VERSION 5.8 ;
BUSBITCHARS "[]" ;
DIVIDERCHAR "/" ;
UNITS
    DATABASE MICRONS 1000 ;
END UNITS

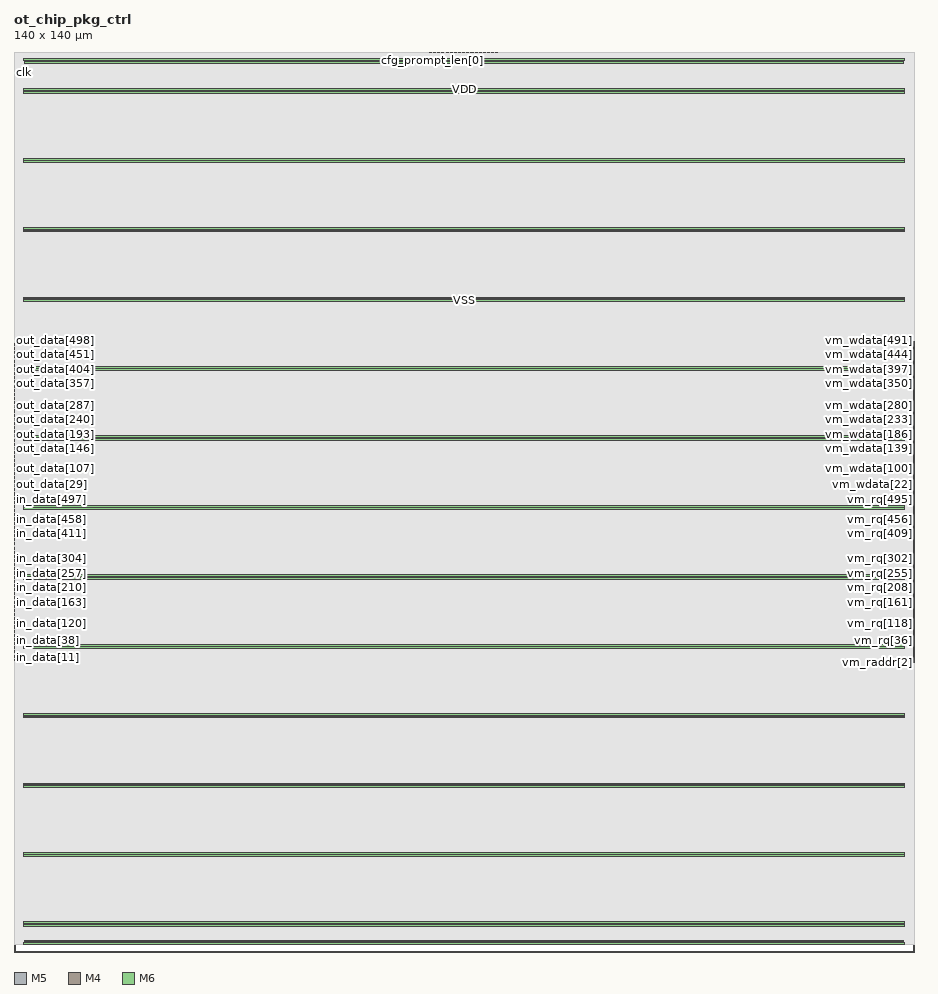
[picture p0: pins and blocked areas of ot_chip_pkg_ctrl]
MACRO ot_chip_pkg_ctrl
  FOREIGN ot_chip_pkg_ctrl 0 0 ;
  CLASS BLOCK ;
  SIZE 140 BY 140 ;
  PIN cfg_gen_len[0]
    DIRECTION INPUT ;
    USE SIGNAL ;
    PORT
      LAYER M5 ;
        RECT  64.272 139.916 64.296 140 ;
    END
  END cfg_gen_len[0]
  PIN cfg_gen_len[10]
    DIRECTION INPUT ;
    USE SIGNAL ;
    PORT
      LAYER M5 ;
        RECT  64.752 139.916 64.776 140 ;
    END
  END cfg_gen_len[10]
  PIN cfg_gen_len[11]
    DIRECTION INPUT ;
    USE SIGNAL ;
    PORT
      LAYER M5 ;
        RECT  64.8 139.916 64.824 140 ;
    END
  END cfg_gen_len[11]
  PIN cfg_gen_len[12]
    DIRECTION INPUT ;
    USE SIGNAL ;
    PORT
      LAYER M5 ;
        RECT  64.848 139.916 64.872 140 ;
    END
  END cfg_gen_len[12]
  PIN cfg_gen_len[13]
    DIRECTION INPUT ;
    USE SIGNAL ;
    PORT
      LAYER M5 ;
        RECT  64.896 139.916 64.92 140 ;
    END
  END cfg_gen_len[13]
  PIN cfg_gen_len[14]
    DIRECTION INPUT ;
    USE SIGNAL ;
    PORT
      LAYER M5 ;
        RECT  64.944 139.916 64.968 140 ;
    END
  END cfg_gen_len[14]
  PIN cfg_gen_len[15]
    DIRECTION INPUT ;
    USE SIGNAL ;
    PORT
      LAYER M5 ;
        RECT  64.992 139.916 65.016 140 ;
    END
  END cfg_gen_len[15]
  PIN cfg_gen_len[1]
    DIRECTION INPUT ;
    USE SIGNAL ;
    PORT
      LAYER M5 ;
        RECT  64.32 139.916 64.344 140 ;
    END
  END cfg_gen_len[1]
  PIN cfg_gen_len[2]
    DIRECTION INPUT ;
    USE SIGNAL ;
    PORT
      LAYER M5 ;
        RECT  64.368 139.916 64.392 140 ;
    END
  END cfg_gen_len[2]
  PIN cfg_gen_len[3]
    DIRECTION INPUT ;
    USE SIGNAL ;
    PORT
      LAYER M5 ;
        RECT  64.416 139.916 64.44 140 ;
    END
  END cfg_gen_len[3]
  PIN cfg_gen_len[4]
    DIRECTION INPUT ;
    USE SIGNAL ;
    PORT
      LAYER M5 ;
        RECT  64.464 139.916 64.488 140 ;
    END
  END cfg_gen_len[4]
  PIN cfg_gen_len[5]
    DIRECTION INPUT ;
    USE SIGNAL ;
    PORT
      LAYER M5 ;
        RECT  64.512 139.916 64.536 140 ;
    END
  END cfg_gen_len[5]
  PIN cfg_gen_len[6]
    DIRECTION INPUT ;
    USE SIGNAL ;
    PORT
      LAYER M5 ;
        RECT  64.56 139.916 64.584 140 ;
    END
  END cfg_gen_len[6]
  PIN cfg_gen_len[7]
    DIRECTION INPUT ;
    USE SIGNAL ;
    PORT
      LAYER M5 ;
        RECT  64.608 139.916 64.632 140 ;
    END
  END cfg_gen_len[7]
  PIN cfg_gen_len[8]
    DIRECTION INPUT ;
    USE SIGNAL ;
    PORT
      LAYER M5 ;
        RECT  64.656 139.916 64.68 140 ;
    END
  END cfg_gen_len[8]
  PIN cfg_gen_len[9]
    DIRECTION INPUT ;
    USE SIGNAL ;
    PORT
      LAYER M5 ;
        RECT  64.704 139.916 64.728 140 ;
    END
  END cfg_gen_len[9]
  PIN cfg_prompt_len[0]
    DIRECTION INPUT ;
    USE SIGNAL ;
    PORT
      LAYER M5 ;
        RECT  65.04 139.916 65.064 140 ;
    END
  END cfg_prompt_len[0]
  PIN cfg_prompt_len[10]
    DIRECTION INPUT ;
    USE SIGNAL ;
    PORT
      LAYER M5 ;
        RECT  65.52 139.916 65.544 140 ;
    END
  END cfg_prompt_len[10]
  PIN cfg_prompt_len[11]
    DIRECTION INPUT ;
    USE SIGNAL ;
    PORT
      LAYER M5 ;
        RECT  65.568 139.916 65.592 140 ;
    END
  END cfg_prompt_len[11]
  PIN cfg_prompt_len[12]
    DIRECTION INPUT ;
    USE SIGNAL ;
    PORT
      LAYER M5 ;
        RECT  65.616 139.916 65.64 140 ;
    END
  END cfg_prompt_len[12]
  PIN cfg_prompt_len[13]
    DIRECTION INPUT ;
    USE SIGNAL ;
    PORT
      LAYER M5 ;
        RECT  65.664 139.916 65.688 140 ;
    END
  END cfg_prompt_len[13]
  PIN cfg_prompt_len[14]
    DIRECTION INPUT ;
    USE SIGNAL ;
    PORT
      LAYER M5 ;
        RECT  65.712 139.916 65.736 140 ;
    END
  END cfg_prompt_len[14]
  PIN cfg_prompt_len[15]
    DIRECTION INPUT ;
    USE SIGNAL ;
    PORT
      LAYER M5 ;
        RECT  65.76 139.916 65.784 140 ;
    END
  END cfg_prompt_len[15]
  PIN cfg_prompt_len[1]
    DIRECTION INPUT ;
    USE SIGNAL ;
    PORT
      LAYER M5 ;
        RECT  65.088 139.916 65.112 140 ;
    END
  END cfg_prompt_len[1]
  PIN cfg_prompt_len[2]
    DIRECTION INPUT ;
    USE SIGNAL ;
    PORT
      LAYER M5 ;
        RECT  65.136 139.916 65.16 140 ;
    END
  END cfg_prompt_len[2]
  PIN cfg_prompt_len[3]
    DIRECTION INPUT ;
    USE SIGNAL ;
    PORT
      LAYER M5 ;
        RECT  65.184 139.916 65.208 140 ;
    END
  END cfg_prompt_len[3]
  PIN cfg_prompt_len[4]
    DIRECTION INPUT ;
    USE SIGNAL ;
    PORT
      LAYER M5 ;
        RECT  65.232 139.916 65.256 140 ;
    END
  END cfg_prompt_len[4]
  PIN cfg_prompt_len[5]
    DIRECTION INPUT ;
    USE SIGNAL ;
    PORT
      LAYER M5 ;
        RECT  65.28 139.916 65.304 140 ;
    END
  END cfg_prompt_len[5]
  PIN cfg_prompt_len[6]
    DIRECTION INPUT ;
    USE SIGNAL ;
    PORT
      LAYER M5 ;
        RECT  65.328 139.916 65.352 140 ;
    END
  END cfg_prompt_len[6]
  PIN cfg_prompt_len[7]
    DIRECTION INPUT ;
    USE SIGNAL ;
    PORT
      LAYER M5 ;
        RECT  65.376 139.916 65.4 140 ;
    END
  END cfg_prompt_len[7]
  PIN cfg_prompt_len[8]
    DIRECTION INPUT ;
    USE SIGNAL ;
    PORT
      LAYER M5 ;
        RECT  65.424 139.916 65.448 140 ;
    END
  END cfg_prompt_len[8]
  PIN cfg_prompt_len[9]
    DIRECTION INPUT ;
    USE SIGNAL ;
    PORT
      LAYER M5 ;
        RECT  65.472 139.916 65.496 140 ;
    END
  END cfg_prompt_len[9]
  PIN cfg_users[0]
    DIRECTION INPUT ;
    USE SIGNAL ;
    PORT
      LAYER M5 ;
        RECT  65.808 139.916 65.832 140 ;
    END
  END cfg_users[0]
  PIN cfg_users[1]
    DIRECTION INPUT ;
    USE SIGNAL ;
    PORT
      LAYER M5 ;
        RECT  65.856 139.916 65.88 140 ;
    END
  END cfg_users[1]
  PIN cfg_users[2]
    DIRECTION INPUT ;
    USE SIGNAL ;
    PORT
      LAYER M5 ;
        RECT  65.904 139.916 65.928 140 ;
    END
  END cfg_users[2]
  PIN cfg_users[3]
    DIRECTION INPUT ;
    USE SIGNAL ;
    PORT
      LAYER M5 ;
        RECT  65.952 139.916 65.976 140 ;
    END
  END cfg_users[3]
  PIN cfg_users[4]
    DIRECTION INPUT ;
    USE SIGNAL ;
    PORT
      LAYER M5 ;
        RECT  66 139.916 66.024 140 ;
    END
  END cfg_users[4]
  PIN cfg_users[5]
    DIRECTION INPUT ;
    USE SIGNAL ;
    PORT
      LAYER M5 ;
        RECT  66.048 139.916 66.072 140 ;
    END
  END cfg_users[5]
  PIN cfg_users[6]
    DIRECTION INPUT ;
    USE SIGNAL ;
    PORT
      LAYER M5 ;
        RECT  66.096 139.916 66.12 140 ;
    END
  END cfg_users[6]
  PIN cfg_users[7]
    DIRECTION INPUT ;
    USE SIGNAL ;
    PORT
      LAYER M5 ;
        RECT  66.144 139.916 66.168 140 ;
    END
  END cfg_users[7]
  PIN clk
    DIRECTION INPUT ;
    USE SIGNAL ;
    PORT
      LAYER M4 ;
        RECT  0 136.848 0.084 136.872 ;
    END
  END clk
  PIN core_busy
    DIRECTION OUTPUT ;
    USE SIGNAL ;
    PORT
      LAYER M5 ;
        RECT  66.192 139.916 66.216 140 ;
    END
  END core_busy
  PIN core_done
    DIRECTION INPUT ;
    USE SIGNAL ;
    PORT
      LAYER M5 ;
        RECT  66.24 139.916 66.264 140 ;
    END
  END core_done
  PIN core_next_token[0]
    DIRECTION INPUT ;
    USE SIGNAL ;
    PORT
      LAYER M5 ;
        RECT  66.288 139.916 66.312 140 ;
    END
  END core_next_token[0]
  PIN core_next_token[10]
    DIRECTION INPUT ;
    USE SIGNAL ;
    PORT
      LAYER M5 ;
        RECT  66.768 139.916 66.792 140 ;
    END
  END core_next_token[10]
  PIN core_next_token[11]
    DIRECTION INPUT ;
    USE SIGNAL ;
    PORT
      LAYER M5 ;
        RECT  66.816 139.916 66.84 140 ;
    END
  END core_next_token[11]
  PIN core_next_token[12]
    DIRECTION INPUT ;
    USE SIGNAL ;
    PORT
      LAYER M5 ;
        RECT  66.864 139.916 66.888 140 ;
    END
  END core_next_token[12]
  PIN core_next_token[13]
    DIRECTION INPUT ;
    USE SIGNAL ;
    PORT
      LAYER M5 ;
        RECT  66.912 139.916 66.936 140 ;
    END
  END core_next_token[13]
  PIN core_next_token[14]
    DIRECTION INPUT ;
    USE SIGNAL ;
    PORT
      LAYER M5 ;
        RECT  66.96 139.916 66.984 140 ;
    END
  END core_next_token[14]
  PIN core_next_token[15]
    DIRECTION INPUT ;
    USE SIGNAL ;
    PORT
      LAYER M5 ;
        RECT  67.008 139.916 67.032 140 ;
    END
  END core_next_token[15]
  PIN core_next_token[1]
    DIRECTION INPUT ;
    USE SIGNAL ;
    PORT
      LAYER M5 ;
        RECT  66.336 139.916 66.36 140 ;
    END
  END core_next_token[1]
  PIN core_next_token[2]
    DIRECTION INPUT ;
    USE SIGNAL ;
    PORT
      LAYER M5 ;
        RECT  66.384 139.916 66.408 140 ;
    END
  END core_next_token[2]
  PIN core_next_token[3]
    DIRECTION INPUT ;
    USE SIGNAL ;
    PORT
      LAYER M5 ;
        RECT  66.432 139.916 66.456 140 ;
    END
  END core_next_token[3]
  PIN core_next_token[4]
    DIRECTION INPUT ;
    USE SIGNAL ;
    PORT
      LAYER M5 ;
        RECT  66.48 139.916 66.504 140 ;
    END
  END core_next_token[4]
  PIN core_next_token[5]
    DIRECTION INPUT ;
    USE SIGNAL ;
    PORT
      LAYER M5 ;
        RECT  66.528 139.916 66.552 140 ;
    END
  END core_next_token[5]
  PIN core_next_token[6]
    DIRECTION INPUT ;
    USE SIGNAL ;
    PORT
      LAYER M5 ;
        RECT  66.576 139.916 66.6 140 ;
    END
  END core_next_token[6]
  PIN core_next_token[7]
    DIRECTION INPUT ;
    USE SIGNAL ;
    PORT
      LAYER M5 ;
        RECT  66.624 139.916 66.648 140 ;
    END
  END core_next_token[7]
  PIN core_next_token[8]
    DIRECTION INPUT ;
    USE SIGNAL ;
    PORT
      LAYER M5 ;
        RECT  66.672 139.916 66.696 140 ;
    END
  END core_next_token[8]
  PIN core_next_token[9]
    DIRECTION INPUT ;
    USE SIGNAL ;
    PORT
      LAYER M5 ;
        RECT  66.72 139.916 66.744 140 ;
    END
  END core_next_token[9]
  PIN core_next_val[0]
    DIRECTION INPUT ;
    USE SIGNAL ;
    PORT
      LAYER M5 ;
        RECT  67.056 139.916 67.08 140 ;
    END
  END core_next_val[0]
  PIN core_next_val[10]
    DIRECTION INPUT ;
    USE SIGNAL ;
    PORT
      LAYER M5 ;
        RECT  67.536 139.916 67.56 140 ;
    END
  END core_next_val[10]
  PIN core_next_val[11]
    DIRECTION INPUT ;
    USE SIGNAL ;
    PORT
      LAYER M5 ;
        RECT  67.584 139.916 67.608 140 ;
    END
  END core_next_val[11]
  PIN core_next_val[12]
    DIRECTION INPUT ;
    USE SIGNAL ;
    PORT
      LAYER M5 ;
        RECT  67.632 139.916 67.656 140 ;
    END
  END core_next_val[12]
  PIN core_next_val[13]
    DIRECTION INPUT ;
    USE SIGNAL ;
    PORT
      LAYER M5 ;
        RECT  67.68 139.916 67.704 140 ;
    END
  END core_next_val[13]
  PIN core_next_val[14]
    DIRECTION INPUT ;
    USE SIGNAL ;
    PORT
      LAYER M5 ;
        RECT  67.728 139.916 67.752 140 ;
    END
  END core_next_val[14]
  PIN core_next_val[15]
    DIRECTION INPUT ;
    USE SIGNAL ;
    PORT
      LAYER M5 ;
        RECT  67.776 139.916 67.8 140 ;
    END
  END core_next_val[15]
  PIN core_next_val[16]
    DIRECTION INPUT ;
    USE SIGNAL ;
    PORT
      LAYER M5 ;
        RECT  67.824 139.916 67.848 140 ;
    END
  END core_next_val[16]
  PIN core_next_val[17]
    DIRECTION INPUT ;
    USE SIGNAL ;
    PORT
      LAYER M5 ;
        RECT  67.872 139.916 67.896 140 ;
    END
  END core_next_val[17]
  PIN core_next_val[18]
    DIRECTION INPUT ;
    USE SIGNAL ;
    PORT
      LAYER M5 ;
        RECT  67.92 139.916 67.944 140 ;
    END
  END core_next_val[18]
  PIN core_next_val[19]
    DIRECTION INPUT ;
    USE SIGNAL ;
    PORT
      LAYER M5 ;
        RECT  67.968 139.916 67.992 140 ;
    END
  END core_next_val[19]
  PIN core_next_val[1]
    DIRECTION INPUT ;
    USE SIGNAL ;
    PORT
      LAYER M5 ;
        RECT  67.104 139.916 67.128 140 ;
    END
  END core_next_val[1]
  PIN core_next_val[20]
    DIRECTION INPUT ;
    USE SIGNAL ;
    PORT
      LAYER M5 ;
        RECT  68.016 139.916 68.04 140 ;
    END
  END core_next_val[20]
  PIN core_next_val[21]
    DIRECTION INPUT ;
    USE SIGNAL ;
    PORT
      LAYER M5 ;
        RECT  68.064 139.916 68.088 140 ;
    END
  END core_next_val[21]
  PIN core_next_val[22]
    DIRECTION INPUT ;
    USE SIGNAL ;
    PORT
      LAYER M5 ;
        RECT  68.112 139.916 68.136 140 ;
    END
  END core_next_val[22]
  PIN core_next_val[23]
    DIRECTION INPUT ;
    USE SIGNAL ;
    PORT
      LAYER M5 ;
        RECT  68.16 139.916 68.184 140 ;
    END
  END core_next_val[23]
  PIN core_next_val[24]
    DIRECTION INPUT ;
    USE SIGNAL ;
    PORT
      LAYER M5 ;
        RECT  68.208 139.916 68.232 140 ;
    END
  END core_next_val[24]
  PIN core_next_val[25]
    DIRECTION INPUT ;
    USE SIGNAL ;
    PORT
      LAYER M5 ;
        RECT  68.256 139.916 68.28 140 ;
    END
  END core_next_val[25]
  PIN core_next_val[26]
    DIRECTION INPUT ;
    USE SIGNAL ;
    PORT
      LAYER M5 ;
        RECT  68.304 139.916 68.328 140 ;
    END
  END core_next_val[26]
  PIN core_next_val[27]
    DIRECTION INPUT ;
    USE SIGNAL ;
    PORT
      LAYER M5 ;
        RECT  68.352 139.916 68.376 140 ;
    END
  END core_next_val[27]
  PIN core_next_val[28]
    DIRECTION INPUT ;
    USE SIGNAL ;
    PORT
      LAYER M5 ;
        RECT  68.4 139.916 68.424 140 ;
    END
  END core_next_val[28]
  PIN core_next_val[29]
    DIRECTION INPUT ;
    USE SIGNAL ;
    PORT
      LAYER M5 ;
        RECT  68.448 139.916 68.472 140 ;
    END
  END core_next_val[29]
  PIN core_next_val[2]
    DIRECTION INPUT ;
    USE SIGNAL ;
    PORT
      LAYER M5 ;
        RECT  67.152 139.916 67.176 140 ;
    END
  END core_next_val[2]
  PIN core_next_val[30]
    DIRECTION INPUT ;
    USE SIGNAL ;
    PORT
      LAYER M5 ;
        RECT  68.496 139.916 68.52 140 ;
    END
  END core_next_val[30]
  PIN core_next_val[31]
    DIRECTION INPUT ;
    USE SIGNAL ;
    PORT
      LAYER M5 ;
        RECT  68.544 139.916 68.568 140 ;
    END
  END core_next_val[31]
  PIN core_next_val[3]
    DIRECTION INPUT ;
    USE SIGNAL ;
    PORT
      LAYER M5 ;
        RECT  67.2 139.916 67.224 140 ;
    END
  END core_next_val[3]
  PIN core_next_val[4]
    DIRECTION INPUT ;
    USE SIGNAL ;
    PORT
      LAYER M5 ;
        RECT  67.248 139.916 67.272 140 ;
    END
  END core_next_val[4]
  PIN core_next_val[5]
    DIRECTION INPUT ;
    USE SIGNAL ;
    PORT
      LAYER M5 ;
        RECT  67.296 139.916 67.32 140 ;
    END
  END core_next_val[5]
  PIN core_next_val[6]
    DIRECTION INPUT ;
    USE SIGNAL ;
    PORT
      LAYER M5 ;
        RECT  67.344 139.916 67.368 140 ;
    END
  END core_next_val[6]
  PIN core_next_val[7]
    DIRECTION INPUT ;
    USE SIGNAL ;
    PORT
      LAYER M5 ;
        RECT  67.392 139.916 67.416 140 ;
    END
  END core_next_val[7]
  PIN core_next_val[8]
    DIRECTION INPUT ;
    USE SIGNAL ;
    PORT
      LAYER M5 ;
        RECT  67.44 139.916 67.464 140 ;
    END
  END core_next_val[8]
  PIN core_next_val[9]
    DIRECTION INPUT ;
    USE SIGNAL ;
    PORT
      LAYER M5 ;
        RECT  67.488 139.916 67.512 140 ;
    END
  END core_next_val[9]
  PIN core_pos[0]
    DIRECTION OUTPUT ;
    USE SIGNAL ;
    PORT
      LAYER M5 ;
        RECT  68.592 139.916 68.616 140 ;
    END
  END core_pos[0]
  PIN core_pos[10]
    DIRECTION OUTPUT ;
    USE SIGNAL ;
    PORT
      LAYER M5 ;
        RECT  69.072 139.916 69.096 140 ;
    END
  END core_pos[10]
  PIN core_pos[11]
    DIRECTION OUTPUT ;
    USE SIGNAL ;
    PORT
      LAYER M5 ;
        RECT  69.12 139.916 69.144 140 ;
    END
  END core_pos[11]
  PIN core_pos[12]
    DIRECTION OUTPUT ;
    USE SIGNAL ;
    PORT
      LAYER M5 ;
        RECT  69.168 139.916 69.192 140 ;
    END
  END core_pos[12]
  PIN core_pos[13]
    DIRECTION OUTPUT ;
    USE SIGNAL ;
    PORT
      LAYER M5 ;
        RECT  69.216 139.916 69.24 140 ;
    END
  END core_pos[13]
  PIN core_pos[14]
    DIRECTION OUTPUT ;
    USE SIGNAL ;
    PORT
      LAYER M5 ;
        RECT  69.264 139.916 69.288 140 ;
    END
  END core_pos[14]
  PIN core_pos[15]
    DIRECTION OUTPUT ;
    USE SIGNAL ;
    PORT
      LAYER M5 ;
        RECT  69.312 139.916 69.336 140 ;
    END
  END core_pos[15]
  PIN core_pos[1]
    DIRECTION OUTPUT ;
    USE SIGNAL ;
    PORT
      LAYER M5 ;
        RECT  68.64 139.916 68.664 140 ;
    END
  END core_pos[1]
  PIN core_pos[2]
    DIRECTION OUTPUT ;
    USE SIGNAL ;
    PORT
      LAYER M5 ;
        RECT  68.688 139.916 68.712 140 ;
    END
  END core_pos[2]
  PIN core_pos[3]
    DIRECTION OUTPUT ;
    USE SIGNAL ;
    PORT
      LAYER M5 ;
        RECT  68.736 139.916 68.76 140 ;
    END
  END core_pos[3]
  PIN core_pos[4]
    DIRECTION OUTPUT ;
    USE SIGNAL ;
    PORT
      LAYER M5 ;
        RECT  68.784 139.916 68.808 140 ;
    END
  END core_pos[4]
  PIN core_pos[5]
    DIRECTION OUTPUT ;
    USE SIGNAL ;
    PORT
      LAYER M5 ;
        RECT  68.832 139.916 68.856 140 ;
    END
  END core_pos[5]
  PIN core_pos[6]
    DIRECTION OUTPUT ;
    USE SIGNAL ;
    PORT
      LAYER M5 ;
        RECT  68.88 139.916 68.904 140 ;
    END
  END core_pos[6]
  PIN core_pos[7]
    DIRECTION OUTPUT ;
    USE SIGNAL ;
    PORT
      LAYER M5 ;
        RECT  68.928 139.916 68.952 140 ;
    END
  END core_pos[7]
  PIN core_pos[8]
    DIRECTION OUTPUT ;
    USE SIGNAL ;
    PORT
      LAYER M5 ;
        RECT  68.976 139.916 69 140 ;
    END
  END core_pos[8]
  PIN core_pos[9]
    DIRECTION OUTPUT ;
    USE SIGNAL ;
    PORT
      LAYER M5 ;
        RECT  69.024 139.916 69.048 140 ;
    END
  END core_pos[9]
  PIN core_start
    DIRECTION OUTPUT ;
    USE SIGNAL ;
    PORT
      LAYER M5 ;
        RECT  69.36 139.916 69.384 140 ;
    END
  END core_start
  PIN core_token[0]
    DIRECTION OUTPUT ;
    USE SIGNAL ;
    PORT
      LAYER M5 ;
        RECT  69.408 139.916 69.432 140 ;
    END
  END core_token[0]
  PIN core_token[10]
    DIRECTION OUTPUT ;
    USE SIGNAL ;
    PORT
      LAYER M5 ;
        RECT  69.888 139.916 69.912 140 ;
    END
  END core_token[10]
  PIN core_token[11]
    DIRECTION OUTPUT ;
    USE SIGNAL ;
    PORT
      LAYER M5 ;
        RECT  69.936 139.916 69.96 140 ;
    END
  END core_token[11]
  PIN core_token[12]
    DIRECTION OUTPUT ;
    USE SIGNAL ;
    PORT
      LAYER M5 ;
        RECT  69.984 139.916 70.008 140 ;
    END
  END core_token[12]
  PIN core_token[13]
    DIRECTION OUTPUT ;
    USE SIGNAL ;
    PORT
      LAYER M5 ;
        RECT  70.032 139.916 70.056 140 ;
    END
  END core_token[13]
  PIN core_token[14]
    DIRECTION OUTPUT ;
    USE SIGNAL ;
    PORT
      LAYER M5 ;
        RECT  70.08 139.916 70.104 140 ;
    END
  END core_token[14]
  PIN core_token[15]
    DIRECTION OUTPUT ;
    USE SIGNAL ;
    PORT
      LAYER M5 ;
        RECT  70.128 139.916 70.152 140 ;
    END
  END core_token[15]
  PIN core_token[1]
    DIRECTION OUTPUT ;
    USE SIGNAL ;
    PORT
      LAYER M5 ;
        RECT  69.456 139.916 69.48 140 ;
    END
  END core_token[1]
  PIN core_token[2]
    DIRECTION OUTPUT ;
    USE SIGNAL ;
    PORT
      LAYER M5 ;
        RECT  69.504 139.916 69.528 140 ;
    END
  END core_token[2]
  PIN core_token[3]
    DIRECTION OUTPUT ;
    USE SIGNAL ;
    PORT
      LAYER M5 ;
        RECT  69.552 139.916 69.576 140 ;
    END
  END core_token[3]
  PIN core_token[4]
    DIRECTION OUTPUT ;
    USE SIGNAL ;
    PORT
      LAYER M5 ;
        RECT  69.6 139.916 69.624 140 ;
    END
  END core_token[4]
  PIN core_token[5]
    DIRECTION OUTPUT ;
    USE SIGNAL ;
    PORT
      LAYER M5 ;
        RECT  69.648 139.916 69.672 140 ;
    END
  END core_token[5]
  PIN core_token[6]
    DIRECTION OUTPUT ;
    USE SIGNAL ;
    PORT
      LAYER M5 ;
        RECT  69.696 139.916 69.72 140 ;
    END
  END core_token[6]
  PIN core_token[7]
    DIRECTION OUTPUT ;
    USE SIGNAL ;
    PORT
      LAYER M5 ;
        RECT  69.744 139.916 69.768 140 ;
    END
  END core_token[7]
  PIN core_token[8]
    DIRECTION OUTPUT ;
    USE SIGNAL ;
    PORT
      LAYER M5 ;
        RECT  69.792 139.916 69.816 140 ;
    END
  END core_token[8]
  PIN core_token[9]
    DIRECTION OUTPUT ;
    USE SIGNAL ;
    PORT
      LAYER M5 ;
        RECT  69.84 139.916 69.864 140 ;
    END
  END core_token[9]
  PIN in_data[0]
    DIRECTION INPUT ;
    USE SIGNAL ;
    PORT
      LAYER M4 ;
        RECT  0 45.312 0.084 45.336 ;
    END
  END in_data[0]
  PIN in_data[100]
    DIRECTION INPUT ;
    USE SIGNAL ;
    PORT
      LAYER M4 ;
        RECT  0 50.112 0.084 50.136 ;
    END
  END in_data[100]
  PIN in_data[101]
    DIRECTION INPUT ;
    USE SIGNAL ;
    PORT
      LAYER M4 ;
        RECT  0 50.16 0.084 50.184 ;
    END
  END in_data[101]
  PIN in_data[102]
    DIRECTION INPUT ;
    USE SIGNAL ;
    PORT
      LAYER M4 ;
        RECT  0 50.208 0.084 50.232 ;
    END
  END in_data[102]
  PIN in_data[103]
    DIRECTION INPUT ;
    USE SIGNAL ;
    PORT
      LAYER M4 ;
        RECT  0 50.256 0.084 50.28 ;
    END
  END in_data[103]
  PIN in_data[104]
    DIRECTION INPUT ;
    USE SIGNAL ;
    PORT
      LAYER M4 ;
        RECT  0 50.304 0.084 50.328 ;
    END
  END in_data[104]
  PIN in_data[105]
    DIRECTION INPUT ;
    USE SIGNAL ;
    PORT
      LAYER M4 ;
        RECT  0 50.352 0.084 50.376 ;
    END
  END in_data[105]
  PIN in_data[106]
    DIRECTION INPUT ;
    USE SIGNAL ;
    PORT
      LAYER M4 ;
        RECT  0 50.4 0.084 50.424 ;
    END
  END in_data[106]
  PIN in_data[107]
    DIRECTION INPUT ;
    USE SIGNAL ;
    PORT
      LAYER M4 ;
        RECT  0 50.448 0.084 50.472 ;
    END
  END in_data[107]
  PIN in_data[108]
    DIRECTION INPUT ;
    USE SIGNAL ;
    PORT
      LAYER M4 ;
        RECT  0 50.496 0.084 50.52 ;
    END
  END in_data[108]
  PIN in_data[109]
    DIRECTION INPUT ;
    USE SIGNAL ;
    PORT
      LAYER M4 ;
        RECT  0 50.544 0.084 50.568 ;
    END
  END in_data[109]
  PIN in_data[10]
    DIRECTION INPUT ;
    USE SIGNAL ;
    PORT
      LAYER M4 ;
        RECT  0 45.792 0.084 45.816 ;
    END
  END in_data[10]
  PIN in_data[110]
    DIRECTION INPUT ;
    USE SIGNAL ;
    PORT
      LAYER M4 ;
        RECT  0 50.592 0.084 50.616 ;
    END
  END in_data[110]
  PIN in_data[111]
    DIRECTION INPUT ;
    USE SIGNAL ;
    PORT
      LAYER M4 ;
        RECT  0 50.64 0.084 50.664 ;
    END
  END in_data[111]
  PIN in_data[112]
    DIRECTION INPUT ;
    USE SIGNAL ;
    PORT
      LAYER M4 ;
        RECT  0 50.688 0.084 50.712 ;
    END
  END in_data[112]
  PIN in_data[113]
    DIRECTION INPUT ;
    USE SIGNAL ;
    PORT
      LAYER M4 ;
        RECT  0 50.736 0.084 50.76 ;
    END
  END in_data[113]
  PIN in_data[114]
    DIRECTION INPUT ;
    USE SIGNAL ;
    PORT
      LAYER M4 ;
        RECT  0 50.784 0.084 50.808 ;
    END
  END in_data[114]
  PIN in_data[115]
    DIRECTION INPUT ;
    USE SIGNAL ;
    PORT
      LAYER M4 ;
        RECT  0 50.832 0.084 50.856 ;
    END
  END in_data[115]
  PIN in_data[116]
    DIRECTION INPUT ;
    USE SIGNAL ;
    PORT
      LAYER M4 ;
        RECT  0 50.88 0.084 50.904 ;
    END
  END in_data[116]
  PIN in_data[117]
    DIRECTION INPUT ;
    USE SIGNAL ;
    PORT
      LAYER M4 ;
        RECT  0 50.928 0.084 50.952 ;
    END
  END in_data[117]
  PIN in_data[118]
    DIRECTION INPUT ;
    USE SIGNAL ;
    PORT
      LAYER M4 ;
        RECT  0 50.976 0.084 51 ;
    END
  END in_data[118]
  PIN in_data[119]
    DIRECTION INPUT ;
    USE SIGNAL ;
    PORT
      LAYER M4 ;
        RECT  0 51.024 0.084 51.048 ;
    END
  END in_data[119]
  PIN in_data[11]
    DIRECTION INPUT ;
    USE SIGNAL ;
    PORT
      LAYER M4 ;
        RECT  0 45.84 0.084 45.864 ;
    END
  END in_data[11]
  PIN in_data[120]
    DIRECTION INPUT ;
    USE SIGNAL ;
    PORT
      LAYER M4 ;
        RECT  0 51.072 0.084 51.096 ;
    END
  END in_data[120]
  PIN in_data[121]
    DIRECTION INPUT ;
    USE SIGNAL ;
    PORT
      LAYER M4 ;
        RECT  0 51.12 0.084 51.144 ;
    END
  END in_data[121]
  PIN in_data[122]
    DIRECTION INPUT ;
    USE SIGNAL ;
    PORT
      LAYER M4 ;
        RECT  0 51.168 0.084 51.192 ;
    END
  END in_data[122]
  PIN in_data[123]
    DIRECTION INPUT ;
    USE SIGNAL ;
    PORT
      LAYER M4 ;
        RECT  0 51.216 0.084 51.24 ;
    END
  END in_data[123]
  PIN in_data[124]
    DIRECTION INPUT ;
    USE SIGNAL ;
    PORT
      LAYER M4 ;
        RECT  0 51.264 0.084 51.288 ;
    END
  END in_data[124]
  PIN in_data[125]
    DIRECTION INPUT ;
    USE SIGNAL ;
    PORT
      LAYER M4 ;
        RECT  0 51.312 0.084 51.336 ;
    END
  END in_data[125]
  PIN in_data[126]
    DIRECTION INPUT ;
    USE SIGNAL ;
    PORT
      LAYER M4 ;
        RECT  0 51.36 0.084 51.384 ;
    END
  END in_data[126]
  PIN in_data[127]
    DIRECTION INPUT ;
    USE SIGNAL ;
    PORT
      LAYER M4 ;
        RECT  0 51.408 0.084 51.432 ;
    END
  END in_data[127]
  PIN in_data[128]
    DIRECTION INPUT ;
    USE SIGNAL ;
    PORT
      LAYER M4 ;
        RECT  0 51.456 0.084 51.48 ;
    END
  END in_data[128]
  PIN in_data[129]
    DIRECTION INPUT ;
    USE SIGNAL ;
    PORT
      LAYER M4 ;
        RECT  0 51.504 0.084 51.528 ;
    END
  END in_data[129]
  PIN in_data[12]
    DIRECTION INPUT ;
    USE SIGNAL ;
    PORT
      LAYER M4 ;
        RECT  0 45.888 0.084 45.912 ;
    END
  END in_data[12]
  PIN in_data[130]
    DIRECTION INPUT ;
    USE SIGNAL ;
    PORT
      LAYER M4 ;
        RECT  0 51.552 0.084 51.576 ;
    END
  END in_data[130]
  PIN in_data[131]
    DIRECTION INPUT ;
    USE SIGNAL ;
    PORT
      LAYER M4 ;
        RECT  0 51.6 0.084 51.624 ;
    END
  END in_data[131]
  PIN in_data[132]
    DIRECTION INPUT ;
    USE SIGNAL ;
    PORT
      LAYER M4 ;
        RECT  0 51.648 0.084 51.672 ;
    END
  END in_data[132]
  PIN in_data[133]
    DIRECTION INPUT ;
    USE SIGNAL ;
    PORT
      LAYER M4 ;
        RECT  0 51.696 0.084 51.72 ;
    END
  END in_data[133]
  PIN in_data[134]
    DIRECTION INPUT ;
    USE SIGNAL ;
    PORT
      LAYER M4 ;
        RECT  0 51.744 0.084 51.768 ;
    END
  END in_data[134]
  PIN in_data[135]
    DIRECTION INPUT ;
    USE SIGNAL ;
    PORT
      LAYER M4 ;
        RECT  0 51.792 0.084 51.816 ;
    END
  END in_data[135]
  PIN in_data[136]
    DIRECTION INPUT ;
    USE SIGNAL ;
    PORT
      LAYER M4 ;
        RECT  0 51.84 0.084 51.864 ;
    END
  END in_data[136]
  PIN in_data[137]
    DIRECTION INPUT ;
    USE SIGNAL ;
    PORT
      LAYER M4 ;
        RECT  0 51.888 0.084 51.912 ;
    END
  END in_data[137]
  PIN in_data[138]
    DIRECTION INPUT ;
    USE SIGNAL ;
    PORT
      LAYER M4 ;
        RECT  0 51.936 0.084 51.96 ;
    END
  END in_data[138]
  PIN in_data[139]
    DIRECTION INPUT ;
    USE SIGNAL ;
    PORT
      LAYER M4 ;
        RECT  0 51.984 0.084 52.008 ;
    END
  END in_data[139]
  PIN in_data[13]
    DIRECTION INPUT ;
    USE SIGNAL ;
    PORT
      LAYER M4 ;
        RECT  0 45.936 0.084 45.96 ;
    END
  END in_data[13]
  PIN in_data[140]
    DIRECTION INPUT ;
    USE SIGNAL ;
    PORT
      LAYER M4 ;
        RECT  0 52.032 0.084 52.056 ;
    END
  END in_data[140]
  PIN in_data[141]
    DIRECTION INPUT ;
    USE SIGNAL ;
    PORT
      LAYER M4 ;
        RECT  0 52.08 0.084 52.104 ;
    END
  END in_data[141]
  PIN in_data[142]
    DIRECTION INPUT ;
    USE SIGNAL ;
    PORT
      LAYER M4 ;
        RECT  0 52.128 0.084 52.152 ;
    END
  END in_data[142]
  PIN in_data[143]
    DIRECTION INPUT ;
    USE SIGNAL ;
    PORT
      LAYER M4 ;
        RECT  0 52.176 0.084 52.2 ;
    END
  END in_data[143]
  PIN in_data[144]
    DIRECTION INPUT ;
    USE SIGNAL ;
    PORT
      LAYER M4 ;
        RECT  0 52.224 0.084 52.248 ;
    END
  END in_data[144]
  PIN in_data[145]
    DIRECTION INPUT ;
    USE SIGNAL ;
    PORT
      LAYER M4 ;
        RECT  0 52.272 0.084 52.296 ;
    END
  END in_data[145]
  PIN in_data[146]
    DIRECTION INPUT ;
    USE SIGNAL ;
    PORT
      LAYER M4 ;
        RECT  0 52.32 0.084 52.344 ;
    END
  END in_data[146]
  PIN in_data[147]
    DIRECTION INPUT ;
    USE SIGNAL ;
    PORT
      LAYER M4 ;
        RECT  0 52.368 0.084 52.392 ;
    END
  END in_data[147]
  PIN in_data[148]
    DIRECTION INPUT ;
    USE SIGNAL ;
    PORT
      LAYER M4 ;
        RECT  0 52.416 0.084 52.44 ;
    END
  END in_data[148]
  PIN in_data[149]
    DIRECTION INPUT ;
    USE SIGNAL ;
    PORT
      LAYER M4 ;
        RECT  0 52.464 0.084 52.488 ;
    END
  END in_data[149]
  PIN in_data[14]
    DIRECTION INPUT ;
    USE SIGNAL ;
    PORT
      LAYER M4 ;
        RECT  0 45.984 0.084 46.008 ;
    END
  END in_data[14]
  PIN in_data[150]
    DIRECTION INPUT ;
    USE SIGNAL ;
    PORT
      LAYER M4 ;
        RECT  0 52.512 0.084 52.536 ;
    END
  END in_data[150]
  PIN in_data[151]
    DIRECTION INPUT ;
    USE SIGNAL ;
    PORT
      LAYER M4 ;
        RECT  0 52.56 0.084 52.584 ;
    END
  END in_data[151]
  PIN in_data[152]
    DIRECTION INPUT ;
    USE SIGNAL ;
    PORT
      LAYER M4 ;
        RECT  0 52.608 0.084 52.632 ;
    END
  END in_data[152]
  PIN in_data[153]
    DIRECTION INPUT ;
    USE SIGNAL ;
    PORT
      LAYER M4 ;
        RECT  0 52.656 0.084 52.68 ;
    END
  END in_data[153]
  PIN in_data[154]
    DIRECTION INPUT ;
    USE SIGNAL ;
    PORT
      LAYER M4 ;
        RECT  0 52.704 0.084 52.728 ;
    END
  END in_data[154]
  PIN in_data[155]
    DIRECTION INPUT ;
    USE SIGNAL ;
    PORT
      LAYER M4 ;
        RECT  0 52.752 0.084 52.776 ;
    END
  END in_data[155]
  PIN in_data[156]
    DIRECTION INPUT ;
    USE SIGNAL ;
    PORT
      LAYER M4 ;
        RECT  0 52.8 0.084 52.824 ;
    END
  END in_data[156]
  PIN in_data[157]
    DIRECTION INPUT ;
    USE SIGNAL ;
    PORT
      LAYER M4 ;
        RECT  0 52.848 0.084 52.872 ;
    END
  END in_data[157]
  PIN in_data[158]
    DIRECTION INPUT ;
    USE SIGNAL ;
    PORT
      LAYER M4 ;
        RECT  0 52.896 0.084 52.92 ;
    END
  END in_data[158]
  PIN in_data[159]
    DIRECTION INPUT ;
    USE SIGNAL ;
    PORT
      LAYER M4 ;
        RECT  0 52.944 0.084 52.968 ;
    END
  END in_data[159]
  PIN in_data[15]
    DIRECTION INPUT ;
    USE SIGNAL ;
    PORT
      LAYER M4 ;
        RECT  0 46.032 0.084 46.056 ;
    END
  END in_data[15]
  PIN in_data[160]
    DIRECTION INPUT ;
    USE SIGNAL ;
    PORT
      LAYER M4 ;
        RECT  0 52.992 0.084 53.016 ;
    END
  END in_data[160]
  PIN in_data[161]
    DIRECTION INPUT ;
    USE SIGNAL ;
    PORT
      LAYER M4 ;
        RECT  0 53.04 0.084 53.064 ;
    END
  END in_data[161]
  PIN in_data[162]
    DIRECTION INPUT ;
    USE SIGNAL ;
    PORT
      LAYER M4 ;
        RECT  0 53.088 0.084 53.112 ;
    END
  END in_data[162]
  PIN in_data[163]
    DIRECTION INPUT ;
    USE SIGNAL ;
    PORT
      LAYER M4 ;
        RECT  0 53.136 0.084 53.16 ;
    END
  END in_data[163]
  PIN in_data[164]
    DIRECTION INPUT ;
    USE SIGNAL ;
    PORT
      LAYER M4 ;
        RECT  0 53.184 0.084 53.208 ;
    END
  END in_data[164]
  PIN in_data[165]
    DIRECTION INPUT ;
    USE SIGNAL ;
    PORT
      LAYER M4 ;
        RECT  0 53.232 0.084 53.256 ;
    END
  END in_data[165]
  PIN in_data[166]
    DIRECTION INPUT ;
    USE SIGNAL ;
    PORT
      LAYER M4 ;
        RECT  0 53.28 0.084 53.304 ;
    END
  END in_data[166]
  PIN in_data[167]
    DIRECTION INPUT ;
    USE SIGNAL ;
    PORT
      LAYER M4 ;
        RECT  0 53.328 0.084 53.352 ;
    END
  END in_data[167]
  PIN in_data[168]
    DIRECTION INPUT ;
    USE SIGNAL ;
    PORT
      LAYER M4 ;
        RECT  0 53.376 0.084 53.4 ;
    END
  END in_data[168]
  PIN in_data[169]
    DIRECTION INPUT ;
    USE SIGNAL ;
    PORT
      LAYER M4 ;
        RECT  0 53.424 0.084 53.448 ;
    END
  END in_data[169]
  PIN in_data[16]
    DIRECTION INPUT ;
    USE SIGNAL ;
    PORT
      LAYER M4 ;
        RECT  0 46.08 0.084 46.104 ;
    END
  END in_data[16]
  PIN in_data[170]
    DIRECTION INPUT ;
    USE SIGNAL ;
    PORT
      LAYER M4 ;
        RECT  0 53.472 0.084 53.496 ;
    END
  END in_data[170]
  PIN in_data[171]
    DIRECTION INPUT ;
    USE SIGNAL ;
    PORT
      LAYER M4 ;
        RECT  0 53.52 0.084 53.544 ;
    END
  END in_data[171]
  PIN in_data[172]
    DIRECTION INPUT ;
    USE SIGNAL ;
    PORT
      LAYER M4 ;
        RECT  0 53.568 0.084 53.592 ;
    END
  END in_data[172]
  PIN in_data[173]
    DIRECTION INPUT ;
    USE SIGNAL ;
    PORT
      LAYER M4 ;
        RECT  0 53.616 0.084 53.64 ;
    END
  END in_data[173]
  PIN in_data[174]
    DIRECTION INPUT ;
    USE SIGNAL ;
    PORT
      LAYER M4 ;
        RECT  0 53.664 0.084 53.688 ;
    END
  END in_data[174]
  PIN in_data[175]
    DIRECTION INPUT ;
    USE SIGNAL ;
    PORT
      LAYER M4 ;
        RECT  0 53.712 0.084 53.736 ;
    END
  END in_data[175]
  PIN in_data[176]
    DIRECTION INPUT ;
    USE SIGNAL ;
    PORT
      LAYER M4 ;
        RECT  0 53.76 0.084 53.784 ;
    END
  END in_data[176]
  PIN in_data[177]
    DIRECTION INPUT ;
    USE SIGNAL ;
    PORT
      LAYER M4 ;
        RECT  0 53.808 0.084 53.832 ;
    END
  END in_data[177]
  PIN in_data[178]
    DIRECTION INPUT ;
    USE SIGNAL ;
    PORT
      LAYER M4 ;
        RECT  0 53.856 0.084 53.88 ;
    END
  END in_data[178]
  PIN in_data[179]
    DIRECTION INPUT ;
    USE SIGNAL ;
    PORT
      LAYER M4 ;
        RECT  0 53.904 0.084 53.928 ;
    END
  END in_data[179]
  PIN in_data[17]
    DIRECTION INPUT ;
    USE SIGNAL ;
    PORT
      LAYER M4 ;
        RECT  0 46.128 0.084 46.152 ;
    END
  END in_data[17]
  PIN in_data[180]
    DIRECTION INPUT ;
    USE SIGNAL ;
    PORT
      LAYER M4 ;
        RECT  0 53.952 0.084 53.976 ;
    END
  END in_data[180]
  PIN in_data[181]
    DIRECTION INPUT ;
    USE SIGNAL ;
    PORT
      LAYER M4 ;
        RECT  0 54 0.084 54.024 ;
    END
  END in_data[181]
  PIN in_data[182]
    DIRECTION INPUT ;
    USE SIGNAL ;
    PORT
      LAYER M4 ;
        RECT  0 54.048 0.084 54.072 ;
    END
  END in_data[182]
  PIN in_data[183]
    DIRECTION INPUT ;
    USE SIGNAL ;
    PORT
      LAYER M4 ;
        RECT  0 54.096 0.084 54.12 ;
    END
  END in_data[183]
  PIN in_data[184]
    DIRECTION INPUT ;
    USE SIGNAL ;
    PORT
      LAYER M4 ;
        RECT  0 54.144 0.084 54.168 ;
    END
  END in_data[184]
  PIN in_data[185]
    DIRECTION INPUT ;
    USE SIGNAL ;
    PORT
      LAYER M4 ;
        RECT  0 54.192 0.084 54.216 ;
    END
  END in_data[185]
  PIN in_data[186]
    DIRECTION INPUT ;
    USE SIGNAL ;
    PORT
      LAYER M4 ;
        RECT  0 54.24 0.084 54.264 ;
    END
  END in_data[186]
  PIN in_data[187]
    DIRECTION INPUT ;
    USE SIGNAL ;
    PORT
      LAYER M4 ;
        RECT  0 54.288 0.084 54.312 ;
    END
  END in_data[187]
  PIN in_data[188]
    DIRECTION INPUT ;
    USE SIGNAL ;
    PORT
      LAYER M4 ;
        RECT  0 54.336 0.084 54.36 ;
    END
  END in_data[188]
  PIN in_data[189]
    DIRECTION INPUT ;
    USE SIGNAL ;
    PORT
      LAYER M4 ;
        RECT  0 54.384 0.084 54.408 ;
    END
  END in_data[189]
  PIN in_data[18]
    DIRECTION INPUT ;
    USE SIGNAL ;
    PORT
      LAYER M4 ;
        RECT  0 46.176 0.084 46.2 ;
    END
  END in_data[18]
  PIN in_data[190]
    DIRECTION INPUT ;
    USE SIGNAL ;
    PORT
      LAYER M4 ;
        RECT  0 54.432 0.084 54.456 ;
    END
  END in_data[190]
  PIN in_data[191]
    DIRECTION INPUT ;
    USE SIGNAL ;
    PORT
      LAYER M4 ;
        RECT  0 54.48 0.084 54.504 ;
    END
  END in_data[191]
  PIN in_data[192]
    DIRECTION INPUT ;
    USE SIGNAL ;
    PORT
      LAYER M4 ;
        RECT  0 54.528 0.084 54.552 ;
    END
  END in_data[192]
  PIN in_data[193]
    DIRECTION INPUT ;
    USE SIGNAL ;
    PORT
      LAYER M4 ;
        RECT  0 54.576 0.084 54.6 ;
    END
  END in_data[193]
  PIN in_data[194]
    DIRECTION INPUT ;
    USE SIGNAL ;
    PORT
      LAYER M4 ;
        RECT  0 54.624 0.084 54.648 ;
    END
  END in_data[194]
  PIN in_data[195]
    DIRECTION INPUT ;
    USE SIGNAL ;
    PORT
      LAYER M4 ;
        RECT  0 54.672 0.084 54.696 ;
    END
  END in_data[195]
  PIN in_data[196]
    DIRECTION INPUT ;
    USE SIGNAL ;
    PORT
      LAYER M4 ;
        RECT  0 54.72 0.084 54.744 ;
    END
  END in_data[196]
  PIN in_data[197]
    DIRECTION INPUT ;
    USE SIGNAL ;
    PORT
      LAYER M4 ;
        RECT  0 54.768 0.084 54.792 ;
    END
  END in_data[197]
  PIN in_data[198]
    DIRECTION INPUT ;
    USE SIGNAL ;
    PORT
      LAYER M4 ;
        RECT  0 54.816 0.084 54.84 ;
    END
  END in_data[198]
  PIN in_data[199]
    DIRECTION INPUT ;
    USE SIGNAL ;
    PORT
      LAYER M4 ;
        RECT  0 54.864 0.084 54.888 ;
    END
  END in_data[199]
  PIN in_data[19]
    DIRECTION INPUT ;
    USE SIGNAL ;
    PORT
      LAYER M4 ;
        RECT  0 46.224 0.084 46.248 ;
    END
  END in_data[19]
  PIN in_data[1]
    DIRECTION INPUT ;
    USE SIGNAL ;
    PORT
      LAYER M4 ;
        RECT  0 45.36 0.084 45.384 ;
    END
  END in_data[1]
  PIN in_data[200]
    DIRECTION INPUT ;
    USE SIGNAL ;
    PORT
      LAYER M4 ;
        RECT  0 54.912 0.084 54.936 ;
    END
  END in_data[200]
  PIN in_data[201]
    DIRECTION INPUT ;
    USE SIGNAL ;
    PORT
      LAYER M4 ;
        RECT  0 54.96 0.084 54.984 ;
    END
  END in_data[201]
  PIN in_data[202]
    DIRECTION INPUT ;
    USE SIGNAL ;
    PORT
      LAYER M4 ;
        RECT  0 55.008 0.084 55.032 ;
    END
  END in_data[202]
  PIN in_data[203]
    DIRECTION INPUT ;
    USE SIGNAL ;
    PORT
      LAYER M4 ;
        RECT  0 55.056 0.084 55.08 ;
    END
  END in_data[203]
  PIN in_data[204]
    DIRECTION INPUT ;
    USE SIGNAL ;
    PORT
      LAYER M4 ;
        RECT  0 55.104 0.084 55.128 ;
    END
  END in_data[204]
  PIN in_data[205]
    DIRECTION INPUT ;
    USE SIGNAL ;
    PORT
      LAYER M4 ;
        RECT  0 55.152 0.084 55.176 ;
    END
  END in_data[205]
  PIN in_data[206]
    DIRECTION INPUT ;
    USE SIGNAL ;
    PORT
      LAYER M4 ;
        RECT  0 55.2 0.084 55.224 ;
    END
  END in_data[206]
  PIN in_data[207]
    DIRECTION INPUT ;
    USE SIGNAL ;
    PORT
      LAYER M4 ;
        RECT  0 55.248 0.084 55.272 ;
    END
  END in_data[207]
  PIN in_data[208]
    DIRECTION INPUT ;
    USE SIGNAL ;
    PORT
      LAYER M4 ;
        RECT  0 55.296 0.084 55.32 ;
    END
  END in_data[208]
  PIN in_data[209]
    DIRECTION INPUT ;
    USE SIGNAL ;
    PORT
      LAYER M4 ;
        RECT  0 55.344 0.084 55.368 ;
    END
  END in_data[209]
  PIN in_data[20]
    DIRECTION INPUT ;
    USE SIGNAL ;
    PORT
      LAYER M4 ;
        RECT  0 46.272 0.084 46.296 ;
    END
  END in_data[20]
  PIN in_data[210]
    DIRECTION INPUT ;
    USE SIGNAL ;
    PORT
      LAYER M4 ;
        RECT  0 55.392 0.084 55.416 ;
    END
  END in_data[210]
  PIN in_data[211]
    DIRECTION INPUT ;
    USE SIGNAL ;
    PORT
      LAYER M4 ;
        RECT  0 55.44 0.084 55.464 ;
    END
  END in_data[211]
  PIN in_data[212]
    DIRECTION INPUT ;
    USE SIGNAL ;
    PORT
      LAYER M4 ;
        RECT  0 55.488 0.084 55.512 ;
    END
  END in_data[212]
  PIN in_data[213]
    DIRECTION INPUT ;
    USE SIGNAL ;
    PORT
      LAYER M4 ;
        RECT  0 55.536 0.084 55.56 ;
    END
  END in_data[213]
  PIN in_data[214]
    DIRECTION INPUT ;
    USE SIGNAL ;
    PORT
      LAYER M4 ;
        RECT  0 55.584 0.084 55.608 ;
    END
  END in_data[214]
  PIN in_data[215]
    DIRECTION INPUT ;
    USE SIGNAL ;
    PORT
      LAYER M4 ;
        RECT  0 55.632 0.084 55.656 ;
    END
  END in_data[215]
  PIN in_data[216]
    DIRECTION INPUT ;
    USE SIGNAL ;
    PORT
      LAYER M4 ;
        RECT  0 55.68 0.084 55.704 ;
    END
  END in_data[216]
  PIN in_data[217]
    DIRECTION INPUT ;
    USE SIGNAL ;
    PORT
      LAYER M4 ;
        RECT  0 55.728 0.084 55.752 ;
    END
  END in_data[217]
  PIN in_data[218]
    DIRECTION INPUT ;
    USE SIGNAL ;
    PORT
      LAYER M4 ;
        RECT  0 55.776 0.084 55.8 ;
    END
  END in_data[218]
  PIN in_data[219]
    DIRECTION INPUT ;
    USE SIGNAL ;
    PORT
      LAYER M4 ;
        RECT  0 55.824 0.084 55.848 ;
    END
  END in_data[219]
  PIN in_data[21]
    DIRECTION INPUT ;
    USE SIGNAL ;
    PORT
      LAYER M4 ;
        RECT  0 46.32 0.084 46.344 ;
    END
  END in_data[21]
  PIN in_data[220]
    DIRECTION INPUT ;
    USE SIGNAL ;
    PORT
      LAYER M4 ;
        RECT  0 55.872 0.084 55.896 ;
    END
  END in_data[220]
  PIN in_data[221]
    DIRECTION INPUT ;
    USE SIGNAL ;
    PORT
      LAYER M4 ;
        RECT  0 55.92 0.084 55.944 ;
    END
  END in_data[221]
  PIN in_data[222]
    DIRECTION INPUT ;
    USE SIGNAL ;
    PORT
      LAYER M4 ;
        RECT  0 55.968 0.084 55.992 ;
    END
  END in_data[222]
  PIN in_data[223]
    DIRECTION INPUT ;
    USE SIGNAL ;
    PORT
      LAYER M4 ;
        RECT  0 56.016 0.084 56.04 ;
    END
  END in_data[223]
  PIN in_data[224]
    DIRECTION INPUT ;
    USE SIGNAL ;
    PORT
      LAYER M4 ;
        RECT  0 56.064 0.084 56.088 ;
    END
  END in_data[224]
  PIN in_data[225]
    DIRECTION INPUT ;
    USE SIGNAL ;
    PORT
      LAYER M4 ;
        RECT  0 56.112 0.084 56.136 ;
    END
  END in_data[225]
  PIN in_data[226]
    DIRECTION INPUT ;
    USE SIGNAL ;
    PORT
      LAYER M4 ;
        RECT  0 56.16 0.084 56.184 ;
    END
  END in_data[226]
  PIN in_data[227]
    DIRECTION INPUT ;
    USE SIGNAL ;
    PORT
      LAYER M4 ;
        RECT  0 56.208 0.084 56.232 ;
    END
  END in_data[227]
  PIN in_data[228]
    DIRECTION INPUT ;
    USE SIGNAL ;
    PORT
      LAYER M4 ;
        RECT  0 56.256 0.084 56.28 ;
    END
  END in_data[228]
  PIN in_data[229]
    DIRECTION INPUT ;
    USE SIGNAL ;
    PORT
      LAYER M4 ;
        RECT  0 56.304 0.084 56.328 ;
    END
  END in_data[229]
  PIN in_data[22]
    DIRECTION INPUT ;
    USE SIGNAL ;
    PORT
      LAYER M4 ;
        RECT  0 46.368 0.084 46.392 ;
    END
  END in_data[22]
  PIN in_data[230]
    DIRECTION INPUT ;
    USE SIGNAL ;
    PORT
      LAYER M4 ;
        RECT  0 56.352 0.084 56.376 ;
    END
  END in_data[230]
  PIN in_data[231]
    DIRECTION INPUT ;
    USE SIGNAL ;
    PORT
      LAYER M4 ;
        RECT  0 56.4 0.084 56.424 ;
    END
  END in_data[231]
  PIN in_data[232]
    DIRECTION INPUT ;
    USE SIGNAL ;
    PORT
      LAYER M4 ;
        RECT  0 56.448 0.084 56.472 ;
    END
  END in_data[232]
  PIN in_data[233]
    DIRECTION INPUT ;
    USE SIGNAL ;
    PORT
      LAYER M4 ;
        RECT  0 56.496 0.084 56.52 ;
    END
  END in_data[233]
  PIN in_data[234]
    DIRECTION INPUT ;
    USE SIGNAL ;
    PORT
      LAYER M4 ;
        RECT  0 56.544 0.084 56.568 ;
    END
  END in_data[234]
  PIN in_data[235]
    DIRECTION INPUT ;
    USE SIGNAL ;
    PORT
      LAYER M4 ;
        RECT  0 56.592 0.084 56.616 ;
    END
  END in_data[235]
  PIN in_data[236]
    DIRECTION INPUT ;
    USE SIGNAL ;
    PORT
      LAYER M4 ;
        RECT  0 56.64 0.084 56.664 ;
    END
  END in_data[236]
  PIN in_data[237]
    DIRECTION INPUT ;
    USE SIGNAL ;
    PORT
      LAYER M4 ;
        RECT  0 56.688 0.084 56.712 ;
    END
  END in_data[237]
  PIN in_data[238]
    DIRECTION INPUT ;
    USE SIGNAL ;
    PORT
      LAYER M4 ;
        RECT  0 56.736 0.084 56.76 ;
    END
  END in_data[238]
  PIN in_data[239]
    DIRECTION INPUT ;
    USE SIGNAL ;
    PORT
      LAYER M4 ;
        RECT  0 56.784 0.084 56.808 ;
    END
  END in_data[239]
  PIN in_data[23]
    DIRECTION INPUT ;
    USE SIGNAL ;
    PORT
      LAYER M4 ;
        RECT  0 46.416 0.084 46.44 ;
    END
  END in_data[23]
  PIN in_data[240]
    DIRECTION INPUT ;
    USE SIGNAL ;
    PORT
      LAYER M4 ;
        RECT  0 56.832 0.084 56.856 ;
    END
  END in_data[240]
  PIN in_data[241]
    DIRECTION INPUT ;
    USE SIGNAL ;
    PORT
      LAYER M4 ;
        RECT  0 56.88 0.084 56.904 ;
    END
  END in_data[241]
  PIN in_data[242]
    DIRECTION INPUT ;
    USE SIGNAL ;
    PORT
      LAYER M4 ;
        RECT  0 56.928 0.084 56.952 ;
    END
  END in_data[242]
  PIN in_data[243]
    DIRECTION INPUT ;
    USE SIGNAL ;
    PORT
      LAYER M4 ;
        RECT  0 56.976 0.084 57 ;
    END
  END in_data[243]
  PIN in_data[244]
    DIRECTION INPUT ;
    USE SIGNAL ;
    PORT
      LAYER M4 ;
        RECT  0 57.024 0.084 57.048 ;
    END
  END in_data[244]
  PIN in_data[245]
    DIRECTION INPUT ;
    USE SIGNAL ;
    PORT
      LAYER M4 ;
        RECT  0 57.072 0.084 57.096 ;
    END
  END in_data[245]
  PIN in_data[246]
    DIRECTION INPUT ;
    USE SIGNAL ;
    PORT
      LAYER M4 ;
        RECT  0 57.12 0.084 57.144 ;
    END
  END in_data[246]
  PIN in_data[247]
    DIRECTION INPUT ;
    USE SIGNAL ;
    PORT
      LAYER M4 ;
        RECT  0 57.168 0.084 57.192 ;
    END
  END in_data[247]
  PIN in_data[248]
    DIRECTION INPUT ;
    USE SIGNAL ;
    PORT
      LAYER M4 ;
        RECT  0 57.216 0.084 57.24 ;
    END
  END in_data[248]
  PIN in_data[249]
    DIRECTION INPUT ;
    USE SIGNAL ;
    PORT
      LAYER M4 ;
        RECT  0 57.264 0.084 57.288 ;
    END
  END in_data[249]
  PIN in_data[24]
    DIRECTION INPUT ;
    USE SIGNAL ;
    PORT
      LAYER M4 ;
        RECT  0 46.464 0.084 46.488 ;
    END
  END in_data[24]
  PIN in_data[250]
    DIRECTION INPUT ;
    USE SIGNAL ;
    PORT
      LAYER M4 ;
        RECT  0 57.312 0.084 57.336 ;
    END
  END in_data[250]
  PIN in_data[251]
    DIRECTION INPUT ;
    USE SIGNAL ;
    PORT
      LAYER M4 ;
        RECT  0 57.36 0.084 57.384 ;
    END
  END in_data[251]
  PIN in_data[252]
    DIRECTION INPUT ;
    USE SIGNAL ;
    PORT
      LAYER M4 ;
        RECT  0 57.408 0.084 57.432 ;
    END
  END in_data[252]
  PIN in_data[253]
    DIRECTION INPUT ;
    USE SIGNAL ;
    PORT
      LAYER M4 ;
        RECT  0 57.456 0.084 57.48 ;
    END
  END in_data[253]
  PIN in_data[254]
    DIRECTION INPUT ;
    USE SIGNAL ;
    PORT
      LAYER M4 ;
        RECT  0 57.504 0.084 57.528 ;
    END
  END in_data[254]
  PIN in_data[255]
    DIRECTION INPUT ;
    USE SIGNAL ;
    PORT
      LAYER M4 ;
        RECT  0 57.552 0.084 57.576 ;
    END
  END in_data[255]
  PIN in_data[256]
    DIRECTION INPUT ;
    USE SIGNAL ;
    PORT
      LAYER M4 ;
        RECT  0 57.6 0.084 57.624 ;
    END
  END in_data[256]
  PIN in_data[257]
    DIRECTION INPUT ;
    USE SIGNAL ;
    PORT
      LAYER M4 ;
        RECT  0 57.648 0.084 57.672 ;
    END
  END in_data[257]
  PIN in_data[258]
    DIRECTION INPUT ;
    USE SIGNAL ;
    PORT
      LAYER M4 ;
        RECT  0 57.696 0.084 57.72 ;
    END
  END in_data[258]
  PIN in_data[259]
    DIRECTION INPUT ;
    USE SIGNAL ;
    PORT
      LAYER M4 ;
        RECT  0 57.744 0.084 57.768 ;
    END
  END in_data[259]
  PIN in_data[25]
    DIRECTION INPUT ;
    USE SIGNAL ;
    PORT
      LAYER M4 ;
        RECT  0 46.512 0.084 46.536 ;
    END
  END in_data[25]
  PIN in_data[260]
    DIRECTION INPUT ;
    USE SIGNAL ;
    PORT
      LAYER M4 ;
        RECT  0 57.792 0.084 57.816 ;
    END
  END in_data[260]
  PIN in_data[261]
    DIRECTION INPUT ;
    USE SIGNAL ;
    PORT
      LAYER M4 ;
        RECT  0 57.84 0.084 57.864 ;
    END
  END in_data[261]
  PIN in_data[262]
    DIRECTION INPUT ;
    USE SIGNAL ;
    PORT
      LAYER M4 ;
        RECT  0 57.888 0.084 57.912 ;
    END
  END in_data[262]
  PIN in_data[263]
    DIRECTION INPUT ;
    USE SIGNAL ;
    PORT
      LAYER M4 ;
        RECT  0 57.936 0.084 57.96 ;
    END
  END in_data[263]
  PIN in_data[264]
    DIRECTION INPUT ;
    USE SIGNAL ;
    PORT
      LAYER M4 ;
        RECT  0 57.984 0.084 58.008 ;
    END
  END in_data[264]
  PIN in_data[265]
    DIRECTION INPUT ;
    USE SIGNAL ;
    PORT
      LAYER M4 ;
        RECT  0 58.032 0.084 58.056 ;
    END
  END in_data[265]
  PIN in_data[266]
    DIRECTION INPUT ;
    USE SIGNAL ;
    PORT
      LAYER M4 ;
        RECT  0 58.08 0.084 58.104 ;
    END
  END in_data[266]
  PIN in_data[267]
    DIRECTION INPUT ;
    USE SIGNAL ;
    PORT
      LAYER M4 ;
        RECT  0 58.128 0.084 58.152 ;
    END
  END in_data[267]
  PIN in_data[268]
    DIRECTION INPUT ;
    USE SIGNAL ;
    PORT
      LAYER M4 ;
        RECT  0 58.176 0.084 58.2 ;
    END
  END in_data[268]
  PIN in_data[269]
    DIRECTION INPUT ;
    USE SIGNAL ;
    PORT
      LAYER M4 ;
        RECT  0 58.224 0.084 58.248 ;
    END
  END in_data[269]
  PIN in_data[26]
    DIRECTION INPUT ;
    USE SIGNAL ;
    PORT
      LAYER M4 ;
        RECT  0 46.56 0.084 46.584 ;
    END
  END in_data[26]
  PIN in_data[270]
    DIRECTION INPUT ;
    USE SIGNAL ;
    PORT
      LAYER M4 ;
        RECT  0 58.272 0.084 58.296 ;
    END
  END in_data[270]
  PIN in_data[271]
    DIRECTION INPUT ;
    USE SIGNAL ;
    PORT
      LAYER M4 ;
        RECT  0 58.32 0.084 58.344 ;
    END
  END in_data[271]
  PIN in_data[272]
    DIRECTION INPUT ;
    USE SIGNAL ;
    PORT
      LAYER M4 ;
        RECT  0 58.368 0.084 58.392 ;
    END
  END in_data[272]
  PIN in_data[273]
    DIRECTION INPUT ;
    USE SIGNAL ;
    PORT
      LAYER M4 ;
        RECT  0 58.416 0.084 58.44 ;
    END
  END in_data[273]
  PIN in_data[274]
    DIRECTION INPUT ;
    USE SIGNAL ;
    PORT
      LAYER M4 ;
        RECT  0 58.464 0.084 58.488 ;
    END
  END in_data[274]
  PIN in_data[275]
    DIRECTION INPUT ;
    USE SIGNAL ;
    PORT
      LAYER M4 ;
        RECT  0 58.512 0.084 58.536 ;
    END
  END in_data[275]
  PIN in_data[276]
    DIRECTION INPUT ;
    USE SIGNAL ;
    PORT
      LAYER M4 ;
        RECT  0 58.56 0.084 58.584 ;
    END
  END in_data[276]
  PIN in_data[277]
    DIRECTION INPUT ;
    USE SIGNAL ;
    PORT
      LAYER M4 ;
        RECT  0 58.608 0.084 58.632 ;
    END
  END in_data[277]
  PIN in_data[278]
    DIRECTION INPUT ;
    USE SIGNAL ;
    PORT
      LAYER M4 ;
        RECT  0 58.656 0.084 58.68 ;
    END
  END in_data[278]
  PIN in_data[279]
    DIRECTION INPUT ;
    USE SIGNAL ;
    PORT
      LAYER M4 ;
        RECT  0 58.704 0.084 58.728 ;
    END
  END in_data[279]
  PIN in_data[27]
    DIRECTION INPUT ;
    USE SIGNAL ;
    PORT
      LAYER M4 ;
        RECT  0 46.608 0.084 46.632 ;
    END
  END in_data[27]
  PIN in_data[280]
    DIRECTION INPUT ;
    USE SIGNAL ;
    PORT
      LAYER M4 ;
        RECT  0 58.752 0.084 58.776 ;
    END
  END in_data[280]
  PIN in_data[281]
    DIRECTION INPUT ;
    USE SIGNAL ;
    PORT
      LAYER M4 ;
        RECT  0 58.8 0.084 58.824 ;
    END
  END in_data[281]
  PIN in_data[282]
    DIRECTION INPUT ;
    USE SIGNAL ;
    PORT
      LAYER M4 ;
        RECT  0 58.848 0.084 58.872 ;
    END
  END in_data[282]
  PIN in_data[283]
    DIRECTION INPUT ;
    USE SIGNAL ;
    PORT
      LAYER M4 ;
        RECT  0 58.896 0.084 58.92 ;
    END
  END in_data[283]
  PIN in_data[284]
    DIRECTION INPUT ;
    USE SIGNAL ;
    PORT
      LAYER M4 ;
        RECT  0 58.944 0.084 58.968 ;
    END
  END in_data[284]
  PIN in_data[285]
    DIRECTION INPUT ;
    USE SIGNAL ;
    PORT
      LAYER M4 ;
        RECT  0 58.992 0.084 59.016 ;
    END
  END in_data[285]
  PIN in_data[286]
    DIRECTION INPUT ;
    USE SIGNAL ;
    PORT
      LAYER M4 ;
        RECT  0 59.04 0.084 59.064 ;
    END
  END in_data[286]
  PIN in_data[287]
    DIRECTION INPUT ;
    USE SIGNAL ;
    PORT
      LAYER M4 ;
        RECT  0 59.088 0.084 59.112 ;
    END
  END in_data[287]
  PIN in_data[288]
    DIRECTION INPUT ;
    USE SIGNAL ;
    PORT
      LAYER M4 ;
        RECT  0 59.136 0.084 59.16 ;
    END
  END in_data[288]
  PIN in_data[289]
    DIRECTION INPUT ;
    USE SIGNAL ;
    PORT
      LAYER M4 ;
        RECT  0 59.184 0.084 59.208 ;
    END
  END in_data[289]
  PIN in_data[28]
    DIRECTION INPUT ;
    USE SIGNAL ;
    PORT
      LAYER M4 ;
        RECT  0 46.656 0.084 46.68 ;
    END
  END in_data[28]
  PIN in_data[290]
    DIRECTION INPUT ;
    USE SIGNAL ;
    PORT
      LAYER M4 ;
        RECT  0 59.232 0.084 59.256 ;
    END
  END in_data[290]
  PIN in_data[291]
    DIRECTION INPUT ;
    USE SIGNAL ;
    PORT
      LAYER M4 ;
        RECT  0 59.28 0.084 59.304 ;
    END
  END in_data[291]
  PIN in_data[292]
    DIRECTION INPUT ;
    USE SIGNAL ;
    PORT
      LAYER M4 ;
        RECT  0 59.328 0.084 59.352 ;
    END
  END in_data[292]
  PIN in_data[293]
    DIRECTION INPUT ;
    USE SIGNAL ;
    PORT
      LAYER M4 ;
        RECT  0 59.376 0.084 59.4 ;
    END
  END in_data[293]
  PIN in_data[294]
    DIRECTION INPUT ;
    USE SIGNAL ;
    PORT
      LAYER M4 ;
        RECT  0 59.424 0.084 59.448 ;
    END
  END in_data[294]
  PIN in_data[295]
    DIRECTION INPUT ;
    USE SIGNAL ;
    PORT
      LAYER M4 ;
        RECT  0 59.472 0.084 59.496 ;
    END
  END in_data[295]
  PIN in_data[296]
    DIRECTION INPUT ;
    USE SIGNAL ;
    PORT
      LAYER M4 ;
        RECT  0 59.52 0.084 59.544 ;
    END
  END in_data[296]
  PIN in_data[297]
    DIRECTION INPUT ;
    USE SIGNAL ;
    PORT
      LAYER M4 ;
        RECT  0 59.568 0.084 59.592 ;
    END
  END in_data[297]
  PIN in_data[298]
    DIRECTION INPUT ;
    USE SIGNAL ;
    PORT
      LAYER M4 ;
        RECT  0 59.616 0.084 59.64 ;
    END
  END in_data[298]
  PIN in_data[299]
    DIRECTION INPUT ;
    USE SIGNAL ;
    PORT
      LAYER M4 ;
        RECT  0 59.664 0.084 59.688 ;
    END
  END in_data[299]
  PIN in_data[29]
    DIRECTION INPUT ;
    USE SIGNAL ;
    PORT
      LAYER M4 ;
        RECT  0 46.704 0.084 46.728 ;
    END
  END in_data[29]
  PIN in_data[2]
    DIRECTION INPUT ;
    USE SIGNAL ;
    PORT
      LAYER M4 ;
        RECT  0 45.408 0.084 45.432 ;
    END
  END in_data[2]
  PIN in_data[300]
    DIRECTION INPUT ;
    USE SIGNAL ;
    PORT
      LAYER M4 ;
        RECT  0 59.712 0.084 59.736 ;
    END
  END in_data[300]
  PIN in_data[301]
    DIRECTION INPUT ;
    USE SIGNAL ;
    PORT
      LAYER M4 ;
        RECT  0 59.76 0.084 59.784 ;
    END
  END in_data[301]
  PIN in_data[302]
    DIRECTION INPUT ;
    USE SIGNAL ;
    PORT
      LAYER M4 ;
        RECT  0 59.808 0.084 59.832 ;
    END
  END in_data[302]
  PIN in_data[303]
    DIRECTION INPUT ;
    USE SIGNAL ;
    PORT
      LAYER M4 ;
        RECT  0 59.856 0.084 59.88 ;
    END
  END in_data[303]
  PIN in_data[304]
    DIRECTION INPUT ;
    USE SIGNAL ;
    PORT
      LAYER M4 ;
        RECT  0 59.904 0.084 59.928 ;
    END
  END in_data[304]
  PIN in_data[305]
    DIRECTION INPUT ;
    USE SIGNAL ;
    PORT
      LAYER M4 ;
        RECT  0 59.952 0.084 59.976 ;
    END
  END in_data[305]
  PIN in_data[306]
    DIRECTION INPUT ;
    USE SIGNAL ;
    PORT
      LAYER M4 ;
        RECT  0 60 0.084 60.024 ;
    END
  END in_data[306]
  PIN in_data[307]
    DIRECTION INPUT ;
    USE SIGNAL ;
    PORT
      LAYER M4 ;
        RECT  0 60.048 0.084 60.072 ;
    END
  END in_data[307]
  PIN in_data[308]
    DIRECTION INPUT ;
    USE SIGNAL ;
    PORT
      LAYER M4 ;
        RECT  0 60.096 0.084 60.12 ;
    END
  END in_data[308]
  PIN in_data[309]
    DIRECTION INPUT ;
    USE SIGNAL ;
    PORT
      LAYER M4 ;
        RECT  0 60.144 0.084 60.168 ;
    END
  END in_data[309]
  PIN in_data[30]
    DIRECTION INPUT ;
    USE SIGNAL ;
    PORT
      LAYER M4 ;
        RECT  0 46.752 0.084 46.776 ;
    END
  END in_data[30]
  PIN in_data[310]
    DIRECTION INPUT ;
    USE SIGNAL ;
    PORT
      LAYER M4 ;
        RECT  0 60.192 0.084 60.216 ;
    END
  END in_data[310]
  PIN in_data[311]
    DIRECTION INPUT ;
    USE SIGNAL ;
    PORT
      LAYER M4 ;
        RECT  0 60.24 0.084 60.264 ;
    END
  END in_data[311]
  PIN in_data[312]
    DIRECTION INPUT ;
    USE SIGNAL ;
    PORT
      LAYER M4 ;
        RECT  0 60.288 0.084 60.312 ;
    END
  END in_data[312]
  PIN in_data[313]
    DIRECTION INPUT ;
    USE SIGNAL ;
    PORT
      LAYER M4 ;
        RECT  0 60.336 0.084 60.36 ;
    END
  END in_data[313]
  PIN in_data[314]
    DIRECTION INPUT ;
    USE SIGNAL ;
    PORT
      LAYER M4 ;
        RECT  0 60.384 0.084 60.408 ;
    END
  END in_data[314]
  PIN in_data[315]
    DIRECTION INPUT ;
    USE SIGNAL ;
    PORT
      LAYER M4 ;
        RECT  0 60.432 0.084 60.456 ;
    END
  END in_data[315]
  PIN in_data[316]
    DIRECTION INPUT ;
    USE SIGNAL ;
    PORT
      LAYER M4 ;
        RECT  0 60.48 0.084 60.504 ;
    END
  END in_data[316]
  PIN in_data[317]
    DIRECTION INPUT ;
    USE SIGNAL ;
    PORT
      LAYER M4 ;
        RECT  0 60.528 0.084 60.552 ;
    END
  END in_data[317]
  PIN in_data[318]
    DIRECTION INPUT ;
    USE SIGNAL ;
    PORT
      LAYER M4 ;
        RECT  0 60.576 0.084 60.6 ;
    END
  END in_data[318]
  PIN in_data[319]
    DIRECTION INPUT ;
    USE SIGNAL ;
    PORT
      LAYER M4 ;
        RECT  0 60.624 0.084 60.648 ;
    END
  END in_data[319]
  PIN in_data[31]
    DIRECTION INPUT ;
    USE SIGNAL ;
    PORT
      LAYER M4 ;
        RECT  0 46.8 0.084 46.824 ;
    END
  END in_data[31]
  PIN in_data[320]
    DIRECTION INPUT ;
    USE SIGNAL ;
    PORT
      LAYER M4 ;
        RECT  0 60.672 0.084 60.696 ;
    END
  END in_data[320]
  PIN in_data[321]
    DIRECTION INPUT ;
    USE SIGNAL ;
    PORT
      LAYER M4 ;
        RECT  0 60.72 0.084 60.744 ;
    END
  END in_data[321]
  PIN in_data[322]
    DIRECTION INPUT ;
    USE SIGNAL ;
    PORT
      LAYER M4 ;
        RECT  0 60.768 0.084 60.792 ;
    END
  END in_data[322]
  PIN in_data[323]
    DIRECTION INPUT ;
    USE SIGNAL ;
    PORT
      LAYER M4 ;
        RECT  0 60.816 0.084 60.84 ;
    END
  END in_data[323]
  PIN in_data[324]
    DIRECTION INPUT ;
    USE SIGNAL ;
    PORT
      LAYER M4 ;
        RECT  0 60.864 0.084 60.888 ;
    END
  END in_data[324]
  PIN in_data[325]
    DIRECTION INPUT ;
    USE SIGNAL ;
    PORT
      LAYER M4 ;
        RECT  0 60.912 0.084 60.936 ;
    END
  END in_data[325]
  PIN in_data[326]
    DIRECTION INPUT ;
    USE SIGNAL ;
    PORT
      LAYER M4 ;
        RECT  0 60.96 0.084 60.984 ;
    END
  END in_data[326]
  PIN in_data[327]
    DIRECTION INPUT ;
    USE SIGNAL ;
    PORT
      LAYER M4 ;
        RECT  0 61.008 0.084 61.032 ;
    END
  END in_data[327]
  PIN in_data[328]
    DIRECTION INPUT ;
    USE SIGNAL ;
    PORT
      LAYER M4 ;
        RECT  0 61.056 0.084 61.08 ;
    END
  END in_data[328]
  PIN in_data[329]
    DIRECTION INPUT ;
    USE SIGNAL ;
    PORT
      LAYER M4 ;
        RECT  0 61.104 0.084 61.128 ;
    END
  END in_data[329]
  PIN in_data[32]
    DIRECTION INPUT ;
    USE SIGNAL ;
    PORT
      LAYER M4 ;
        RECT  0 46.848 0.084 46.872 ;
    END
  END in_data[32]
  PIN in_data[330]
    DIRECTION INPUT ;
    USE SIGNAL ;
    PORT
      LAYER M4 ;
        RECT  0 61.152 0.084 61.176 ;
    END
  END in_data[330]
  PIN in_data[331]
    DIRECTION INPUT ;
    USE SIGNAL ;
    PORT
      LAYER M4 ;
        RECT  0 61.2 0.084 61.224 ;
    END
  END in_data[331]
  PIN in_data[332]
    DIRECTION INPUT ;
    USE SIGNAL ;
    PORT
      LAYER M4 ;
        RECT  0 61.248 0.084 61.272 ;
    END
  END in_data[332]
  PIN in_data[333]
    DIRECTION INPUT ;
    USE SIGNAL ;
    PORT
      LAYER M4 ;
        RECT  0 61.296 0.084 61.32 ;
    END
  END in_data[333]
  PIN in_data[334]
    DIRECTION INPUT ;
    USE SIGNAL ;
    PORT
      LAYER M4 ;
        RECT  0 61.344 0.084 61.368 ;
    END
  END in_data[334]
  PIN in_data[335]
    DIRECTION INPUT ;
    USE SIGNAL ;
    PORT
      LAYER M4 ;
        RECT  0 61.392 0.084 61.416 ;
    END
  END in_data[335]
  PIN in_data[336]
    DIRECTION INPUT ;
    USE SIGNAL ;
    PORT
      LAYER M4 ;
        RECT  0 61.44 0.084 61.464 ;
    END
  END in_data[336]
  PIN in_data[337]
    DIRECTION INPUT ;
    USE SIGNAL ;
    PORT
      LAYER M4 ;
        RECT  0 61.488 0.084 61.512 ;
    END
  END in_data[337]
  PIN in_data[338]
    DIRECTION INPUT ;
    USE SIGNAL ;
    PORT
      LAYER M4 ;
        RECT  0 61.536 0.084 61.56 ;
    END
  END in_data[338]
  PIN in_data[339]
    DIRECTION INPUT ;
    USE SIGNAL ;
    PORT
      LAYER M4 ;
        RECT  0 61.584 0.084 61.608 ;
    END
  END in_data[339]
  PIN in_data[33]
    DIRECTION INPUT ;
    USE SIGNAL ;
    PORT
      LAYER M4 ;
        RECT  0 46.896 0.084 46.92 ;
    END
  END in_data[33]
  PIN in_data[340]
    DIRECTION INPUT ;
    USE SIGNAL ;
    PORT
      LAYER M4 ;
        RECT  0 61.632 0.084 61.656 ;
    END
  END in_data[340]
  PIN in_data[341]
    DIRECTION INPUT ;
    USE SIGNAL ;
    PORT
      LAYER M4 ;
        RECT  0 61.68 0.084 61.704 ;
    END
  END in_data[341]
  PIN in_data[342]
    DIRECTION INPUT ;
    USE SIGNAL ;
    PORT
      LAYER M4 ;
        RECT  0 61.728 0.084 61.752 ;
    END
  END in_data[342]
  PIN in_data[343]
    DIRECTION INPUT ;
    USE SIGNAL ;
    PORT
      LAYER M4 ;
        RECT  0 61.776 0.084 61.8 ;
    END
  END in_data[343]
  PIN in_data[344]
    DIRECTION INPUT ;
    USE SIGNAL ;
    PORT
      LAYER M4 ;
        RECT  0 61.824 0.084 61.848 ;
    END
  END in_data[344]
  PIN in_data[345]
    DIRECTION INPUT ;
    USE SIGNAL ;
    PORT
      LAYER M4 ;
        RECT  0 61.872 0.084 61.896 ;
    END
  END in_data[345]
  PIN in_data[346]
    DIRECTION INPUT ;
    USE SIGNAL ;
    PORT
      LAYER M4 ;
        RECT  0 61.92 0.084 61.944 ;
    END
  END in_data[346]
  PIN in_data[347]
    DIRECTION INPUT ;
    USE SIGNAL ;
    PORT
      LAYER M4 ;
        RECT  0 61.968 0.084 61.992 ;
    END
  END in_data[347]
  PIN in_data[348]
    DIRECTION INPUT ;
    USE SIGNAL ;
    PORT
      LAYER M4 ;
        RECT  0 62.016 0.084 62.04 ;
    END
  END in_data[348]
  PIN in_data[349]
    DIRECTION INPUT ;
    USE SIGNAL ;
    PORT
      LAYER M4 ;
        RECT  0 62.064 0.084 62.088 ;
    END
  END in_data[349]
  PIN in_data[34]
    DIRECTION INPUT ;
    USE SIGNAL ;
    PORT
      LAYER M4 ;
        RECT  0 46.944 0.084 46.968 ;
    END
  END in_data[34]
  PIN in_data[350]
    DIRECTION INPUT ;
    USE SIGNAL ;
    PORT
      LAYER M4 ;
        RECT  0 62.112 0.084 62.136 ;
    END
  END in_data[350]
  PIN in_data[351]
    DIRECTION INPUT ;
    USE SIGNAL ;
    PORT
      LAYER M4 ;
        RECT  0 62.16 0.084 62.184 ;
    END
  END in_data[351]
  PIN in_data[352]
    DIRECTION INPUT ;
    USE SIGNAL ;
    PORT
      LAYER M4 ;
        RECT  0 62.208 0.084 62.232 ;
    END
  END in_data[352]
  PIN in_data[353]
    DIRECTION INPUT ;
    USE SIGNAL ;
    PORT
      LAYER M4 ;
        RECT  0 62.256 0.084 62.28 ;
    END
  END in_data[353]
  PIN in_data[354]
    DIRECTION INPUT ;
    USE SIGNAL ;
    PORT
      LAYER M4 ;
        RECT  0 62.304 0.084 62.328 ;
    END
  END in_data[354]
  PIN in_data[355]
    DIRECTION INPUT ;
    USE SIGNAL ;
    PORT
      LAYER M4 ;
        RECT  0 62.352 0.084 62.376 ;
    END
  END in_data[355]
  PIN in_data[356]
    DIRECTION INPUT ;
    USE SIGNAL ;
    PORT
      LAYER M4 ;
        RECT  0 62.4 0.084 62.424 ;
    END
  END in_data[356]
  PIN in_data[357]
    DIRECTION INPUT ;
    USE SIGNAL ;
    PORT
      LAYER M4 ;
        RECT  0 62.448 0.084 62.472 ;
    END
  END in_data[357]
  PIN in_data[358]
    DIRECTION INPUT ;
    USE SIGNAL ;
    PORT
      LAYER M4 ;
        RECT  0 62.496 0.084 62.52 ;
    END
  END in_data[358]
  PIN in_data[359]
    DIRECTION INPUT ;
    USE SIGNAL ;
    PORT
      LAYER M4 ;
        RECT  0 62.544 0.084 62.568 ;
    END
  END in_data[359]
  PIN in_data[35]
    DIRECTION INPUT ;
    USE SIGNAL ;
    PORT
      LAYER M4 ;
        RECT  0 46.992 0.084 47.016 ;
    END
  END in_data[35]
  PIN in_data[360]
    DIRECTION INPUT ;
    USE SIGNAL ;
    PORT
      LAYER M4 ;
        RECT  0 62.592 0.084 62.616 ;
    END
  END in_data[360]
  PIN in_data[361]
    DIRECTION INPUT ;
    USE SIGNAL ;
    PORT
      LAYER M4 ;
        RECT  0 62.64 0.084 62.664 ;
    END
  END in_data[361]
  PIN in_data[362]
    DIRECTION INPUT ;
    USE SIGNAL ;
    PORT
      LAYER M4 ;
        RECT  0 62.688 0.084 62.712 ;
    END
  END in_data[362]
  PIN in_data[363]
    DIRECTION INPUT ;
    USE SIGNAL ;
    PORT
      LAYER M4 ;
        RECT  0 62.736 0.084 62.76 ;
    END
  END in_data[363]
  PIN in_data[364]
    DIRECTION INPUT ;
    USE SIGNAL ;
    PORT
      LAYER M4 ;
        RECT  0 62.784 0.084 62.808 ;
    END
  END in_data[364]
  PIN in_data[365]
    DIRECTION INPUT ;
    USE SIGNAL ;
    PORT
      LAYER M4 ;
        RECT  0 62.832 0.084 62.856 ;
    END
  END in_data[365]
  PIN in_data[366]
    DIRECTION INPUT ;
    USE SIGNAL ;
    PORT
      LAYER M4 ;
        RECT  0 62.88 0.084 62.904 ;
    END
  END in_data[366]
  PIN in_data[367]
    DIRECTION INPUT ;
    USE SIGNAL ;
    PORT
      LAYER M4 ;
        RECT  0 62.928 0.084 62.952 ;
    END
  END in_data[367]
  PIN in_data[368]
    DIRECTION INPUT ;
    USE SIGNAL ;
    PORT
      LAYER M4 ;
        RECT  0 62.976 0.084 63 ;
    END
  END in_data[368]
  PIN in_data[369]
    DIRECTION INPUT ;
    USE SIGNAL ;
    PORT
      LAYER M4 ;
        RECT  0 63.024 0.084 63.048 ;
    END
  END in_data[369]
  PIN in_data[36]
    DIRECTION INPUT ;
    USE SIGNAL ;
    PORT
      LAYER M4 ;
        RECT  0 47.04 0.084 47.064 ;
    END
  END in_data[36]
  PIN in_data[370]
    DIRECTION INPUT ;
    USE SIGNAL ;
    PORT
      LAYER M4 ;
        RECT  0 63.072 0.084 63.096 ;
    END
  END in_data[370]
  PIN in_data[371]
    DIRECTION INPUT ;
    USE SIGNAL ;
    PORT
      LAYER M4 ;
        RECT  0 63.12 0.084 63.144 ;
    END
  END in_data[371]
  PIN in_data[372]
    DIRECTION INPUT ;
    USE SIGNAL ;
    PORT
      LAYER M4 ;
        RECT  0 63.168 0.084 63.192 ;
    END
  END in_data[372]
  PIN in_data[373]
    DIRECTION INPUT ;
    USE SIGNAL ;
    PORT
      LAYER M4 ;
        RECT  0 63.216 0.084 63.24 ;
    END
  END in_data[373]
  PIN in_data[374]
    DIRECTION INPUT ;
    USE SIGNAL ;
    PORT
      LAYER M4 ;
        RECT  0 63.264 0.084 63.288 ;
    END
  END in_data[374]
  PIN in_data[375]
    DIRECTION INPUT ;
    USE SIGNAL ;
    PORT
      LAYER M4 ;
        RECT  0 63.312 0.084 63.336 ;
    END
  END in_data[375]
  PIN in_data[376]
    DIRECTION INPUT ;
    USE SIGNAL ;
    PORT
      LAYER M4 ;
        RECT  0 63.36 0.084 63.384 ;
    END
  END in_data[376]
  PIN in_data[377]
    DIRECTION INPUT ;
    USE SIGNAL ;
    PORT
      LAYER M4 ;
        RECT  0 63.408 0.084 63.432 ;
    END
  END in_data[377]
  PIN in_data[378]
    DIRECTION INPUT ;
    USE SIGNAL ;
    PORT
      LAYER M4 ;
        RECT  0 63.456 0.084 63.48 ;
    END
  END in_data[378]
  PIN in_data[379]
    DIRECTION INPUT ;
    USE SIGNAL ;
    PORT
      LAYER M4 ;
        RECT  0 63.504 0.084 63.528 ;
    END
  END in_data[379]
  PIN in_data[37]
    DIRECTION INPUT ;
    USE SIGNAL ;
    PORT
      LAYER M4 ;
        RECT  0 47.088 0.084 47.112 ;
    END
  END in_data[37]
  PIN in_data[380]
    DIRECTION INPUT ;
    USE SIGNAL ;
    PORT
      LAYER M4 ;
        RECT  0 63.552 0.084 63.576 ;
    END
  END in_data[380]
  PIN in_data[381]
    DIRECTION INPUT ;
    USE SIGNAL ;
    PORT
      LAYER M4 ;
        RECT  0 63.6 0.084 63.624 ;
    END
  END in_data[381]
  PIN in_data[382]
    DIRECTION INPUT ;
    USE SIGNAL ;
    PORT
      LAYER M4 ;
        RECT  0 63.648 0.084 63.672 ;
    END
  END in_data[382]
  PIN in_data[383]
    DIRECTION INPUT ;
    USE SIGNAL ;
    PORT
      LAYER M4 ;
        RECT  0 63.696 0.084 63.72 ;
    END
  END in_data[383]
  PIN in_data[384]
    DIRECTION INPUT ;
    USE SIGNAL ;
    PORT
      LAYER M4 ;
        RECT  0 63.744 0.084 63.768 ;
    END
  END in_data[384]
  PIN in_data[385]
    DIRECTION INPUT ;
    USE SIGNAL ;
    PORT
      LAYER M4 ;
        RECT  0 63.792 0.084 63.816 ;
    END
  END in_data[385]
  PIN in_data[386]
    DIRECTION INPUT ;
    USE SIGNAL ;
    PORT
      LAYER M4 ;
        RECT  0 63.84 0.084 63.864 ;
    END
  END in_data[386]
  PIN in_data[387]
    DIRECTION INPUT ;
    USE SIGNAL ;
    PORT
      LAYER M4 ;
        RECT  0 63.888 0.084 63.912 ;
    END
  END in_data[387]
  PIN in_data[388]
    DIRECTION INPUT ;
    USE SIGNAL ;
    PORT
      LAYER M4 ;
        RECT  0 63.936 0.084 63.96 ;
    END
  END in_data[388]
  PIN in_data[389]
    DIRECTION INPUT ;
    USE SIGNAL ;
    PORT
      LAYER M4 ;
        RECT  0 63.984 0.084 64.008 ;
    END
  END in_data[389]
  PIN in_data[38]
    DIRECTION INPUT ;
    USE SIGNAL ;
    PORT
      LAYER M4 ;
        RECT  0 47.136 0.084 47.16 ;
    END
  END in_data[38]
  PIN in_data[390]
    DIRECTION INPUT ;
    USE SIGNAL ;
    PORT
      LAYER M4 ;
        RECT  0 64.032 0.084 64.056 ;
    END
  END in_data[390]
  PIN in_data[391]
    DIRECTION INPUT ;
    USE SIGNAL ;
    PORT
      LAYER M4 ;
        RECT  0 64.08 0.084 64.104 ;
    END
  END in_data[391]
  PIN in_data[392]
    DIRECTION INPUT ;
    USE SIGNAL ;
    PORT
      LAYER M4 ;
        RECT  0 64.128 0.084 64.152 ;
    END
  END in_data[392]
  PIN in_data[393]
    DIRECTION INPUT ;
    USE SIGNAL ;
    PORT
      LAYER M4 ;
        RECT  0 64.176 0.084 64.2 ;
    END
  END in_data[393]
  PIN in_data[394]
    DIRECTION INPUT ;
    USE SIGNAL ;
    PORT
      LAYER M4 ;
        RECT  0 64.224 0.084 64.248 ;
    END
  END in_data[394]
  PIN in_data[395]
    DIRECTION INPUT ;
    USE SIGNAL ;
    PORT
      LAYER M4 ;
        RECT  0 64.272 0.084 64.296 ;
    END
  END in_data[395]
  PIN in_data[396]
    DIRECTION INPUT ;
    USE SIGNAL ;
    PORT
      LAYER M4 ;
        RECT  0 64.32 0.084 64.344 ;
    END
  END in_data[396]
  PIN in_data[397]
    DIRECTION INPUT ;
    USE SIGNAL ;
    PORT
      LAYER M4 ;
        RECT  0 64.368 0.084 64.392 ;
    END
  END in_data[397]
  PIN in_data[398]
    DIRECTION INPUT ;
    USE SIGNAL ;
    PORT
      LAYER M4 ;
        RECT  0 64.416 0.084 64.44 ;
    END
  END in_data[398]
  PIN in_data[399]
    DIRECTION INPUT ;
    USE SIGNAL ;
    PORT
      LAYER M4 ;
        RECT  0 64.464 0.084 64.488 ;
    END
  END in_data[399]
  PIN in_data[39]
    DIRECTION INPUT ;
    USE SIGNAL ;
    PORT
      LAYER M4 ;
        RECT  0 47.184 0.084 47.208 ;
    END
  END in_data[39]
  PIN in_data[3]
    DIRECTION INPUT ;
    USE SIGNAL ;
    PORT
      LAYER M4 ;
        RECT  0 45.456 0.084 45.48 ;
    END
  END in_data[3]
  PIN in_data[400]
    DIRECTION INPUT ;
    USE SIGNAL ;
    PORT
      LAYER M4 ;
        RECT  0 64.512 0.084 64.536 ;
    END
  END in_data[400]
  PIN in_data[401]
    DIRECTION INPUT ;
    USE SIGNAL ;
    PORT
      LAYER M4 ;
        RECT  0 64.56 0.084 64.584 ;
    END
  END in_data[401]
  PIN in_data[402]
    DIRECTION INPUT ;
    USE SIGNAL ;
    PORT
      LAYER M4 ;
        RECT  0 64.608 0.084 64.632 ;
    END
  END in_data[402]
  PIN in_data[403]
    DIRECTION INPUT ;
    USE SIGNAL ;
    PORT
      LAYER M4 ;
        RECT  0 64.656 0.084 64.68 ;
    END
  END in_data[403]
  PIN in_data[404]
    DIRECTION INPUT ;
    USE SIGNAL ;
    PORT
      LAYER M4 ;
        RECT  0 64.704 0.084 64.728 ;
    END
  END in_data[404]
  PIN in_data[405]
    DIRECTION INPUT ;
    USE SIGNAL ;
    PORT
      LAYER M4 ;
        RECT  0 64.752 0.084 64.776 ;
    END
  END in_data[405]
  PIN in_data[406]
    DIRECTION INPUT ;
    USE SIGNAL ;
    PORT
      LAYER M4 ;
        RECT  0 64.8 0.084 64.824 ;
    END
  END in_data[406]
  PIN in_data[407]
    DIRECTION INPUT ;
    USE SIGNAL ;
    PORT
      LAYER M4 ;
        RECT  0 64.848 0.084 64.872 ;
    END
  END in_data[407]
  PIN in_data[408]
    DIRECTION INPUT ;
    USE SIGNAL ;
    PORT
      LAYER M4 ;
        RECT  0 64.896 0.084 64.92 ;
    END
  END in_data[408]
  PIN in_data[409]
    DIRECTION INPUT ;
    USE SIGNAL ;
    PORT
      LAYER M4 ;
        RECT  0 64.944 0.084 64.968 ;
    END
  END in_data[409]
  PIN in_data[40]
    DIRECTION INPUT ;
    USE SIGNAL ;
    PORT
      LAYER M4 ;
        RECT  0 47.232 0.084 47.256 ;
    END
  END in_data[40]
  PIN in_data[410]
    DIRECTION INPUT ;
    USE SIGNAL ;
    PORT
      LAYER M4 ;
        RECT  0 64.992 0.084 65.016 ;
    END
  END in_data[410]
  PIN in_data[411]
    DIRECTION INPUT ;
    USE SIGNAL ;
    PORT
      LAYER M4 ;
        RECT  0 65.04 0.084 65.064 ;
    END
  END in_data[411]
  PIN in_data[412]
    DIRECTION INPUT ;
    USE SIGNAL ;
    PORT
      LAYER M4 ;
        RECT  0 65.088 0.084 65.112 ;
    END
  END in_data[412]
  PIN in_data[413]
    DIRECTION INPUT ;
    USE SIGNAL ;
    PORT
      LAYER M4 ;
        RECT  0 65.136 0.084 65.16 ;
    END
  END in_data[413]
  PIN in_data[414]
    DIRECTION INPUT ;
    USE SIGNAL ;
    PORT
      LAYER M4 ;
        RECT  0 65.184 0.084 65.208 ;
    END
  END in_data[414]
  PIN in_data[415]
    DIRECTION INPUT ;
    USE SIGNAL ;
    PORT
      LAYER M4 ;
        RECT  0 65.232 0.084 65.256 ;
    END
  END in_data[415]
  PIN in_data[416]
    DIRECTION INPUT ;
    USE SIGNAL ;
    PORT
      LAYER M4 ;
        RECT  0 65.28 0.084 65.304 ;
    END
  END in_data[416]
  PIN in_data[417]
    DIRECTION INPUT ;
    USE SIGNAL ;
    PORT
      LAYER M4 ;
        RECT  0 65.328 0.084 65.352 ;
    END
  END in_data[417]
  PIN in_data[418]
    DIRECTION INPUT ;
    USE SIGNAL ;
    PORT
      LAYER M4 ;
        RECT  0 65.376 0.084 65.4 ;
    END
  END in_data[418]
  PIN in_data[419]
    DIRECTION INPUT ;
    USE SIGNAL ;
    PORT
      LAYER M4 ;
        RECT  0 65.424 0.084 65.448 ;
    END
  END in_data[419]
  PIN in_data[41]
    DIRECTION INPUT ;
    USE SIGNAL ;
    PORT
      LAYER M4 ;
        RECT  0 47.28 0.084 47.304 ;
    END
  END in_data[41]
  PIN in_data[420]
    DIRECTION INPUT ;
    USE SIGNAL ;
    PORT
      LAYER M4 ;
        RECT  0 65.472 0.084 65.496 ;
    END
  END in_data[420]
  PIN in_data[421]
    DIRECTION INPUT ;
    USE SIGNAL ;
    PORT
      LAYER M4 ;
        RECT  0 65.52 0.084 65.544 ;
    END
  END in_data[421]
  PIN in_data[422]
    DIRECTION INPUT ;
    USE SIGNAL ;
    PORT
      LAYER M4 ;
        RECT  0 65.568 0.084 65.592 ;
    END
  END in_data[422]
  PIN in_data[423]
    DIRECTION INPUT ;
    USE SIGNAL ;
    PORT
      LAYER M4 ;
        RECT  0 65.616 0.084 65.64 ;
    END
  END in_data[423]
  PIN in_data[424]
    DIRECTION INPUT ;
    USE SIGNAL ;
    PORT
      LAYER M4 ;
        RECT  0 65.664 0.084 65.688 ;
    END
  END in_data[424]
  PIN in_data[425]
    DIRECTION INPUT ;
    USE SIGNAL ;
    PORT
      LAYER M4 ;
        RECT  0 65.712 0.084 65.736 ;
    END
  END in_data[425]
  PIN in_data[426]
    DIRECTION INPUT ;
    USE SIGNAL ;
    PORT
      LAYER M4 ;
        RECT  0 65.76 0.084 65.784 ;
    END
  END in_data[426]
  PIN in_data[427]
    DIRECTION INPUT ;
    USE SIGNAL ;
    PORT
      LAYER M4 ;
        RECT  0 65.808 0.084 65.832 ;
    END
  END in_data[427]
  PIN in_data[428]
    DIRECTION INPUT ;
    USE SIGNAL ;
    PORT
      LAYER M4 ;
        RECT  0 65.856 0.084 65.88 ;
    END
  END in_data[428]
  PIN in_data[429]
    DIRECTION INPUT ;
    USE SIGNAL ;
    PORT
      LAYER M4 ;
        RECT  0 65.904 0.084 65.928 ;
    END
  END in_data[429]
  PIN in_data[42]
    DIRECTION INPUT ;
    USE SIGNAL ;
    PORT
      LAYER M4 ;
        RECT  0 47.328 0.084 47.352 ;
    END
  END in_data[42]
  PIN in_data[430]
    DIRECTION INPUT ;
    USE SIGNAL ;
    PORT
      LAYER M4 ;
        RECT  0 65.952 0.084 65.976 ;
    END
  END in_data[430]
  PIN in_data[431]
    DIRECTION INPUT ;
    USE SIGNAL ;
    PORT
      LAYER M4 ;
        RECT  0 66 0.084 66.024 ;
    END
  END in_data[431]
  PIN in_data[432]
    DIRECTION INPUT ;
    USE SIGNAL ;
    PORT
      LAYER M4 ;
        RECT  0 66.048 0.084 66.072 ;
    END
  END in_data[432]
  PIN in_data[433]
    DIRECTION INPUT ;
    USE SIGNAL ;
    PORT
      LAYER M4 ;
        RECT  0 66.096 0.084 66.12 ;
    END
  END in_data[433]
  PIN in_data[434]
    DIRECTION INPUT ;
    USE SIGNAL ;
    PORT
      LAYER M4 ;
        RECT  0 66.144 0.084 66.168 ;
    END
  END in_data[434]
  PIN in_data[435]
    DIRECTION INPUT ;
    USE SIGNAL ;
    PORT
      LAYER M4 ;
        RECT  0 66.192 0.084 66.216 ;
    END
  END in_data[435]
  PIN in_data[436]
    DIRECTION INPUT ;
    USE SIGNAL ;
    PORT
      LAYER M4 ;
        RECT  0 66.24 0.084 66.264 ;
    END
  END in_data[436]
  PIN in_data[437]
    DIRECTION INPUT ;
    USE SIGNAL ;
    PORT
      LAYER M4 ;
        RECT  0 66.288 0.084 66.312 ;
    END
  END in_data[437]
  PIN in_data[438]
    DIRECTION INPUT ;
    USE SIGNAL ;
    PORT
      LAYER M4 ;
        RECT  0 66.336 0.084 66.36 ;
    END
  END in_data[438]
  PIN in_data[439]
    DIRECTION INPUT ;
    USE SIGNAL ;
    PORT
      LAYER M4 ;
        RECT  0 66.384 0.084 66.408 ;
    END
  END in_data[439]
  PIN in_data[43]
    DIRECTION INPUT ;
    USE SIGNAL ;
    PORT
      LAYER M4 ;
        RECT  0 47.376 0.084 47.4 ;
    END
  END in_data[43]
  PIN in_data[440]
    DIRECTION INPUT ;
    USE SIGNAL ;
    PORT
      LAYER M4 ;
        RECT  0 66.432 0.084 66.456 ;
    END
  END in_data[440]
  PIN in_data[441]
    DIRECTION INPUT ;
    USE SIGNAL ;
    PORT
      LAYER M4 ;
        RECT  0 66.48 0.084 66.504 ;
    END
  END in_data[441]
  PIN in_data[442]
    DIRECTION INPUT ;
    USE SIGNAL ;
    PORT
      LAYER M4 ;
        RECT  0 66.528 0.084 66.552 ;
    END
  END in_data[442]
  PIN in_data[443]
    DIRECTION INPUT ;
    USE SIGNAL ;
    PORT
      LAYER M4 ;
        RECT  0 66.576 0.084 66.6 ;
    END
  END in_data[443]
  PIN in_data[444]
    DIRECTION INPUT ;
    USE SIGNAL ;
    PORT
      LAYER M4 ;
        RECT  0 66.624 0.084 66.648 ;
    END
  END in_data[444]
  PIN in_data[445]
    DIRECTION INPUT ;
    USE SIGNAL ;
    PORT
      LAYER M4 ;
        RECT  0 66.672 0.084 66.696 ;
    END
  END in_data[445]
  PIN in_data[446]
    DIRECTION INPUT ;
    USE SIGNAL ;
    PORT
      LAYER M4 ;
        RECT  0 66.72 0.084 66.744 ;
    END
  END in_data[446]
  PIN in_data[447]
    DIRECTION INPUT ;
    USE SIGNAL ;
    PORT
      LAYER M4 ;
        RECT  0 66.768 0.084 66.792 ;
    END
  END in_data[447]
  PIN in_data[448]
    DIRECTION INPUT ;
    USE SIGNAL ;
    PORT
      LAYER M4 ;
        RECT  0 66.816 0.084 66.84 ;
    END
  END in_data[448]
  PIN in_data[449]
    DIRECTION INPUT ;
    USE SIGNAL ;
    PORT
      LAYER M4 ;
        RECT  0 66.864 0.084 66.888 ;
    END
  END in_data[449]
  PIN in_data[44]
    DIRECTION INPUT ;
    USE SIGNAL ;
    PORT
      LAYER M4 ;
        RECT  0 47.424 0.084 47.448 ;
    END
  END in_data[44]
  PIN in_data[450]
    DIRECTION INPUT ;
    USE SIGNAL ;
    PORT
      LAYER M4 ;
        RECT  0 66.912 0.084 66.936 ;
    END
  END in_data[450]
  PIN in_data[451]
    DIRECTION INPUT ;
    USE SIGNAL ;
    PORT
      LAYER M4 ;
        RECT  0 66.96 0.084 66.984 ;
    END
  END in_data[451]
  PIN in_data[452]
    DIRECTION INPUT ;
    USE SIGNAL ;
    PORT
      LAYER M4 ;
        RECT  0 67.008 0.084 67.032 ;
    END
  END in_data[452]
  PIN in_data[453]
    DIRECTION INPUT ;
    USE SIGNAL ;
    PORT
      LAYER M4 ;
        RECT  0 67.056 0.084 67.08 ;
    END
  END in_data[453]
  PIN in_data[454]
    DIRECTION INPUT ;
    USE SIGNAL ;
    PORT
      LAYER M4 ;
        RECT  0 67.104 0.084 67.128 ;
    END
  END in_data[454]
  PIN in_data[455]
    DIRECTION INPUT ;
    USE SIGNAL ;
    PORT
      LAYER M4 ;
        RECT  0 67.152 0.084 67.176 ;
    END
  END in_data[455]
  PIN in_data[456]
    DIRECTION INPUT ;
    USE SIGNAL ;
    PORT
      LAYER M4 ;
        RECT  0 67.2 0.084 67.224 ;
    END
  END in_data[456]
  PIN in_data[457]
    DIRECTION INPUT ;
    USE SIGNAL ;
    PORT
      LAYER M4 ;
        RECT  0 67.248 0.084 67.272 ;
    END
  END in_data[457]
  PIN in_data[458]
    DIRECTION INPUT ;
    USE SIGNAL ;
    PORT
      LAYER M4 ;
        RECT  0 67.296 0.084 67.32 ;
    END
  END in_data[458]
  PIN in_data[459]
    DIRECTION INPUT ;
    USE SIGNAL ;
    PORT
      LAYER M4 ;
        RECT  0 67.344 0.084 67.368 ;
    END
  END in_data[459]
  PIN in_data[45]
    DIRECTION INPUT ;
    USE SIGNAL ;
    PORT
      LAYER M4 ;
        RECT  0 47.472 0.084 47.496 ;
    END
  END in_data[45]
  PIN in_data[460]
    DIRECTION INPUT ;
    USE SIGNAL ;
    PORT
      LAYER M4 ;
        RECT  0 67.392 0.084 67.416 ;
    END
  END in_data[460]
  PIN in_data[461]
    DIRECTION INPUT ;
    USE SIGNAL ;
    PORT
      LAYER M4 ;
        RECT  0 67.44 0.084 67.464 ;
    END
  END in_data[461]
  PIN in_data[462]
    DIRECTION INPUT ;
    USE SIGNAL ;
    PORT
      LAYER M4 ;
        RECT  0 67.488 0.084 67.512 ;
    END
  END in_data[462]
  PIN in_data[463]
    DIRECTION INPUT ;
    USE SIGNAL ;
    PORT
      LAYER M4 ;
        RECT  0 67.536 0.084 67.56 ;
    END
  END in_data[463]
  PIN in_data[464]
    DIRECTION INPUT ;
    USE SIGNAL ;
    PORT
      LAYER M4 ;
        RECT  0 67.584 0.084 67.608 ;
    END
  END in_data[464]
  PIN in_data[465]
    DIRECTION INPUT ;
    USE SIGNAL ;
    PORT
      LAYER M4 ;
        RECT  0 67.632 0.084 67.656 ;
    END
  END in_data[465]
  PIN in_data[466]
    DIRECTION INPUT ;
    USE SIGNAL ;
    PORT
      LAYER M4 ;
        RECT  0 67.68 0.084 67.704 ;
    END
  END in_data[466]
  PIN in_data[467]
    DIRECTION INPUT ;
    USE SIGNAL ;
    PORT
      LAYER M4 ;
        RECT  0 67.728 0.084 67.752 ;
    END
  END in_data[467]
  PIN in_data[468]
    DIRECTION INPUT ;
    USE SIGNAL ;
    PORT
      LAYER M4 ;
        RECT  0 67.776 0.084 67.8 ;
    END
  END in_data[468]
  PIN in_data[469]
    DIRECTION INPUT ;
    USE SIGNAL ;
    PORT
      LAYER M4 ;
        RECT  0 67.824 0.084 67.848 ;
    END
  END in_data[469]
  PIN in_data[46]
    DIRECTION INPUT ;
    USE SIGNAL ;
    PORT
      LAYER M4 ;
        RECT  0 47.52 0.084 47.544 ;
    END
  END in_data[46]
  PIN in_data[470]
    DIRECTION INPUT ;
    USE SIGNAL ;
    PORT
      LAYER M4 ;
        RECT  0 67.872 0.084 67.896 ;
    END
  END in_data[470]
  PIN in_data[471]
    DIRECTION INPUT ;
    USE SIGNAL ;
    PORT
      LAYER M4 ;
        RECT  0 67.92 0.084 67.944 ;
    END
  END in_data[471]
  PIN in_data[472]
    DIRECTION INPUT ;
    USE SIGNAL ;
    PORT
      LAYER M4 ;
        RECT  0 67.968 0.084 67.992 ;
    END
  END in_data[472]
  PIN in_data[473]
    DIRECTION INPUT ;
    USE SIGNAL ;
    PORT
      LAYER M4 ;
        RECT  0 68.016 0.084 68.04 ;
    END
  END in_data[473]
  PIN in_data[474]
    DIRECTION INPUT ;
    USE SIGNAL ;
    PORT
      LAYER M4 ;
        RECT  0 68.064 0.084 68.088 ;
    END
  END in_data[474]
  PIN in_data[475]
    DIRECTION INPUT ;
    USE SIGNAL ;
    PORT
      LAYER M4 ;
        RECT  0 68.112 0.084 68.136 ;
    END
  END in_data[475]
  PIN in_data[476]
    DIRECTION INPUT ;
    USE SIGNAL ;
    PORT
      LAYER M4 ;
        RECT  0 68.16 0.084 68.184 ;
    END
  END in_data[476]
  PIN in_data[477]
    DIRECTION INPUT ;
    USE SIGNAL ;
    PORT
      LAYER M4 ;
        RECT  0 68.208 0.084 68.232 ;
    END
  END in_data[477]
  PIN in_data[478]
    DIRECTION INPUT ;
    USE SIGNAL ;
    PORT
      LAYER M4 ;
        RECT  0 68.256 0.084 68.28 ;
    END
  END in_data[478]
  PIN in_data[479]
    DIRECTION INPUT ;
    USE SIGNAL ;
    PORT
      LAYER M4 ;
        RECT  0 68.304 0.084 68.328 ;
    END
  END in_data[479]
  PIN in_data[47]
    DIRECTION INPUT ;
    USE SIGNAL ;
    PORT
      LAYER M4 ;
        RECT  0 47.568 0.084 47.592 ;
    END
  END in_data[47]
  PIN in_data[480]
    DIRECTION INPUT ;
    USE SIGNAL ;
    PORT
      LAYER M4 ;
        RECT  0 68.352 0.084 68.376 ;
    END
  END in_data[480]
  PIN in_data[481]
    DIRECTION INPUT ;
    USE SIGNAL ;
    PORT
      LAYER M4 ;
        RECT  0 68.4 0.084 68.424 ;
    END
  END in_data[481]
  PIN in_data[482]
    DIRECTION INPUT ;
    USE SIGNAL ;
    PORT
      LAYER M4 ;
        RECT  0 68.448 0.084 68.472 ;
    END
  END in_data[482]
  PIN in_data[483]
    DIRECTION INPUT ;
    USE SIGNAL ;
    PORT
      LAYER M4 ;
        RECT  0 68.496 0.084 68.52 ;
    END
  END in_data[483]
  PIN in_data[484]
    DIRECTION INPUT ;
    USE SIGNAL ;
    PORT
      LAYER M4 ;
        RECT  0 68.544 0.084 68.568 ;
    END
  END in_data[484]
  PIN in_data[485]
    DIRECTION INPUT ;
    USE SIGNAL ;
    PORT
      LAYER M4 ;
        RECT  0 68.592 0.084 68.616 ;
    END
  END in_data[485]
  PIN in_data[486]
    DIRECTION INPUT ;
    USE SIGNAL ;
    PORT
      LAYER M4 ;
        RECT  0 68.64 0.084 68.664 ;
    END
  END in_data[486]
  PIN in_data[487]
    DIRECTION INPUT ;
    USE SIGNAL ;
    PORT
      LAYER M4 ;
        RECT  0 68.688 0.084 68.712 ;
    END
  END in_data[487]
  PIN in_data[488]
    DIRECTION INPUT ;
    USE SIGNAL ;
    PORT
      LAYER M4 ;
        RECT  0 68.736 0.084 68.76 ;
    END
  END in_data[488]
  PIN in_data[489]
    DIRECTION INPUT ;
    USE SIGNAL ;
    PORT
      LAYER M4 ;
        RECT  0 68.784 0.084 68.808 ;
    END
  END in_data[489]
  PIN in_data[48]
    DIRECTION INPUT ;
    USE SIGNAL ;
    PORT
      LAYER M4 ;
        RECT  0 47.616 0.084 47.64 ;
    END
  END in_data[48]
  PIN in_data[490]
    DIRECTION INPUT ;
    USE SIGNAL ;
    PORT
      LAYER M4 ;
        RECT  0 68.832 0.084 68.856 ;
    END
  END in_data[490]
  PIN in_data[491]
    DIRECTION INPUT ;
    USE SIGNAL ;
    PORT
      LAYER M4 ;
        RECT  0 68.88 0.084 68.904 ;
    END
  END in_data[491]
  PIN in_data[492]
    DIRECTION INPUT ;
    USE SIGNAL ;
    PORT
      LAYER M4 ;
        RECT  0 68.928 0.084 68.952 ;
    END
  END in_data[492]
  PIN in_data[493]
    DIRECTION INPUT ;
    USE SIGNAL ;
    PORT
      LAYER M4 ;
        RECT  0 68.976 0.084 69 ;
    END
  END in_data[493]
  PIN in_data[494]
    DIRECTION INPUT ;
    USE SIGNAL ;
    PORT
      LAYER M4 ;
        RECT  0 69.024 0.084 69.048 ;
    END
  END in_data[494]
  PIN in_data[495]
    DIRECTION INPUT ;
    USE SIGNAL ;
    PORT
      LAYER M4 ;
        RECT  0 69.072 0.084 69.096 ;
    END
  END in_data[495]
  PIN in_data[496]
    DIRECTION INPUT ;
    USE SIGNAL ;
    PORT
      LAYER M4 ;
        RECT  0 69.12 0.084 69.144 ;
    END
  END in_data[496]
  PIN in_data[497]
    DIRECTION INPUT ;
    USE SIGNAL ;
    PORT
      LAYER M4 ;
        RECT  0 69.168 0.084 69.192 ;
    END
  END in_data[497]
  PIN in_data[498]
    DIRECTION INPUT ;
    USE SIGNAL ;
    PORT
      LAYER M4 ;
        RECT  0 69.216 0.084 69.24 ;
    END
  END in_data[498]
  PIN in_data[499]
    DIRECTION INPUT ;
    USE SIGNAL ;
    PORT
      LAYER M4 ;
        RECT  0 69.264 0.084 69.288 ;
    END
  END in_data[499]
  PIN in_data[49]
    DIRECTION INPUT ;
    USE SIGNAL ;
    PORT
      LAYER M4 ;
        RECT  0 47.664 0.084 47.688 ;
    END
  END in_data[49]
  PIN in_data[4]
    DIRECTION INPUT ;
    USE SIGNAL ;
    PORT
      LAYER M4 ;
        RECT  0 45.504 0.084 45.528 ;
    END
  END in_data[4]
  PIN in_data[500]
    DIRECTION INPUT ;
    USE SIGNAL ;
    PORT
      LAYER M4 ;
        RECT  0 69.312 0.084 69.336 ;
    END
  END in_data[500]
  PIN in_data[501]
    DIRECTION INPUT ;
    USE SIGNAL ;
    PORT
      LAYER M4 ;
        RECT  0 69.36 0.084 69.384 ;
    END
  END in_data[501]
  PIN in_data[502]
    DIRECTION INPUT ;
    USE SIGNAL ;
    PORT
      LAYER M4 ;
        RECT  0 69.408 0.084 69.432 ;
    END
  END in_data[502]
  PIN in_data[503]
    DIRECTION INPUT ;
    USE SIGNAL ;
    PORT
      LAYER M4 ;
        RECT  0 69.456 0.084 69.48 ;
    END
  END in_data[503]
  PIN in_data[504]
    DIRECTION INPUT ;
    USE SIGNAL ;
    PORT
      LAYER M4 ;
        RECT  0 69.504 0.084 69.528 ;
    END
  END in_data[504]
  PIN in_data[505]
    DIRECTION INPUT ;
    USE SIGNAL ;
    PORT
      LAYER M4 ;
        RECT  0 69.552 0.084 69.576 ;
    END
  END in_data[505]
  PIN in_data[506]
    DIRECTION INPUT ;
    USE SIGNAL ;
    PORT
      LAYER M4 ;
        RECT  0 69.6 0.084 69.624 ;
    END
  END in_data[506]
  PIN in_data[507]
    DIRECTION INPUT ;
    USE SIGNAL ;
    PORT
      LAYER M4 ;
        RECT  0 69.648 0.084 69.672 ;
    END
  END in_data[507]
  PIN in_data[508]
    DIRECTION INPUT ;
    USE SIGNAL ;
    PORT
      LAYER M4 ;
        RECT  0 69.696 0.084 69.72 ;
    END
  END in_data[508]
  PIN in_data[509]
    DIRECTION INPUT ;
    USE SIGNAL ;
    PORT
      LAYER M4 ;
        RECT  0 69.744 0.084 69.768 ;
    END
  END in_data[509]
  PIN in_data[50]
    DIRECTION INPUT ;
    USE SIGNAL ;
    PORT
      LAYER M4 ;
        RECT  0 47.712 0.084 47.736 ;
    END
  END in_data[50]
  PIN in_data[510]
    DIRECTION INPUT ;
    USE SIGNAL ;
    PORT
      LAYER M4 ;
        RECT  0 69.792 0.084 69.816 ;
    END
  END in_data[510]
  PIN in_data[511]
    DIRECTION INPUT ;
    USE SIGNAL ;
    PORT
      LAYER M4 ;
        RECT  0 69.84 0.084 69.864 ;
    END
  END in_data[511]
  PIN in_data[51]
    DIRECTION INPUT ;
    USE SIGNAL ;
    PORT
      LAYER M4 ;
        RECT  0 47.76 0.084 47.784 ;
    END
  END in_data[51]
  PIN in_data[52]
    DIRECTION INPUT ;
    USE SIGNAL ;
    PORT
      LAYER M4 ;
        RECT  0 47.808 0.084 47.832 ;
    END
  END in_data[52]
  PIN in_data[53]
    DIRECTION INPUT ;
    USE SIGNAL ;
    PORT
      LAYER M4 ;
        RECT  0 47.856 0.084 47.88 ;
    END
  END in_data[53]
  PIN in_data[54]
    DIRECTION INPUT ;
    USE SIGNAL ;
    PORT
      LAYER M4 ;
        RECT  0 47.904 0.084 47.928 ;
    END
  END in_data[54]
  PIN in_data[55]
    DIRECTION INPUT ;
    USE SIGNAL ;
    PORT
      LAYER M4 ;
        RECT  0 47.952 0.084 47.976 ;
    END
  END in_data[55]
  PIN in_data[56]
    DIRECTION INPUT ;
    USE SIGNAL ;
    PORT
      LAYER M4 ;
        RECT  0 48 0.084 48.024 ;
    END
  END in_data[56]
  PIN in_data[57]
    DIRECTION INPUT ;
    USE SIGNAL ;
    PORT
      LAYER M4 ;
        RECT  0 48.048 0.084 48.072 ;
    END
  END in_data[57]
  PIN in_data[58]
    DIRECTION INPUT ;
    USE SIGNAL ;
    PORT
      LAYER M4 ;
        RECT  0 48.096 0.084 48.12 ;
    END
  END in_data[58]
  PIN in_data[59]
    DIRECTION INPUT ;
    USE SIGNAL ;
    PORT
      LAYER M4 ;
        RECT  0 48.144 0.084 48.168 ;
    END
  END in_data[59]
  PIN in_data[5]
    DIRECTION INPUT ;
    USE SIGNAL ;
    PORT
      LAYER M4 ;
        RECT  0 45.552 0.084 45.576 ;
    END
  END in_data[5]
  PIN in_data[60]
    DIRECTION INPUT ;
    USE SIGNAL ;
    PORT
      LAYER M4 ;
        RECT  0 48.192 0.084 48.216 ;
    END
  END in_data[60]
  PIN in_data[61]
    DIRECTION INPUT ;
    USE SIGNAL ;
    PORT
      LAYER M4 ;
        RECT  0 48.24 0.084 48.264 ;
    END
  END in_data[61]
  PIN in_data[62]
    DIRECTION INPUT ;
    USE SIGNAL ;
    PORT
      LAYER M4 ;
        RECT  0 48.288 0.084 48.312 ;
    END
  END in_data[62]
  PIN in_data[63]
    DIRECTION INPUT ;
    USE SIGNAL ;
    PORT
      LAYER M4 ;
        RECT  0 48.336 0.084 48.36 ;
    END
  END in_data[63]
  PIN in_data[64]
    DIRECTION INPUT ;
    USE SIGNAL ;
    PORT
      LAYER M4 ;
        RECT  0 48.384 0.084 48.408 ;
    END
  END in_data[64]
  PIN in_data[65]
    DIRECTION INPUT ;
    USE SIGNAL ;
    PORT
      LAYER M4 ;
        RECT  0 48.432 0.084 48.456 ;
    END
  END in_data[65]
  PIN in_data[66]
    DIRECTION INPUT ;
    USE SIGNAL ;
    PORT
      LAYER M4 ;
        RECT  0 48.48 0.084 48.504 ;
    END
  END in_data[66]
  PIN in_data[67]
    DIRECTION INPUT ;
    USE SIGNAL ;
    PORT
      LAYER M4 ;
        RECT  0 48.528 0.084 48.552 ;
    END
  END in_data[67]
  PIN in_data[68]
    DIRECTION INPUT ;
    USE SIGNAL ;
    PORT
      LAYER M4 ;
        RECT  0 48.576 0.084 48.6 ;
    END
  END in_data[68]
  PIN in_data[69]
    DIRECTION INPUT ;
    USE SIGNAL ;
    PORT
      LAYER M4 ;
        RECT  0 48.624 0.084 48.648 ;
    END
  END in_data[69]
  PIN in_data[6]
    DIRECTION INPUT ;
    USE SIGNAL ;
    PORT
      LAYER M4 ;
        RECT  0 45.6 0.084 45.624 ;
    END
  END in_data[6]
  PIN in_data[70]
    DIRECTION INPUT ;
    USE SIGNAL ;
    PORT
      LAYER M4 ;
        RECT  0 48.672 0.084 48.696 ;
    END
  END in_data[70]
  PIN in_data[71]
    DIRECTION INPUT ;
    USE SIGNAL ;
    PORT
      LAYER M4 ;
        RECT  0 48.72 0.084 48.744 ;
    END
  END in_data[71]
  PIN in_data[72]
    DIRECTION INPUT ;
    USE SIGNAL ;
    PORT
      LAYER M4 ;
        RECT  0 48.768 0.084 48.792 ;
    END
  END in_data[72]
  PIN in_data[73]
    DIRECTION INPUT ;
    USE SIGNAL ;
    PORT
      LAYER M4 ;
        RECT  0 48.816 0.084 48.84 ;
    END
  END in_data[73]
  PIN in_data[74]
    DIRECTION INPUT ;
    USE SIGNAL ;
    PORT
      LAYER M4 ;
        RECT  0 48.864 0.084 48.888 ;
    END
  END in_data[74]
  PIN in_data[75]
    DIRECTION INPUT ;
    USE SIGNAL ;
    PORT
      LAYER M4 ;
        RECT  0 48.912 0.084 48.936 ;
    END
  END in_data[75]
  PIN in_data[76]
    DIRECTION INPUT ;
    USE SIGNAL ;
    PORT
      LAYER M4 ;
        RECT  0 48.96 0.084 48.984 ;
    END
  END in_data[76]
  PIN in_data[77]
    DIRECTION INPUT ;
    USE SIGNAL ;
    PORT
      LAYER M4 ;
        RECT  0 49.008 0.084 49.032 ;
    END
  END in_data[77]
  PIN in_data[78]
    DIRECTION INPUT ;
    USE SIGNAL ;
    PORT
      LAYER M4 ;
        RECT  0 49.056 0.084 49.08 ;
    END
  END in_data[78]
  PIN in_data[79]
    DIRECTION INPUT ;
    USE SIGNAL ;
    PORT
      LAYER M4 ;
        RECT  0 49.104 0.084 49.128 ;
    END
  END in_data[79]
  PIN in_data[7]
    DIRECTION INPUT ;
    USE SIGNAL ;
    PORT
      LAYER M4 ;
        RECT  0 45.648 0.084 45.672 ;
    END
  END in_data[7]
  PIN in_data[80]
    DIRECTION INPUT ;
    USE SIGNAL ;
    PORT
      LAYER M4 ;
        RECT  0 49.152 0.084 49.176 ;
    END
  END in_data[80]
  PIN in_data[81]
    DIRECTION INPUT ;
    USE SIGNAL ;
    PORT
      LAYER M4 ;
        RECT  0 49.2 0.084 49.224 ;
    END
  END in_data[81]
  PIN in_data[82]
    DIRECTION INPUT ;
    USE SIGNAL ;
    PORT
      LAYER M4 ;
        RECT  0 49.248 0.084 49.272 ;
    END
  END in_data[82]
  PIN in_data[83]
    DIRECTION INPUT ;
    USE SIGNAL ;
    PORT
      LAYER M4 ;
        RECT  0 49.296 0.084 49.32 ;
    END
  END in_data[83]
  PIN in_data[84]
    DIRECTION INPUT ;
    USE SIGNAL ;
    PORT
      LAYER M4 ;
        RECT  0 49.344 0.084 49.368 ;
    END
  END in_data[84]
  PIN in_data[85]
    DIRECTION INPUT ;
    USE SIGNAL ;
    PORT
      LAYER M4 ;
        RECT  0 49.392 0.084 49.416 ;
    END
  END in_data[85]
  PIN in_data[86]
    DIRECTION INPUT ;
    USE SIGNAL ;
    PORT
      LAYER M4 ;
        RECT  0 49.44 0.084 49.464 ;
    END
  END in_data[86]
  PIN in_data[87]
    DIRECTION INPUT ;
    USE SIGNAL ;
    PORT
      LAYER M4 ;
        RECT  0 49.488 0.084 49.512 ;
    END
  END in_data[87]
  PIN in_data[88]
    DIRECTION INPUT ;
    USE SIGNAL ;
    PORT
      LAYER M4 ;
        RECT  0 49.536 0.084 49.56 ;
    END
  END in_data[88]
  PIN in_data[89]
    DIRECTION INPUT ;
    USE SIGNAL ;
    PORT
      LAYER M4 ;
        RECT  0 49.584 0.084 49.608 ;
    END
  END in_data[89]
  PIN in_data[8]
    DIRECTION INPUT ;
    USE SIGNAL ;
    PORT
      LAYER M4 ;
        RECT  0 45.696 0.084 45.72 ;
    END
  END in_data[8]
  PIN in_data[90]
    DIRECTION INPUT ;
    USE SIGNAL ;
    PORT
      LAYER M4 ;
        RECT  0 49.632 0.084 49.656 ;
    END
  END in_data[90]
  PIN in_data[91]
    DIRECTION INPUT ;
    USE SIGNAL ;
    PORT
      LAYER M4 ;
        RECT  0 49.68 0.084 49.704 ;
    END
  END in_data[91]
  PIN in_data[92]
    DIRECTION INPUT ;
    USE SIGNAL ;
    PORT
      LAYER M4 ;
        RECT  0 49.728 0.084 49.752 ;
    END
  END in_data[92]
  PIN in_data[93]
    DIRECTION INPUT ;
    USE SIGNAL ;
    PORT
      LAYER M4 ;
        RECT  0 49.776 0.084 49.8 ;
    END
  END in_data[93]
  PIN in_data[94]
    DIRECTION INPUT ;
    USE SIGNAL ;
    PORT
      LAYER M4 ;
        RECT  0 49.824 0.084 49.848 ;
    END
  END in_data[94]
  PIN in_data[95]
    DIRECTION INPUT ;
    USE SIGNAL ;
    PORT
      LAYER M4 ;
        RECT  0 49.872 0.084 49.896 ;
    END
  END in_data[95]
  PIN in_data[96]
    DIRECTION INPUT ;
    USE SIGNAL ;
    PORT
      LAYER M4 ;
        RECT  0 49.92 0.084 49.944 ;
    END
  END in_data[96]
  PIN in_data[97]
    DIRECTION INPUT ;
    USE SIGNAL ;
    PORT
      LAYER M4 ;
        RECT  0 49.968 0.084 49.992 ;
    END
  END in_data[97]
  PIN in_data[98]
    DIRECTION INPUT ;
    USE SIGNAL ;
    PORT
      LAYER M4 ;
        RECT  0 50.016 0.084 50.04 ;
    END
  END in_data[98]
  PIN in_data[99]
    DIRECTION INPUT ;
    USE SIGNAL ;
    PORT
      LAYER M4 ;
        RECT  0 50.064 0.084 50.088 ;
    END
  END in_data[99]
  PIN in_data[9]
    DIRECTION INPUT ;
    USE SIGNAL ;
    PORT
      LAYER M4 ;
        RECT  0 45.744 0.084 45.768 ;
    END
  END in_data[9]
  PIN in_last
    DIRECTION INPUT ;
    USE SIGNAL ;
    PORT
      LAYER M4 ;
        RECT  0 69.888 0.084 69.912 ;
    END
  END in_last
  PIN in_ready
    DIRECTION OUTPUT ;
    USE SIGNAL ;
    PORT
      LAYER M4 ;
        RECT  0 69.936 0.084 69.96 ;
    END
  END in_ready
  PIN in_valid
    DIRECTION INPUT ;
    USE SIGNAL ;
    PORT
      LAYER M4 ;
        RECT  0 69.984 0.084 70.008 ;
    END
  END in_valid
  PIN kv_base[0]
    DIRECTION OUTPUT ;
    USE SIGNAL ;
    PORT
      LAYER M5 ;
        RECT  70.176 139.916 70.2 140 ;
    END
  END kv_base[0]
  PIN kv_base[10]
    DIRECTION OUTPUT ;
    USE SIGNAL ;
    PORT
      LAYER M5 ;
        RECT  70.656 139.916 70.68 140 ;
    END
  END kv_base[10]
  PIN kv_base[11]
    DIRECTION OUTPUT ;
    USE SIGNAL ;
    PORT
      LAYER M5 ;
        RECT  70.704 139.916 70.728 140 ;
    END
  END kv_base[11]
  PIN kv_base[12]
    DIRECTION OUTPUT ;
    USE SIGNAL ;
    PORT
      LAYER M5 ;
        RECT  70.752 139.916 70.776 140 ;
    END
  END kv_base[12]
  PIN kv_base[13]
    DIRECTION OUTPUT ;
    USE SIGNAL ;
    PORT
      LAYER M5 ;
        RECT  70.8 139.916 70.824 140 ;
    END
  END kv_base[13]
  PIN kv_base[14]
    DIRECTION OUTPUT ;
    USE SIGNAL ;
    PORT
      LAYER M5 ;
        RECT  70.848 139.916 70.872 140 ;
    END
  END kv_base[14]
  PIN kv_base[15]
    DIRECTION OUTPUT ;
    USE SIGNAL ;
    PORT
      LAYER M5 ;
        RECT  70.896 139.916 70.92 140 ;
    END
  END kv_base[15]
  PIN kv_base[16]
    DIRECTION OUTPUT ;
    USE SIGNAL ;
    PORT
      LAYER M5 ;
        RECT  70.944 139.916 70.968 140 ;
    END
  END kv_base[16]
  PIN kv_base[17]
    DIRECTION OUTPUT ;
    USE SIGNAL ;
    PORT
      LAYER M5 ;
        RECT  70.992 139.916 71.016 140 ;
    END
  END kv_base[17]
  PIN kv_base[18]
    DIRECTION OUTPUT ;
    USE SIGNAL ;
    PORT
      LAYER M5 ;
        RECT  71.04 139.916 71.064 140 ;
    END
  END kv_base[18]
  PIN kv_base[19]
    DIRECTION OUTPUT ;
    USE SIGNAL ;
    PORT
      LAYER M5 ;
        RECT  71.088 139.916 71.112 140 ;
    END
  END kv_base[19]
  PIN kv_base[1]
    DIRECTION OUTPUT ;
    USE SIGNAL ;
    PORT
      LAYER M5 ;
        RECT  70.224 139.916 70.248 140 ;
    END
  END kv_base[1]
  PIN kv_base[20]
    DIRECTION OUTPUT ;
    USE SIGNAL ;
    PORT
      LAYER M5 ;
        RECT  71.136 139.916 71.16 140 ;
    END
  END kv_base[20]
  PIN kv_base[21]
    DIRECTION OUTPUT ;
    USE SIGNAL ;
    PORT
      LAYER M5 ;
        RECT  71.184 139.916 71.208 140 ;
    END
  END kv_base[21]
  PIN kv_base[22]
    DIRECTION OUTPUT ;
    USE SIGNAL ;
    PORT
      LAYER M5 ;
        RECT  71.232 139.916 71.256 140 ;
    END
  END kv_base[22]
  PIN kv_base[23]
    DIRECTION OUTPUT ;
    USE SIGNAL ;
    PORT
      LAYER M5 ;
        RECT  71.28 139.916 71.304 140 ;
    END
  END kv_base[23]
  PIN kv_base[2]
    DIRECTION OUTPUT ;
    USE SIGNAL ;
    PORT
      LAYER M5 ;
        RECT  70.272 139.916 70.296 140 ;
    END
  END kv_base[2]
  PIN kv_base[3]
    DIRECTION OUTPUT ;
    USE SIGNAL ;
    PORT
      LAYER M5 ;
        RECT  70.32 139.916 70.344 140 ;
    END
  END kv_base[3]
  PIN kv_base[4]
    DIRECTION OUTPUT ;
    USE SIGNAL ;
    PORT
      LAYER M5 ;
        RECT  70.368 139.916 70.392 140 ;
    END
  END kv_base[4]
  PIN kv_base[5]
    DIRECTION OUTPUT ;
    USE SIGNAL ;
    PORT
      LAYER M5 ;
        RECT  70.416 139.916 70.44 140 ;
    END
  END kv_base[5]
  PIN kv_base[6]
    DIRECTION OUTPUT ;
    USE SIGNAL ;
    PORT
      LAYER M5 ;
        RECT  70.464 139.916 70.488 140 ;
    END
  END kv_base[6]
  PIN kv_base[7]
    DIRECTION OUTPUT ;
    USE SIGNAL ;
    PORT
      LAYER M5 ;
        RECT  70.512 139.916 70.536 140 ;
    END
  END kv_base[7]
  PIN kv_base[8]
    DIRECTION OUTPUT ;
    USE SIGNAL ;
    PORT
      LAYER M5 ;
        RECT  70.56 139.916 70.584 140 ;
    END
  END kv_base[8]
  PIN kv_base[9]
    DIRECTION OUTPUT ;
    USE SIGNAL ;
    PORT
      LAYER M5 ;
        RECT  70.608 139.916 70.632 140 ;
    END
  END kv_base[9]
  PIN out_data[0]
    DIRECTION OUTPUT ;
    USE SIGNAL ;
    PORT
      LAYER M4 ;
        RECT  0 70.032 0.084 70.056 ;
    END
  END out_data[0]
  PIN out_data[100]
    DIRECTION OUTPUT ;
    USE SIGNAL ;
    PORT
      LAYER M4 ;
        RECT  0 74.832 0.084 74.856 ;
    END
  END out_data[100]
  PIN out_data[101]
    DIRECTION OUTPUT ;
    USE SIGNAL ;
    PORT
      LAYER M4 ;
        RECT  0 74.88 0.084 74.904 ;
    END
  END out_data[101]
  PIN out_data[102]
    DIRECTION OUTPUT ;
    USE SIGNAL ;
    PORT
      LAYER M4 ;
        RECT  0 74.928 0.084 74.952 ;
    END
  END out_data[102]
  PIN out_data[103]
    DIRECTION OUTPUT ;
    USE SIGNAL ;
    PORT
      LAYER M4 ;
        RECT  0 74.976 0.084 75 ;
    END
  END out_data[103]
  PIN out_data[104]
    DIRECTION OUTPUT ;
    USE SIGNAL ;
    PORT
      LAYER M4 ;
        RECT  0 75.024 0.084 75.048 ;
    END
  END out_data[104]
  PIN out_data[105]
    DIRECTION OUTPUT ;
    USE SIGNAL ;
    PORT
      LAYER M4 ;
        RECT  0 75.072 0.084 75.096 ;
    END
  END out_data[105]
  PIN out_data[106]
    DIRECTION OUTPUT ;
    USE SIGNAL ;
    PORT
      LAYER M4 ;
        RECT  0 75.12 0.084 75.144 ;
    END
  END out_data[106]
  PIN out_data[107]
    DIRECTION OUTPUT ;
    USE SIGNAL ;
    PORT
      LAYER M4 ;
        RECT  0 75.168 0.084 75.192 ;
    END
  END out_data[107]
  PIN out_data[108]
    DIRECTION OUTPUT ;
    USE SIGNAL ;
    PORT
      LAYER M4 ;
        RECT  0 75.216 0.084 75.24 ;
    END
  END out_data[108]
  PIN out_data[109]
    DIRECTION OUTPUT ;
    USE SIGNAL ;
    PORT
      LAYER M4 ;
        RECT  0 75.264 0.084 75.288 ;
    END
  END out_data[109]
  PIN out_data[10]
    DIRECTION OUTPUT ;
    USE SIGNAL ;
    PORT
      LAYER M4 ;
        RECT  0 70.512 0.084 70.536 ;
    END
  END out_data[10]
  PIN out_data[110]
    DIRECTION OUTPUT ;
    USE SIGNAL ;
    PORT
      LAYER M4 ;
        RECT  0 75.312 0.084 75.336 ;
    END
  END out_data[110]
  PIN out_data[111]
    DIRECTION OUTPUT ;
    USE SIGNAL ;
    PORT
      LAYER M4 ;
        RECT  0 75.36 0.084 75.384 ;
    END
  END out_data[111]
  PIN out_data[112]
    DIRECTION OUTPUT ;
    USE SIGNAL ;
    PORT
      LAYER M4 ;
        RECT  0 75.408 0.084 75.432 ;
    END
  END out_data[112]
  PIN out_data[113]
    DIRECTION OUTPUT ;
    USE SIGNAL ;
    PORT
      LAYER M4 ;
        RECT  0 75.456 0.084 75.48 ;
    END
  END out_data[113]
  PIN out_data[114]
    DIRECTION OUTPUT ;
    USE SIGNAL ;
    PORT
      LAYER M4 ;
        RECT  0 75.504 0.084 75.528 ;
    END
  END out_data[114]
  PIN out_data[115]
    DIRECTION OUTPUT ;
    USE SIGNAL ;
    PORT
      LAYER M4 ;
        RECT  0 75.552 0.084 75.576 ;
    END
  END out_data[115]
  PIN out_data[116]
    DIRECTION OUTPUT ;
    USE SIGNAL ;
    PORT
      LAYER M4 ;
        RECT  0 75.6 0.084 75.624 ;
    END
  END out_data[116]
  PIN out_data[117]
    DIRECTION OUTPUT ;
    USE SIGNAL ;
    PORT
      LAYER M4 ;
        RECT  0 75.648 0.084 75.672 ;
    END
  END out_data[117]
  PIN out_data[118]
    DIRECTION OUTPUT ;
    USE SIGNAL ;
    PORT
      LAYER M4 ;
        RECT  0 75.696 0.084 75.72 ;
    END
  END out_data[118]
  PIN out_data[119]
    DIRECTION OUTPUT ;
    USE SIGNAL ;
    PORT
      LAYER M4 ;
        RECT  0 75.744 0.084 75.768 ;
    END
  END out_data[119]
  PIN out_data[11]
    DIRECTION OUTPUT ;
    USE SIGNAL ;
    PORT
      LAYER M4 ;
        RECT  0 70.56 0.084 70.584 ;
    END
  END out_data[11]
  PIN out_data[120]
    DIRECTION OUTPUT ;
    USE SIGNAL ;
    PORT
      LAYER M4 ;
        RECT  0 75.792 0.084 75.816 ;
    END
  END out_data[120]
  PIN out_data[121]
    DIRECTION OUTPUT ;
    USE SIGNAL ;
    PORT
      LAYER M4 ;
        RECT  0 75.84 0.084 75.864 ;
    END
  END out_data[121]
  PIN out_data[122]
    DIRECTION OUTPUT ;
    USE SIGNAL ;
    PORT
      LAYER M4 ;
        RECT  0 75.888 0.084 75.912 ;
    END
  END out_data[122]
  PIN out_data[123]
    DIRECTION OUTPUT ;
    USE SIGNAL ;
    PORT
      LAYER M4 ;
        RECT  0 75.936 0.084 75.96 ;
    END
  END out_data[123]
  PIN out_data[124]
    DIRECTION OUTPUT ;
    USE SIGNAL ;
    PORT
      LAYER M4 ;
        RECT  0 75.984 0.084 76.008 ;
    END
  END out_data[124]
  PIN out_data[125]
    DIRECTION OUTPUT ;
    USE SIGNAL ;
    PORT
      LAYER M4 ;
        RECT  0 76.032 0.084 76.056 ;
    END
  END out_data[125]
  PIN out_data[126]
    DIRECTION OUTPUT ;
    USE SIGNAL ;
    PORT
      LAYER M4 ;
        RECT  0 76.08 0.084 76.104 ;
    END
  END out_data[126]
  PIN out_data[127]
    DIRECTION OUTPUT ;
    USE SIGNAL ;
    PORT
      LAYER M4 ;
        RECT  0 76.128 0.084 76.152 ;
    END
  END out_data[127]
  PIN out_data[128]
    DIRECTION OUTPUT ;
    USE SIGNAL ;
    PORT
      LAYER M4 ;
        RECT  0 76.176 0.084 76.2 ;
    END
  END out_data[128]
  PIN out_data[129]
    DIRECTION OUTPUT ;
    USE SIGNAL ;
    PORT
      LAYER M4 ;
        RECT  0 76.224 0.084 76.248 ;
    END
  END out_data[129]
  PIN out_data[12]
    DIRECTION OUTPUT ;
    USE SIGNAL ;
    PORT
      LAYER M4 ;
        RECT  0 70.608 0.084 70.632 ;
    END
  END out_data[12]
  PIN out_data[130]
    DIRECTION OUTPUT ;
    USE SIGNAL ;
    PORT
      LAYER M4 ;
        RECT  0 76.272 0.084 76.296 ;
    END
  END out_data[130]
  PIN out_data[131]
    DIRECTION OUTPUT ;
    USE SIGNAL ;
    PORT
      LAYER M4 ;
        RECT  0 76.32 0.084 76.344 ;
    END
  END out_data[131]
  PIN out_data[132]
    DIRECTION OUTPUT ;
    USE SIGNAL ;
    PORT
      LAYER M4 ;
        RECT  0 76.368 0.084 76.392 ;
    END
  END out_data[132]
  PIN out_data[133]
    DIRECTION OUTPUT ;
    USE SIGNAL ;
    PORT
      LAYER M4 ;
        RECT  0 76.416 0.084 76.44 ;
    END
  END out_data[133]
  PIN out_data[134]
    DIRECTION OUTPUT ;
    USE SIGNAL ;
    PORT
      LAYER M4 ;
        RECT  0 76.464 0.084 76.488 ;
    END
  END out_data[134]
  PIN out_data[135]
    DIRECTION OUTPUT ;
    USE SIGNAL ;
    PORT
      LAYER M4 ;
        RECT  0 76.512 0.084 76.536 ;
    END
  END out_data[135]
  PIN out_data[136]
    DIRECTION OUTPUT ;
    USE SIGNAL ;
    PORT
      LAYER M4 ;
        RECT  0 76.56 0.084 76.584 ;
    END
  END out_data[136]
  PIN out_data[137]
    DIRECTION OUTPUT ;
    USE SIGNAL ;
    PORT
      LAYER M4 ;
        RECT  0 76.608 0.084 76.632 ;
    END
  END out_data[137]
  PIN out_data[138]
    DIRECTION OUTPUT ;
    USE SIGNAL ;
    PORT
      LAYER M4 ;
        RECT  0 76.656 0.084 76.68 ;
    END
  END out_data[138]
  PIN out_data[139]
    DIRECTION OUTPUT ;
    USE SIGNAL ;
    PORT
      LAYER M4 ;
        RECT  0 76.704 0.084 76.728 ;
    END
  END out_data[139]
  PIN out_data[13]
    DIRECTION OUTPUT ;
    USE SIGNAL ;
    PORT
      LAYER M4 ;
        RECT  0 70.656 0.084 70.68 ;
    END
  END out_data[13]
  PIN out_data[140]
    DIRECTION OUTPUT ;
    USE SIGNAL ;
    PORT
      LAYER M4 ;
        RECT  0 76.752 0.084 76.776 ;
    END
  END out_data[140]
  PIN out_data[141]
    DIRECTION OUTPUT ;
    USE SIGNAL ;
    PORT
      LAYER M4 ;
        RECT  0 76.8 0.084 76.824 ;
    END
  END out_data[141]
  PIN out_data[142]
    DIRECTION OUTPUT ;
    USE SIGNAL ;
    PORT
      LAYER M4 ;
        RECT  0 76.848 0.084 76.872 ;
    END
  END out_data[142]
  PIN out_data[143]
    DIRECTION OUTPUT ;
    USE SIGNAL ;
    PORT
      LAYER M4 ;
        RECT  0 76.896 0.084 76.92 ;
    END
  END out_data[143]
  PIN out_data[144]
    DIRECTION OUTPUT ;
    USE SIGNAL ;
    PORT
      LAYER M4 ;
        RECT  0 76.944 0.084 76.968 ;
    END
  END out_data[144]
  PIN out_data[145]
    DIRECTION OUTPUT ;
    USE SIGNAL ;
    PORT
      LAYER M4 ;
        RECT  0 76.992 0.084 77.016 ;
    END
  END out_data[145]
  PIN out_data[146]
    DIRECTION OUTPUT ;
    USE SIGNAL ;
    PORT
      LAYER M4 ;
        RECT  0 77.04 0.084 77.064 ;
    END
  END out_data[146]
  PIN out_data[147]
    DIRECTION OUTPUT ;
    USE SIGNAL ;
    PORT
      LAYER M4 ;
        RECT  0 77.088 0.084 77.112 ;
    END
  END out_data[147]
  PIN out_data[148]
    DIRECTION OUTPUT ;
    USE SIGNAL ;
    PORT
      LAYER M4 ;
        RECT  0 77.136 0.084 77.16 ;
    END
  END out_data[148]
  PIN out_data[149]
    DIRECTION OUTPUT ;
    USE SIGNAL ;
    PORT
      LAYER M4 ;
        RECT  0 77.184 0.084 77.208 ;
    END
  END out_data[149]
  PIN out_data[14]
    DIRECTION OUTPUT ;
    USE SIGNAL ;
    PORT
      LAYER M4 ;
        RECT  0 70.704 0.084 70.728 ;
    END
  END out_data[14]
  PIN out_data[150]
    DIRECTION OUTPUT ;
    USE SIGNAL ;
    PORT
      LAYER M4 ;
        RECT  0 77.232 0.084 77.256 ;
    END
  END out_data[150]
  PIN out_data[151]
    DIRECTION OUTPUT ;
    USE SIGNAL ;
    PORT
      LAYER M4 ;
        RECT  0 77.28 0.084 77.304 ;
    END
  END out_data[151]
  PIN out_data[152]
    DIRECTION OUTPUT ;
    USE SIGNAL ;
    PORT
      LAYER M4 ;
        RECT  0 77.328 0.084 77.352 ;
    END
  END out_data[152]
  PIN out_data[153]
    DIRECTION OUTPUT ;
    USE SIGNAL ;
    PORT
      LAYER M4 ;
        RECT  0 77.376 0.084 77.4 ;
    END
  END out_data[153]
  PIN out_data[154]
    DIRECTION OUTPUT ;
    USE SIGNAL ;
    PORT
      LAYER M4 ;
        RECT  0 77.424 0.084 77.448 ;
    END
  END out_data[154]
  PIN out_data[155]
    DIRECTION OUTPUT ;
    USE SIGNAL ;
    PORT
      LAYER M4 ;
        RECT  0 77.472 0.084 77.496 ;
    END
  END out_data[155]
  PIN out_data[156]
    DIRECTION OUTPUT ;
    USE SIGNAL ;
    PORT
      LAYER M4 ;
        RECT  0 77.52 0.084 77.544 ;
    END
  END out_data[156]
  PIN out_data[157]
    DIRECTION OUTPUT ;
    USE SIGNAL ;
    PORT
      LAYER M4 ;
        RECT  0 77.568 0.084 77.592 ;
    END
  END out_data[157]
  PIN out_data[158]
    DIRECTION OUTPUT ;
    USE SIGNAL ;
    PORT
      LAYER M4 ;
        RECT  0 77.616 0.084 77.64 ;
    END
  END out_data[158]
  PIN out_data[159]
    DIRECTION OUTPUT ;
    USE SIGNAL ;
    PORT
      LAYER M4 ;
        RECT  0 77.664 0.084 77.688 ;
    END
  END out_data[159]
  PIN out_data[15]
    DIRECTION OUTPUT ;
    USE SIGNAL ;
    PORT
      LAYER M4 ;
        RECT  0 70.752 0.084 70.776 ;
    END
  END out_data[15]
  PIN out_data[160]
    DIRECTION OUTPUT ;
    USE SIGNAL ;
    PORT
      LAYER M4 ;
        RECT  0 77.712 0.084 77.736 ;
    END
  END out_data[160]
  PIN out_data[161]
    DIRECTION OUTPUT ;
    USE SIGNAL ;
    PORT
      LAYER M4 ;
        RECT  0 77.76 0.084 77.784 ;
    END
  END out_data[161]
  PIN out_data[162]
    DIRECTION OUTPUT ;
    USE SIGNAL ;
    PORT
      LAYER M4 ;
        RECT  0 77.808 0.084 77.832 ;
    END
  END out_data[162]
  PIN out_data[163]
    DIRECTION OUTPUT ;
    USE SIGNAL ;
    PORT
      LAYER M4 ;
        RECT  0 77.856 0.084 77.88 ;
    END
  END out_data[163]
  PIN out_data[164]
    DIRECTION OUTPUT ;
    USE SIGNAL ;
    PORT
      LAYER M4 ;
        RECT  0 77.904 0.084 77.928 ;
    END
  END out_data[164]
  PIN out_data[165]
    DIRECTION OUTPUT ;
    USE SIGNAL ;
    PORT
      LAYER M4 ;
        RECT  0 77.952 0.084 77.976 ;
    END
  END out_data[165]
  PIN out_data[166]
    DIRECTION OUTPUT ;
    USE SIGNAL ;
    PORT
      LAYER M4 ;
        RECT  0 78 0.084 78.024 ;
    END
  END out_data[166]
  PIN out_data[167]
    DIRECTION OUTPUT ;
    USE SIGNAL ;
    PORT
      LAYER M4 ;
        RECT  0 78.048 0.084 78.072 ;
    END
  END out_data[167]
  PIN out_data[168]
    DIRECTION OUTPUT ;
    USE SIGNAL ;
    PORT
      LAYER M4 ;
        RECT  0 78.096 0.084 78.12 ;
    END
  END out_data[168]
  PIN out_data[169]
    DIRECTION OUTPUT ;
    USE SIGNAL ;
    PORT
      LAYER M4 ;
        RECT  0 78.144 0.084 78.168 ;
    END
  END out_data[169]
  PIN out_data[16]
    DIRECTION OUTPUT ;
    USE SIGNAL ;
    PORT
      LAYER M4 ;
        RECT  0 70.8 0.084 70.824 ;
    END
  END out_data[16]
  PIN out_data[170]
    DIRECTION OUTPUT ;
    USE SIGNAL ;
    PORT
      LAYER M4 ;
        RECT  0 78.192 0.084 78.216 ;
    END
  END out_data[170]
  PIN out_data[171]
    DIRECTION OUTPUT ;
    USE SIGNAL ;
    PORT
      LAYER M4 ;
        RECT  0 78.24 0.084 78.264 ;
    END
  END out_data[171]
  PIN out_data[172]
    DIRECTION OUTPUT ;
    USE SIGNAL ;
    PORT
      LAYER M4 ;
        RECT  0 78.288 0.084 78.312 ;
    END
  END out_data[172]
  PIN out_data[173]
    DIRECTION OUTPUT ;
    USE SIGNAL ;
    PORT
      LAYER M4 ;
        RECT  0 78.336 0.084 78.36 ;
    END
  END out_data[173]
  PIN out_data[174]
    DIRECTION OUTPUT ;
    USE SIGNAL ;
    PORT
      LAYER M4 ;
        RECT  0 78.384 0.084 78.408 ;
    END
  END out_data[174]
  PIN out_data[175]
    DIRECTION OUTPUT ;
    USE SIGNAL ;
    PORT
      LAYER M4 ;
        RECT  0 78.432 0.084 78.456 ;
    END
  END out_data[175]
  PIN out_data[176]
    DIRECTION OUTPUT ;
    USE SIGNAL ;
    PORT
      LAYER M4 ;
        RECT  0 78.48 0.084 78.504 ;
    END
  END out_data[176]
  PIN out_data[177]
    DIRECTION OUTPUT ;
    USE SIGNAL ;
    PORT
      LAYER M4 ;
        RECT  0 78.528 0.084 78.552 ;
    END
  END out_data[177]
  PIN out_data[178]
    DIRECTION OUTPUT ;
    USE SIGNAL ;
    PORT
      LAYER M4 ;
        RECT  0 78.576 0.084 78.6 ;
    END
  END out_data[178]
  PIN out_data[179]
    DIRECTION OUTPUT ;
    USE SIGNAL ;
    PORT
      LAYER M4 ;
        RECT  0 78.624 0.084 78.648 ;
    END
  END out_data[179]
  PIN out_data[17]
    DIRECTION OUTPUT ;
    USE SIGNAL ;
    PORT
      LAYER M4 ;
        RECT  0 70.848 0.084 70.872 ;
    END
  END out_data[17]
  PIN out_data[180]
    DIRECTION OUTPUT ;
    USE SIGNAL ;
    PORT
      LAYER M4 ;
        RECT  0 78.672 0.084 78.696 ;
    END
  END out_data[180]
  PIN out_data[181]
    DIRECTION OUTPUT ;
    USE SIGNAL ;
    PORT
      LAYER M4 ;
        RECT  0 78.72 0.084 78.744 ;
    END
  END out_data[181]
  PIN out_data[182]
    DIRECTION OUTPUT ;
    USE SIGNAL ;
    PORT
      LAYER M4 ;
        RECT  0 78.768 0.084 78.792 ;
    END
  END out_data[182]
  PIN out_data[183]
    DIRECTION OUTPUT ;
    USE SIGNAL ;
    PORT
      LAYER M4 ;
        RECT  0 78.816 0.084 78.84 ;
    END
  END out_data[183]
  PIN out_data[184]
    DIRECTION OUTPUT ;
    USE SIGNAL ;
    PORT
      LAYER M4 ;
        RECT  0 78.864 0.084 78.888 ;
    END
  END out_data[184]
  PIN out_data[185]
    DIRECTION OUTPUT ;
    USE SIGNAL ;
    PORT
      LAYER M4 ;
        RECT  0 78.912 0.084 78.936 ;
    END
  END out_data[185]
  PIN out_data[186]
    DIRECTION OUTPUT ;
    USE SIGNAL ;
    PORT
      LAYER M4 ;
        RECT  0 78.96 0.084 78.984 ;
    END
  END out_data[186]
  PIN out_data[187]
    DIRECTION OUTPUT ;
    USE SIGNAL ;
    PORT
      LAYER M4 ;
        RECT  0 79.008 0.084 79.032 ;
    END
  END out_data[187]
  PIN out_data[188]
    DIRECTION OUTPUT ;
    USE SIGNAL ;
    PORT
      LAYER M4 ;
        RECT  0 79.056 0.084 79.08 ;
    END
  END out_data[188]
  PIN out_data[189]
    DIRECTION OUTPUT ;
    USE SIGNAL ;
    PORT
      LAYER M4 ;
        RECT  0 79.104 0.084 79.128 ;
    END
  END out_data[189]
  PIN out_data[18]
    DIRECTION OUTPUT ;
    USE SIGNAL ;
    PORT
      LAYER M4 ;
        RECT  0 70.896 0.084 70.92 ;
    END
  END out_data[18]
  PIN out_data[190]
    DIRECTION OUTPUT ;
    USE SIGNAL ;
    PORT
      LAYER M4 ;
        RECT  0 79.152 0.084 79.176 ;
    END
  END out_data[190]
  PIN out_data[191]
    DIRECTION OUTPUT ;
    USE SIGNAL ;
    PORT
      LAYER M4 ;
        RECT  0 79.2 0.084 79.224 ;
    END
  END out_data[191]
  PIN out_data[192]
    DIRECTION OUTPUT ;
    USE SIGNAL ;
    PORT
      LAYER M4 ;
        RECT  0 79.248 0.084 79.272 ;
    END
  END out_data[192]
  PIN out_data[193]
    DIRECTION OUTPUT ;
    USE SIGNAL ;
    PORT
      LAYER M4 ;
        RECT  0 79.296 0.084 79.32 ;
    END
  END out_data[193]
  PIN out_data[194]
    DIRECTION OUTPUT ;
    USE SIGNAL ;
    PORT
      LAYER M4 ;
        RECT  0 79.344 0.084 79.368 ;
    END
  END out_data[194]
  PIN out_data[195]
    DIRECTION OUTPUT ;
    USE SIGNAL ;
    PORT
      LAYER M4 ;
        RECT  0 79.392 0.084 79.416 ;
    END
  END out_data[195]
  PIN out_data[196]
    DIRECTION OUTPUT ;
    USE SIGNAL ;
    PORT
      LAYER M4 ;
        RECT  0 79.44 0.084 79.464 ;
    END
  END out_data[196]
  PIN out_data[197]
    DIRECTION OUTPUT ;
    USE SIGNAL ;
    PORT
      LAYER M4 ;
        RECT  0 79.488 0.084 79.512 ;
    END
  END out_data[197]
  PIN out_data[198]
    DIRECTION OUTPUT ;
    USE SIGNAL ;
    PORT
      LAYER M4 ;
        RECT  0 79.536 0.084 79.56 ;
    END
  END out_data[198]
  PIN out_data[199]
    DIRECTION OUTPUT ;
    USE SIGNAL ;
    PORT
      LAYER M4 ;
        RECT  0 79.584 0.084 79.608 ;
    END
  END out_data[199]
  PIN out_data[19]
    DIRECTION OUTPUT ;
    USE SIGNAL ;
    PORT
      LAYER M4 ;
        RECT  0 70.944 0.084 70.968 ;
    END
  END out_data[19]
  PIN out_data[1]
    DIRECTION OUTPUT ;
    USE SIGNAL ;
    PORT
      LAYER M4 ;
        RECT  0 70.08 0.084 70.104 ;
    END
  END out_data[1]
  PIN out_data[200]
    DIRECTION OUTPUT ;
    USE SIGNAL ;
    PORT
      LAYER M4 ;
        RECT  0 79.632 0.084 79.656 ;
    END
  END out_data[200]
  PIN out_data[201]
    DIRECTION OUTPUT ;
    USE SIGNAL ;
    PORT
      LAYER M4 ;
        RECT  0 79.68 0.084 79.704 ;
    END
  END out_data[201]
  PIN out_data[202]
    DIRECTION OUTPUT ;
    USE SIGNAL ;
    PORT
      LAYER M4 ;
        RECT  0 79.728 0.084 79.752 ;
    END
  END out_data[202]
  PIN out_data[203]
    DIRECTION OUTPUT ;
    USE SIGNAL ;
    PORT
      LAYER M4 ;
        RECT  0 79.776 0.084 79.8 ;
    END
  END out_data[203]
  PIN out_data[204]
    DIRECTION OUTPUT ;
    USE SIGNAL ;
    PORT
      LAYER M4 ;
        RECT  0 79.824 0.084 79.848 ;
    END
  END out_data[204]
  PIN out_data[205]
    DIRECTION OUTPUT ;
    USE SIGNAL ;
    PORT
      LAYER M4 ;
        RECT  0 79.872 0.084 79.896 ;
    END
  END out_data[205]
  PIN out_data[206]
    DIRECTION OUTPUT ;
    USE SIGNAL ;
    PORT
      LAYER M4 ;
        RECT  0 79.92 0.084 79.944 ;
    END
  END out_data[206]
  PIN out_data[207]
    DIRECTION OUTPUT ;
    USE SIGNAL ;
    PORT
      LAYER M4 ;
        RECT  0 79.968 0.084 79.992 ;
    END
  END out_data[207]
  PIN out_data[208]
    DIRECTION OUTPUT ;
    USE SIGNAL ;
    PORT
      LAYER M4 ;
        RECT  0 80.016 0.084 80.04 ;
    END
  END out_data[208]
  PIN out_data[209]
    DIRECTION OUTPUT ;
    USE SIGNAL ;
    PORT
      LAYER M4 ;
        RECT  0 80.064 0.084 80.088 ;
    END
  END out_data[209]
  PIN out_data[20]
    DIRECTION OUTPUT ;
    USE SIGNAL ;
    PORT
      LAYER M4 ;
        RECT  0 70.992 0.084 71.016 ;
    END
  END out_data[20]
  PIN out_data[210]
    DIRECTION OUTPUT ;
    USE SIGNAL ;
    PORT
      LAYER M4 ;
        RECT  0 80.112 0.084 80.136 ;
    END
  END out_data[210]
  PIN out_data[211]
    DIRECTION OUTPUT ;
    USE SIGNAL ;
    PORT
      LAYER M4 ;
        RECT  0 80.16 0.084 80.184 ;
    END
  END out_data[211]
  PIN out_data[212]
    DIRECTION OUTPUT ;
    USE SIGNAL ;
    PORT
      LAYER M4 ;
        RECT  0 80.208 0.084 80.232 ;
    END
  END out_data[212]
  PIN out_data[213]
    DIRECTION OUTPUT ;
    USE SIGNAL ;
    PORT
      LAYER M4 ;
        RECT  0 80.256 0.084 80.28 ;
    END
  END out_data[213]
  PIN out_data[214]
    DIRECTION OUTPUT ;
    USE SIGNAL ;
    PORT
      LAYER M4 ;
        RECT  0 80.304 0.084 80.328 ;
    END
  END out_data[214]
  PIN out_data[215]
    DIRECTION OUTPUT ;
    USE SIGNAL ;
    PORT
      LAYER M4 ;
        RECT  0 80.352 0.084 80.376 ;
    END
  END out_data[215]
  PIN out_data[216]
    DIRECTION OUTPUT ;
    USE SIGNAL ;
    PORT
      LAYER M4 ;
        RECT  0 80.4 0.084 80.424 ;
    END
  END out_data[216]
  PIN out_data[217]
    DIRECTION OUTPUT ;
    USE SIGNAL ;
    PORT
      LAYER M4 ;
        RECT  0 80.448 0.084 80.472 ;
    END
  END out_data[217]
  PIN out_data[218]
    DIRECTION OUTPUT ;
    USE SIGNAL ;
    PORT
      LAYER M4 ;
        RECT  0 80.496 0.084 80.52 ;
    END
  END out_data[218]
  PIN out_data[219]
    DIRECTION OUTPUT ;
    USE SIGNAL ;
    PORT
      LAYER M4 ;
        RECT  0 80.544 0.084 80.568 ;
    END
  END out_data[219]
  PIN out_data[21]
    DIRECTION OUTPUT ;
    USE SIGNAL ;
    PORT
      LAYER M4 ;
        RECT  0 71.04 0.084 71.064 ;
    END
  END out_data[21]
  PIN out_data[220]
    DIRECTION OUTPUT ;
    USE SIGNAL ;
    PORT
      LAYER M4 ;
        RECT  0 80.592 0.084 80.616 ;
    END
  END out_data[220]
  PIN out_data[221]
    DIRECTION OUTPUT ;
    USE SIGNAL ;
    PORT
      LAYER M4 ;
        RECT  0 80.64 0.084 80.664 ;
    END
  END out_data[221]
  PIN out_data[222]
    DIRECTION OUTPUT ;
    USE SIGNAL ;
    PORT
      LAYER M4 ;
        RECT  0 80.688 0.084 80.712 ;
    END
  END out_data[222]
  PIN out_data[223]
    DIRECTION OUTPUT ;
    USE SIGNAL ;
    PORT
      LAYER M4 ;
        RECT  0 80.736 0.084 80.76 ;
    END
  END out_data[223]
  PIN out_data[224]
    DIRECTION OUTPUT ;
    USE SIGNAL ;
    PORT
      LAYER M4 ;
        RECT  0 80.784 0.084 80.808 ;
    END
  END out_data[224]
  PIN out_data[225]
    DIRECTION OUTPUT ;
    USE SIGNAL ;
    PORT
      LAYER M4 ;
        RECT  0 80.832 0.084 80.856 ;
    END
  END out_data[225]
  PIN out_data[226]
    DIRECTION OUTPUT ;
    USE SIGNAL ;
    PORT
      LAYER M4 ;
        RECT  0 80.88 0.084 80.904 ;
    END
  END out_data[226]
  PIN out_data[227]
    DIRECTION OUTPUT ;
    USE SIGNAL ;
    PORT
      LAYER M4 ;
        RECT  0 80.928 0.084 80.952 ;
    END
  END out_data[227]
  PIN out_data[228]
    DIRECTION OUTPUT ;
    USE SIGNAL ;
    PORT
      LAYER M4 ;
        RECT  0 80.976 0.084 81 ;
    END
  END out_data[228]
  PIN out_data[229]
    DIRECTION OUTPUT ;
    USE SIGNAL ;
    PORT
      LAYER M4 ;
        RECT  0 81.024 0.084 81.048 ;
    END
  END out_data[229]
  PIN out_data[22]
    DIRECTION OUTPUT ;
    USE SIGNAL ;
    PORT
      LAYER M4 ;
        RECT  0 71.088 0.084 71.112 ;
    END
  END out_data[22]
  PIN out_data[230]
    DIRECTION OUTPUT ;
    USE SIGNAL ;
    PORT
      LAYER M4 ;
        RECT  0 81.072 0.084 81.096 ;
    END
  END out_data[230]
  PIN out_data[231]
    DIRECTION OUTPUT ;
    USE SIGNAL ;
    PORT
      LAYER M4 ;
        RECT  0 81.12 0.084 81.144 ;
    END
  END out_data[231]
  PIN out_data[232]
    DIRECTION OUTPUT ;
    USE SIGNAL ;
    PORT
      LAYER M4 ;
        RECT  0 81.168 0.084 81.192 ;
    END
  END out_data[232]
  PIN out_data[233]
    DIRECTION OUTPUT ;
    USE SIGNAL ;
    PORT
      LAYER M4 ;
        RECT  0 81.216 0.084 81.24 ;
    END
  END out_data[233]
  PIN out_data[234]
    DIRECTION OUTPUT ;
    USE SIGNAL ;
    PORT
      LAYER M4 ;
        RECT  0 81.264 0.084 81.288 ;
    END
  END out_data[234]
  PIN out_data[235]
    DIRECTION OUTPUT ;
    USE SIGNAL ;
    PORT
      LAYER M4 ;
        RECT  0 81.312 0.084 81.336 ;
    END
  END out_data[235]
  PIN out_data[236]
    DIRECTION OUTPUT ;
    USE SIGNAL ;
    PORT
      LAYER M4 ;
        RECT  0 81.36 0.084 81.384 ;
    END
  END out_data[236]
  PIN out_data[237]
    DIRECTION OUTPUT ;
    USE SIGNAL ;
    PORT
      LAYER M4 ;
        RECT  0 81.408 0.084 81.432 ;
    END
  END out_data[237]
  PIN out_data[238]
    DIRECTION OUTPUT ;
    USE SIGNAL ;
    PORT
      LAYER M4 ;
        RECT  0 81.456 0.084 81.48 ;
    END
  END out_data[238]
  PIN out_data[239]
    DIRECTION OUTPUT ;
    USE SIGNAL ;
    PORT
      LAYER M4 ;
        RECT  0 81.504 0.084 81.528 ;
    END
  END out_data[239]
  PIN out_data[23]
    DIRECTION OUTPUT ;
    USE SIGNAL ;
    PORT
      LAYER M4 ;
        RECT  0 71.136 0.084 71.16 ;
    END
  END out_data[23]
  PIN out_data[240]
    DIRECTION OUTPUT ;
    USE SIGNAL ;
    PORT
      LAYER M4 ;
        RECT  0 81.552 0.084 81.576 ;
    END
  END out_data[240]
  PIN out_data[241]
    DIRECTION OUTPUT ;
    USE SIGNAL ;
    PORT
      LAYER M4 ;
        RECT  0 81.6 0.084 81.624 ;
    END
  END out_data[241]
  PIN out_data[242]
    DIRECTION OUTPUT ;
    USE SIGNAL ;
    PORT
      LAYER M4 ;
        RECT  0 81.648 0.084 81.672 ;
    END
  END out_data[242]
  PIN out_data[243]
    DIRECTION OUTPUT ;
    USE SIGNAL ;
    PORT
      LAYER M4 ;
        RECT  0 81.696 0.084 81.72 ;
    END
  END out_data[243]
  PIN out_data[244]
    DIRECTION OUTPUT ;
    USE SIGNAL ;
    PORT
      LAYER M4 ;
        RECT  0 81.744 0.084 81.768 ;
    END
  END out_data[244]
  PIN out_data[245]
    DIRECTION OUTPUT ;
    USE SIGNAL ;
    PORT
      LAYER M4 ;
        RECT  0 81.792 0.084 81.816 ;
    END
  END out_data[245]
  PIN out_data[246]
    DIRECTION OUTPUT ;
    USE SIGNAL ;
    PORT
      LAYER M4 ;
        RECT  0 81.84 0.084 81.864 ;
    END
  END out_data[246]
  PIN out_data[247]
    DIRECTION OUTPUT ;
    USE SIGNAL ;
    PORT
      LAYER M4 ;
        RECT  0 81.888 0.084 81.912 ;
    END
  END out_data[247]
  PIN out_data[248]
    DIRECTION OUTPUT ;
    USE SIGNAL ;
    PORT
      LAYER M4 ;
        RECT  0 81.936 0.084 81.96 ;
    END
  END out_data[248]
  PIN out_data[249]
    DIRECTION OUTPUT ;
    USE SIGNAL ;
    PORT
      LAYER M4 ;
        RECT  0 81.984 0.084 82.008 ;
    END
  END out_data[249]
  PIN out_data[24]
    DIRECTION OUTPUT ;
    USE SIGNAL ;
    PORT
      LAYER M4 ;
        RECT  0 71.184 0.084 71.208 ;
    END
  END out_data[24]
  PIN out_data[250]
    DIRECTION OUTPUT ;
    USE SIGNAL ;
    PORT
      LAYER M4 ;
        RECT  0 82.032 0.084 82.056 ;
    END
  END out_data[250]
  PIN out_data[251]
    DIRECTION OUTPUT ;
    USE SIGNAL ;
    PORT
      LAYER M4 ;
        RECT  0 82.08 0.084 82.104 ;
    END
  END out_data[251]
  PIN out_data[252]
    DIRECTION OUTPUT ;
    USE SIGNAL ;
    PORT
      LAYER M4 ;
        RECT  0 82.128 0.084 82.152 ;
    END
  END out_data[252]
  PIN out_data[253]
    DIRECTION OUTPUT ;
    USE SIGNAL ;
    PORT
      LAYER M4 ;
        RECT  0 82.176 0.084 82.2 ;
    END
  END out_data[253]
  PIN out_data[254]
    DIRECTION OUTPUT ;
    USE SIGNAL ;
    PORT
      LAYER M4 ;
        RECT  0 82.224 0.084 82.248 ;
    END
  END out_data[254]
  PIN out_data[255]
    DIRECTION OUTPUT ;
    USE SIGNAL ;
    PORT
      LAYER M4 ;
        RECT  0 82.272 0.084 82.296 ;
    END
  END out_data[255]
  PIN out_data[256]
    DIRECTION OUTPUT ;
    USE SIGNAL ;
    PORT
      LAYER M4 ;
        RECT  0 82.32 0.084 82.344 ;
    END
  END out_data[256]
  PIN out_data[257]
    DIRECTION OUTPUT ;
    USE SIGNAL ;
    PORT
      LAYER M4 ;
        RECT  0 82.368 0.084 82.392 ;
    END
  END out_data[257]
  PIN out_data[258]
    DIRECTION OUTPUT ;
    USE SIGNAL ;
    PORT
      LAYER M4 ;
        RECT  0 82.416 0.084 82.44 ;
    END
  END out_data[258]
  PIN out_data[259]
    DIRECTION OUTPUT ;
    USE SIGNAL ;
    PORT
      LAYER M4 ;
        RECT  0 82.464 0.084 82.488 ;
    END
  END out_data[259]
  PIN out_data[25]
    DIRECTION OUTPUT ;
    USE SIGNAL ;
    PORT
      LAYER M4 ;
        RECT  0 71.232 0.084 71.256 ;
    END
  END out_data[25]
  PIN out_data[260]
    DIRECTION OUTPUT ;
    USE SIGNAL ;
    PORT
      LAYER M4 ;
        RECT  0 82.512 0.084 82.536 ;
    END
  END out_data[260]
  PIN out_data[261]
    DIRECTION OUTPUT ;
    USE SIGNAL ;
    PORT
      LAYER M4 ;
        RECT  0 82.56 0.084 82.584 ;
    END
  END out_data[261]
  PIN out_data[262]
    DIRECTION OUTPUT ;
    USE SIGNAL ;
    PORT
      LAYER M4 ;
        RECT  0 82.608 0.084 82.632 ;
    END
  END out_data[262]
  PIN out_data[263]
    DIRECTION OUTPUT ;
    USE SIGNAL ;
    PORT
      LAYER M4 ;
        RECT  0 82.656 0.084 82.68 ;
    END
  END out_data[263]
  PIN out_data[264]
    DIRECTION OUTPUT ;
    USE SIGNAL ;
    PORT
      LAYER M4 ;
        RECT  0 82.704 0.084 82.728 ;
    END
  END out_data[264]
  PIN out_data[265]
    DIRECTION OUTPUT ;
    USE SIGNAL ;
    PORT
      LAYER M4 ;
        RECT  0 82.752 0.084 82.776 ;
    END
  END out_data[265]
  PIN out_data[266]
    DIRECTION OUTPUT ;
    USE SIGNAL ;
    PORT
      LAYER M4 ;
        RECT  0 82.8 0.084 82.824 ;
    END
  END out_data[266]
  PIN out_data[267]
    DIRECTION OUTPUT ;
    USE SIGNAL ;
    PORT
      LAYER M4 ;
        RECT  0 82.848 0.084 82.872 ;
    END
  END out_data[267]
  PIN out_data[268]
    DIRECTION OUTPUT ;
    USE SIGNAL ;
    PORT
      LAYER M4 ;
        RECT  0 82.896 0.084 82.92 ;
    END
  END out_data[268]
  PIN out_data[269]
    DIRECTION OUTPUT ;
    USE SIGNAL ;
    PORT
      LAYER M4 ;
        RECT  0 82.944 0.084 82.968 ;
    END
  END out_data[269]
  PIN out_data[26]
    DIRECTION OUTPUT ;
    USE SIGNAL ;
    PORT
      LAYER M4 ;
        RECT  0 71.28 0.084 71.304 ;
    END
  END out_data[26]
  PIN out_data[270]
    DIRECTION OUTPUT ;
    USE SIGNAL ;
    PORT
      LAYER M4 ;
        RECT  0 82.992 0.084 83.016 ;
    END
  END out_data[270]
  PIN out_data[271]
    DIRECTION OUTPUT ;
    USE SIGNAL ;
    PORT
      LAYER M4 ;
        RECT  0 83.04 0.084 83.064 ;
    END
  END out_data[271]
  PIN out_data[272]
    DIRECTION OUTPUT ;
    USE SIGNAL ;
    PORT
      LAYER M4 ;
        RECT  0 83.088 0.084 83.112 ;
    END
  END out_data[272]
  PIN out_data[273]
    DIRECTION OUTPUT ;
    USE SIGNAL ;
    PORT
      LAYER M4 ;
        RECT  0 83.136 0.084 83.16 ;
    END
  END out_data[273]
  PIN out_data[274]
    DIRECTION OUTPUT ;
    USE SIGNAL ;
    PORT
      LAYER M4 ;
        RECT  0 83.184 0.084 83.208 ;
    END
  END out_data[274]
  PIN out_data[275]
    DIRECTION OUTPUT ;
    USE SIGNAL ;
    PORT
      LAYER M4 ;
        RECT  0 83.232 0.084 83.256 ;
    END
  END out_data[275]
  PIN out_data[276]
    DIRECTION OUTPUT ;
    USE SIGNAL ;
    PORT
      LAYER M4 ;
        RECT  0 83.28 0.084 83.304 ;
    END
  END out_data[276]
  PIN out_data[277]
    DIRECTION OUTPUT ;
    USE SIGNAL ;
    PORT
      LAYER M4 ;
        RECT  0 83.328 0.084 83.352 ;
    END
  END out_data[277]
  PIN out_data[278]
    DIRECTION OUTPUT ;
    USE SIGNAL ;
    PORT
      LAYER M4 ;
        RECT  0 83.376 0.084 83.4 ;
    END
  END out_data[278]
  PIN out_data[279]
    DIRECTION OUTPUT ;
    USE SIGNAL ;
    PORT
      LAYER M4 ;
        RECT  0 83.424 0.084 83.448 ;
    END
  END out_data[279]
  PIN out_data[27]
    DIRECTION OUTPUT ;
    USE SIGNAL ;
    PORT
      LAYER M4 ;
        RECT  0 71.328 0.084 71.352 ;
    END
  END out_data[27]
  PIN out_data[280]
    DIRECTION OUTPUT ;
    USE SIGNAL ;
    PORT
      LAYER M4 ;
        RECT  0 83.472 0.084 83.496 ;
    END
  END out_data[280]
  PIN out_data[281]
    DIRECTION OUTPUT ;
    USE SIGNAL ;
    PORT
      LAYER M4 ;
        RECT  0 83.52 0.084 83.544 ;
    END
  END out_data[281]
  PIN out_data[282]
    DIRECTION OUTPUT ;
    USE SIGNAL ;
    PORT
      LAYER M4 ;
        RECT  0 83.568 0.084 83.592 ;
    END
  END out_data[282]
  PIN out_data[283]
    DIRECTION OUTPUT ;
    USE SIGNAL ;
    PORT
      LAYER M4 ;
        RECT  0 83.616 0.084 83.64 ;
    END
  END out_data[283]
  PIN out_data[284]
    DIRECTION OUTPUT ;
    USE SIGNAL ;
    PORT
      LAYER M4 ;
        RECT  0 83.664 0.084 83.688 ;
    END
  END out_data[284]
  PIN out_data[285]
    DIRECTION OUTPUT ;
    USE SIGNAL ;
    PORT
      LAYER M4 ;
        RECT  0 83.712 0.084 83.736 ;
    END
  END out_data[285]
  PIN out_data[286]
    DIRECTION OUTPUT ;
    USE SIGNAL ;
    PORT
      LAYER M4 ;
        RECT  0 83.76 0.084 83.784 ;
    END
  END out_data[286]
  PIN out_data[287]
    DIRECTION OUTPUT ;
    USE SIGNAL ;
    PORT
      LAYER M4 ;
        RECT  0 83.808 0.084 83.832 ;
    END
  END out_data[287]
  PIN out_data[288]
    DIRECTION OUTPUT ;
    USE SIGNAL ;
    PORT
      LAYER M4 ;
        RECT  0 83.856 0.084 83.88 ;
    END
  END out_data[288]
  PIN out_data[289]
    DIRECTION OUTPUT ;
    USE SIGNAL ;
    PORT
      LAYER M4 ;
        RECT  0 83.904 0.084 83.928 ;
    END
  END out_data[289]
  PIN out_data[28]
    DIRECTION OUTPUT ;
    USE SIGNAL ;
    PORT
      LAYER M4 ;
        RECT  0 71.376 0.084 71.4 ;
    END
  END out_data[28]
  PIN out_data[290]
    DIRECTION OUTPUT ;
    USE SIGNAL ;
    PORT
      LAYER M4 ;
        RECT  0 83.952 0.084 83.976 ;
    END
  END out_data[290]
  PIN out_data[291]
    DIRECTION OUTPUT ;
    USE SIGNAL ;
    PORT
      LAYER M4 ;
        RECT  0 84 0.084 84.024 ;
    END
  END out_data[291]
  PIN out_data[292]
    DIRECTION OUTPUT ;
    USE SIGNAL ;
    PORT
      LAYER M4 ;
        RECT  0 84.048 0.084 84.072 ;
    END
  END out_data[292]
  PIN out_data[293]
    DIRECTION OUTPUT ;
    USE SIGNAL ;
    PORT
      LAYER M4 ;
        RECT  0 84.096 0.084 84.12 ;
    END
  END out_data[293]
  PIN out_data[294]
    DIRECTION OUTPUT ;
    USE SIGNAL ;
    PORT
      LAYER M4 ;
        RECT  0 84.144 0.084 84.168 ;
    END
  END out_data[294]
  PIN out_data[295]
    DIRECTION OUTPUT ;
    USE SIGNAL ;
    PORT
      LAYER M4 ;
        RECT  0 84.192 0.084 84.216 ;
    END
  END out_data[295]
  PIN out_data[296]
    DIRECTION OUTPUT ;
    USE SIGNAL ;
    PORT
      LAYER M4 ;
        RECT  0 84.24 0.084 84.264 ;
    END
  END out_data[296]
  PIN out_data[297]
    DIRECTION OUTPUT ;
    USE SIGNAL ;
    PORT
      LAYER M4 ;
        RECT  0 84.288 0.084 84.312 ;
    END
  END out_data[297]
  PIN out_data[298]
    DIRECTION OUTPUT ;
    USE SIGNAL ;
    PORT
      LAYER M4 ;
        RECT  0 84.336 0.084 84.36 ;
    END
  END out_data[298]
  PIN out_data[299]
    DIRECTION OUTPUT ;
    USE SIGNAL ;
    PORT
      LAYER M4 ;
        RECT  0 84.384 0.084 84.408 ;
    END
  END out_data[299]
  PIN out_data[29]
    DIRECTION OUTPUT ;
    USE SIGNAL ;
    PORT
      LAYER M4 ;
        RECT  0 71.424 0.084 71.448 ;
    END
  END out_data[29]
  PIN out_data[2]
    DIRECTION OUTPUT ;
    USE SIGNAL ;
    PORT
      LAYER M4 ;
        RECT  0 70.128 0.084 70.152 ;
    END
  END out_data[2]
  PIN out_data[300]
    DIRECTION OUTPUT ;
    USE SIGNAL ;
    PORT
      LAYER M4 ;
        RECT  0 84.432 0.084 84.456 ;
    END
  END out_data[300]
  PIN out_data[301]
    DIRECTION OUTPUT ;
    USE SIGNAL ;
    PORT
      LAYER M4 ;
        RECT  0 84.48 0.084 84.504 ;
    END
  END out_data[301]
  PIN out_data[302]
    DIRECTION OUTPUT ;
    USE SIGNAL ;
    PORT
      LAYER M4 ;
        RECT  0 84.528 0.084 84.552 ;
    END
  END out_data[302]
  PIN out_data[303]
    DIRECTION OUTPUT ;
    USE SIGNAL ;
    PORT
      LAYER M4 ;
        RECT  0 84.576 0.084 84.6 ;
    END
  END out_data[303]
  PIN out_data[304]
    DIRECTION OUTPUT ;
    USE SIGNAL ;
    PORT
      LAYER M4 ;
        RECT  0 84.624 0.084 84.648 ;
    END
  END out_data[304]
  PIN out_data[305]
    DIRECTION OUTPUT ;
    USE SIGNAL ;
    PORT
      LAYER M4 ;
        RECT  0 84.672 0.084 84.696 ;
    END
  END out_data[305]
  PIN out_data[306]
    DIRECTION OUTPUT ;
    USE SIGNAL ;
    PORT
      LAYER M4 ;
        RECT  0 84.72 0.084 84.744 ;
    END
  END out_data[306]
  PIN out_data[307]
    DIRECTION OUTPUT ;
    USE SIGNAL ;
    PORT
      LAYER M4 ;
        RECT  0 84.768 0.084 84.792 ;
    END
  END out_data[307]
  PIN out_data[308]
    DIRECTION OUTPUT ;
    USE SIGNAL ;
    PORT
      LAYER M4 ;
        RECT  0 84.816 0.084 84.84 ;
    END
  END out_data[308]
  PIN out_data[309]
    DIRECTION OUTPUT ;
    USE SIGNAL ;
    PORT
      LAYER M4 ;
        RECT  0 84.864 0.084 84.888 ;
    END
  END out_data[309]
  PIN out_data[30]
    DIRECTION OUTPUT ;
    USE SIGNAL ;
    PORT
      LAYER M4 ;
        RECT  0 71.472 0.084 71.496 ;
    END
  END out_data[30]
  PIN out_data[310]
    DIRECTION OUTPUT ;
    USE SIGNAL ;
    PORT
      LAYER M4 ;
        RECT  0 84.912 0.084 84.936 ;
    END
  END out_data[310]
  PIN out_data[311]
    DIRECTION OUTPUT ;
    USE SIGNAL ;
    PORT
      LAYER M4 ;
        RECT  0 84.96 0.084 84.984 ;
    END
  END out_data[311]
  PIN out_data[312]
    DIRECTION OUTPUT ;
    USE SIGNAL ;
    PORT
      LAYER M4 ;
        RECT  0 85.008 0.084 85.032 ;
    END
  END out_data[312]
  PIN out_data[313]
    DIRECTION OUTPUT ;
    USE SIGNAL ;
    PORT
      LAYER M4 ;
        RECT  0 85.056 0.084 85.08 ;
    END
  END out_data[313]
  PIN out_data[314]
    DIRECTION OUTPUT ;
    USE SIGNAL ;
    PORT
      LAYER M4 ;
        RECT  0 85.104 0.084 85.128 ;
    END
  END out_data[314]
  PIN out_data[315]
    DIRECTION OUTPUT ;
    USE SIGNAL ;
    PORT
      LAYER M4 ;
        RECT  0 85.152 0.084 85.176 ;
    END
  END out_data[315]
  PIN out_data[316]
    DIRECTION OUTPUT ;
    USE SIGNAL ;
    PORT
      LAYER M4 ;
        RECT  0 85.2 0.084 85.224 ;
    END
  END out_data[316]
  PIN out_data[317]
    DIRECTION OUTPUT ;
    USE SIGNAL ;
    PORT
      LAYER M4 ;
        RECT  0 85.248 0.084 85.272 ;
    END
  END out_data[317]
  PIN out_data[318]
    DIRECTION OUTPUT ;
    USE SIGNAL ;
    PORT
      LAYER M4 ;
        RECT  0 85.296 0.084 85.32 ;
    END
  END out_data[318]
  PIN out_data[319]
    DIRECTION OUTPUT ;
    USE SIGNAL ;
    PORT
      LAYER M4 ;
        RECT  0 85.344 0.084 85.368 ;
    END
  END out_data[319]
  PIN out_data[31]
    DIRECTION OUTPUT ;
    USE SIGNAL ;
    PORT
      LAYER M4 ;
        RECT  0 71.52 0.084 71.544 ;
    END
  END out_data[31]
  PIN out_data[320]
    DIRECTION OUTPUT ;
    USE SIGNAL ;
    PORT
      LAYER M4 ;
        RECT  0 85.392 0.084 85.416 ;
    END
  END out_data[320]
  PIN out_data[321]
    DIRECTION OUTPUT ;
    USE SIGNAL ;
    PORT
      LAYER M4 ;
        RECT  0 85.44 0.084 85.464 ;
    END
  END out_data[321]
  PIN out_data[322]
    DIRECTION OUTPUT ;
    USE SIGNAL ;
    PORT
      LAYER M4 ;
        RECT  0 85.488 0.084 85.512 ;
    END
  END out_data[322]
  PIN out_data[323]
    DIRECTION OUTPUT ;
    USE SIGNAL ;
    PORT
      LAYER M4 ;
        RECT  0 85.536 0.084 85.56 ;
    END
  END out_data[323]
  PIN out_data[324]
    DIRECTION OUTPUT ;
    USE SIGNAL ;
    PORT
      LAYER M4 ;
        RECT  0 85.584 0.084 85.608 ;
    END
  END out_data[324]
  PIN out_data[325]
    DIRECTION OUTPUT ;
    USE SIGNAL ;
    PORT
      LAYER M4 ;
        RECT  0 85.632 0.084 85.656 ;
    END
  END out_data[325]
  PIN out_data[326]
    DIRECTION OUTPUT ;
    USE SIGNAL ;
    PORT
      LAYER M4 ;
        RECT  0 85.68 0.084 85.704 ;
    END
  END out_data[326]
  PIN out_data[327]
    DIRECTION OUTPUT ;
    USE SIGNAL ;
    PORT
      LAYER M4 ;
        RECT  0 85.728 0.084 85.752 ;
    END
  END out_data[327]
  PIN out_data[328]
    DIRECTION OUTPUT ;
    USE SIGNAL ;
    PORT
      LAYER M4 ;
        RECT  0 85.776 0.084 85.8 ;
    END
  END out_data[328]
  PIN out_data[329]
    DIRECTION OUTPUT ;
    USE SIGNAL ;
    PORT
      LAYER M4 ;
        RECT  0 85.824 0.084 85.848 ;
    END
  END out_data[329]
  PIN out_data[32]
    DIRECTION OUTPUT ;
    USE SIGNAL ;
    PORT
      LAYER M4 ;
        RECT  0 71.568 0.084 71.592 ;
    END
  END out_data[32]
  PIN out_data[330]
    DIRECTION OUTPUT ;
    USE SIGNAL ;
    PORT
      LAYER M4 ;
        RECT  0 85.872 0.084 85.896 ;
    END
  END out_data[330]
  PIN out_data[331]
    DIRECTION OUTPUT ;
    USE SIGNAL ;
    PORT
      LAYER M4 ;
        RECT  0 85.92 0.084 85.944 ;
    END
  END out_data[331]
  PIN out_data[332]
    DIRECTION OUTPUT ;
    USE SIGNAL ;
    PORT
      LAYER M4 ;
        RECT  0 85.968 0.084 85.992 ;
    END
  END out_data[332]
  PIN out_data[333]
    DIRECTION OUTPUT ;
    USE SIGNAL ;
    PORT
      LAYER M4 ;
        RECT  0 86.016 0.084 86.04 ;
    END
  END out_data[333]
  PIN out_data[334]
    DIRECTION OUTPUT ;
    USE SIGNAL ;
    PORT
      LAYER M4 ;
        RECT  0 86.064 0.084 86.088 ;
    END
  END out_data[334]
  PIN out_data[335]
    DIRECTION OUTPUT ;
    USE SIGNAL ;
    PORT
      LAYER M4 ;
        RECT  0 86.112 0.084 86.136 ;
    END
  END out_data[335]
  PIN out_data[336]
    DIRECTION OUTPUT ;
    USE SIGNAL ;
    PORT
      LAYER M4 ;
        RECT  0 86.16 0.084 86.184 ;
    END
  END out_data[336]
  PIN out_data[337]
    DIRECTION OUTPUT ;
    USE SIGNAL ;
    PORT
      LAYER M4 ;
        RECT  0 86.208 0.084 86.232 ;
    END
  END out_data[337]
  PIN out_data[338]
    DIRECTION OUTPUT ;
    USE SIGNAL ;
    PORT
      LAYER M4 ;
        RECT  0 86.256 0.084 86.28 ;
    END
  END out_data[338]
  PIN out_data[339]
    DIRECTION OUTPUT ;
    USE SIGNAL ;
    PORT
      LAYER M4 ;
        RECT  0 86.304 0.084 86.328 ;
    END
  END out_data[339]
  PIN out_data[33]
    DIRECTION OUTPUT ;
    USE SIGNAL ;
    PORT
      LAYER M4 ;
        RECT  0 71.616 0.084 71.64 ;
    END
  END out_data[33]
  PIN out_data[340]
    DIRECTION OUTPUT ;
    USE SIGNAL ;
    PORT
      LAYER M4 ;
        RECT  0 86.352 0.084 86.376 ;
    END
  END out_data[340]
  PIN out_data[341]
    DIRECTION OUTPUT ;
    USE SIGNAL ;
    PORT
      LAYER M4 ;
        RECT  0 86.4 0.084 86.424 ;
    END
  END out_data[341]
  PIN out_data[342]
    DIRECTION OUTPUT ;
    USE SIGNAL ;
    PORT
      LAYER M4 ;
        RECT  0 86.448 0.084 86.472 ;
    END
  END out_data[342]
  PIN out_data[343]
    DIRECTION OUTPUT ;
    USE SIGNAL ;
    PORT
      LAYER M4 ;
        RECT  0 86.496 0.084 86.52 ;
    END
  END out_data[343]
  PIN out_data[344]
    DIRECTION OUTPUT ;
    USE SIGNAL ;
    PORT
      LAYER M4 ;
        RECT  0 86.544 0.084 86.568 ;
    END
  END out_data[344]
  PIN out_data[345]
    DIRECTION OUTPUT ;
    USE SIGNAL ;
    PORT
      LAYER M4 ;
        RECT  0 86.592 0.084 86.616 ;
    END
  END out_data[345]
  PIN out_data[346]
    DIRECTION OUTPUT ;
    USE SIGNAL ;
    PORT
      LAYER M4 ;
        RECT  0 86.64 0.084 86.664 ;
    END
  END out_data[346]
  PIN out_data[347]
    DIRECTION OUTPUT ;
    USE SIGNAL ;
    PORT
      LAYER M4 ;
        RECT  0 86.688 0.084 86.712 ;
    END
  END out_data[347]
  PIN out_data[348]
    DIRECTION OUTPUT ;
    USE SIGNAL ;
    PORT
      LAYER M4 ;
        RECT  0 86.736 0.084 86.76 ;
    END
  END out_data[348]
  PIN out_data[349]
    DIRECTION OUTPUT ;
    USE SIGNAL ;
    PORT
      LAYER M4 ;
        RECT  0 86.784 0.084 86.808 ;
    END
  END out_data[349]
  PIN out_data[34]
    DIRECTION OUTPUT ;
    USE SIGNAL ;
    PORT
      LAYER M4 ;
        RECT  0 71.664 0.084 71.688 ;
    END
  END out_data[34]
  PIN out_data[350]
    DIRECTION OUTPUT ;
    USE SIGNAL ;
    PORT
      LAYER M4 ;
        RECT  0 86.832 0.084 86.856 ;
    END
  END out_data[350]
  PIN out_data[351]
    DIRECTION OUTPUT ;
    USE SIGNAL ;
    PORT
      LAYER M4 ;
        RECT  0 86.88 0.084 86.904 ;
    END
  END out_data[351]
  PIN out_data[352]
    DIRECTION OUTPUT ;
    USE SIGNAL ;
    PORT
      LAYER M4 ;
        RECT  0 86.928 0.084 86.952 ;
    END
  END out_data[352]
  PIN out_data[353]
    DIRECTION OUTPUT ;
    USE SIGNAL ;
    PORT
      LAYER M4 ;
        RECT  0 86.976 0.084 87 ;
    END
  END out_data[353]
  PIN out_data[354]
    DIRECTION OUTPUT ;
    USE SIGNAL ;
    PORT
      LAYER M4 ;
        RECT  0 87.024 0.084 87.048 ;
    END
  END out_data[354]
  PIN out_data[355]
    DIRECTION OUTPUT ;
    USE SIGNAL ;
    PORT
      LAYER M4 ;
        RECT  0 87.072 0.084 87.096 ;
    END
  END out_data[355]
  PIN out_data[356]
    DIRECTION OUTPUT ;
    USE SIGNAL ;
    PORT
      LAYER M4 ;
        RECT  0 87.12 0.084 87.144 ;
    END
  END out_data[356]
  PIN out_data[357]
    DIRECTION OUTPUT ;
    USE SIGNAL ;
    PORT
      LAYER M4 ;
        RECT  0 87.168 0.084 87.192 ;
    END
  END out_data[357]
  PIN out_data[358]
    DIRECTION OUTPUT ;
    USE SIGNAL ;
    PORT
      LAYER M4 ;
        RECT  0 87.216 0.084 87.24 ;
    END
  END out_data[358]
  PIN out_data[359]
    DIRECTION OUTPUT ;
    USE SIGNAL ;
    PORT
      LAYER M4 ;
        RECT  0 87.264 0.084 87.288 ;
    END
  END out_data[359]
  PIN out_data[35]
    DIRECTION OUTPUT ;
    USE SIGNAL ;
    PORT
      LAYER M4 ;
        RECT  0 71.712 0.084 71.736 ;
    END
  END out_data[35]
  PIN out_data[360]
    DIRECTION OUTPUT ;
    USE SIGNAL ;
    PORT
      LAYER M4 ;
        RECT  0 87.312 0.084 87.336 ;
    END
  END out_data[360]
  PIN out_data[361]
    DIRECTION OUTPUT ;
    USE SIGNAL ;
    PORT
      LAYER M4 ;
        RECT  0 87.36 0.084 87.384 ;
    END
  END out_data[361]
  PIN out_data[362]
    DIRECTION OUTPUT ;
    USE SIGNAL ;
    PORT
      LAYER M4 ;
        RECT  0 87.408 0.084 87.432 ;
    END
  END out_data[362]
  PIN out_data[363]
    DIRECTION OUTPUT ;
    USE SIGNAL ;
    PORT
      LAYER M4 ;
        RECT  0 87.456 0.084 87.48 ;
    END
  END out_data[363]
  PIN out_data[364]
    DIRECTION OUTPUT ;
    USE SIGNAL ;
    PORT
      LAYER M4 ;
        RECT  0 87.504 0.084 87.528 ;
    END
  END out_data[364]
  PIN out_data[365]
    DIRECTION OUTPUT ;
    USE SIGNAL ;
    PORT
      LAYER M4 ;
        RECT  0 87.552 0.084 87.576 ;
    END
  END out_data[365]
  PIN out_data[366]
    DIRECTION OUTPUT ;
    USE SIGNAL ;
    PORT
      LAYER M4 ;
        RECT  0 87.6 0.084 87.624 ;
    END
  END out_data[366]
  PIN out_data[367]
    DIRECTION OUTPUT ;
    USE SIGNAL ;
    PORT
      LAYER M4 ;
        RECT  0 87.648 0.084 87.672 ;
    END
  END out_data[367]
  PIN out_data[368]
    DIRECTION OUTPUT ;
    USE SIGNAL ;
    PORT
      LAYER M4 ;
        RECT  0 87.696 0.084 87.72 ;
    END
  END out_data[368]
  PIN out_data[369]
    DIRECTION OUTPUT ;
    USE SIGNAL ;
    PORT
      LAYER M4 ;
        RECT  0 87.744 0.084 87.768 ;
    END
  END out_data[369]
  PIN out_data[36]
    DIRECTION OUTPUT ;
    USE SIGNAL ;
    PORT
      LAYER M4 ;
        RECT  0 71.76 0.084 71.784 ;
    END
  END out_data[36]
  PIN out_data[370]
    DIRECTION OUTPUT ;
    USE SIGNAL ;
    PORT
      LAYER M4 ;
        RECT  0 87.792 0.084 87.816 ;
    END
  END out_data[370]
  PIN out_data[371]
    DIRECTION OUTPUT ;
    USE SIGNAL ;
    PORT
      LAYER M4 ;
        RECT  0 87.84 0.084 87.864 ;
    END
  END out_data[371]
  PIN out_data[372]
    DIRECTION OUTPUT ;
    USE SIGNAL ;
    PORT
      LAYER M4 ;
        RECT  0 87.888 0.084 87.912 ;
    END
  END out_data[372]
  PIN out_data[373]
    DIRECTION OUTPUT ;
    USE SIGNAL ;
    PORT
      LAYER M4 ;
        RECT  0 87.936 0.084 87.96 ;
    END
  END out_data[373]
  PIN out_data[374]
    DIRECTION OUTPUT ;
    USE SIGNAL ;
    PORT
      LAYER M4 ;
        RECT  0 87.984 0.084 88.008 ;
    END
  END out_data[374]
  PIN out_data[375]
    DIRECTION OUTPUT ;
    USE SIGNAL ;
    PORT
      LAYER M4 ;
        RECT  0 88.032 0.084 88.056 ;
    END
  END out_data[375]
  PIN out_data[376]
    DIRECTION OUTPUT ;
    USE SIGNAL ;
    PORT
      LAYER M4 ;
        RECT  0 88.08 0.084 88.104 ;
    END
  END out_data[376]
  PIN out_data[377]
    DIRECTION OUTPUT ;
    USE SIGNAL ;
    PORT
      LAYER M4 ;
        RECT  0 88.128 0.084 88.152 ;
    END
  END out_data[377]
  PIN out_data[378]
    DIRECTION OUTPUT ;
    USE SIGNAL ;
    PORT
      LAYER M4 ;
        RECT  0 88.176 0.084 88.2 ;
    END
  END out_data[378]
  PIN out_data[379]
    DIRECTION OUTPUT ;
    USE SIGNAL ;
    PORT
      LAYER M4 ;
        RECT  0 88.224 0.084 88.248 ;
    END
  END out_data[379]
  PIN out_data[37]
    DIRECTION OUTPUT ;
    USE SIGNAL ;
    PORT
      LAYER M4 ;
        RECT  0 71.808 0.084 71.832 ;
    END
  END out_data[37]
  PIN out_data[380]
    DIRECTION OUTPUT ;
    USE SIGNAL ;
    PORT
      LAYER M4 ;
        RECT  0 88.272 0.084 88.296 ;
    END
  END out_data[380]
  PIN out_data[381]
    DIRECTION OUTPUT ;
    USE SIGNAL ;
    PORT
      LAYER M4 ;
        RECT  0 88.32 0.084 88.344 ;
    END
  END out_data[381]
  PIN out_data[382]
    DIRECTION OUTPUT ;
    USE SIGNAL ;
    PORT
      LAYER M4 ;
        RECT  0 88.368 0.084 88.392 ;
    END
  END out_data[382]
  PIN out_data[383]
    DIRECTION OUTPUT ;
    USE SIGNAL ;
    PORT
      LAYER M4 ;
        RECT  0 88.416 0.084 88.44 ;
    END
  END out_data[383]
  PIN out_data[384]
    DIRECTION OUTPUT ;
    USE SIGNAL ;
    PORT
      LAYER M4 ;
        RECT  0 88.464 0.084 88.488 ;
    END
  END out_data[384]
  PIN out_data[385]
    DIRECTION OUTPUT ;
    USE SIGNAL ;
    PORT
      LAYER M4 ;
        RECT  0 88.512 0.084 88.536 ;
    END
  END out_data[385]
  PIN out_data[386]
    DIRECTION OUTPUT ;
    USE SIGNAL ;
    PORT
      LAYER M4 ;
        RECT  0 88.56 0.084 88.584 ;
    END
  END out_data[386]
  PIN out_data[387]
    DIRECTION OUTPUT ;
    USE SIGNAL ;
    PORT
      LAYER M4 ;
        RECT  0 88.608 0.084 88.632 ;
    END
  END out_data[387]
  PIN out_data[388]
    DIRECTION OUTPUT ;
    USE SIGNAL ;
    PORT
      LAYER M4 ;
        RECT  0 88.656 0.084 88.68 ;
    END
  END out_data[388]
  PIN out_data[389]
    DIRECTION OUTPUT ;
    USE SIGNAL ;
    PORT
      LAYER M4 ;
        RECT  0 88.704 0.084 88.728 ;
    END
  END out_data[389]
  PIN out_data[38]
    DIRECTION OUTPUT ;
    USE SIGNAL ;
    PORT
      LAYER M4 ;
        RECT  0 71.856 0.084 71.88 ;
    END
  END out_data[38]
  PIN out_data[390]
    DIRECTION OUTPUT ;
    USE SIGNAL ;
    PORT
      LAYER M4 ;
        RECT  0 88.752 0.084 88.776 ;
    END
  END out_data[390]
  PIN out_data[391]
    DIRECTION OUTPUT ;
    USE SIGNAL ;
    PORT
      LAYER M4 ;
        RECT  0 88.8 0.084 88.824 ;
    END
  END out_data[391]
  PIN out_data[392]
    DIRECTION OUTPUT ;
    USE SIGNAL ;
    PORT
      LAYER M4 ;
        RECT  0 88.848 0.084 88.872 ;
    END
  END out_data[392]
  PIN out_data[393]
    DIRECTION OUTPUT ;
    USE SIGNAL ;
    PORT
      LAYER M4 ;
        RECT  0 88.896 0.084 88.92 ;
    END
  END out_data[393]
  PIN out_data[394]
    DIRECTION OUTPUT ;
    USE SIGNAL ;
    PORT
      LAYER M4 ;
        RECT  0 88.944 0.084 88.968 ;
    END
  END out_data[394]
  PIN out_data[395]
    DIRECTION OUTPUT ;
    USE SIGNAL ;
    PORT
      LAYER M4 ;
        RECT  0 88.992 0.084 89.016 ;
    END
  END out_data[395]
  PIN out_data[396]
    DIRECTION OUTPUT ;
    USE SIGNAL ;
    PORT
      LAYER M4 ;
        RECT  0 89.04 0.084 89.064 ;
    END
  END out_data[396]
  PIN out_data[397]
    DIRECTION OUTPUT ;
    USE SIGNAL ;
    PORT
      LAYER M4 ;
        RECT  0 89.088 0.084 89.112 ;
    END
  END out_data[397]
  PIN out_data[398]
    DIRECTION OUTPUT ;
    USE SIGNAL ;
    PORT
      LAYER M4 ;
        RECT  0 89.136 0.084 89.16 ;
    END
  END out_data[398]
  PIN out_data[399]
    DIRECTION OUTPUT ;
    USE SIGNAL ;
    PORT
      LAYER M4 ;
        RECT  0 89.184 0.084 89.208 ;
    END
  END out_data[399]
  PIN out_data[39]
    DIRECTION OUTPUT ;
    USE SIGNAL ;
    PORT
      LAYER M4 ;
        RECT  0 71.904 0.084 71.928 ;
    END
  END out_data[39]
  PIN out_data[3]
    DIRECTION OUTPUT ;
    USE SIGNAL ;
    PORT
      LAYER M4 ;
        RECT  0 70.176 0.084 70.2 ;
    END
  END out_data[3]
  PIN out_data[400]
    DIRECTION OUTPUT ;
    USE SIGNAL ;
    PORT
      LAYER M4 ;
        RECT  0 89.232 0.084 89.256 ;
    END
  END out_data[400]
  PIN out_data[401]
    DIRECTION OUTPUT ;
    USE SIGNAL ;
    PORT
      LAYER M4 ;
        RECT  0 89.28 0.084 89.304 ;
    END
  END out_data[401]
  PIN out_data[402]
    DIRECTION OUTPUT ;
    USE SIGNAL ;
    PORT
      LAYER M4 ;
        RECT  0 89.328 0.084 89.352 ;
    END
  END out_data[402]
  PIN out_data[403]
    DIRECTION OUTPUT ;
    USE SIGNAL ;
    PORT
      LAYER M4 ;
        RECT  0 89.376 0.084 89.4 ;
    END
  END out_data[403]
  PIN out_data[404]
    DIRECTION OUTPUT ;
    USE SIGNAL ;
    PORT
      LAYER M4 ;
        RECT  0 89.424 0.084 89.448 ;
    END
  END out_data[404]
  PIN out_data[405]
    DIRECTION OUTPUT ;
    USE SIGNAL ;
    PORT
      LAYER M4 ;
        RECT  0 89.472 0.084 89.496 ;
    END
  END out_data[405]
  PIN out_data[406]
    DIRECTION OUTPUT ;
    USE SIGNAL ;
    PORT
      LAYER M4 ;
        RECT  0 89.52 0.084 89.544 ;
    END
  END out_data[406]
  PIN out_data[407]
    DIRECTION OUTPUT ;
    USE SIGNAL ;
    PORT
      LAYER M4 ;
        RECT  0 89.568 0.084 89.592 ;
    END
  END out_data[407]
  PIN out_data[408]
    DIRECTION OUTPUT ;
    USE SIGNAL ;
    PORT
      LAYER M4 ;
        RECT  0 89.616 0.084 89.64 ;
    END
  END out_data[408]
  PIN out_data[409]
    DIRECTION OUTPUT ;
    USE SIGNAL ;
    PORT
      LAYER M4 ;
        RECT  0 89.664 0.084 89.688 ;
    END
  END out_data[409]
  PIN out_data[40]
    DIRECTION OUTPUT ;
    USE SIGNAL ;
    PORT
      LAYER M4 ;
        RECT  0 71.952 0.084 71.976 ;
    END
  END out_data[40]
  PIN out_data[410]
    DIRECTION OUTPUT ;
    USE SIGNAL ;
    PORT
      LAYER M4 ;
        RECT  0 89.712 0.084 89.736 ;
    END
  END out_data[410]
  PIN out_data[411]
    DIRECTION OUTPUT ;
    USE SIGNAL ;
    PORT
      LAYER M4 ;
        RECT  0 89.76 0.084 89.784 ;
    END
  END out_data[411]
  PIN out_data[412]
    DIRECTION OUTPUT ;
    USE SIGNAL ;
    PORT
      LAYER M4 ;
        RECT  0 89.808 0.084 89.832 ;
    END
  END out_data[412]
  PIN out_data[413]
    DIRECTION OUTPUT ;
    USE SIGNAL ;
    PORT
      LAYER M4 ;
        RECT  0 89.856 0.084 89.88 ;
    END
  END out_data[413]
  PIN out_data[414]
    DIRECTION OUTPUT ;
    USE SIGNAL ;
    PORT
      LAYER M4 ;
        RECT  0 89.904 0.084 89.928 ;
    END
  END out_data[414]
  PIN out_data[415]
    DIRECTION OUTPUT ;
    USE SIGNAL ;
    PORT
      LAYER M4 ;
        RECT  0 89.952 0.084 89.976 ;
    END
  END out_data[415]
  PIN out_data[416]
    DIRECTION OUTPUT ;
    USE SIGNAL ;
    PORT
      LAYER M4 ;
        RECT  0 90 0.084 90.024 ;
    END
  END out_data[416]
  PIN out_data[417]
    DIRECTION OUTPUT ;
    USE SIGNAL ;
    PORT
      LAYER M4 ;
        RECT  0 90.048 0.084 90.072 ;
    END
  END out_data[417]
  PIN out_data[418]
    DIRECTION OUTPUT ;
    USE SIGNAL ;
    PORT
      LAYER M4 ;
        RECT  0 90.096 0.084 90.12 ;
    END
  END out_data[418]
  PIN out_data[419]
    DIRECTION OUTPUT ;
    USE SIGNAL ;
    PORT
      LAYER M4 ;
        RECT  0 90.144 0.084 90.168 ;
    END
  END out_data[419]
  PIN out_data[41]
    DIRECTION OUTPUT ;
    USE SIGNAL ;
    PORT
      LAYER M4 ;
        RECT  0 72 0.084 72.024 ;
    END
  END out_data[41]
  PIN out_data[420]
    DIRECTION OUTPUT ;
    USE SIGNAL ;
    PORT
      LAYER M4 ;
        RECT  0 90.192 0.084 90.216 ;
    END
  END out_data[420]
  PIN out_data[421]
    DIRECTION OUTPUT ;
    USE SIGNAL ;
    PORT
      LAYER M4 ;
        RECT  0 90.24 0.084 90.264 ;
    END
  END out_data[421]
  PIN out_data[422]
    DIRECTION OUTPUT ;
    USE SIGNAL ;
    PORT
      LAYER M4 ;
        RECT  0 90.288 0.084 90.312 ;
    END
  END out_data[422]
  PIN out_data[423]
    DIRECTION OUTPUT ;
    USE SIGNAL ;
    PORT
      LAYER M4 ;
        RECT  0 90.336 0.084 90.36 ;
    END
  END out_data[423]
  PIN out_data[424]
    DIRECTION OUTPUT ;
    USE SIGNAL ;
    PORT
      LAYER M4 ;
        RECT  0 90.384 0.084 90.408 ;
    END
  END out_data[424]
  PIN out_data[425]
    DIRECTION OUTPUT ;
    USE SIGNAL ;
    PORT
      LAYER M4 ;
        RECT  0 90.432 0.084 90.456 ;
    END
  END out_data[425]
  PIN out_data[426]
    DIRECTION OUTPUT ;
    USE SIGNAL ;
    PORT
      LAYER M4 ;
        RECT  0 90.48 0.084 90.504 ;
    END
  END out_data[426]
  PIN out_data[427]
    DIRECTION OUTPUT ;
    USE SIGNAL ;
    PORT
      LAYER M4 ;
        RECT  0 90.528 0.084 90.552 ;
    END
  END out_data[427]
  PIN out_data[428]
    DIRECTION OUTPUT ;
    USE SIGNAL ;
    PORT
      LAYER M4 ;
        RECT  0 90.576 0.084 90.6 ;
    END
  END out_data[428]
  PIN out_data[429]
    DIRECTION OUTPUT ;
    USE SIGNAL ;
    PORT
      LAYER M4 ;
        RECT  0 90.624 0.084 90.648 ;
    END
  END out_data[429]
  PIN out_data[42]
    DIRECTION OUTPUT ;
    USE SIGNAL ;
    PORT
      LAYER M4 ;
        RECT  0 72.048 0.084 72.072 ;
    END
  END out_data[42]
  PIN out_data[430]
    DIRECTION OUTPUT ;
    USE SIGNAL ;
    PORT
      LAYER M4 ;
        RECT  0 90.672 0.084 90.696 ;
    END
  END out_data[430]
  PIN out_data[431]
    DIRECTION OUTPUT ;
    USE SIGNAL ;
    PORT
      LAYER M4 ;
        RECT  0 90.72 0.084 90.744 ;
    END
  END out_data[431]
  PIN out_data[432]
    DIRECTION OUTPUT ;
    USE SIGNAL ;
    PORT
      LAYER M4 ;
        RECT  0 90.768 0.084 90.792 ;
    END
  END out_data[432]
  PIN out_data[433]
    DIRECTION OUTPUT ;
    USE SIGNAL ;
    PORT
      LAYER M4 ;
        RECT  0 90.816 0.084 90.84 ;
    END
  END out_data[433]
  PIN out_data[434]
    DIRECTION OUTPUT ;
    USE SIGNAL ;
    PORT
      LAYER M4 ;
        RECT  0 90.864 0.084 90.888 ;
    END
  END out_data[434]
  PIN out_data[435]
    DIRECTION OUTPUT ;
    USE SIGNAL ;
    PORT
      LAYER M4 ;
        RECT  0 90.912 0.084 90.936 ;
    END
  END out_data[435]
  PIN out_data[436]
    DIRECTION OUTPUT ;
    USE SIGNAL ;
    PORT
      LAYER M4 ;
        RECT  0 90.96 0.084 90.984 ;
    END
  END out_data[436]
  PIN out_data[437]
    DIRECTION OUTPUT ;
    USE SIGNAL ;
    PORT
      LAYER M4 ;
        RECT  0 91.008 0.084 91.032 ;
    END
  END out_data[437]
  PIN out_data[438]
    DIRECTION OUTPUT ;
    USE SIGNAL ;
    PORT
      LAYER M4 ;
        RECT  0 91.056 0.084 91.08 ;
    END
  END out_data[438]
  PIN out_data[439]
    DIRECTION OUTPUT ;
    USE SIGNAL ;
    PORT
      LAYER M4 ;
        RECT  0 91.104 0.084 91.128 ;
    END
  END out_data[439]
  PIN out_data[43]
    DIRECTION OUTPUT ;
    USE SIGNAL ;
    PORT
      LAYER M4 ;
        RECT  0 72.096 0.084 72.12 ;
    END
  END out_data[43]
  PIN out_data[440]
    DIRECTION OUTPUT ;
    USE SIGNAL ;
    PORT
      LAYER M4 ;
        RECT  0 91.152 0.084 91.176 ;
    END
  END out_data[440]
  PIN out_data[441]
    DIRECTION OUTPUT ;
    USE SIGNAL ;
    PORT
      LAYER M4 ;
        RECT  0 91.2 0.084 91.224 ;
    END
  END out_data[441]
  PIN out_data[442]
    DIRECTION OUTPUT ;
    USE SIGNAL ;
    PORT
      LAYER M4 ;
        RECT  0 91.248 0.084 91.272 ;
    END
  END out_data[442]
  PIN out_data[443]
    DIRECTION OUTPUT ;
    USE SIGNAL ;
    PORT
      LAYER M4 ;
        RECT  0 91.296 0.084 91.32 ;
    END
  END out_data[443]
  PIN out_data[444]
    DIRECTION OUTPUT ;
    USE SIGNAL ;
    PORT
      LAYER M4 ;
        RECT  0 91.344 0.084 91.368 ;
    END
  END out_data[444]
  PIN out_data[445]
    DIRECTION OUTPUT ;
    USE SIGNAL ;
    PORT
      LAYER M4 ;
        RECT  0 91.392 0.084 91.416 ;
    END
  END out_data[445]
  PIN out_data[446]
    DIRECTION OUTPUT ;
    USE SIGNAL ;
    PORT
      LAYER M4 ;
        RECT  0 91.44 0.084 91.464 ;
    END
  END out_data[446]
  PIN out_data[447]
    DIRECTION OUTPUT ;
    USE SIGNAL ;
    PORT
      LAYER M4 ;
        RECT  0 91.488 0.084 91.512 ;
    END
  END out_data[447]
  PIN out_data[448]
    DIRECTION OUTPUT ;
    USE SIGNAL ;
    PORT
      LAYER M4 ;
        RECT  0 91.536 0.084 91.56 ;
    END
  END out_data[448]
  PIN out_data[449]
    DIRECTION OUTPUT ;
    USE SIGNAL ;
    PORT
      LAYER M4 ;
        RECT  0 91.584 0.084 91.608 ;
    END
  END out_data[449]
  PIN out_data[44]
    DIRECTION OUTPUT ;
    USE SIGNAL ;
    PORT
      LAYER M4 ;
        RECT  0 72.144 0.084 72.168 ;
    END
  END out_data[44]
  PIN out_data[450]
    DIRECTION OUTPUT ;
    USE SIGNAL ;
    PORT
      LAYER M4 ;
        RECT  0 91.632 0.084 91.656 ;
    END
  END out_data[450]
  PIN out_data[451]
    DIRECTION OUTPUT ;
    USE SIGNAL ;
    PORT
      LAYER M4 ;
        RECT  0 91.68 0.084 91.704 ;
    END
  END out_data[451]
  PIN out_data[452]
    DIRECTION OUTPUT ;
    USE SIGNAL ;
    PORT
      LAYER M4 ;
        RECT  0 91.728 0.084 91.752 ;
    END
  END out_data[452]
  PIN out_data[453]
    DIRECTION OUTPUT ;
    USE SIGNAL ;
    PORT
      LAYER M4 ;
        RECT  0 91.776 0.084 91.8 ;
    END
  END out_data[453]
  PIN out_data[454]
    DIRECTION OUTPUT ;
    USE SIGNAL ;
    PORT
      LAYER M4 ;
        RECT  0 91.824 0.084 91.848 ;
    END
  END out_data[454]
  PIN out_data[455]
    DIRECTION OUTPUT ;
    USE SIGNAL ;
    PORT
      LAYER M4 ;
        RECT  0 91.872 0.084 91.896 ;
    END
  END out_data[455]
  PIN out_data[456]
    DIRECTION OUTPUT ;
    USE SIGNAL ;
    PORT
      LAYER M4 ;
        RECT  0 91.92 0.084 91.944 ;
    END
  END out_data[456]
  PIN out_data[457]
    DIRECTION OUTPUT ;
    USE SIGNAL ;
    PORT
      LAYER M4 ;
        RECT  0 91.968 0.084 91.992 ;
    END
  END out_data[457]
  PIN out_data[458]
    DIRECTION OUTPUT ;
    USE SIGNAL ;
    PORT
      LAYER M4 ;
        RECT  0 92.016 0.084 92.04 ;
    END
  END out_data[458]
  PIN out_data[459]
    DIRECTION OUTPUT ;
    USE SIGNAL ;
    PORT
      LAYER M4 ;
        RECT  0 92.064 0.084 92.088 ;
    END
  END out_data[459]
  PIN out_data[45]
    DIRECTION OUTPUT ;
    USE SIGNAL ;
    PORT
      LAYER M4 ;
        RECT  0 72.192 0.084 72.216 ;
    END
  END out_data[45]
  PIN out_data[460]
    DIRECTION OUTPUT ;
    USE SIGNAL ;
    PORT
      LAYER M4 ;
        RECT  0 92.112 0.084 92.136 ;
    END
  END out_data[460]
  PIN out_data[461]
    DIRECTION OUTPUT ;
    USE SIGNAL ;
    PORT
      LAYER M4 ;
        RECT  0 92.16 0.084 92.184 ;
    END
  END out_data[461]
  PIN out_data[462]
    DIRECTION OUTPUT ;
    USE SIGNAL ;
    PORT
      LAYER M4 ;
        RECT  0 92.208 0.084 92.232 ;
    END
  END out_data[462]
  PIN out_data[463]
    DIRECTION OUTPUT ;
    USE SIGNAL ;
    PORT
      LAYER M4 ;
        RECT  0 92.256 0.084 92.28 ;
    END
  END out_data[463]
  PIN out_data[464]
    DIRECTION OUTPUT ;
    USE SIGNAL ;
    PORT
      LAYER M4 ;
        RECT  0 92.304 0.084 92.328 ;
    END
  END out_data[464]
  PIN out_data[465]
    DIRECTION OUTPUT ;
    USE SIGNAL ;
    PORT
      LAYER M4 ;
        RECT  0 92.352 0.084 92.376 ;
    END
  END out_data[465]
  PIN out_data[466]
    DIRECTION OUTPUT ;
    USE SIGNAL ;
    PORT
      LAYER M4 ;
        RECT  0 92.4 0.084 92.424 ;
    END
  END out_data[466]
  PIN out_data[467]
    DIRECTION OUTPUT ;
    USE SIGNAL ;
    PORT
      LAYER M4 ;
        RECT  0 92.448 0.084 92.472 ;
    END
  END out_data[467]
  PIN out_data[468]
    DIRECTION OUTPUT ;
    USE SIGNAL ;
    PORT
      LAYER M4 ;
        RECT  0 92.496 0.084 92.52 ;
    END
  END out_data[468]
  PIN out_data[469]
    DIRECTION OUTPUT ;
    USE SIGNAL ;
    PORT
      LAYER M4 ;
        RECT  0 92.544 0.084 92.568 ;
    END
  END out_data[469]
  PIN out_data[46]
    DIRECTION OUTPUT ;
    USE SIGNAL ;
    PORT
      LAYER M4 ;
        RECT  0 72.24 0.084 72.264 ;
    END
  END out_data[46]
  PIN out_data[470]
    DIRECTION OUTPUT ;
    USE SIGNAL ;
    PORT
      LAYER M4 ;
        RECT  0 92.592 0.084 92.616 ;
    END
  END out_data[470]
  PIN out_data[471]
    DIRECTION OUTPUT ;
    USE SIGNAL ;
    PORT
      LAYER M4 ;
        RECT  0 92.64 0.084 92.664 ;
    END
  END out_data[471]
  PIN out_data[472]
    DIRECTION OUTPUT ;
    USE SIGNAL ;
    PORT
      LAYER M4 ;
        RECT  0 92.688 0.084 92.712 ;
    END
  END out_data[472]
  PIN out_data[473]
    DIRECTION OUTPUT ;
    USE SIGNAL ;
    PORT
      LAYER M4 ;
        RECT  0 92.736 0.084 92.76 ;
    END
  END out_data[473]
  PIN out_data[474]
    DIRECTION OUTPUT ;
    USE SIGNAL ;
    PORT
      LAYER M4 ;
        RECT  0 92.784 0.084 92.808 ;
    END
  END out_data[474]
  PIN out_data[475]
    DIRECTION OUTPUT ;
    USE SIGNAL ;
    PORT
      LAYER M4 ;
        RECT  0 92.832 0.084 92.856 ;
    END
  END out_data[475]
  PIN out_data[476]
    DIRECTION OUTPUT ;
    USE SIGNAL ;
    PORT
      LAYER M4 ;
        RECT  0 92.88 0.084 92.904 ;
    END
  END out_data[476]
  PIN out_data[477]
    DIRECTION OUTPUT ;
    USE SIGNAL ;
    PORT
      LAYER M4 ;
        RECT  0 92.928 0.084 92.952 ;
    END
  END out_data[477]
  PIN out_data[478]
    DIRECTION OUTPUT ;
    USE SIGNAL ;
    PORT
      LAYER M4 ;
        RECT  0 92.976 0.084 93 ;
    END
  END out_data[478]
  PIN out_data[479]
    DIRECTION OUTPUT ;
    USE SIGNAL ;
    PORT
      LAYER M4 ;
        RECT  0 93.024 0.084 93.048 ;
    END
  END out_data[479]
  PIN out_data[47]
    DIRECTION OUTPUT ;
    USE SIGNAL ;
    PORT
      LAYER M4 ;
        RECT  0 72.288 0.084 72.312 ;
    END
  END out_data[47]
  PIN out_data[480]
    DIRECTION OUTPUT ;
    USE SIGNAL ;
    PORT
      LAYER M4 ;
        RECT  0 93.072 0.084 93.096 ;
    END
  END out_data[480]
  PIN out_data[481]
    DIRECTION OUTPUT ;
    USE SIGNAL ;
    PORT
      LAYER M4 ;
        RECT  0 93.12 0.084 93.144 ;
    END
  END out_data[481]
  PIN out_data[482]
    DIRECTION OUTPUT ;
    USE SIGNAL ;
    PORT
      LAYER M4 ;
        RECT  0 93.168 0.084 93.192 ;
    END
  END out_data[482]
  PIN out_data[483]
    DIRECTION OUTPUT ;
    USE SIGNAL ;
    PORT
      LAYER M4 ;
        RECT  0 93.216 0.084 93.24 ;
    END
  END out_data[483]
  PIN out_data[484]
    DIRECTION OUTPUT ;
    USE SIGNAL ;
    PORT
      LAYER M4 ;
        RECT  0 93.264 0.084 93.288 ;
    END
  END out_data[484]
  PIN out_data[485]
    DIRECTION OUTPUT ;
    USE SIGNAL ;
    PORT
      LAYER M4 ;
        RECT  0 93.312 0.084 93.336 ;
    END
  END out_data[485]
  PIN out_data[486]
    DIRECTION OUTPUT ;
    USE SIGNAL ;
    PORT
      LAYER M4 ;
        RECT  0 93.36 0.084 93.384 ;
    END
  END out_data[486]
  PIN out_data[487]
    DIRECTION OUTPUT ;
    USE SIGNAL ;
    PORT
      LAYER M4 ;
        RECT  0 93.408 0.084 93.432 ;
    END
  END out_data[487]
  PIN out_data[488]
    DIRECTION OUTPUT ;
    USE SIGNAL ;
    PORT
      LAYER M4 ;
        RECT  0 93.456 0.084 93.48 ;
    END
  END out_data[488]
  PIN out_data[489]
    DIRECTION OUTPUT ;
    USE SIGNAL ;
    PORT
      LAYER M4 ;
        RECT  0 93.504 0.084 93.528 ;
    END
  END out_data[489]
  PIN out_data[48]
    DIRECTION OUTPUT ;
    USE SIGNAL ;
    PORT
      LAYER M4 ;
        RECT  0 72.336 0.084 72.36 ;
    END
  END out_data[48]
  PIN out_data[490]
    DIRECTION OUTPUT ;
    USE SIGNAL ;
    PORT
      LAYER M4 ;
        RECT  0 93.552 0.084 93.576 ;
    END
  END out_data[490]
  PIN out_data[491]
    DIRECTION OUTPUT ;
    USE SIGNAL ;
    PORT
      LAYER M4 ;
        RECT  0 93.6 0.084 93.624 ;
    END
  END out_data[491]
  PIN out_data[492]
    DIRECTION OUTPUT ;
    USE SIGNAL ;
    PORT
      LAYER M4 ;
        RECT  0 93.648 0.084 93.672 ;
    END
  END out_data[492]
  PIN out_data[493]
    DIRECTION OUTPUT ;
    USE SIGNAL ;
    PORT
      LAYER M4 ;
        RECT  0 93.696 0.084 93.72 ;
    END
  END out_data[493]
  PIN out_data[494]
    DIRECTION OUTPUT ;
    USE SIGNAL ;
    PORT
      LAYER M4 ;
        RECT  0 93.744 0.084 93.768 ;
    END
  END out_data[494]
  PIN out_data[495]
    DIRECTION OUTPUT ;
    USE SIGNAL ;
    PORT
      LAYER M4 ;
        RECT  0 93.792 0.084 93.816 ;
    END
  END out_data[495]
  PIN out_data[496]
    DIRECTION OUTPUT ;
    USE SIGNAL ;
    PORT
      LAYER M4 ;
        RECT  0 93.84 0.084 93.864 ;
    END
  END out_data[496]
  PIN out_data[497]
    DIRECTION OUTPUT ;
    USE SIGNAL ;
    PORT
      LAYER M4 ;
        RECT  0 93.888 0.084 93.912 ;
    END
  END out_data[497]
  PIN out_data[498]
    DIRECTION OUTPUT ;
    USE SIGNAL ;
    PORT
      LAYER M4 ;
        RECT  0 93.936 0.084 93.96 ;
    END
  END out_data[498]
  PIN out_data[499]
    DIRECTION OUTPUT ;
    USE SIGNAL ;
    PORT
      LAYER M4 ;
        RECT  0 93.984 0.084 94.008 ;
    END
  END out_data[499]
  PIN out_data[49]
    DIRECTION OUTPUT ;
    USE SIGNAL ;
    PORT
      LAYER M4 ;
        RECT  0 72.384 0.084 72.408 ;
    END
  END out_data[49]
  PIN out_data[4]
    DIRECTION OUTPUT ;
    USE SIGNAL ;
    PORT
      LAYER M4 ;
        RECT  0 70.224 0.084 70.248 ;
    END
  END out_data[4]
  PIN out_data[500]
    DIRECTION OUTPUT ;
    USE SIGNAL ;
    PORT
      LAYER M4 ;
        RECT  0 94.032 0.084 94.056 ;
    END
  END out_data[500]
  PIN out_data[501]
    DIRECTION OUTPUT ;
    USE SIGNAL ;
    PORT
      LAYER M4 ;
        RECT  0 94.08 0.084 94.104 ;
    END
  END out_data[501]
  PIN out_data[502]
    DIRECTION OUTPUT ;
    USE SIGNAL ;
    PORT
      LAYER M4 ;
        RECT  0 94.128 0.084 94.152 ;
    END
  END out_data[502]
  PIN out_data[503]
    DIRECTION OUTPUT ;
    USE SIGNAL ;
    PORT
      LAYER M4 ;
        RECT  0 94.176 0.084 94.2 ;
    END
  END out_data[503]
  PIN out_data[504]
    DIRECTION OUTPUT ;
    USE SIGNAL ;
    PORT
      LAYER M4 ;
        RECT  0 94.224 0.084 94.248 ;
    END
  END out_data[504]
  PIN out_data[505]
    DIRECTION OUTPUT ;
    USE SIGNAL ;
    PORT
      LAYER M4 ;
        RECT  0 94.272 0.084 94.296 ;
    END
  END out_data[505]
  PIN out_data[506]
    DIRECTION OUTPUT ;
    USE SIGNAL ;
    PORT
      LAYER M4 ;
        RECT  0 94.32 0.084 94.344 ;
    END
  END out_data[506]
  PIN out_data[507]
    DIRECTION OUTPUT ;
    USE SIGNAL ;
    PORT
      LAYER M4 ;
        RECT  0 94.368 0.084 94.392 ;
    END
  END out_data[507]
  PIN out_data[508]
    DIRECTION OUTPUT ;
    USE SIGNAL ;
    PORT
      LAYER M4 ;
        RECT  0 94.416 0.084 94.44 ;
    END
  END out_data[508]
  PIN out_data[509]
    DIRECTION OUTPUT ;
    USE SIGNAL ;
    PORT
      LAYER M4 ;
        RECT  0 94.464 0.084 94.488 ;
    END
  END out_data[509]
  PIN out_data[50]
    DIRECTION OUTPUT ;
    USE SIGNAL ;
    PORT
      LAYER M4 ;
        RECT  0 72.432 0.084 72.456 ;
    END
  END out_data[50]
  PIN out_data[510]
    DIRECTION OUTPUT ;
    USE SIGNAL ;
    PORT
      LAYER M4 ;
        RECT  0 94.512 0.084 94.536 ;
    END
  END out_data[510]
  PIN out_data[511]
    DIRECTION OUTPUT ;
    USE SIGNAL ;
    PORT
      LAYER M4 ;
        RECT  0 94.56 0.084 94.584 ;
    END
  END out_data[511]
  PIN out_data[51]
    DIRECTION OUTPUT ;
    USE SIGNAL ;
    PORT
      LAYER M4 ;
        RECT  0 72.48 0.084 72.504 ;
    END
  END out_data[51]
  PIN out_data[52]
    DIRECTION OUTPUT ;
    USE SIGNAL ;
    PORT
      LAYER M4 ;
        RECT  0 72.528 0.084 72.552 ;
    END
  END out_data[52]
  PIN out_data[53]
    DIRECTION OUTPUT ;
    USE SIGNAL ;
    PORT
      LAYER M4 ;
        RECT  0 72.576 0.084 72.6 ;
    END
  END out_data[53]
  PIN out_data[54]
    DIRECTION OUTPUT ;
    USE SIGNAL ;
    PORT
      LAYER M4 ;
        RECT  0 72.624 0.084 72.648 ;
    END
  END out_data[54]
  PIN out_data[55]
    DIRECTION OUTPUT ;
    USE SIGNAL ;
    PORT
      LAYER M4 ;
        RECT  0 72.672 0.084 72.696 ;
    END
  END out_data[55]
  PIN out_data[56]
    DIRECTION OUTPUT ;
    USE SIGNAL ;
    PORT
      LAYER M4 ;
        RECT  0 72.72 0.084 72.744 ;
    END
  END out_data[56]
  PIN out_data[57]
    DIRECTION OUTPUT ;
    USE SIGNAL ;
    PORT
      LAYER M4 ;
        RECT  0 72.768 0.084 72.792 ;
    END
  END out_data[57]
  PIN out_data[58]
    DIRECTION OUTPUT ;
    USE SIGNAL ;
    PORT
      LAYER M4 ;
        RECT  0 72.816 0.084 72.84 ;
    END
  END out_data[58]
  PIN out_data[59]
    DIRECTION OUTPUT ;
    USE SIGNAL ;
    PORT
      LAYER M4 ;
        RECT  0 72.864 0.084 72.888 ;
    END
  END out_data[59]
  PIN out_data[5]
    DIRECTION OUTPUT ;
    USE SIGNAL ;
    PORT
      LAYER M4 ;
        RECT  0 70.272 0.084 70.296 ;
    END
  END out_data[5]
  PIN out_data[60]
    DIRECTION OUTPUT ;
    USE SIGNAL ;
    PORT
      LAYER M4 ;
        RECT  0 72.912 0.084 72.936 ;
    END
  END out_data[60]
  PIN out_data[61]
    DIRECTION OUTPUT ;
    USE SIGNAL ;
    PORT
      LAYER M4 ;
        RECT  0 72.96 0.084 72.984 ;
    END
  END out_data[61]
  PIN out_data[62]
    DIRECTION OUTPUT ;
    USE SIGNAL ;
    PORT
      LAYER M4 ;
        RECT  0 73.008 0.084 73.032 ;
    END
  END out_data[62]
  PIN out_data[63]
    DIRECTION OUTPUT ;
    USE SIGNAL ;
    PORT
      LAYER M4 ;
        RECT  0 73.056 0.084 73.08 ;
    END
  END out_data[63]
  PIN out_data[64]
    DIRECTION OUTPUT ;
    USE SIGNAL ;
    PORT
      LAYER M4 ;
        RECT  0 73.104 0.084 73.128 ;
    END
  END out_data[64]
  PIN out_data[65]
    DIRECTION OUTPUT ;
    USE SIGNAL ;
    PORT
      LAYER M4 ;
        RECT  0 73.152 0.084 73.176 ;
    END
  END out_data[65]
  PIN out_data[66]
    DIRECTION OUTPUT ;
    USE SIGNAL ;
    PORT
      LAYER M4 ;
        RECT  0 73.2 0.084 73.224 ;
    END
  END out_data[66]
  PIN out_data[67]
    DIRECTION OUTPUT ;
    USE SIGNAL ;
    PORT
      LAYER M4 ;
        RECT  0 73.248 0.084 73.272 ;
    END
  END out_data[67]
  PIN out_data[68]
    DIRECTION OUTPUT ;
    USE SIGNAL ;
    PORT
      LAYER M4 ;
        RECT  0 73.296 0.084 73.32 ;
    END
  END out_data[68]
  PIN out_data[69]
    DIRECTION OUTPUT ;
    USE SIGNAL ;
    PORT
      LAYER M4 ;
        RECT  0 73.344 0.084 73.368 ;
    END
  END out_data[69]
  PIN out_data[6]
    DIRECTION OUTPUT ;
    USE SIGNAL ;
    PORT
      LAYER M4 ;
        RECT  0 70.32 0.084 70.344 ;
    END
  END out_data[6]
  PIN out_data[70]
    DIRECTION OUTPUT ;
    USE SIGNAL ;
    PORT
      LAYER M4 ;
        RECT  0 73.392 0.084 73.416 ;
    END
  END out_data[70]
  PIN out_data[71]
    DIRECTION OUTPUT ;
    USE SIGNAL ;
    PORT
      LAYER M4 ;
        RECT  0 73.44 0.084 73.464 ;
    END
  END out_data[71]
  PIN out_data[72]
    DIRECTION OUTPUT ;
    USE SIGNAL ;
    PORT
      LAYER M4 ;
        RECT  0 73.488 0.084 73.512 ;
    END
  END out_data[72]
  PIN out_data[73]
    DIRECTION OUTPUT ;
    USE SIGNAL ;
    PORT
      LAYER M4 ;
        RECT  0 73.536 0.084 73.56 ;
    END
  END out_data[73]
  PIN out_data[74]
    DIRECTION OUTPUT ;
    USE SIGNAL ;
    PORT
      LAYER M4 ;
        RECT  0 73.584 0.084 73.608 ;
    END
  END out_data[74]
  PIN out_data[75]
    DIRECTION OUTPUT ;
    USE SIGNAL ;
    PORT
      LAYER M4 ;
        RECT  0 73.632 0.084 73.656 ;
    END
  END out_data[75]
  PIN out_data[76]
    DIRECTION OUTPUT ;
    USE SIGNAL ;
    PORT
      LAYER M4 ;
        RECT  0 73.68 0.084 73.704 ;
    END
  END out_data[76]
  PIN out_data[77]
    DIRECTION OUTPUT ;
    USE SIGNAL ;
    PORT
      LAYER M4 ;
        RECT  0 73.728 0.084 73.752 ;
    END
  END out_data[77]
  PIN out_data[78]
    DIRECTION OUTPUT ;
    USE SIGNAL ;
    PORT
      LAYER M4 ;
        RECT  0 73.776 0.084 73.8 ;
    END
  END out_data[78]
  PIN out_data[79]
    DIRECTION OUTPUT ;
    USE SIGNAL ;
    PORT
      LAYER M4 ;
        RECT  0 73.824 0.084 73.848 ;
    END
  END out_data[79]
  PIN out_data[7]
    DIRECTION OUTPUT ;
    USE SIGNAL ;
    PORT
      LAYER M4 ;
        RECT  0 70.368 0.084 70.392 ;
    END
  END out_data[7]
  PIN out_data[80]
    DIRECTION OUTPUT ;
    USE SIGNAL ;
    PORT
      LAYER M4 ;
        RECT  0 73.872 0.084 73.896 ;
    END
  END out_data[80]
  PIN out_data[81]
    DIRECTION OUTPUT ;
    USE SIGNAL ;
    PORT
      LAYER M4 ;
        RECT  0 73.92 0.084 73.944 ;
    END
  END out_data[81]
  PIN out_data[82]
    DIRECTION OUTPUT ;
    USE SIGNAL ;
    PORT
      LAYER M4 ;
        RECT  0 73.968 0.084 73.992 ;
    END
  END out_data[82]
  PIN out_data[83]
    DIRECTION OUTPUT ;
    USE SIGNAL ;
    PORT
      LAYER M4 ;
        RECT  0 74.016 0.084 74.04 ;
    END
  END out_data[83]
  PIN out_data[84]
    DIRECTION OUTPUT ;
    USE SIGNAL ;
    PORT
      LAYER M4 ;
        RECT  0 74.064 0.084 74.088 ;
    END
  END out_data[84]
  PIN out_data[85]
    DIRECTION OUTPUT ;
    USE SIGNAL ;
    PORT
      LAYER M4 ;
        RECT  0 74.112 0.084 74.136 ;
    END
  END out_data[85]
  PIN out_data[86]
    DIRECTION OUTPUT ;
    USE SIGNAL ;
    PORT
      LAYER M4 ;
        RECT  0 74.16 0.084 74.184 ;
    END
  END out_data[86]
  PIN out_data[87]
    DIRECTION OUTPUT ;
    USE SIGNAL ;
    PORT
      LAYER M4 ;
        RECT  0 74.208 0.084 74.232 ;
    END
  END out_data[87]
  PIN out_data[88]
    DIRECTION OUTPUT ;
    USE SIGNAL ;
    PORT
      LAYER M4 ;
        RECT  0 74.256 0.084 74.28 ;
    END
  END out_data[88]
  PIN out_data[89]
    DIRECTION OUTPUT ;
    USE SIGNAL ;
    PORT
      LAYER M4 ;
        RECT  0 74.304 0.084 74.328 ;
    END
  END out_data[89]
  PIN out_data[8]
    DIRECTION OUTPUT ;
    USE SIGNAL ;
    PORT
      LAYER M4 ;
        RECT  0 70.416 0.084 70.44 ;
    END
  END out_data[8]
  PIN out_data[90]
    DIRECTION OUTPUT ;
    USE SIGNAL ;
    PORT
      LAYER M4 ;
        RECT  0 74.352 0.084 74.376 ;
    END
  END out_data[90]
  PIN out_data[91]
    DIRECTION OUTPUT ;
    USE SIGNAL ;
    PORT
      LAYER M4 ;
        RECT  0 74.4 0.084 74.424 ;
    END
  END out_data[91]
  PIN out_data[92]
    DIRECTION OUTPUT ;
    USE SIGNAL ;
    PORT
      LAYER M4 ;
        RECT  0 74.448 0.084 74.472 ;
    END
  END out_data[92]
  PIN out_data[93]
    DIRECTION OUTPUT ;
    USE SIGNAL ;
    PORT
      LAYER M4 ;
        RECT  0 74.496 0.084 74.52 ;
    END
  END out_data[93]
  PIN out_data[94]
    DIRECTION OUTPUT ;
    USE SIGNAL ;
    PORT
      LAYER M4 ;
        RECT  0 74.544 0.084 74.568 ;
    END
  END out_data[94]
  PIN out_data[95]
    DIRECTION OUTPUT ;
    USE SIGNAL ;
    PORT
      LAYER M4 ;
        RECT  0 74.592 0.084 74.616 ;
    END
  END out_data[95]
  PIN out_data[96]
    DIRECTION OUTPUT ;
    USE SIGNAL ;
    PORT
      LAYER M4 ;
        RECT  0 74.64 0.084 74.664 ;
    END
  END out_data[96]
  PIN out_data[97]
    DIRECTION OUTPUT ;
    USE SIGNAL ;
    PORT
      LAYER M4 ;
        RECT  0 74.688 0.084 74.712 ;
    END
  END out_data[97]
  PIN out_data[98]
    DIRECTION OUTPUT ;
    USE SIGNAL ;
    PORT
      LAYER M4 ;
        RECT  0 74.736 0.084 74.76 ;
    END
  END out_data[98]
  PIN out_data[99]
    DIRECTION OUTPUT ;
    USE SIGNAL ;
    PORT
      LAYER M4 ;
        RECT  0 74.784 0.084 74.808 ;
    END
  END out_data[99]
  PIN out_data[9]
    DIRECTION OUTPUT ;
    USE SIGNAL ;
    PORT
      LAYER M4 ;
        RECT  0 70.464 0.084 70.488 ;
    END
  END out_data[9]
  PIN out_last
    DIRECTION OUTPUT ;
    USE SIGNAL ;
    PORT
      LAYER M4 ;
        RECT  0 94.608 0.084 94.632 ;
    END
  END out_last
  PIN out_ready
    DIRECTION INPUT ;
    USE SIGNAL ;
    PORT
      LAYER M4 ;
        RECT  0 94.656 0.084 94.68 ;
    END
  END out_ready
  PIN out_valid
    DIRECTION OUTPUT ;
    USE SIGNAL ;
    PORT
      LAYER M4 ;
        RECT  0 94.704 0.084 94.728 ;
    END
  END out_valid
  PIN pr_pos[0]
    DIRECTION OUTPUT ;
    USE SIGNAL ;
    PORT
      LAYER M5 ;
        RECT  71.328 139.916 71.352 140 ;
    END
  END pr_pos[0]
  PIN pr_pos[10]
    DIRECTION OUTPUT ;
    USE SIGNAL ;
    PORT
      LAYER M5 ;
        RECT  71.808 139.916 71.832 140 ;
    END
  END pr_pos[10]
  PIN pr_pos[11]
    DIRECTION OUTPUT ;
    USE SIGNAL ;
    PORT
      LAYER M5 ;
        RECT  71.856 139.916 71.88 140 ;
    END
  END pr_pos[11]
  PIN pr_pos[12]
    DIRECTION OUTPUT ;
    USE SIGNAL ;
    PORT
      LAYER M5 ;
        RECT  71.904 139.916 71.928 140 ;
    END
  END pr_pos[12]
  PIN pr_pos[13]
    DIRECTION OUTPUT ;
    USE SIGNAL ;
    PORT
      LAYER M5 ;
        RECT  71.952 139.916 71.976 140 ;
    END
  END pr_pos[13]
  PIN pr_pos[14]
    DIRECTION OUTPUT ;
    USE SIGNAL ;
    PORT
      LAYER M5 ;
        RECT  72 139.916 72.024 140 ;
    END
  END pr_pos[14]
  PIN pr_pos[15]
    DIRECTION OUTPUT ;
    USE SIGNAL ;
    PORT
      LAYER M5 ;
        RECT  72.048 139.916 72.072 140 ;
    END
  END pr_pos[15]
  PIN pr_pos[1]
    DIRECTION OUTPUT ;
    USE SIGNAL ;
    PORT
      LAYER M5 ;
        RECT  71.376 139.916 71.4 140 ;
    END
  END pr_pos[1]
  PIN pr_pos[2]
    DIRECTION OUTPUT ;
    USE SIGNAL ;
    PORT
      LAYER M5 ;
        RECT  71.424 139.916 71.448 140 ;
    END
  END pr_pos[2]
  PIN pr_pos[3]
    DIRECTION OUTPUT ;
    USE SIGNAL ;
    PORT
      LAYER M5 ;
        RECT  71.472 139.916 71.496 140 ;
    END
  END pr_pos[3]
  PIN pr_pos[4]
    DIRECTION OUTPUT ;
    USE SIGNAL ;
    PORT
      LAYER M5 ;
        RECT  71.52 139.916 71.544 140 ;
    END
  END pr_pos[4]
  PIN pr_pos[5]
    DIRECTION OUTPUT ;
    USE SIGNAL ;
    PORT
      LAYER M5 ;
        RECT  71.568 139.916 71.592 140 ;
    END
  END pr_pos[5]
  PIN pr_pos[6]
    DIRECTION OUTPUT ;
    USE SIGNAL ;
    PORT
      LAYER M5 ;
        RECT  71.616 139.916 71.64 140 ;
    END
  END pr_pos[6]
  PIN pr_pos[7]
    DIRECTION OUTPUT ;
    USE SIGNAL ;
    PORT
      LAYER M5 ;
        RECT  71.664 139.916 71.688 140 ;
    END
  END pr_pos[7]
  PIN pr_pos[8]
    DIRECTION OUTPUT ;
    USE SIGNAL ;
    PORT
      LAYER M5 ;
        RECT  71.712 139.916 71.736 140 ;
    END
  END pr_pos[8]
  PIN pr_pos[9]
    DIRECTION OUTPUT ;
    USE SIGNAL ;
    PORT
      LAYER M5 ;
        RECT  71.76 139.916 71.784 140 ;
    END
  END pr_pos[9]
  PIN pr_q[0]
    DIRECTION INPUT ;
    USE SIGNAL ;
    PORT
      LAYER M5 ;
        RECT  72.096 139.916 72.12 140 ;
    END
  END pr_q[0]
  PIN pr_q[10]
    DIRECTION INPUT ;
    USE SIGNAL ;
    PORT
      LAYER M5 ;
        RECT  72.576 139.916 72.6 140 ;
    END
  END pr_q[10]
  PIN pr_q[11]
    DIRECTION INPUT ;
    USE SIGNAL ;
    PORT
      LAYER M5 ;
        RECT  72.624 139.916 72.648 140 ;
    END
  END pr_q[11]
  PIN pr_q[12]
    DIRECTION INPUT ;
    USE SIGNAL ;
    PORT
      LAYER M5 ;
        RECT  72.672 139.916 72.696 140 ;
    END
  END pr_q[12]
  PIN pr_q[13]
    DIRECTION INPUT ;
    USE SIGNAL ;
    PORT
      LAYER M5 ;
        RECT  72.72 139.916 72.744 140 ;
    END
  END pr_q[13]
  PIN pr_q[14]
    DIRECTION INPUT ;
    USE SIGNAL ;
    PORT
      LAYER M5 ;
        RECT  72.768 139.916 72.792 140 ;
    END
  END pr_q[14]
  PIN pr_q[15]
    DIRECTION INPUT ;
    USE SIGNAL ;
    PORT
      LAYER M5 ;
        RECT  72.816 139.916 72.84 140 ;
    END
  END pr_q[15]
  PIN pr_q[1]
    DIRECTION INPUT ;
    USE SIGNAL ;
    PORT
      LAYER M5 ;
        RECT  72.144 139.916 72.168 140 ;
    END
  END pr_q[1]
  PIN pr_q[2]
    DIRECTION INPUT ;
    USE SIGNAL ;
    PORT
      LAYER M5 ;
        RECT  72.192 139.916 72.216 140 ;
    END
  END pr_q[2]
  PIN pr_q[3]
    DIRECTION INPUT ;
    USE SIGNAL ;
    PORT
      LAYER M5 ;
        RECT  72.24 139.916 72.264 140 ;
    END
  END pr_q[3]
  PIN pr_q[4]
    DIRECTION INPUT ;
    USE SIGNAL ;
    PORT
      LAYER M5 ;
        RECT  72.288 139.916 72.312 140 ;
    END
  END pr_q[4]
  PIN pr_q[5]
    DIRECTION INPUT ;
    USE SIGNAL ;
    PORT
      LAYER M5 ;
        RECT  72.336 139.916 72.36 140 ;
    END
  END pr_q[5]
  PIN pr_q[6]
    DIRECTION INPUT ;
    USE SIGNAL ;
    PORT
      LAYER M5 ;
        RECT  72.384 139.916 72.408 140 ;
    END
  END pr_q[6]
  PIN pr_q[7]
    DIRECTION INPUT ;
    USE SIGNAL ;
    PORT
      LAYER M5 ;
        RECT  72.432 139.916 72.456 140 ;
    END
  END pr_q[7]
  PIN pr_q[8]
    DIRECTION INPUT ;
    USE SIGNAL ;
    PORT
      LAYER M5 ;
        RECT  72.48 139.916 72.504 140 ;
    END
  END pr_q[8]
  PIN pr_q[9]
    DIRECTION INPUT ;
    USE SIGNAL ;
    PORT
      LAYER M5 ;
        RECT  72.528 139.916 72.552 140 ;
    END
  END pr_q[9]
  PIN pr_re
    DIRECTION OUTPUT ;
    USE SIGNAL ;
    PORT
      LAYER M5 ;
        RECT  72.864 139.916 72.888 140 ;
    END
  END pr_re
  PIN pr_user[0]
    DIRECTION OUTPUT ;
    USE SIGNAL ;
    PORT
      LAYER M5 ;
        RECT  72.912 139.916 72.936 140 ;
    END
  END pr_user[0]
  PIN pr_user[1]
    DIRECTION OUTPUT ;
    USE SIGNAL ;
    PORT
      LAYER M5 ;
        RECT  72.96 139.916 72.984 140 ;
    END
  END pr_user[1]
  PIN pr_user[2]
    DIRECTION OUTPUT ;
    USE SIGNAL ;
    PORT
      LAYER M5 ;
        RECT  73.008 139.916 73.032 140 ;
    END
  END pr_user[2]
  PIN pr_user[3]
    DIRECTION OUTPUT ;
    USE SIGNAL ;
    PORT
      LAYER M5 ;
        RECT  73.056 139.916 73.08 140 ;
    END
  END pr_user[3]
  PIN pr_user[4]
    DIRECTION OUTPUT ;
    USE SIGNAL ;
    PORT
      LAYER M5 ;
        RECT  73.104 139.916 73.128 140 ;
    END
  END pr_user[4]
  PIN pr_user[5]
    DIRECTION OUTPUT ;
    USE SIGNAL ;
    PORT
      LAYER M5 ;
        RECT  73.152 139.916 73.176 140 ;
    END
  END pr_user[5]
  PIN pr_user[6]
    DIRECTION OUTPUT ;
    USE SIGNAL ;
    PORT
      LAYER M5 ;
        RECT  73.2 139.916 73.224 140 ;
    END
  END pr_user[6]
  PIN pr_user[7]
    DIRECTION OUTPUT ;
    USE SIGNAL ;
    PORT
      LAYER M5 ;
        RECT  73.248 139.916 73.272 140 ;
    END
  END pr_user[7]
  PIN proto_fault
    DIRECTION OUTPUT ;
    USE SIGNAL ;
    PORT
      LAYER M5 ;
        RECT  73.296 139.916 73.32 140 ;
    END
  END proto_fault
  PIN rst_n
    DIRECTION INPUT ;
    USE SIGNAL ;
    PORT
      LAYER M5 ;
        RECT  73.344 139.916 73.368 140 ;
    END
  END rst_n
  PIN tok_id[0]
    DIRECTION OUTPUT ;
    USE SIGNAL ;
    PORT
      LAYER M5 ;
        RECT  73.392 139.916 73.416 140 ;
    END
  END tok_id[0]
  PIN tok_id[10]
    DIRECTION OUTPUT ;
    USE SIGNAL ;
    PORT
      LAYER M5 ;
        RECT  73.872 139.916 73.896 140 ;
    END
  END tok_id[10]
  PIN tok_id[11]
    DIRECTION OUTPUT ;
    USE SIGNAL ;
    PORT
      LAYER M5 ;
        RECT  73.92 139.916 73.944 140 ;
    END
  END tok_id[11]
  PIN tok_id[12]
    DIRECTION OUTPUT ;
    USE SIGNAL ;
    PORT
      LAYER M5 ;
        RECT  73.968 139.916 73.992 140 ;
    END
  END tok_id[12]
  PIN tok_id[13]
    DIRECTION OUTPUT ;
    USE SIGNAL ;
    PORT
      LAYER M5 ;
        RECT  74.016 139.916 74.04 140 ;
    END
  END tok_id[13]
  PIN tok_id[14]
    DIRECTION OUTPUT ;
    USE SIGNAL ;
    PORT
      LAYER M5 ;
        RECT  74.064 139.916 74.088 140 ;
    END
  END tok_id[14]
  PIN tok_id[15]
    DIRECTION OUTPUT ;
    USE SIGNAL ;
    PORT
      LAYER M5 ;
        RECT  74.112 139.916 74.136 140 ;
    END
  END tok_id[15]
  PIN tok_id[1]
    DIRECTION OUTPUT ;
    USE SIGNAL ;
    PORT
      LAYER M5 ;
        RECT  73.44 139.916 73.464 140 ;
    END
  END tok_id[1]
  PIN tok_id[2]
    DIRECTION OUTPUT ;
    USE SIGNAL ;
    PORT
      LAYER M5 ;
        RECT  73.488 139.916 73.512 140 ;
    END
  END tok_id[2]
  PIN tok_id[3]
    DIRECTION OUTPUT ;
    USE SIGNAL ;
    PORT
      LAYER M5 ;
        RECT  73.536 139.916 73.56 140 ;
    END
  END tok_id[3]
  PIN tok_id[4]
    DIRECTION OUTPUT ;
    USE SIGNAL ;
    PORT
      LAYER M5 ;
        RECT  73.584 139.916 73.608 140 ;
    END
  END tok_id[4]
  PIN tok_id[5]
    DIRECTION OUTPUT ;
    USE SIGNAL ;
    PORT
      LAYER M5 ;
        RECT  73.632 139.916 73.656 140 ;
    END
  END tok_id[5]
  PIN tok_id[6]
    DIRECTION OUTPUT ;
    USE SIGNAL ;
    PORT
      LAYER M5 ;
        RECT  73.68 139.916 73.704 140 ;
    END
  END tok_id[6]
  PIN tok_id[7]
    DIRECTION OUTPUT ;
    USE SIGNAL ;
    PORT
      LAYER M5 ;
        RECT  73.728 139.916 73.752 140 ;
    END
  END tok_id[7]
  PIN tok_id[8]
    DIRECTION OUTPUT ;
    USE SIGNAL ;
    PORT
      LAYER M5 ;
        RECT  73.776 139.916 73.8 140 ;
    END
  END tok_id[8]
  PIN tok_id[9]
    DIRECTION OUTPUT ;
    USE SIGNAL ;
    PORT
      LAYER M5 ;
        RECT  73.824 139.916 73.848 140 ;
    END
  END tok_id[9]
  PIN tok_pos[0]
    DIRECTION OUTPUT ;
    USE SIGNAL ;
    PORT
      LAYER M5 ;
        RECT  74.16 139.916 74.184 140 ;
    END
  END tok_pos[0]
  PIN tok_pos[10]
    DIRECTION OUTPUT ;
    USE SIGNAL ;
    PORT
      LAYER M5 ;
        RECT  74.64 139.916 74.664 140 ;
    END
  END tok_pos[10]
  PIN tok_pos[11]
    DIRECTION OUTPUT ;
    USE SIGNAL ;
    PORT
      LAYER M5 ;
        RECT  74.688 139.916 74.712 140 ;
    END
  END tok_pos[11]
  PIN tok_pos[12]
    DIRECTION OUTPUT ;
    USE SIGNAL ;
    PORT
      LAYER M5 ;
        RECT  74.736 139.916 74.76 140 ;
    END
  END tok_pos[12]
  PIN tok_pos[13]
    DIRECTION OUTPUT ;
    USE SIGNAL ;
    PORT
      LAYER M5 ;
        RECT  74.784 139.916 74.808 140 ;
    END
  END tok_pos[13]
  PIN tok_pos[14]
    DIRECTION OUTPUT ;
    USE SIGNAL ;
    PORT
      LAYER M5 ;
        RECT  74.832 139.916 74.856 140 ;
    END
  END tok_pos[14]
  PIN tok_pos[15]
    DIRECTION OUTPUT ;
    USE SIGNAL ;
    PORT
      LAYER M5 ;
        RECT  74.88 139.916 74.904 140 ;
    END
  END tok_pos[15]
  PIN tok_pos[1]
    DIRECTION OUTPUT ;
    USE SIGNAL ;
    PORT
      LAYER M5 ;
        RECT  74.208 139.916 74.232 140 ;
    END
  END tok_pos[1]
  PIN tok_pos[2]
    DIRECTION OUTPUT ;
    USE SIGNAL ;
    PORT
      LAYER M5 ;
        RECT  74.256 139.916 74.28 140 ;
    END
  END tok_pos[2]
  PIN tok_pos[3]
    DIRECTION OUTPUT ;
    USE SIGNAL ;
    PORT
      LAYER M5 ;
        RECT  74.304 139.916 74.328 140 ;
    END
  END tok_pos[3]
  PIN tok_pos[4]
    DIRECTION OUTPUT ;
    USE SIGNAL ;
    PORT
      LAYER M5 ;
        RECT  74.352 139.916 74.376 140 ;
    END
  END tok_pos[4]
  PIN tok_pos[5]
    DIRECTION OUTPUT ;
    USE SIGNAL ;
    PORT
      LAYER M5 ;
        RECT  74.4 139.916 74.424 140 ;
    END
  END tok_pos[5]
  PIN tok_pos[6]
    DIRECTION OUTPUT ;
    USE SIGNAL ;
    PORT
      LAYER M5 ;
        RECT  74.448 139.916 74.472 140 ;
    END
  END tok_pos[6]
  PIN tok_pos[7]
    DIRECTION OUTPUT ;
    USE SIGNAL ;
    PORT
      LAYER M5 ;
        RECT  74.496 139.916 74.52 140 ;
    END
  END tok_pos[7]
  PIN tok_pos[8]
    DIRECTION OUTPUT ;
    USE SIGNAL ;
    PORT
      LAYER M5 ;
        RECT  74.544 139.916 74.568 140 ;
    END
  END tok_pos[8]
  PIN tok_pos[9]
    DIRECTION OUTPUT ;
    USE SIGNAL ;
    PORT
      LAYER M5 ;
        RECT  74.592 139.916 74.616 140 ;
    END
  END tok_pos[9]
  PIN tok_user[0]
    DIRECTION OUTPUT ;
    USE SIGNAL ;
    PORT
      LAYER M5 ;
        RECT  74.928 139.916 74.952 140 ;
    END
  END tok_user[0]
  PIN tok_user[1]
    DIRECTION OUTPUT ;
    USE SIGNAL ;
    PORT
      LAYER M5 ;
        RECT  74.976 139.916 75 140 ;
    END
  END tok_user[1]
  PIN tok_user[2]
    DIRECTION OUTPUT ;
    USE SIGNAL ;
    PORT
      LAYER M5 ;
        RECT  75.024 139.916 75.048 140 ;
    END
  END tok_user[2]
  PIN tok_user[3]
    DIRECTION OUTPUT ;
    USE SIGNAL ;
    PORT
      LAYER M5 ;
        RECT  75.072 139.916 75.096 140 ;
    END
  END tok_user[3]
  PIN tok_user[4]
    DIRECTION OUTPUT ;
    USE SIGNAL ;
    PORT
      LAYER M5 ;
        RECT  75.12 139.916 75.144 140 ;
    END
  END tok_user[4]
  PIN tok_user[5]
    DIRECTION OUTPUT ;
    USE SIGNAL ;
    PORT
      LAYER M5 ;
        RECT  75.168 139.916 75.192 140 ;
    END
  END tok_user[5]
  PIN tok_user[6]
    DIRECTION OUTPUT ;
    USE SIGNAL ;
    PORT
      LAYER M5 ;
        RECT  75.216 139.916 75.24 140 ;
    END
  END tok_user[6]
  PIN tok_user[7]
    DIRECTION OUTPUT ;
    USE SIGNAL ;
    PORT
      LAYER M5 ;
        RECT  75.264 139.916 75.288 140 ;
    END
  END tok_user[7]
  PIN tok_valid
    DIRECTION OUTPUT ;
    USE SIGNAL ;
    PORT
      LAYER M5 ;
        RECT  75.312 139.916 75.336 140 ;
    END
  END tok_valid
  PIN users_done[0]
    DIRECTION OUTPUT ;
    USE SIGNAL ;
    PORT
      LAYER M5 ;
        RECT  75.36 139.916 75.384 140 ;
    END
  END users_done[0]
  PIN users_done[1]
    DIRECTION OUTPUT ;
    USE SIGNAL ;
    PORT
      LAYER M5 ;
        RECT  75.408 139.916 75.432 140 ;
    END
  END users_done[1]
  PIN users_done[2]
    DIRECTION OUTPUT ;
    USE SIGNAL ;
    PORT
      LAYER M5 ;
        RECT  75.456 139.916 75.48 140 ;
    END
  END users_done[2]
  PIN users_done[3]
    DIRECTION OUTPUT ;
    USE SIGNAL ;
    PORT
      LAYER M5 ;
        RECT  75.504 139.916 75.528 140 ;
    END
  END users_done[3]
  PIN users_done[4]
    DIRECTION OUTPUT ;
    USE SIGNAL ;
    PORT
      LAYER M5 ;
        RECT  75.552 139.916 75.576 140 ;
    END
  END users_done[4]
  PIN users_done[5]
    DIRECTION OUTPUT ;
    USE SIGNAL ;
    PORT
      LAYER M5 ;
        RECT  75.6 139.916 75.624 140 ;
    END
  END users_done[5]
  PIN users_done[6]
    DIRECTION OUTPUT ;
    USE SIGNAL ;
    PORT
      LAYER M5 ;
        RECT  75.648 139.916 75.672 140 ;
    END
  END users_done[6]
  PIN users_done[7]
    DIRECTION OUTPUT ;
    USE SIGNAL ;
    PORT
      LAYER M5 ;
        RECT  75.696 139.916 75.72 140 ;
    END
  END users_done[7]
  PIN vm_raddr[0]
    DIRECTION OUTPUT ;
    USE SIGNAL ;
    PORT
      LAYER M4 ;
        RECT  139.916 44.976 140 45 ;
    END
  END vm_raddr[0]
  PIN vm_raddr[1]
    DIRECTION OUTPUT ;
    USE SIGNAL ;
    PORT
      LAYER M4 ;
        RECT  139.916 45.024 140 45.048 ;
    END
  END vm_raddr[1]
  PIN vm_raddr[2]
    DIRECTION OUTPUT ;
    USE SIGNAL ;
    PORT
      LAYER M4 ;
        RECT  139.916 45.072 140 45.096 ;
    END
  END vm_raddr[2]
  PIN vm_raddr[3]
    DIRECTION OUTPUT ;
    USE SIGNAL ;
    PORT
      LAYER M4 ;
        RECT  139.916 45.12 140 45.144 ;
    END
  END vm_raddr[3]
  PIN vm_raddr[4]
    DIRECTION OUTPUT ;
    USE SIGNAL ;
    PORT
      LAYER M4 ;
        RECT  139.916 45.168 140 45.192 ;
    END
  END vm_raddr[4]
  PIN vm_raddr[5]
    DIRECTION OUTPUT ;
    USE SIGNAL ;
    PORT
      LAYER M4 ;
        RECT  139.916 45.216 140 45.24 ;
    END
  END vm_raddr[5]
  PIN vm_raddr[6]
    DIRECTION OUTPUT ;
    USE SIGNAL ;
    PORT
      LAYER M4 ;
        RECT  139.916 45.264 140 45.288 ;
    END
  END vm_raddr[6]
  PIN vm_raddr[7]
    DIRECTION OUTPUT ;
    USE SIGNAL ;
    PORT
      LAYER M4 ;
        RECT  139.916 45.312 140 45.336 ;
    END
  END vm_raddr[7]
  PIN vm_re
    DIRECTION OUTPUT ;
    USE SIGNAL ;
    PORT
      LAYER M4 ;
        RECT  139.916 45.36 140 45.384 ;
    END
  END vm_re
  PIN vm_rq[0]
    DIRECTION INPUT ;
    USE SIGNAL ;
    PORT
      LAYER M4 ;
        RECT  139.916 45.408 140 45.432 ;
    END
  END vm_rq[0]
  PIN vm_rq[100]
    DIRECTION INPUT ;
    USE SIGNAL ;
    PORT
      LAYER M4 ;
        RECT  139.916 50.208 140 50.232 ;
    END
  END vm_rq[100]
  PIN vm_rq[101]
    DIRECTION INPUT ;
    USE SIGNAL ;
    PORT
      LAYER M4 ;
        RECT  139.916 50.256 140 50.28 ;
    END
  END vm_rq[101]
  PIN vm_rq[102]
    DIRECTION INPUT ;
    USE SIGNAL ;
    PORT
      LAYER M4 ;
        RECT  139.916 50.304 140 50.328 ;
    END
  END vm_rq[102]
  PIN vm_rq[103]
    DIRECTION INPUT ;
    USE SIGNAL ;
    PORT
      LAYER M4 ;
        RECT  139.916 50.352 140 50.376 ;
    END
  END vm_rq[103]
  PIN vm_rq[104]
    DIRECTION INPUT ;
    USE SIGNAL ;
    PORT
      LAYER M4 ;
        RECT  139.916 50.4 140 50.424 ;
    END
  END vm_rq[104]
  PIN vm_rq[105]
    DIRECTION INPUT ;
    USE SIGNAL ;
    PORT
      LAYER M4 ;
        RECT  139.916 50.448 140 50.472 ;
    END
  END vm_rq[105]
  PIN vm_rq[106]
    DIRECTION INPUT ;
    USE SIGNAL ;
    PORT
      LAYER M4 ;
        RECT  139.916 50.496 140 50.52 ;
    END
  END vm_rq[106]
  PIN vm_rq[107]
    DIRECTION INPUT ;
    USE SIGNAL ;
    PORT
      LAYER M4 ;
        RECT  139.916 50.544 140 50.568 ;
    END
  END vm_rq[107]
  PIN vm_rq[108]
    DIRECTION INPUT ;
    USE SIGNAL ;
    PORT
      LAYER M4 ;
        RECT  139.916 50.592 140 50.616 ;
    END
  END vm_rq[108]
  PIN vm_rq[109]
    DIRECTION INPUT ;
    USE SIGNAL ;
    PORT
      LAYER M4 ;
        RECT  139.916 50.64 140 50.664 ;
    END
  END vm_rq[109]
  PIN vm_rq[10]
    DIRECTION INPUT ;
    USE SIGNAL ;
    PORT
      LAYER M4 ;
        RECT  139.916 45.888 140 45.912 ;
    END
  END vm_rq[10]
  PIN vm_rq[110]
    DIRECTION INPUT ;
    USE SIGNAL ;
    PORT
      LAYER M4 ;
        RECT  139.916 50.688 140 50.712 ;
    END
  END vm_rq[110]
  PIN vm_rq[111]
    DIRECTION INPUT ;
    USE SIGNAL ;
    PORT
      LAYER M4 ;
        RECT  139.916 50.736 140 50.76 ;
    END
  END vm_rq[111]
  PIN vm_rq[112]
    DIRECTION INPUT ;
    USE SIGNAL ;
    PORT
      LAYER M4 ;
        RECT  139.916 50.784 140 50.808 ;
    END
  END vm_rq[112]
  PIN vm_rq[113]
    DIRECTION INPUT ;
    USE SIGNAL ;
    PORT
      LAYER M4 ;
        RECT  139.916 50.832 140 50.856 ;
    END
  END vm_rq[113]
  PIN vm_rq[114]
    DIRECTION INPUT ;
    USE SIGNAL ;
    PORT
      LAYER M4 ;
        RECT  139.916 50.88 140 50.904 ;
    END
  END vm_rq[114]
  PIN vm_rq[115]
    DIRECTION INPUT ;
    USE SIGNAL ;
    PORT
      LAYER M4 ;
        RECT  139.916 50.928 140 50.952 ;
    END
  END vm_rq[115]
  PIN vm_rq[116]
    DIRECTION INPUT ;
    USE SIGNAL ;
    PORT
      LAYER M4 ;
        RECT  139.916 50.976 140 51 ;
    END
  END vm_rq[116]
  PIN vm_rq[117]
    DIRECTION INPUT ;
    USE SIGNAL ;
    PORT
      LAYER M4 ;
        RECT  139.916 51.024 140 51.048 ;
    END
  END vm_rq[117]
  PIN vm_rq[118]
    DIRECTION INPUT ;
    USE SIGNAL ;
    PORT
      LAYER M4 ;
        RECT  139.916 51.072 140 51.096 ;
    END
  END vm_rq[118]
  PIN vm_rq[119]
    DIRECTION INPUT ;
    USE SIGNAL ;
    PORT
      LAYER M4 ;
        RECT  139.916 51.12 140 51.144 ;
    END
  END vm_rq[119]
  PIN vm_rq[11]
    DIRECTION INPUT ;
    USE SIGNAL ;
    PORT
      LAYER M4 ;
        RECT  139.916 45.936 140 45.96 ;
    END
  END vm_rq[11]
  PIN vm_rq[120]
    DIRECTION INPUT ;
    USE SIGNAL ;
    PORT
      LAYER M4 ;
        RECT  139.916 51.168 140 51.192 ;
    END
  END vm_rq[120]
  PIN vm_rq[121]
    DIRECTION INPUT ;
    USE SIGNAL ;
    PORT
      LAYER M4 ;
        RECT  139.916 51.216 140 51.24 ;
    END
  END vm_rq[121]
  PIN vm_rq[122]
    DIRECTION INPUT ;
    USE SIGNAL ;
    PORT
      LAYER M4 ;
        RECT  139.916 51.264 140 51.288 ;
    END
  END vm_rq[122]
  PIN vm_rq[123]
    DIRECTION INPUT ;
    USE SIGNAL ;
    PORT
      LAYER M4 ;
        RECT  139.916 51.312 140 51.336 ;
    END
  END vm_rq[123]
  PIN vm_rq[124]
    DIRECTION INPUT ;
    USE SIGNAL ;
    PORT
      LAYER M4 ;
        RECT  139.916 51.36 140 51.384 ;
    END
  END vm_rq[124]
  PIN vm_rq[125]
    DIRECTION INPUT ;
    USE SIGNAL ;
    PORT
      LAYER M4 ;
        RECT  139.916 51.408 140 51.432 ;
    END
  END vm_rq[125]
  PIN vm_rq[126]
    DIRECTION INPUT ;
    USE SIGNAL ;
    PORT
      LAYER M4 ;
        RECT  139.916 51.456 140 51.48 ;
    END
  END vm_rq[126]
  PIN vm_rq[127]
    DIRECTION INPUT ;
    USE SIGNAL ;
    PORT
      LAYER M4 ;
        RECT  139.916 51.504 140 51.528 ;
    END
  END vm_rq[127]
  PIN vm_rq[128]
    DIRECTION INPUT ;
    USE SIGNAL ;
    PORT
      LAYER M4 ;
        RECT  139.916 51.552 140 51.576 ;
    END
  END vm_rq[128]
  PIN vm_rq[129]
    DIRECTION INPUT ;
    USE SIGNAL ;
    PORT
      LAYER M4 ;
        RECT  139.916 51.6 140 51.624 ;
    END
  END vm_rq[129]
  PIN vm_rq[12]
    DIRECTION INPUT ;
    USE SIGNAL ;
    PORT
      LAYER M4 ;
        RECT  139.916 45.984 140 46.008 ;
    END
  END vm_rq[12]
  PIN vm_rq[130]
    DIRECTION INPUT ;
    USE SIGNAL ;
    PORT
      LAYER M4 ;
        RECT  139.916 51.648 140 51.672 ;
    END
  END vm_rq[130]
  PIN vm_rq[131]
    DIRECTION INPUT ;
    USE SIGNAL ;
    PORT
      LAYER M4 ;
        RECT  139.916 51.696 140 51.72 ;
    END
  END vm_rq[131]
  PIN vm_rq[132]
    DIRECTION INPUT ;
    USE SIGNAL ;
    PORT
      LAYER M4 ;
        RECT  139.916 51.744 140 51.768 ;
    END
  END vm_rq[132]
  PIN vm_rq[133]
    DIRECTION INPUT ;
    USE SIGNAL ;
    PORT
      LAYER M4 ;
        RECT  139.916 51.792 140 51.816 ;
    END
  END vm_rq[133]
  PIN vm_rq[134]
    DIRECTION INPUT ;
    USE SIGNAL ;
    PORT
      LAYER M4 ;
        RECT  139.916 51.84 140 51.864 ;
    END
  END vm_rq[134]
  PIN vm_rq[135]
    DIRECTION INPUT ;
    USE SIGNAL ;
    PORT
      LAYER M4 ;
        RECT  139.916 51.888 140 51.912 ;
    END
  END vm_rq[135]
  PIN vm_rq[136]
    DIRECTION INPUT ;
    USE SIGNAL ;
    PORT
      LAYER M4 ;
        RECT  139.916 51.936 140 51.96 ;
    END
  END vm_rq[136]
  PIN vm_rq[137]
    DIRECTION INPUT ;
    USE SIGNAL ;
    PORT
      LAYER M4 ;
        RECT  139.916 51.984 140 52.008 ;
    END
  END vm_rq[137]
  PIN vm_rq[138]
    DIRECTION INPUT ;
    USE SIGNAL ;
    PORT
      LAYER M4 ;
        RECT  139.916 52.032 140 52.056 ;
    END
  END vm_rq[138]
  PIN vm_rq[139]
    DIRECTION INPUT ;
    USE SIGNAL ;
    PORT
      LAYER M4 ;
        RECT  139.916 52.08 140 52.104 ;
    END
  END vm_rq[139]
  PIN vm_rq[13]
    DIRECTION INPUT ;
    USE SIGNAL ;
    PORT
      LAYER M4 ;
        RECT  139.916 46.032 140 46.056 ;
    END
  END vm_rq[13]
  PIN vm_rq[140]
    DIRECTION INPUT ;
    USE SIGNAL ;
    PORT
      LAYER M4 ;
        RECT  139.916 52.128 140 52.152 ;
    END
  END vm_rq[140]
  PIN vm_rq[141]
    DIRECTION INPUT ;
    USE SIGNAL ;
    PORT
      LAYER M4 ;
        RECT  139.916 52.176 140 52.2 ;
    END
  END vm_rq[141]
  PIN vm_rq[142]
    DIRECTION INPUT ;
    USE SIGNAL ;
    PORT
      LAYER M4 ;
        RECT  139.916 52.224 140 52.248 ;
    END
  END vm_rq[142]
  PIN vm_rq[143]
    DIRECTION INPUT ;
    USE SIGNAL ;
    PORT
      LAYER M4 ;
        RECT  139.916 52.272 140 52.296 ;
    END
  END vm_rq[143]
  PIN vm_rq[144]
    DIRECTION INPUT ;
    USE SIGNAL ;
    PORT
      LAYER M4 ;
        RECT  139.916 52.32 140 52.344 ;
    END
  END vm_rq[144]
  PIN vm_rq[145]
    DIRECTION INPUT ;
    USE SIGNAL ;
    PORT
      LAYER M4 ;
        RECT  139.916 52.368 140 52.392 ;
    END
  END vm_rq[145]
  PIN vm_rq[146]
    DIRECTION INPUT ;
    USE SIGNAL ;
    PORT
      LAYER M4 ;
        RECT  139.916 52.416 140 52.44 ;
    END
  END vm_rq[146]
  PIN vm_rq[147]
    DIRECTION INPUT ;
    USE SIGNAL ;
    PORT
      LAYER M4 ;
        RECT  139.916 52.464 140 52.488 ;
    END
  END vm_rq[147]
  PIN vm_rq[148]
    DIRECTION INPUT ;
    USE SIGNAL ;
    PORT
      LAYER M4 ;
        RECT  139.916 52.512 140 52.536 ;
    END
  END vm_rq[148]
  PIN vm_rq[149]
    DIRECTION INPUT ;
    USE SIGNAL ;
    PORT
      LAYER M4 ;
        RECT  139.916 52.56 140 52.584 ;
    END
  END vm_rq[149]
  PIN vm_rq[14]
    DIRECTION INPUT ;
    USE SIGNAL ;
    PORT
      LAYER M4 ;
        RECT  139.916 46.08 140 46.104 ;
    END
  END vm_rq[14]
  PIN vm_rq[150]
    DIRECTION INPUT ;
    USE SIGNAL ;
    PORT
      LAYER M4 ;
        RECT  139.916 52.608 140 52.632 ;
    END
  END vm_rq[150]
  PIN vm_rq[151]
    DIRECTION INPUT ;
    USE SIGNAL ;
    PORT
      LAYER M4 ;
        RECT  139.916 52.656 140 52.68 ;
    END
  END vm_rq[151]
  PIN vm_rq[152]
    DIRECTION INPUT ;
    USE SIGNAL ;
    PORT
      LAYER M4 ;
        RECT  139.916 52.704 140 52.728 ;
    END
  END vm_rq[152]
  PIN vm_rq[153]
    DIRECTION INPUT ;
    USE SIGNAL ;
    PORT
      LAYER M4 ;
        RECT  139.916 52.752 140 52.776 ;
    END
  END vm_rq[153]
  PIN vm_rq[154]
    DIRECTION INPUT ;
    USE SIGNAL ;
    PORT
      LAYER M4 ;
        RECT  139.916 52.8 140 52.824 ;
    END
  END vm_rq[154]
  PIN vm_rq[155]
    DIRECTION INPUT ;
    USE SIGNAL ;
    PORT
      LAYER M4 ;
        RECT  139.916 52.848 140 52.872 ;
    END
  END vm_rq[155]
  PIN vm_rq[156]
    DIRECTION INPUT ;
    USE SIGNAL ;
    PORT
      LAYER M4 ;
        RECT  139.916 52.896 140 52.92 ;
    END
  END vm_rq[156]
  PIN vm_rq[157]
    DIRECTION INPUT ;
    USE SIGNAL ;
    PORT
      LAYER M4 ;
        RECT  139.916 52.944 140 52.968 ;
    END
  END vm_rq[157]
  PIN vm_rq[158]
    DIRECTION INPUT ;
    USE SIGNAL ;
    PORT
      LAYER M4 ;
        RECT  139.916 52.992 140 53.016 ;
    END
  END vm_rq[158]
  PIN vm_rq[159]
    DIRECTION INPUT ;
    USE SIGNAL ;
    PORT
      LAYER M4 ;
        RECT  139.916 53.04 140 53.064 ;
    END
  END vm_rq[159]
  PIN vm_rq[15]
    DIRECTION INPUT ;
    USE SIGNAL ;
    PORT
      LAYER M4 ;
        RECT  139.916 46.128 140 46.152 ;
    END
  END vm_rq[15]
  PIN vm_rq[160]
    DIRECTION INPUT ;
    USE SIGNAL ;
    PORT
      LAYER M4 ;
        RECT  139.916 53.088 140 53.112 ;
    END
  END vm_rq[160]
  PIN vm_rq[161]
    DIRECTION INPUT ;
    USE SIGNAL ;
    PORT
      LAYER M4 ;
        RECT  139.916 53.136 140 53.16 ;
    END
  END vm_rq[161]
  PIN vm_rq[162]
    DIRECTION INPUT ;
    USE SIGNAL ;
    PORT
      LAYER M4 ;
        RECT  139.916 53.184 140 53.208 ;
    END
  END vm_rq[162]
  PIN vm_rq[163]
    DIRECTION INPUT ;
    USE SIGNAL ;
    PORT
      LAYER M4 ;
        RECT  139.916 53.232 140 53.256 ;
    END
  END vm_rq[163]
  PIN vm_rq[164]
    DIRECTION INPUT ;
    USE SIGNAL ;
    PORT
      LAYER M4 ;
        RECT  139.916 53.28 140 53.304 ;
    END
  END vm_rq[164]
  PIN vm_rq[165]
    DIRECTION INPUT ;
    USE SIGNAL ;
    PORT
      LAYER M4 ;
        RECT  139.916 53.328 140 53.352 ;
    END
  END vm_rq[165]
  PIN vm_rq[166]
    DIRECTION INPUT ;
    USE SIGNAL ;
    PORT
      LAYER M4 ;
        RECT  139.916 53.376 140 53.4 ;
    END
  END vm_rq[166]
  PIN vm_rq[167]
    DIRECTION INPUT ;
    USE SIGNAL ;
    PORT
      LAYER M4 ;
        RECT  139.916 53.424 140 53.448 ;
    END
  END vm_rq[167]
  PIN vm_rq[168]
    DIRECTION INPUT ;
    USE SIGNAL ;
    PORT
      LAYER M4 ;
        RECT  139.916 53.472 140 53.496 ;
    END
  END vm_rq[168]
  PIN vm_rq[169]
    DIRECTION INPUT ;
    USE SIGNAL ;
    PORT
      LAYER M4 ;
        RECT  139.916 53.52 140 53.544 ;
    END
  END vm_rq[169]
  PIN vm_rq[16]
    DIRECTION INPUT ;
    USE SIGNAL ;
    PORT
      LAYER M4 ;
        RECT  139.916 46.176 140 46.2 ;
    END
  END vm_rq[16]
  PIN vm_rq[170]
    DIRECTION INPUT ;
    USE SIGNAL ;
    PORT
      LAYER M4 ;
        RECT  139.916 53.568 140 53.592 ;
    END
  END vm_rq[170]
  PIN vm_rq[171]
    DIRECTION INPUT ;
    USE SIGNAL ;
    PORT
      LAYER M4 ;
        RECT  139.916 53.616 140 53.64 ;
    END
  END vm_rq[171]
  PIN vm_rq[172]
    DIRECTION INPUT ;
    USE SIGNAL ;
    PORT
      LAYER M4 ;
        RECT  139.916 53.664 140 53.688 ;
    END
  END vm_rq[172]
  PIN vm_rq[173]
    DIRECTION INPUT ;
    USE SIGNAL ;
    PORT
      LAYER M4 ;
        RECT  139.916 53.712 140 53.736 ;
    END
  END vm_rq[173]
  PIN vm_rq[174]
    DIRECTION INPUT ;
    USE SIGNAL ;
    PORT
      LAYER M4 ;
        RECT  139.916 53.76 140 53.784 ;
    END
  END vm_rq[174]
  PIN vm_rq[175]
    DIRECTION INPUT ;
    USE SIGNAL ;
    PORT
      LAYER M4 ;
        RECT  139.916 53.808 140 53.832 ;
    END
  END vm_rq[175]
  PIN vm_rq[176]
    DIRECTION INPUT ;
    USE SIGNAL ;
    PORT
      LAYER M4 ;
        RECT  139.916 53.856 140 53.88 ;
    END
  END vm_rq[176]
  PIN vm_rq[177]
    DIRECTION INPUT ;
    USE SIGNAL ;
    PORT
      LAYER M4 ;
        RECT  139.916 53.904 140 53.928 ;
    END
  END vm_rq[177]
  PIN vm_rq[178]
    DIRECTION INPUT ;
    USE SIGNAL ;
    PORT
      LAYER M4 ;
        RECT  139.916 53.952 140 53.976 ;
    END
  END vm_rq[178]
  PIN vm_rq[179]
    DIRECTION INPUT ;
    USE SIGNAL ;
    PORT
      LAYER M4 ;
        RECT  139.916 54 140 54.024 ;
    END
  END vm_rq[179]
  PIN vm_rq[17]
    DIRECTION INPUT ;
    USE SIGNAL ;
    PORT
      LAYER M4 ;
        RECT  139.916 46.224 140 46.248 ;
    END
  END vm_rq[17]
  PIN vm_rq[180]
    DIRECTION INPUT ;
    USE SIGNAL ;
    PORT
      LAYER M4 ;
        RECT  139.916 54.048 140 54.072 ;
    END
  END vm_rq[180]
  PIN vm_rq[181]
    DIRECTION INPUT ;
    USE SIGNAL ;
    PORT
      LAYER M4 ;
        RECT  139.916 54.096 140 54.12 ;
    END
  END vm_rq[181]
  PIN vm_rq[182]
    DIRECTION INPUT ;
    USE SIGNAL ;
    PORT
      LAYER M4 ;
        RECT  139.916 54.144 140 54.168 ;
    END
  END vm_rq[182]
  PIN vm_rq[183]
    DIRECTION INPUT ;
    USE SIGNAL ;
    PORT
      LAYER M4 ;
        RECT  139.916 54.192 140 54.216 ;
    END
  END vm_rq[183]
  PIN vm_rq[184]
    DIRECTION INPUT ;
    USE SIGNAL ;
    PORT
      LAYER M4 ;
        RECT  139.916 54.24 140 54.264 ;
    END
  END vm_rq[184]
  PIN vm_rq[185]
    DIRECTION INPUT ;
    USE SIGNAL ;
    PORT
      LAYER M4 ;
        RECT  139.916 54.288 140 54.312 ;
    END
  END vm_rq[185]
  PIN vm_rq[186]
    DIRECTION INPUT ;
    USE SIGNAL ;
    PORT
      LAYER M4 ;
        RECT  139.916 54.336 140 54.36 ;
    END
  END vm_rq[186]
  PIN vm_rq[187]
    DIRECTION INPUT ;
    USE SIGNAL ;
    PORT
      LAYER M4 ;
        RECT  139.916 54.384 140 54.408 ;
    END
  END vm_rq[187]
  PIN vm_rq[188]
    DIRECTION INPUT ;
    USE SIGNAL ;
    PORT
      LAYER M4 ;
        RECT  139.916 54.432 140 54.456 ;
    END
  END vm_rq[188]
  PIN vm_rq[189]
    DIRECTION INPUT ;
    USE SIGNAL ;
    PORT
      LAYER M4 ;
        RECT  139.916 54.48 140 54.504 ;
    END
  END vm_rq[189]
  PIN vm_rq[18]
    DIRECTION INPUT ;
    USE SIGNAL ;
    PORT
      LAYER M4 ;
        RECT  139.916 46.272 140 46.296 ;
    END
  END vm_rq[18]
  PIN vm_rq[190]
    DIRECTION INPUT ;
    USE SIGNAL ;
    PORT
      LAYER M4 ;
        RECT  139.916 54.528 140 54.552 ;
    END
  END vm_rq[190]
  PIN vm_rq[191]
    DIRECTION INPUT ;
    USE SIGNAL ;
    PORT
      LAYER M4 ;
        RECT  139.916 54.576 140 54.6 ;
    END
  END vm_rq[191]
  PIN vm_rq[192]
    DIRECTION INPUT ;
    USE SIGNAL ;
    PORT
      LAYER M4 ;
        RECT  139.916 54.624 140 54.648 ;
    END
  END vm_rq[192]
  PIN vm_rq[193]
    DIRECTION INPUT ;
    USE SIGNAL ;
    PORT
      LAYER M4 ;
        RECT  139.916 54.672 140 54.696 ;
    END
  END vm_rq[193]
  PIN vm_rq[194]
    DIRECTION INPUT ;
    USE SIGNAL ;
    PORT
      LAYER M4 ;
        RECT  139.916 54.72 140 54.744 ;
    END
  END vm_rq[194]
  PIN vm_rq[195]
    DIRECTION INPUT ;
    USE SIGNAL ;
    PORT
      LAYER M4 ;
        RECT  139.916 54.768 140 54.792 ;
    END
  END vm_rq[195]
  PIN vm_rq[196]
    DIRECTION INPUT ;
    USE SIGNAL ;
    PORT
      LAYER M4 ;
        RECT  139.916 54.816 140 54.84 ;
    END
  END vm_rq[196]
  PIN vm_rq[197]
    DIRECTION INPUT ;
    USE SIGNAL ;
    PORT
      LAYER M4 ;
        RECT  139.916 54.864 140 54.888 ;
    END
  END vm_rq[197]
  PIN vm_rq[198]
    DIRECTION INPUT ;
    USE SIGNAL ;
    PORT
      LAYER M4 ;
        RECT  139.916 54.912 140 54.936 ;
    END
  END vm_rq[198]
  PIN vm_rq[199]
    DIRECTION INPUT ;
    USE SIGNAL ;
    PORT
      LAYER M4 ;
        RECT  139.916 54.96 140 54.984 ;
    END
  END vm_rq[199]
  PIN vm_rq[19]
    DIRECTION INPUT ;
    USE SIGNAL ;
    PORT
      LAYER M4 ;
        RECT  139.916 46.32 140 46.344 ;
    END
  END vm_rq[19]
  PIN vm_rq[1]
    DIRECTION INPUT ;
    USE SIGNAL ;
    PORT
      LAYER M4 ;
        RECT  139.916 45.456 140 45.48 ;
    END
  END vm_rq[1]
  PIN vm_rq[200]
    DIRECTION INPUT ;
    USE SIGNAL ;
    PORT
      LAYER M4 ;
        RECT  139.916 55.008 140 55.032 ;
    END
  END vm_rq[200]
  PIN vm_rq[201]
    DIRECTION INPUT ;
    USE SIGNAL ;
    PORT
      LAYER M4 ;
        RECT  139.916 55.056 140 55.08 ;
    END
  END vm_rq[201]
  PIN vm_rq[202]
    DIRECTION INPUT ;
    USE SIGNAL ;
    PORT
      LAYER M4 ;
        RECT  139.916 55.104 140 55.128 ;
    END
  END vm_rq[202]
  PIN vm_rq[203]
    DIRECTION INPUT ;
    USE SIGNAL ;
    PORT
      LAYER M4 ;
        RECT  139.916 55.152 140 55.176 ;
    END
  END vm_rq[203]
  PIN vm_rq[204]
    DIRECTION INPUT ;
    USE SIGNAL ;
    PORT
      LAYER M4 ;
        RECT  139.916 55.2 140 55.224 ;
    END
  END vm_rq[204]
  PIN vm_rq[205]
    DIRECTION INPUT ;
    USE SIGNAL ;
    PORT
      LAYER M4 ;
        RECT  139.916 55.248 140 55.272 ;
    END
  END vm_rq[205]
  PIN vm_rq[206]
    DIRECTION INPUT ;
    USE SIGNAL ;
    PORT
      LAYER M4 ;
        RECT  139.916 55.296 140 55.32 ;
    END
  END vm_rq[206]
  PIN vm_rq[207]
    DIRECTION INPUT ;
    USE SIGNAL ;
    PORT
      LAYER M4 ;
        RECT  139.916 55.344 140 55.368 ;
    END
  END vm_rq[207]
  PIN vm_rq[208]
    DIRECTION INPUT ;
    USE SIGNAL ;
    PORT
      LAYER M4 ;
        RECT  139.916 55.392 140 55.416 ;
    END
  END vm_rq[208]
  PIN vm_rq[209]
    DIRECTION INPUT ;
    USE SIGNAL ;
    PORT
      LAYER M4 ;
        RECT  139.916 55.44 140 55.464 ;
    END
  END vm_rq[209]
  PIN vm_rq[20]
    DIRECTION INPUT ;
    USE SIGNAL ;
    PORT
      LAYER M4 ;
        RECT  139.916 46.368 140 46.392 ;
    END
  END vm_rq[20]
  PIN vm_rq[210]
    DIRECTION INPUT ;
    USE SIGNAL ;
    PORT
      LAYER M4 ;
        RECT  139.916 55.488 140 55.512 ;
    END
  END vm_rq[210]
  PIN vm_rq[211]
    DIRECTION INPUT ;
    USE SIGNAL ;
    PORT
      LAYER M4 ;
        RECT  139.916 55.536 140 55.56 ;
    END
  END vm_rq[211]
  PIN vm_rq[212]
    DIRECTION INPUT ;
    USE SIGNAL ;
    PORT
      LAYER M4 ;
        RECT  139.916 55.584 140 55.608 ;
    END
  END vm_rq[212]
  PIN vm_rq[213]
    DIRECTION INPUT ;
    USE SIGNAL ;
    PORT
      LAYER M4 ;
        RECT  139.916 55.632 140 55.656 ;
    END
  END vm_rq[213]
  PIN vm_rq[214]
    DIRECTION INPUT ;
    USE SIGNAL ;
    PORT
      LAYER M4 ;
        RECT  139.916 55.68 140 55.704 ;
    END
  END vm_rq[214]
  PIN vm_rq[215]
    DIRECTION INPUT ;
    USE SIGNAL ;
    PORT
      LAYER M4 ;
        RECT  139.916 55.728 140 55.752 ;
    END
  END vm_rq[215]
  PIN vm_rq[216]
    DIRECTION INPUT ;
    USE SIGNAL ;
    PORT
      LAYER M4 ;
        RECT  139.916 55.776 140 55.8 ;
    END
  END vm_rq[216]
  PIN vm_rq[217]
    DIRECTION INPUT ;
    USE SIGNAL ;
    PORT
      LAYER M4 ;
        RECT  139.916 55.824 140 55.848 ;
    END
  END vm_rq[217]
  PIN vm_rq[218]
    DIRECTION INPUT ;
    USE SIGNAL ;
    PORT
      LAYER M4 ;
        RECT  139.916 55.872 140 55.896 ;
    END
  END vm_rq[218]
  PIN vm_rq[219]
    DIRECTION INPUT ;
    USE SIGNAL ;
    PORT
      LAYER M4 ;
        RECT  139.916 55.92 140 55.944 ;
    END
  END vm_rq[219]
  PIN vm_rq[21]
    DIRECTION INPUT ;
    USE SIGNAL ;
    PORT
      LAYER M4 ;
        RECT  139.916 46.416 140 46.44 ;
    END
  END vm_rq[21]
  PIN vm_rq[220]
    DIRECTION INPUT ;
    USE SIGNAL ;
    PORT
      LAYER M4 ;
        RECT  139.916 55.968 140 55.992 ;
    END
  END vm_rq[220]
  PIN vm_rq[221]
    DIRECTION INPUT ;
    USE SIGNAL ;
    PORT
      LAYER M4 ;
        RECT  139.916 56.016 140 56.04 ;
    END
  END vm_rq[221]
  PIN vm_rq[222]
    DIRECTION INPUT ;
    USE SIGNAL ;
    PORT
      LAYER M4 ;
        RECT  139.916 56.064 140 56.088 ;
    END
  END vm_rq[222]
  PIN vm_rq[223]
    DIRECTION INPUT ;
    USE SIGNAL ;
    PORT
      LAYER M4 ;
        RECT  139.916 56.112 140 56.136 ;
    END
  END vm_rq[223]
  PIN vm_rq[224]
    DIRECTION INPUT ;
    USE SIGNAL ;
    PORT
      LAYER M4 ;
        RECT  139.916 56.16 140 56.184 ;
    END
  END vm_rq[224]
  PIN vm_rq[225]
    DIRECTION INPUT ;
    USE SIGNAL ;
    PORT
      LAYER M4 ;
        RECT  139.916 56.208 140 56.232 ;
    END
  END vm_rq[225]
  PIN vm_rq[226]
    DIRECTION INPUT ;
    USE SIGNAL ;
    PORT
      LAYER M4 ;
        RECT  139.916 56.256 140 56.28 ;
    END
  END vm_rq[226]
  PIN vm_rq[227]
    DIRECTION INPUT ;
    USE SIGNAL ;
    PORT
      LAYER M4 ;
        RECT  139.916 56.304 140 56.328 ;
    END
  END vm_rq[227]
  PIN vm_rq[228]
    DIRECTION INPUT ;
    USE SIGNAL ;
    PORT
      LAYER M4 ;
        RECT  139.916 56.352 140 56.376 ;
    END
  END vm_rq[228]
  PIN vm_rq[229]
    DIRECTION INPUT ;
    USE SIGNAL ;
    PORT
      LAYER M4 ;
        RECT  139.916 56.4 140 56.424 ;
    END
  END vm_rq[229]
  PIN vm_rq[22]
    DIRECTION INPUT ;
    USE SIGNAL ;
    PORT
      LAYER M4 ;
        RECT  139.916 46.464 140 46.488 ;
    END
  END vm_rq[22]
  PIN vm_rq[230]
    DIRECTION INPUT ;
    USE SIGNAL ;
    PORT
      LAYER M4 ;
        RECT  139.916 56.448 140 56.472 ;
    END
  END vm_rq[230]
  PIN vm_rq[231]
    DIRECTION INPUT ;
    USE SIGNAL ;
    PORT
      LAYER M4 ;
        RECT  139.916 56.496 140 56.52 ;
    END
  END vm_rq[231]
  PIN vm_rq[232]
    DIRECTION INPUT ;
    USE SIGNAL ;
    PORT
      LAYER M4 ;
        RECT  139.916 56.544 140 56.568 ;
    END
  END vm_rq[232]
  PIN vm_rq[233]
    DIRECTION INPUT ;
    USE SIGNAL ;
    PORT
      LAYER M4 ;
        RECT  139.916 56.592 140 56.616 ;
    END
  END vm_rq[233]
  PIN vm_rq[234]
    DIRECTION INPUT ;
    USE SIGNAL ;
    PORT
      LAYER M4 ;
        RECT  139.916 56.64 140 56.664 ;
    END
  END vm_rq[234]
  PIN vm_rq[235]
    DIRECTION INPUT ;
    USE SIGNAL ;
    PORT
      LAYER M4 ;
        RECT  139.916 56.688 140 56.712 ;
    END
  END vm_rq[235]
  PIN vm_rq[236]
    DIRECTION INPUT ;
    USE SIGNAL ;
    PORT
      LAYER M4 ;
        RECT  139.916 56.736 140 56.76 ;
    END
  END vm_rq[236]
  PIN vm_rq[237]
    DIRECTION INPUT ;
    USE SIGNAL ;
    PORT
      LAYER M4 ;
        RECT  139.916 56.784 140 56.808 ;
    END
  END vm_rq[237]
  PIN vm_rq[238]
    DIRECTION INPUT ;
    USE SIGNAL ;
    PORT
      LAYER M4 ;
        RECT  139.916 56.832 140 56.856 ;
    END
  END vm_rq[238]
  PIN vm_rq[239]
    DIRECTION INPUT ;
    USE SIGNAL ;
    PORT
      LAYER M4 ;
        RECT  139.916 56.88 140 56.904 ;
    END
  END vm_rq[239]
  PIN vm_rq[23]
    DIRECTION INPUT ;
    USE SIGNAL ;
    PORT
      LAYER M4 ;
        RECT  139.916 46.512 140 46.536 ;
    END
  END vm_rq[23]
  PIN vm_rq[240]
    DIRECTION INPUT ;
    USE SIGNAL ;
    PORT
      LAYER M4 ;
        RECT  139.916 56.928 140 56.952 ;
    END
  END vm_rq[240]
  PIN vm_rq[241]
    DIRECTION INPUT ;
    USE SIGNAL ;
    PORT
      LAYER M4 ;
        RECT  139.916 56.976 140 57 ;
    END
  END vm_rq[241]
  PIN vm_rq[242]
    DIRECTION INPUT ;
    USE SIGNAL ;
    PORT
      LAYER M4 ;
        RECT  139.916 57.024 140 57.048 ;
    END
  END vm_rq[242]
  PIN vm_rq[243]
    DIRECTION INPUT ;
    USE SIGNAL ;
    PORT
      LAYER M4 ;
        RECT  139.916 57.072 140 57.096 ;
    END
  END vm_rq[243]
  PIN vm_rq[244]
    DIRECTION INPUT ;
    USE SIGNAL ;
    PORT
      LAYER M4 ;
        RECT  139.916 57.12 140 57.144 ;
    END
  END vm_rq[244]
  PIN vm_rq[245]
    DIRECTION INPUT ;
    USE SIGNAL ;
    PORT
      LAYER M4 ;
        RECT  139.916 57.168 140 57.192 ;
    END
  END vm_rq[245]
  PIN vm_rq[246]
    DIRECTION INPUT ;
    USE SIGNAL ;
    PORT
      LAYER M4 ;
        RECT  139.916 57.216 140 57.24 ;
    END
  END vm_rq[246]
  PIN vm_rq[247]
    DIRECTION INPUT ;
    USE SIGNAL ;
    PORT
      LAYER M4 ;
        RECT  139.916 57.264 140 57.288 ;
    END
  END vm_rq[247]
  PIN vm_rq[248]
    DIRECTION INPUT ;
    USE SIGNAL ;
    PORT
      LAYER M4 ;
        RECT  139.916 57.312 140 57.336 ;
    END
  END vm_rq[248]
  PIN vm_rq[249]
    DIRECTION INPUT ;
    USE SIGNAL ;
    PORT
      LAYER M4 ;
        RECT  139.916 57.36 140 57.384 ;
    END
  END vm_rq[249]
  PIN vm_rq[24]
    DIRECTION INPUT ;
    USE SIGNAL ;
    PORT
      LAYER M4 ;
        RECT  139.916 46.56 140 46.584 ;
    END
  END vm_rq[24]
  PIN vm_rq[250]
    DIRECTION INPUT ;
    USE SIGNAL ;
    PORT
      LAYER M4 ;
        RECT  139.916 57.408 140 57.432 ;
    END
  END vm_rq[250]
  PIN vm_rq[251]
    DIRECTION INPUT ;
    USE SIGNAL ;
    PORT
      LAYER M4 ;
        RECT  139.916 57.456 140 57.48 ;
    END
  END vm_rq[251]
  PIN vm_rq[252]
    DIRECTION INPUT ;
    USE SIGNAL ;
    PORT
      LAYER M4 ;
        RECT  139.916 57.504 140 57.528 ;
    END
  END vm_rq[252]
  PIN vm_rq[253]
    DIRECTION INPUT ;
    USE SIGNAL ;
    PORT
      LAYER M4 ;
        RECT  139.916 57.552 140 57.576 ;
    END
  END vm_rq[253]
  PIN vm_rq[254]
    DIRECTION INPUT ;
    USE SIGNAL ;
    PORT
      LAYER M4 ;
        RECT  139.916 57.6 140 57.624 ;
    END
  END vm_rq[254]
  PIN vm_rq[255]
    DIRECTION INPUT ;
    USE SIGNAL ;
    PORT
      LAYER M4 ;
        RECT  139.916 57.648 140 57.672 ;
    END
  END vm_rq[255]
  PIN vm_rq[256]
    DIRECTION INPUT ;
    USE SIGNAL ;
    PORT
      LAYER M4 ;
        RECT  139.916 57.696 140 57.72 ;
    END
  END vm_rq[256]
  PIN vm_rq[257]
    DIRECTION INPUT ;
    USE SIGNAL ;
    PORT
      LAYER M4 ;
        RECT  139.916 57.744 140 57.768 ;
    END
  END vm_rq[257]
  PIN vm_rq[258]
    DIRECTION INPUT ;
    USE SIGNAL ;
    PORT
      LAYER M4 ;
        RECT  139.916 57.792 140 57.816 ;
    END
  END vm_rq[258]
  PIN vm_rq[259]
    DIRECTION INPUT ;
    USE SIGNAL ;
    PORT
      LAYER M4 ;
        RECT  139.916 57.84 140 57.864 ;
    END
  END vm_rq[259]
  PIN vm_rq[25]
    DIRECTION INPUT ;
    USE SIGNAL ;
    PORT
      LAYER M4 ;
        RECT  139.916 46.608 140 46.632 ;
    END
  END vm_rq[25]
  PIN vm_rq[260]
    DIRECTION INPUT ;
    USE SIGNAL ;
    PORT
      LAYER M4 ;
        RECT  139.916 57.888 140 57.912 ;
    END
  END vm_rq[260]
  PIN vm_rq[261]
    DIRECTION INPUT ;
    USE SIGNAL ;
    PORT
      LAYER M4 ;
        RECT  139.916 57.936 140 57.96 ;
    END
  END vm_rq[261]
  PIN vm_rq[262]
    DIRECTION INPUT ;
    USE SIGNAL ;
    PORT
      LAYER M4 ;
        RECT  139.916 57.984 140 58.008 ;
    END
  END vm_rq[262]
  PIN vm_rq[263]
    DIRECTION INPUT ;
    USE SIGNAL ;
    PORT
      LAYER M4 ;
        RECT  139.916 58.032 140 58.056 ;
    END
  END vm_rq[263]
  PIN vm_rq[264]
    DIRECTION INPUT ;
    USE SIGNAL ;
    PORT
      LAYER M4 ;
        RECT  139.916 58.08 140 58.104 ;
    END
  END vm_rq[264]
  PIN vm_rq[265]
    DIRECTION INPUT ;
    USE SIGNAL ;
    PORT
      LAYER M4 ;
        RECT  139.916 58.128 140 58.152 ;
    END
  END vm_rq[265]
  PIN vm_rq[266]
    DIRECTION INPUT ;
    USE SIGNAL ;
    PORT
      LAYER M4 ;
        RECT  139.916 58.176 140 58.2 ;
    END
  END vm_rq[266]
  PIN vm_rq[267]
    DIRECTION INPUT ;
    USE SIGNAL ;
    PORT
      LAYER M4 ;
        RECT  139.916 58.224 140 58.248 ;
    END
  END vm_rq[267]
  PIN vm_rq[268]
    DIRECTION INPUT ;
    USE SIGNAL ;
    PORT
      LAYER M4 ;
        RECT  139.916 58.272 140 58.296 ;
    END
  END vm_rq[268]
  PIN vm_rq[269]
    DIRECTION INPUT ;
    USE SIGNAL ;
    PORT
      LAYER M4 ;
        RECT  139.916 58.32 140 58.344 ;
    END
  END vm_rq[269]
  PIN vm_rq[26]
    DIRECTION INPUT ;
    USE SIGNAL ;
    PORT
      LAYER M4 ;
        RECT  139.916 46.656 140 46.68 ;
    END
  END vm_rq[26]
  PIN vm_rq[270]
    DIRECTION INPUT ;
    USE SIGNAL ;
    PORT
      LAYER M4 ;
        RECT  139.916 58.368 140 58.392 ;
    END
  END vm_rq[270]
  PIN vm_rq[271]
    DIRECTION INPUT ;
    USE SIGNAL ;
    PORT
      LAYER M4 ;
        RECT  139.916 58.416 140 58.44 ;
    END
  END vm_rq[271]
  PIN vm_rq[272]
    DIRECTION INPUT ;
    USE SIGNAL ;
    PORT
      LAYER M4 ;
        RECT  139.916 58.464 140 58.488 ;
    END
  END vm_rq[272]
  PIN vm_rq[273]
    DIRECTION INPUT ;
    USE SIGNAL ;
    PORT
      LAYER M4 ;
        RECT  139.916 58.512 140 58.536 ;
    END
  END vm_rq[273]
  PIN vm_rq[274]
    DIRECTION INPUT ;
    USE SIGNAL ;
    PORT
      LAYER M4 ;
        RECT  139.916 58.56 140 58.584 ;
    END
  END vm_rq[274]
  PIN vm_rq[275]
    DIRECTION INPUT ;
    USE SIGNAL ;
    PORT
      LAYER M4 ;
        RECT  139.916 58.608 140 58.632 ;
    END
  END vm_rq[275]
  PIN vm_rq[276]
    DIRECTION INPUT ;
    USE SIGNAL ;
    PORT
      LAYER M4 ;
        RECT  139.916 58.656 140 58.68 ;
    END
  END vm_rq[276]
  PIN vm_rq[277]
    DIRECTION INPUT ;
    USE SIGNAL ;
    PORT
      LAYER M4 ;
        RECT  139.916 58.704 140 58.728 ;
    END
  END vm_rq[277]
  PIN vm_rq[278]
    DIRECTION INPUT ;
    USE SIGNAL ;
    PORT
      LAYER M4 ;
        RECT  139.916 58.752 140 58.776 ;
    END
  END vm_rq[278]
  PIN vm_rq[279]
    DIRECTION INPUT ;
    USE SIGNAL ;
    PORT
      LAYER M4 ;
        RECT  139.916 58.8 140 58.824 ;
    END
  END vm_rq[279]
  PIN vm_rq[27]
    DIRECTION INPUT ;
    USE SIGNAL ;
    PORT
      LAYER M4 ;
        RECT  139.916 46.704 140 46.728 ;
    END
  END vm_rq[27]
  PIN vm_rq[280]
    DIRECTION INPUT ;
    USE SIGNAL ;
    PORT
      LAYER M4 ;
        RECT  139.916 58.848 140 58.872 ;
    END
  END vm_rq[280]
  PIN vm_rq[281]
    DIRECTION INPUT ;
    USE SIGNAL ;
    PORT
      LAYER M4 ;
        RECT  139.916 58.896 140 58.92 ;
    END
  END vm_rq[281]
  PIN vm_rq[282]
    DIRECTION INPUT ;
    USE SIGNAL ;
    PORT
      LAYER M4 ;
        RECT  139.916 58.944 140 58.968 ;
    END
  END vm_rq[282]
  PIN vm_rq[283]
    DIRECTION INPUT ;
    USE SIGNAL ;
    PORT
      LAYER M4 ;
        RECT  139.916 58.992 140 59.016 ;
    END
  END vm_rq[283]
  PIN vm_rq[284]
    DIRECTION INPUT ;
    USE SIGNAL ;
    PORT
      LAYER M4 ;
        RECT  139.916 59.04 140 59.064 ;
    END
  END vm_rq[284]
  PIN vm_rq[285]
    DIRECTION INPUT ;
    USE SIGNAL ;
    PORT
      LAYER M4 ;
        RECT  139.916 59.088 140 59.112 ;
    END
  END vm_rq[285]
  PIN vm_rq[286]
    DIRECTION INPUT ;
    USE SIGNAL ;
    PORT
      LAYER M4 ;
        RECT  139.916 59.136 140 59.16 ;
    END
  END vm_rq[286]
  PIN vm_rq[287]
    DIRECTION INPUT ;
    USE SIGNAL ;
    PORT
      LAYER M4 ;
        RECT  139.916 59.184 140 59.208 ;
    END
  END vm_rq[287]
  PIN vm_rq[288]
    DIRECTION INPUT ;
    USE SIGNAL ;
    PORT
      LAYER M4 ;
        RECT  139.916 59.232 140 59.256 ;
    END
  END vm_rq[288]
  PIN vm_rq[289]
    DIRECTION INPUT ;
    USE SIGNAL ;
    PORT
      LAYER M4 ;
        RECT  139.916 59.28 140 59.304 ;
    END
  END vm_rq[289]
  PIN vm_rq[28]
    DIRECTION INPUT ;
    USE SIGNAL ;
    PORT
      LAYER M4 ;
        RECT  139.916 46.752 140 46.776 ;
    END
  END vm_rq[28]
  PIN vm_rq[290]
    DIRECTION INPUT ;
    USE SIGNAL ;
    PORT
      LAYER M4 ;
        RECT  139.916 59.328 140 59.352 ;
    END
  END vm_rq[290]
  PIN vm_rq[291]
    DIRECTION INPUT ;
    USE SIGNAL ;
    PORT
      LAYER M4 ;
        RECT  139.916 59.376 140 59.4 ;
    END
  END vm_rq[291]
  PIN vm_rq[292]
    DIRECTION INPUT ;
    USE SIGNAL ;
    PORT
      LAYER M4 ;
        RECT  139.916 59.424 140 59.448 ;
    END
  END vm_rq[292]
  PIN vm_rq[293]
    DIRECTION INPUT ;
    USE SIGNAL ;
    PORT
      LAYER M4 ;
        RECT  139.916 59.472 140 59.496 ;
    END
  END vm_rq[293]
  PIN vm_rq[294]
    DIRECTION INPUT ;
    USE SIGNAL ;
    PORT
      LAYER M4 ;
        RECT  139.916 59.52 140 59.544 ;
    END
  END vm_rq[294]
  PIN vm_rq[295]
    DIRECTION INPUT ;
    USE SIGNAL ;
    PORT
      LAYER M4 ;
        RECT  139.916 59.568 140 59.592 ;
    END
  END vm_rq[295]
  PIN vm_rq[296]
    DIRECTION INPUT ;
    USE SIGNAL ;
    PORT
      LAYER M4 ;
        RECT  139.916 59.616 140 59.64 ;
    END
  END vm_rq[296]
  PIN vm_rq[297]
    DIRECTION INPUT ;
    USE SIGNAL ;
    PORT
      LAYER M4 ;
        RECT  139.916 59.664 140 59.688 ;
    END
  END vm_rq[297]
  PIN vm_rq[298]
    DIRECTION INPUT ;
    USE SIGNAL ;
    PORT
      LAYER M4 ;
        RECT  139.916 59.712 140 59.736 ;
    END
  END vm_rq[298]
  PIN vm_rq[299]
    DIRECTION INPUT ;
    USE SIGNAL ;
    PORT
      LAYER M4 ;
        RECT  139.916 59.76 140 59.784 ;
    END
  END vm_rq[299]
  PIN vm_rq[29]
    DIRECTION INPUT ;
    USE SIGNAL ;
    PORT
      LAYER M4 ;
        RECT  139.916 46.8 140 46.824 ;
    END
  END vm_rq[29]
  PIN vm_rq[2]
    DIRECTION INPUT ;
    USE SIGNAL ;
    PORT
      LAYER M4 ;
        RECT  139.916 45.504 140 45.528 ;
    END
  END vm_rq[2]
  PIN vm_rq[300]
    DIRECTION INPUT ;
    USE SIGNAL ;
    PORT
      LAYER M4 ;
        RECT  139.916 59.808 140 59.832 ;
    END
  END vm_rq[300]
  PIN vm_rq[301]
    DIRECTION INPUT ;
    USE SIGNAL ;
    PORT
      LAYER M4 ;
        RECT  139.916 59.856 140 59.88 ;
    END
  END vm_rq[301]
  PIN vm_rq[302]
    DIRECTION INPUT ;
    USE SIGNAL ;
    PORT
      LAYER M4 ;
        RECT  139.916 59.904 140 59.928 ;
    END
  END vm_rq[302]
  PIN vm_rq[303]
    DIRECTION INPUT ;
    USE SIGNAL ;
    PORT
      LAYER M4 ;
        RECT  139.916 59.952 140 59.976 ;
    END
  END vm_rq[303]
  PIN vm_rq[304]
    DIRECTION INPUT ;
    USE SIGNAL ;
    PORT
      LAYER M4 ;
        RECT  139.916 60 140 60.024 ;
    END
  END vm_rq[304]
  PIN vm_rq[305]
    DIRECTION INPUT ;
    USE SIGNAL ;
    PORT
      LAYER M4 ;
        RECT  139.916 60.048 140 60.072 ;
    END
  END vm_rq[305]
  PIN vm_rq[306]
    DIRECTION INPUT ;
    USE SIGNAL ;
    PORT
      LAYER M4 ;
        RECT  139.916 60.096 140 60.12 ;
    END
  END vm_rq[306]
  PIN vm_rq[307]
    DIRECTION INPUT ;
    USE SIGNAL ;
    PORT
      LAYER M4 ;
        RECT  139.916 60.144 140 60.168 ;
    END
  END vm_rq[307]
  PIN vm_rq[308]
    DIRECTION INPUT ;
    USE SIGNAL ;
    PORT
      LAYER M4 ;
        RECT  139.916 60.192 140 60.216 ;
    END
  END vm_rq[308]
  PIN vm_rq[309]
    DIRECTION INPUT ;
    USE SIGNAL ;
    PORT
      LAYER M4 ;
        RECT  139.916 60.24 140 60.264 ;
    END
  END vm_rq[309]
  PIN vm_rq[30]
    DIRECTION INPUT ;
    USE SIGNAL ;
    PORT
      LAYER M4 ;
        RECT  139.916 46.848 140 46.872 ;
    END
  END vm_rq[30]
  PIN vm_rq[310]
    DIRECTION INPUT ;
    USE SIGNAL ;
    PORT
      LAYER M4 ;
        RECT  139.916 60.288 140 60.312 ;
    END
  END vm_rq[310]
  PIN vm_rq[311]
    DIRECTION INPUT ;
    USE SIGNAL ;
    PORT
      LAYER M4 ;
        RECT  139.916 60.336 140 60.36 ;
    END
  END vm_rq[311]
  PIN vm_rq[312]
    DIRECTION INPUT ;
    USE SIGNAL ;
    PORT
      LAYER M4 ;
        RECT  139.916 60.384 140 60.408 ;
    END
  END vm_rq[312]
  PIN vm_rq[313]
    DIRECTION INPUT ;
    USE SIGNAL ;
    PORT
      LAYER M4 ;
        RECT  139.916 60.432 140 60.456 ;
    END
  END vm_rq[313]
  PIN vm_rq[314]
    DIRECTION INPUT ;
    USE SIGNAL ;
    PORT
      LAYER M4 ;
        RECT  139.916 60.48 140 60.504 ;
    END
  END vm_rq[314]
  PIN vm_rq[315]
    DIRECTION INPUT ;
    USE SIGNAL ;
    PORT
      LAYER M4 ;
        RECT  139.916 60.528 140 60.552 ;
    END
  END vm_rq[315]
  PIN vm_rq[316]
    DIRECTION INPUT ;
    USE SIGNAL ;
    PORT
      LAYER M4 ;
        RECT  139.916 60.576 140 60.6 ;
    END
  END vm_rq[316]
  PIN vm_rq[317]
    DIRECTION INPUT ;
    USE SIGNAL ;
    PORT
      LAYER M4 ;
        RECT  139.916 60.624 140 60.648 ;
    END
  END vm_rq[317]
  PIN vm_rq[318]
    DIRECTION INPUT ;
    USE SIGNAL ;
    PORT
      LAYER M4 ;
        RECT  139.916 60.672 140 60.696 ;
    END
  END vm_rq[318]
  PIN vm_rq[319]
    DIRECTION INPUT ;
    USE SIGNAL ;
    PORT
      LAYER M4 ;
        RECT  139.916 60.72 140 60.744 ;
    END
  END vm_rq[319]
  PIN vm_rq[31]
    DIRECTION INPUT ;
    USE SIGNAL ;
    PORT
      LAYER M4 ;
        RECT  139.916 46.896 140 46.92 ;
    END
  END vm_rq[31]
  PIN vm_rq[320]
    DIRECTION INPUT ;
    USE SIGNAL ;
    PORT
      LAYER M4 ;
        RECT  139.916 60.768 140 60.792 ;
    END
  END vm_rq[320]
  PIN vm_rq[321]
    DIRECTION INPUT ;
    USE SIGNAL ;
    PORT
      LAYER M4 ;
        RECT  139.916 60.816 140 60.84 ;
    END
  END vm_rq[321]
  PIN vm_rq[322]
    DIRECTION INPUT ;
    USE SIGNAL ;
    PORT
      LAYER M4 ;
        RECT  139.916 60.864 140 60.888 ;
    END
  END vm_rq[322]
  PIN vm_rq[323]
    DIRECTION INPUT ;
    USE SIGNAL ;
    PORT
      LAYER M4 ;
        RECT  139.916 60.912 140 60.936 ;
    END
  END vm_rq[323]
  PIN vm_rq[324]
    DIRECTION INPUT ;
    USE SIGNAL ;
    PORT
      LAYER M4 ;
        RECT  139.916 60.96 140 60.984 ;
    END
  END vm_rq[324]
  PIN vm_rq[325]
    DIRECTION INPUT ;
    USE SIGNAL ;
    PORT
      LAYER M4 ;
        RECT  139.916 61.008 140 61.032 ;
    END
  END vm_rq[325]
  PIN vm_rq[326]
    DIRECTION INPUT ;
    USE SIGNAL ;
    PORT
      LAYER M4 ;
        RECT  139.916 61.056 140 61.08 ;
    END
  END vm_rq[326]
  PIN vm_rq[327]
    DIRECTION INPUT ;
    USE SIGNAL ;
    PORT
      LAYER M4 ;
        RECT  139.916 61.104 140 61.128 ;
    END
  END vm_rq[327]
  PIN vm_rq[328]
    DIRECTION INPUT ;
    USE SIGNAL ;
    PORT
      LAYER M4 ;
        RECT  139.916 61.152 140 61.176 ;
    END
  END vm_rq[328]
  PIN vm_rq[329]
    DIRECTION INPUT ;
    USE SIGNAL ;
    PORT
      LAYER M4 ;
        RECT  139.916 61.2 140 61.224 ;
    END
  END vm_rq[329]
  PIN vm_rq[32]
    DIRECTION INPUT ;
    USE SIGNAL ;
    PORT
      LAYER M4 ;
        RECT  139.916 46.944 140 46.968 ;
    END
  END vm_rq[32]
  PIN vm_rq[330]
    DIRECTION INPUT ;
    USE SIGNAL ;
    PORT
      LAYER M4 ;
        RECT  139.916 61.248 140 61.272 ;
    END
  END vm_rq[330]
  PIN vm_rq[331]
    DIRECTION INPUT ;
    USE SIGNAL ;
    PORT
      LAYER M4 ;
        RECT  139.916 61.296 140 61.32 ;
    END
  END vm_rq[331]
  PIN vm_rq[332]
    DIRECTION INPUT ;
    USE SIGNAL ;
    PORT
      LAYER M4 ;
        RECT  139.916 61.344 140 61.368 ;
    END
  END vm_rq[332]
  PIN vm_rq[333]
    DIRECTION INPUT ;
    USE SIGNAL ;
    PORT
      LAYER M4 ;
        RECT  139.916 61.392 140 61.416 ;
    END
  END vm_rq[333]
  PIN vm_rq[334]
    DIRECTION INPUT ;
    USE SIGNAL ;
    PORT
      LAYER M4 ;
        RECT  139.916 61.44 140 61.464 ;
    END
  END vm_rq[334]
  PIN vm_rq[335]
    DIRECTION INPUT ;
    USE SIGNAL ;
    PORT
      LAYER M4 ;
        RECT  139.916 61.488 140 61.512 ;
    END
  END vm_rq[335]
  PIN vm_rq[336]
    DIRECTION INPUT ;
    USE SIGNAL ;
    PORT
      LAYER M4 ;
        RECT  139.916 61.536 140 61.56 ;
    END
  END vm_rq[336]
  PIN vm_rq[337]
    DIRECTION INPUT ;
    USE SIGNAL ;
    PORT
      LAYER M4 ;
        RECT  139.916 61.584 140 61.608 ;
    END
  END vm_rq[337]
  PIN vm_rq[338]
    DIRECTION INPUT ;
    USE SIGNAL ;
    PORT
      LAYER M4 ;
        RECT  139.916 61.632 140 61.656 ;
    END
  END vm_rq[338]
  PIN vm_rq[339]
    DIRECTION INPUT ;
    USE SIGNAL ;
    PORT
      LAYER M4 ;
        RECT  139.916 61.68 140 61.704 ;
    END
  END vm_rq[339]
  PIN vm_rq[33]
    DIRECTION INPUT ;
    USE SIGNAL ;
    PORT
      LAYER M4 ;
        RECT  139.916 46.992 140 47.016 ;
    END
  END vm_rq[33]
  PIN vm_rq[340]
    DIRECTION INPUT ;
    USE SIGNAL ;
    PORT
      LAYER M4 ;
        RECT  139.916 61.728 140 61.752 ;
    END
  END vm_rq[340]
  PIN vm_rq[341]
    DIRECTION INPUT ;
    USE SIGNAL ;
    PORT
      LAYER M4 ;
        RECT  139.916 61.776 140 61.8 ;
    END
  END vm_rq[341]
  PIN vm_rq[342]
    DIRECTION INPUT ;
    USE SIGNAL ;
    PORT
      LAYER M4 ;
        RECT  139.916 61.824 140 61.848 ;
    END
  END vm_rq[342]
  PIN vm_rq[343]
    DIRECTION INPUT ;
    USE SIGNAL ;
    PORT
      LAYER M4 ;
        RECT  139.916 61.872 140 61.896 ;
    END
  END vm_rq[343]
  PIN vm_rq[344]
    DIRECTION INPUT ;
    USE SIGNAL ;
    PORT
      LAYER M4 ;
        RECT  139.916 61.92 140 61.944 ;
    END
  END vm_rq[344]
  PIN vm_rq[345]
    DIRECTION INPUT ;
    USE SIGNAL ;
    PORT
      LAYER M4 ;
        RECT  139.916 61.968 140 61.992 ;
    END
  END vm_rq[345]
  PIN vm_rq[346]
    DIRECTION INPUT ;
    USE SIGNAL ;
    PORT
      LAYER M4 ;
        RECT  139.916 62.016 140 62.04 ;
    END
  END vm_rq[346]
  PIN vm_rq[347]
    DIRECTION INPUT ;
    USE SIGNAL ;
    PORT
      LAYER M4 ;
        RECT  139.916 62.064 140 62.088 ;
    END
  END vm_rq[347]
  PIN vm_rq[348]
    DIRECTION INPUT ;
    USE SIGNAL ;
    PORT
      LAYER M4 ;
        RECT  139.916 62.112 140 62.136 ;
    END
  END vm_rq[348]
  PIN vm_rq[349]
    DIRECTION INPUT ;
    USE SIGNAL ;
    PORT
      LAYER M4 ;
        RECT  139.916 62.16 140 62.184 ;
    END
  END vm_rq[349]
  PIN vm_rq[34]
    DIRECTION INPUT ;
    USE SIGNAL ;
    PORT
      LAYER M4 ;
        RECT  139.916 47.04 140 47.064 ;
    END
  END vm_rq[34]
  PIN vm_rq[350]
    DIRECTION INPUT ;
    USE SIGNAL ;
    PORT
      LAYER M4 ;
        RECT  139.916 62.208 140 62.232 ;
    END
  END vm_rq[350]
  PIN vm_rq[351]
    DIRECTION INPUT ;
    USE SIGNAL ;
    PORT
      LAYER M4 ;
        RECT  139.916 62.256 140 62.28 ;
    END
  END vm_rq[351]
  PIN vm_rq[352]
    DIRECTION INPUT ;
    USE SIGNAL ;
    PORT
      LAYER M4 ;
        RECT  139.916 62.304 140 62.328 ;
    END
  END vm_rq[352]
  PIN vm_rq[353]
    DIRECTION INPUT ;
    USE SIGNAL ;
    PORT
      LAYER M4 ;
        RECT  139.916 62.352 140 62.376 ;
    END
  END vm_rq[353]
  PIN vm_rq[354]
    DIRECTION INPUT ;
    USE SIGNAL ;
    PORT
      LAYER M4 ;
        RECT  139.916 62.4 140 62.424 ;
    END
  END vm_rq[354]
  PIN vm_rq[355]
    DIRECTION INPUT ;
    USE SIGNAL ;
    PORT
      LAYER M4 ;
        RECT  139.916 62.448 140 62.472 ;
    END
  END vm_rq[355]
  PIN vm_rq[356]
    DIRECTION INPUT ;
    USE SIGNAL ;
    PORT
      LAYER M4 ;
        RECT  139.916 62.496 140 62.52 ;
    END
  END vm_rq[356]
  PIN vm_rq[357]
    DIRECTION INPUT ;
    USE SIGNAL ;
    PORT
      LAYER M4 ;
        RECT  139.916 62.544 140 62.568 ;
    END
  END vm_rq[357]
  PIN vm_rq[358]
    DIRECTION INPUT ;
    USE SIGNAL ;
    PORT
      LAYER M4 ;
        RECT  139.916 62.592 140 62.616 ;
    END
  END vm_rq[358]
  PIN vm_rq[359]
    DIRECTION INPUT ;
    USE SIGNAL ;
    PORT
      LAYER M4 ;
        RECT  139.916 62.64 140 62.664 ;
    END
  END vm_rq[359]
  PIN vm_rq[35]
    DIRECTION INPUT ;
    USE SIGNAL ;
    PORT
      LAYER M4 ;
        RECT  139.916 47.088 140 47.112 ;
    END
  END vm_rq[35]
  PIN vm_rq[360]
    DIRECTION INPUT ;
    USE SIGNAL ;
    PORT
      LAYER M4 ;
        RECT  139.916 62.688 140 62.712 ;
    END
  END vm_rq[360]
  PIN vm_rq[361]
    DIRECTION INPUT ;
    USE SIGNAL ;
    PORT
      LAYER M4 ;
        RECT  139.916 62.736 140 62.76 ;
    END
  END vm_rq[361]
  PIN vm_rq[362]
    DIRECTION INPUT ;
    USE SIGNAL ;
    PORT
      LAYER M4 ;
        RECT  139.916 62.784 140 62.808 ;
    END
  END vm_rq[362]
  PIN vm_rq[363]
    DIRECTION INPUT ;
    USE SIGNAL ;
    PORT
      LAYER M4 ;
        RECT  139.916 62.832 140 62.856 ;
    END
  END vm_rq[363]
  PIN vm_rq[364]
    DIRECTION INPUT ;
    USE SIGNAL ;
    PORT
      LAYER M4 ;
        RECT  139.916 62.88 140 62.904 ;
    END
  END vm_rq[364]
  PIN vm_rq[365]
    DIRECTION INPUT ;
    USE SIGNAL ;
    PORT
      LAYER M4 ;
        RECT  139.916 62.928 140 62.952 ;
    END
  END vm_rq[365]
  PIN vm_rq[366]
    DIRECTION INPUT ;
    USE SIGNAL ;
    PORT
      LAYER M4 ;
        RECT  139.916 62.976 140 63 ;
    END
  END vm_rq[366]
  PIN vm_rq[367]
    DIRECTION INPUT ;
    USE SIGNAL ;
    PORT
      LAYER M4 ;
        RECT  139.916 63.024 140 63.048 ;
    END
  END vm_rq[367]
  PIN vm_rq[368]
    DIRECTION INPUT ;
    USE SIGNAL ;
    PORT
      LAYER M4 ;
        RECT  139.916 63.072 140 63.096 ;
    END
  END vm_rq[368]
  PIN vm_rq[369]
    DIRECTION INPUT ;
    USE SIGNAL ;
    PORT
      LAYER M4 ;
        RECT  139.916 63.12 140 63.144 ;
    END
  END vm_rq[369]
  PIN vm_rq[36]
    DIRECTION INPUT ;
    USE SIGNAL ;
    PORT
      LAYER M4 ;
        RECT  139.916 47.136 140 47.16 ;
    END
  END vm_rq[36]
  PIN vm_rq[370]
    DIRECTION INPUT ;
    USE SIGNAL ;
    PORT
      LAYER M4 ;
        RECT  139.916 63.168 140 63.192 ;
    END
  END vm_rq[370]
  PIN vm_rq[371]
    DIRECTION INPUT ;
    USE SIGNAL ;
    PORT
      LAYER M4 ;
        RECT  139.916 63.216 140 63.24 ;
    END
  END vm_rq[371]
  PIN vm_rq[372]
    DIRECTION INPUT ;
    USE SIGNAL ;
    PORT
      LAYER M4 ;
        RECT  139.916 63.264 140 63.288 ;
    END
  END vm_rq[372]
  PIN vm_rq[373]
    DIRECTION INPUT ;
    USE SIGNAL ;
    PORT
      LAYER M4 ;
        RECT  139.916 63.312 140 63.336 ;
    END
  END vm_rq[373]
  PIN vm_rq[374]
    DIRECTION INPUT ;
    USE SIGNAL ;
    PORT
      LAYER M4 ;
        RECT  139.916 63.36 140 63.384 ;
    END
  END vm_rq[374]
  PIN vm_rq[375]
    DIRECTION INPUT ;
    USE SIGNAL ;
    PORT
      LAYER M4 ;
        RECT  139.916 63.408 140 63.432 ;
    END
  END vm_rq[375]
  PIN vm_rq[376]
    DIRECTION INPUT ;
    USE SIGNAL ;
    PORT
      LAYER M4 ;
        RECT  139.916 63.456 140 63.48 ;
    END
  END vm_rq[376]
  PIN vm_rq[377]
    DIRECTION INPUT ;
    USE SIGNAL ;
    PORT
      LAYER M4 ;
        RECT  139.916 63.504 140 63.528 ;
    END
  END vm_rq[377]
  PIN vm_rq[378]
    DIRECTION INPUT ;
    USE SIGNAL ;
    PORT
      LAYER M4 ;
        RECT  139.916 63.552 140 63.576 ;
    END
  END vm_rq[378]
  PIN vm_rq[379]
    DIRECTION INPUT ;
    USE SIGNAL ;
    PORT
      LAYER M4 ;
        RECT  139.916 63.6 140 63.624 ;
    END
  END vm_rq[379]
  PIN vm_rq[37]
    DIRECTION INPUT ;
    USE SIGNAL ;
    PORT
      LAYER M4 ;
        RECT  139.916 47.184 140 47.208 ;
    END
  END vm_rq[37]
  PIN vm_rq[380]
    DIRECTION INPUT ;
    USE SIGNAL ;
    PORT
      LAYER M4 ;
        RECT  139.916 63.648 140 63.672 ;
    END
  END vm_rq[380]
  PIN vm_rq[381]
    DIRECTION INPUT ;
    USE SIGNAL ;
    PORT
      LAYER M4 ;
        RECT  139.916 63.696 140 63.72 ;
    END
  END vm_rq[381]
  PIN vm_rq[382]
    DIRECTION INPUT ;
    USE SIGNAL ;
    PORT
      LAYER M4 ;
        RECT  139.916 63.744 140 63.768 ;
    END
  END vm_rq[382]
  PIN vm_rq[383]
    DIRECTION INPUT ;
    USE SIGNAL ;
    PORT
      LAYER M4 ;
        RECT  139.916 63.792 140 63.816 ;
    END
  END vm_rq[383]
  PIN vm_rq[384]
    DIRECTION INPUT ;
    USE SIGNAL ;
    PORT
      LAYER M4 ;
        RECT  139.916 63.84 140 63.864 ;
    END
  END vm_rq[384]
  PIN vm_rq[385]
    DIRECTION INPUT ;
    USE SIGNAL ;
    PORT
      LAYER M4 ;
        RECT  139.916 63.888 140 63.912 ;
    END
  END vm_rq[385]
  PIN vm_rq[386]
    DIRECTION INPUT ;
    USE SIGNAL ;
    PORT
      LAYER M4 ;
        RECT  139.916 63.936 140 63.96 ;
    END
  END vm_rq[386]
  PIN vm_rq[387]
    DIRECTION INPUT ;
    USE SIGNAL ;
    PORT
      LAYER M4 ;
        RECT  139.916 63.984 140 64.008 ;
    END
  END vm_rq[387]
  PIN vm_rq[388]
    DIRECTION INPUT ;
    USE SIGNAL ;
    PORT
      LAYER M4 ;
        RECT  139.916 64.032 140 64.056 ;
    END
  END vm_rq[388]
  PIN vm_rq[389]
    DIRECTION INPUT ;
    USE SIGNAL ;
    PORT
      LAYER M4 ;
        RECT  139.916 64.08 140 64.104 ;
    END
  END vm_rq[389]
  PIN vm_rq[38]
    DIRECTION INPUT ;
    USE SIGNAL ;
    PORT
      LAYER M4 ;
        RECT  139.916 47.232 140 47.256 ;
    END
  END vm_rq[38]
  PIN vm_rq[390]
    DIRECTION INPUT ;
    USE SIGNAL ;
    PORT
      LAYER M4 ;
        RECT  139.916 64.128 140 64.152 ;
    END
  END vm_rq[390]
  PIN vm_rq[391]
    DIRECTION INPUT ;
    USE SIGNAL ;
    PORT
      LAYER M4 ;
        RECT  139.916 64.176 140 64.2 ;
    END
  END vm_rq[391]
  PIN vm_rq[392]
    DIRECTION INPUT ;
    USE SIGNAL ;
    PORT
      LAYER M4 ;
        RECT  139.916 64.224 140 64.248 ;
    END
  END vm_rq[392]
  PIN vm_rq[393]
    DIRECTION INPUT ;
    USE SIGNAL ;
    PORT
      LAYER M4 ;
        RECT  139.916 64.272 140 64.296 ;
    END
  END vm_rq[393]
  PIN vm_rq[394]
    DIRECTION INPUT ;
    USE SIGNAL ;
    PORT
      LAYER M4 ;
        RECT  139.916 64.32 140 64.344 ;
    END
  END vm_rq[394]
  PIN vm_rq[395]
    DIRECTION INPUT ;
    USE SIGNAL ;
    PORT
      LAYER M4 ;
        RECT  139.916 64.368 140 64.392 ;
    END
  END vm_rq[395]
  PIN vm_rq[396]
    DIRECTION INPUT ;
    USE SIGNAL ;
    PORT
      LAYER M4 ;
        RECT  139.916 64.416 140 64.44 ;
    END
  END vm_rq[396]
  PIN vm_rq[397]
    DIRECTION INPUT ;
    USE SIGNAL ;
    PORT
      LAYER M4 ;
        RECT  139.916 64.464 140 64.488 ;
    END
  END vm_rq[397]
  PIN vm_rq[398]
    DIRECTION INPUT ;
    USE SIGNAL ;
    PORT
      LAYER M4 ;
        RECT  139.916 64.512 140 64.536 ;
    END
  END vm_rq[398]
  PIN vm_rq[399]
    DIRECTION INPUT ;
    USE SIGNAL ;
    PORT
      LAYER M4 ;
        RECT  139.916 64.56 140 64.584 ;
    END
  END vm_rq[399]
  PIN vm_rq[39]
    DIRECTION INPUT ;
    USE SIGNAL ;
    PORT
      LAYER M4 ;
        RECT  139.916 47.28 140 47.304 ;
    END
  END vm_rq[39]
  PIN vm_rq[3]
    DIRECTION INPUT ;
    USE SIGNAL ;
    PORT
      LAYER M4 ;
        RECT  139.916 45.552 140 45.576 ;
    END
  END vm_rq[3]
  PIN vm_rq[400]
    DIRECTION INPUT ;
    USE SIGNAL ;
    PORT
      LAYER M4 ;
        RECT  139.916 64.608 140 64.632 ;
    END
  END vm_rq[400]
  PIN vm_rq[401]
    DIRECTION INPUT ;
    USE SIGNAL ;
    PORT
      LAYER M4 ;
        RECT  139.916 64.656 140 64.68 ;
    END
  END vm_rq[401]
  PIN vm_rq[402]
    DIRECTION INPUT ;
    USE SIGNAL ;
    PORT
      LAYER M4 ;
        RECT  139.916 64.704 140 64.728 ;
    END
  END vm_rq[402]
  PIN vm_rq[403]
    DIRECTION INPUT ;
    USE SIGNAL ;
    PORT
      LAYER M4 ;
        RECT  139.916 64.752 140 64.776 ;
    END
  END vm_rq[403]
  PIN vm_rq[404]
    DIRECTION INPUT ;
    USE SIGNAL ;
    PORT
      LAYER M4 ;
        RECT  139.916 64.8 140 64.824 ;
    END
  END vm_rq[404]
  PIN vm_rq[405]
    DIRECTION INPUT ;
    USE SIGNAL ;
    PORT
      LAYER M4 ;
        RECT  139.916 64.848 140 64.872 ;
    END
  END vm_rq[405]
  PIN vm_rq[406]
    DIRECTION INPUT ;
    USE SIGNAL ;
    PORT
      LAYER M4 ;
        RECT  139.916 64.896 140 64.92 ;
    END
  END vm_rq[406]
  PIN vm_rq[407]
    DIRECTION INPUT ;
    USE SIGNAL ;
    PORT
      LAYER M4 ;
        RECT  139.916 64.944 140 64.968 ;
    END
  END vm_rq[407]
  PIN vm_rq[408]
    DIRECTION INPUT ;
    USE SIGNAL ;
    PORT
      LAYER M4 ;
        RECT  139.916 64.992 140 65.016 ;
    END
  END vm_rq[408]
  PIN vm_rq[409]
    DIRECTION INPUT ;
    USE SIGNAL ;
    PORT
      LAYER M4 ;
        RECT  139.916 65.04 140 65.064 ;
    END
  END vm_rq[409]
  PIN vm_rq[40]
    DIRECTION INPUT ;
    USE SIGNAL ;
    PORT
      LAYER M4 ;
        RECT  139.916 47.328 140 47.352 ;
    END
  END vm_rq[40]
  PIN vm_rq[410]
    DIRECTION INPUT ;
    USE SIGNAL ;
    PORT
      LAYER M4 ;
        RECT  139.916 65.088 140 65.112 ;
    END
  END vm_rq[410]
  PIN vm_rq[411]
    DIRECTION INPUT ;
    USE SIGNAL ;
    PORT
      LAYER M4 ;
        RECT  139.916 65.136 140 65.16 ;
    END
  END vm_rq[411]
  PIN vm_rq[412]
    DIRECTION INPUT ;
    USE SIGNAL ;
    PORT
      LAYER M4 ;
        RECT  139.916 65.184 140 65.208 ;
    END
  END vm_rq[412]
  PIN vm_rq[413]
    DIRECTION INPUT ;
    USE SIGNAL ;
    PORT
      LAYER M4 ;
        RECT  139.916 65.232 140 65.256 ;
    END
  END vm_rq[413]
  PIN vm_rq[414]
    DIRECTION INPUT ;
    USE SIGNAL ;
    PORT
      LAYER M4 ;
        RECT  139.916 65.28 140 65.304 ;
    END
  END vm_rq[414]
  PIN vm_rq[415]
    DIRECTION INPUT ;
    USE SIGNAL ;
    PORT
      LAYER M4 ;
        RECT  139.916 65.328 140 65.352 ;
    END
  END vm_rq[415]
  PIN vm_rq[416]
    DIRECTION INPUT ;
    USE SIGNAL ;
    PORT
      LAYER M4 ;
        RECT  139.916 65.376 140 65.4 ;
    END
  END vm_rq[416]
  PIN vm_rq[417]
    DIRECTION INPUT ;
    USE SIGNAL ;
    PORT
      LAYER M4 ;
        RECT  139.916 65.424 140 65.448 ;
    END
  END vm_rq[417]
  PIN vm_rq[418]
    DIRECTION INPUT ;
    USE SIGNAL ;
    PORT
      LAYER M4 ;
        RECT  139.916 65.472 140 65.496 ;
    END
  END vm_rq[418]
  PIN vm_rq[419]
    DIRECTION INPUT ;
    USE SIGNAL ;
    PORT
      LAYER M4 ;
        RECT  139.916 65.52 140 65.544 ;
    END
  END vm_rq[419]
  PIN vm_rq[41]
    DIRECTION INPUT ;
    USE SIGNAL ;
    PORT
      LAYER M4 ;
        RECT  139.916 47.376 140 47.4 ;
    END
  END vm_rq[41]
  PIN vm_rq[420]
    DIRECTION INPUT ;
    USE SIGNAL ;
    PORT
      LAYER M4 ;
        RECT  139.916 65.568 140 65.592 ;
    END
  END vm_rq[420]
  PIN vm_rq[421]
    DIRECTION INPUT ;
    USE SIGNAL ;
    PORT
      LAYER M4 ;
        RECT  139.916 65.616 140 65.64 ;
    END
  END vm_rq[421]
  PIN vm_rq[422]
    DIRECTION INPUT ;
    USE SIGNAL ;
    PORT
      LAYER M4 ;
        RECT  139.916 65.664 140 65.688 ;
    END
  END vm_rq[422]
  PIN vm_rq[423]
    DIRECTION INPUT ;
    USE SIGNAL ;
    PORT
      LAYER M4 ;
        RECT  139.916 65.712 140 65.736 ;
    END
  END vm_rq[423]
  PIN vm_rq[424]
    DIRECTION INPUT ;
    USE SIGNAL ;
    PORT
      LAYER M4 ;
        RECT  139.916 65.76 140 65.784 ;
    END
  END vm_rq[424]
  PIN vm_rq[425]
    DIRECTION INPUT ;
    USE SIGNAL ;
    PORT
      LAYER M4 ;
        RECT  139.916 65.808 140 65.832 ;
    END
  END vm_rq[425]
  PIN vm_rq[426]
    DIRECTION INPUT ;
    USE SIGNAL ;
    PORT
      LAYER M4 ;
        RECT  139.916 65.856 140 65.88 ;
    END
  END vm_rq[426]
  PIN vm_rq[427]
    DIRECTION INPUT ;
    USE SIGNAL ;
    PORT
      LAYER M4 ;
        RECT  139.916 65.904 140 65.928 ;
    END
  END vm_rq[427]
  PIN vm_rq[428]
    DIRECTION INPUT ;
    USE SIGNAL ;
    PORT
      LAYER M4 ;
        RECT  139.916 65.952 140 65.976 ;
    END
  END vm_rq[428]
  PIN vm_rq[429]
    DIRECTION INPUT ;
    USE SIGNAL ;
    PORT
      LAYER M4 ;
        RECT  139.916 66 140 66.024 ;
    END
  END vm_rq[429]
  PIN vm_rq[42]
    DIRECTION INPUT ;
    USE SIGNAL ;
    PORT
      LAYER M4 ;
        RECT  139.916 47.424 140 47.448 ;
    END
  END vm_rq[42]
  PIN vm_rq[430]
    DIRECTION INPUT ;
    USE SIGNAL ;
    PORT
      LAYER M4 ;
        RECT  139.916 66.048 140 66.072 ;
    END
  END vm_rq[430]
  PIN vm_rq[431]
    DIRECTION INPUT ;
    USE SIGNAL ;
    PORT
      LAYER M4 ;
        RECT  139.916 66.096 140 66.12 ;
    END
  END vm_rq[431]
  PIN vm_rq[432]
    DIRECTION INPUT ;
    USE SIGNAL ;
    PORT
      LAYER M4 ;
        RECT  139.916 66.144 140 66.168 ;
    END
  END vm_rq[432]
  PIN vm_rq[433]
    DIRECTION INPUT ;
    USE SIGNAL ;
    PORT
      LAYER M4 ;
        RECT  139.916 66.192 140 66.216 ;
    END
  END vm_rq[433]
  PIN vm_rq[434]
    DIRECTION INPUT ;
    USE SIGNAL ;
    PORT
      LAYER M4 ;
        RECT  139.916 66.24 140 66.264 ;
    END
  END vm_rq[434]
  PIN vm_rq[435]
    DIRECTION INPUT ;
    USE SIGNAL ;
    PORT
      LAYER M4 ;
        RECT  139.916 66.288 140 66.312 ;
    END
  END vm_rq[435]
  PIN vm_rq[436]
    DIRECTION INPUT ;
    USE SIGNAL ;
    PORT
      LAYER M4 ;
        RECT  139.916 66.336 140 66.36 ;
    END
  END vm_rq[436]
  PIN vm_rq[437]
    DIRECTION INPUT ;
    USE SIGNAL ;
    PORT
      LAYER M4 ;
        RECT  139.916 66.384 140 66.408 ;
    END
  END vm_rq[437]
  PIN vm_rq[438]
    DIRECTION INPUT ;
    USE SIGNAL ;
    PORT
      LAYER M4 ;
        RECT  139.916 66.432 140 66.456 ;
    END
  END vm_rq[438]
  PIN vm_rq[439]
    DIRECTION INPUT ;
    USE SIGNAL ;
    PORT
      LAYER M4 ;
        RECT  139.916 66.48 140 66.504 ;
    END
  END vm_rq[439]
  PIN vm_rq[43]
    DIRECTION INPUT ;
    USE SIGNAL ;
    PORT
      LAYER M4 ;
        RECT  139.916 47.472 140 47.496 ;
    END
  END vm_rq[43]
  PIN vm_rq[440]
    DIRECTION INPUT ;
    USE SIGNAL ;
    PORT
      LAYER M4 ;
        RECT  139.916 66.528 140 66.552 ;
    END
  END vm_rq[440]
  PIN vm_rq[441]
    DIRECTION INPUT ;
    USE SIGNAL ;
    PORT
      LAYER M4 ;
        RECT  139.916 66.576 140 66.6 ;
    END
  END vm_rq[441]
  PIN vm_rq[442]
    DIRECTION INPUT ;
    USE SIGNAL ;
    PORT
      LAYER M4 ;
        RECT  139.916 66.624 140 66.648 ;
    END
  END vm_rq[442]
  PIN vm_rq[443]
    DIRECTION INPUT ;
    USE SIGNAL ;
    PORT
      LAYER M4 ;
        RECT  139.916 66.672 140 66.696 ;
    END
  END vm_rq[443]
  PIN vm_rq[444]
    DIRECTION INPUT ;
    USE SIGNAL ;
    PORT
      LAYER M4 ;
        RECT  139.916 66.72 140 66.744 ;
    END
  END vm_rq[444]
  PIN vm_rq[445]
    DIRECTION INPUT ;
    USE SIGNAL ;
    PORT
      LAYER M4 ;
        RECT  139.916 66.768 140 66.792 ;
    END
  END vm_rq[445]
  PIN vm_rq[446]
    DIRECTION INPUT ;
    USE SIGNAL ;
    PORT
      LAYER M4 ;
        RECT  139.916 66.816 140 66.84 ;
    END
  END vm_rq[446]
  PIN vm_rq[447]
    DIRECTION INPUT ;
    USE SIGNAL ;
    PORT
      LAYER M4 ;
        RECT  139.916 66.864 140 66.888 ;
    END
  END vm_rq[447]
  PIN vm_rq[448]
    DIRECTION INPUT ;
    USE SIGNAL ;
    PORT
      LAYER M4 ;
        RECT  139.916 66.912 140 66.936 ;
    END
  END vm_rq[448]
  PIN vm_rq[449]
    DIRECTION INPUT ;
    USE SIGNAL ;
    PORT
      LAYER M4 ;
        RECT  139.916 66.96 140 66.984 ;
    END
  END vm_rq[449]
  PIN vm_rq[44]
    DIRECTION INPUT ;
    USE SIGNAL ;
    PORT
      LAYER M4 ;
        RECT  139.916 47.52 140 47.544 ;
    END
  END vm_rq[44]
  PIN vm_rq[450]
    DIRECTION INPUT ;
    USE SIGNAL ;
    PORT
      LAYER M4 ;
        RECT  139.916 67.008 140 67.032 ;
    END
  END vm_rq[450]
  PIN vm_rq[451]
    DIRECTION INPUT ;
    USE SIGNAL ;
    PORT
      LAYER M4 ;
        RECT  139.916 67.056 140 67.08 ;
    END
  END vm_rq[451]
  PIN vm_rq[452]
    DIRECTION INPUT ;
    USE SIGNAL ;
    PORT
      LAYER M4 ;
        RECT  139.916 67.104 140 67.128 ;
    END
  END vm_rq[452]
  PIN vm_rq[453]
    DIRECTION INPUT ;
    USE SIGNAL ;
    PORT
      LAYER M4 ;
        RECT  139.916 67.152 140 67.176 ;
    END
  END vm_rq[453]
  PIN vm_rq[454]
    DIRECTION INPUT ;
    USE SIGNAL ;
    PORT
      LAYER M4 ;
        RECT  139.916 67.2 140 67.224 ;
    END
  END vm_rq[454]
  PIN vm_rq[455]
    DIRECTION INPUT ;
    USE SIGNAL ;
    PORT
      LAYER M4 ;
        RECT  139.916 67.248 140 67.272 ;
    END
  END vm_rq[455]
  PIN vm_rq[456]
    DIRECTION INPUT ;
    USE SIGNAL ;
    PORT
      LAYER M4 ;
        RECT  139.916 67.296 140 67.32 ;
    END
  END vm_rq[456]
  PIN vm_rq[457]
    DIRECTION INPUT ;
    USE SIGNAL ;
    PORT
      LAYER M4 ;
        RECT  139.916 67.344 140 67.368 ;
    END
  END vm_rq[457]
  PIN vm_rq[458]
    DIRECTION INPUT ;
    USE SIGNAL ;
    PORT
      LAYER M4 ;
        RECT  139.916 67.392 140 67.416 ;
    END
  END vm_rq[458]
  PIN vm_rq[459]
    DIRECTION INPUT ;
    USE SIGNAL ;
    PORT
      LAYER M4 ;
        RECT  139.916 67.44 140 67.464 ;
    END
  END vm_rq[459]
  PIN vm_rq[45]
    DIRECTION INPUT ;
    USE SIGNAL ;
    PORT
      LAYER M4 ;
        RECT  139.916 47.568 140 47.592 ;
    END
  END vm_rq[45]
  PIN vm_rq[460]
    DIRECTION INPUT ;
    USE SIGNAL ;
    PORT
      LAYER M4 ;
        RECT  139.916 67.488 140 67.512 ;
    END
  END vm_rq[460]
  PIN vm_rq[461]
    DIRECTION INPUT ;
    USE SIGNAL ;
    PORT
      LAYER M4 ;
        RECT  139.916 67.536 140 67.56 ;
    END
  END vm_rq[461]
  PIN vm_rq[462]
    DIRECTION INPUT ;
    USE SIGNAL ;
    PORT
      LAYER M4 ;
        RECT  139.916 67.584 140 67.608 ;
    END
  END vm_rq[462]
  PIN vm_rq[463]
    DIRECTION INPUT ;
    USE SIGNAL ;
    PORT
      LAYER M4 ;
        RECT  139.916 67.632 140 67.656 ;
    END
  END vm_rq[463]
  PIN vm_rq[464]
    DIRECTION INPUT ;
    USE SIGNAL ;
    PORT
      LAYER M4 ;
        RECT  139.916 67.68 140 67.704 ;
    END
  END vm_rq[464]
  PIN vm_rq[465]
    DIRECTION INPUT ;
    USE SIGNAL ;
    PORT
      LAYER M4 ;
        RECT  139.916 67.728 140 67.752 ;
    END
  END vm_rq[465]
  PIN vm_rq[466]
    DIRECTION INPUT ;
    USE SIGNAL ;
    PORT
      LAYER M4 ;
        RECT  139.916 67.776 140 67.8 ;
    END
  END vm_rq[466]
  PIN vm_rq[467]
    DIRECTION INPUT ;
    USE SIGNAL ;
    PORT
      LAYER M4 ;
        RECT  139.916 67.824 140 67.848 ;
    END
  END vm_rq[467]
  PIN vm_rq[468]
    DIRECTION INPUT ;
    USE SIGNAL ;
    PORT
      LAYER M4 ;
        RECT  139.916 67.872 140 67.896 ;
    END
  END vm_rq[468]
  PIN vm_rq[469]
    DIRECTION INPUT ;
    USE SIGNAL ;
    PORT
      LAYER M4 ;
        RECT  139.916 67.92 140 67.944 ;
    END
  END vm_rq[469]
  PIN vm_rq[46]
    DIRECTION INPUT ;
    USE SIGNAL ;
    PORT
      LAYER M4 ;
        RECT  139.916 47.616 140 47.64 ;
    END
  END vm_rq[46]
  PIN vm_rq[470]
    DIRECTION INPUT ;
    USE SIGNAL ;
    PORT
      LAYER M4 ;
        RECT  139.916 67.968 140 67.992 ;
    END
  END vm_rq[470]
  PIN vm_rq[471]
    DIRECTION INPUT ;
    USE SIGNAL ;
    PORT
      LAYER M4 ;
        RECT  139.916 68.016 140 68.04 ;
    END
  END vm_rq[471]
  PIN vm_rq[472]
    DIRECTION INPUT ;
    USE SIGNAL ;
    PORT
      LAYER M4 ;
        RECT  139.916 68.064 140 68.088 ;
    END
  END vm_rq[472]
  PIN vm_rq[473]
    DIRECTION INPUT ;
    USE SIGNAL ;
    PORT
      LAYER M4 ;
        RECT  139.916 68.112 140 68.136 ;
    END
  END vm_rq[473]
  PIN vm_rq[474]
    DIRECTION INPUT ;
    USE SIGNAL ;
    PORT
      LAYER M4 ;
        RECT  139.916 68.16 140 68.184 ;
    END
  END vm_rq[474]
  PIN vm_rq[475]
    DIRECTION INPUT ;
    USE SIGNAL ;
    PORT
      LAYER M4 ;
        RECT  139.916 68.208 140 68.232 ;
    END
  END vm_rq[475]
  PIN vm_rq[476]
    DIRECTION INPUT ;
    USE SIGNAL ;
    PORT
      LAYER M4 ;
        RECT  139.916 68.256 140 68.28 ;
    END
  END vm_rq[476]
  PIN vm_rq[477]
    DIRECTION INPUT ;
    USE SIGNAL ;
    PORT
      LAYER M4 ;
        RECT  139.916 68.304 140 68.328 ;
    END
  END vm_rq[477]
  PIN vm_rq[478]
    DIRECTION INPUT ;
    USE SIGNAL ;
    PORT
      LAYER M4 ;
        RECT  139.916 68.352 140 68.376 ;
    END
  END vm_rq[478]
  PIN vm_rq[479]
    DIRECTION INPUT ;
    USE SIGNAL ;
    PORT
      LAYER M4 ;
        RECT  139.916 68.4 140 68.424 ;
    END
  END vm_rq[479]
  PIN vm_rq[47]
    DIRECTION INPUT ;
    USE SIGNAL ;
    PORT
      LAYER M4 ;
        RECT  139.916 47.664 140 47.688 ;
    END
  END vm_rq[47]
  PIN vm_rq[480]
    DIRECTION INPUT ;
    USE SIGNAL ;
    PORT
      LAYER M4 ;
        RECT  139.916 68.448 140 68.472 ;
    END
  END vm_rq[480]
  PIN vm_rq[481]
    DIRECTION INPUT ;
    USE SIGNAL ;
    PORT
      LAYER M4 ;
        RECT  139.916 68.496 140 68.52 ;
    END
  END vm_rq[481]
  PIN vm_rq[482]
    DIRECTION INPUT ;
    USE SIGNAL ;
    PORT
      LAYER M4 ;
        RECT  139.916 68.544 140 68.568 ;
    END
  END vm_rq[482]
  PIN vm_rq[483]
    DIRECTION INPUT ;
    USE SIGNAL ;
    PORT
      LAYER M4 ;
        RECT  139.916 68.592 140 68.616 ;
    END
  END vm_rq[483]
  PIN vm_rq[484]
    DIRECTION INPUT ;
    USE SIGNAL ;
    PORT
      LAYER M4 ;
        RECT  139.916 68.64 140 68.664 ;
    END
  END vm_rq[484]
  PIN vm_rq[485]
    DIRECTION INPUT ;
    USE SIGNAL ;
    PORT
      LAYER M4 ;
        RECT  139.916 68.688 140 68.712 ;
    END
  END vm_rq[485]
  PIN vm_rq[486]
    DIRECTION INPUT ;
    USE SIGNAL ;
    PORT
      LAYER M4 ;
        RECT  139.916 68.736 140 68.76 ;
    END
  END vm_rq[486]
  PIN vm_rq[487]
    DIRECTION INPUT ;
    USE SIGNAL ;
    PORT
      LAYER M4 ;
        RECT  139.916 68.784 140 68.808 ;
    END
  END vm_rq[487]
  PIN vm_rq[488]
    DIRECTION INPUT ;
    USE SIGNAL ;
    PORT
      LAYER M4 ;
        RECT  139.916 68.832 140 68.856 ;
    END
  END vm_rq[488]
  PIN vm_rq[489]
    DIRECTION INPUT ;
    USE SIGNAL ;
    PORT
      LAYER M4 ;
        RECT  139.916 68.88 140 68.904 ;
    END
  END vm_rq[489]
  PIN vm_rq[48]
    DIRECTION INPUT ;
    USE SIGNAL ;
    PORT
      LAYER M4 ;
        RECT  139.916 47.712 140 47.736 ;
    END
  END vm_rq[48]
  PIN vm_rq[490]
    DIRECTION INPUT ;
    USE SIGNAL ;
    PORT
      LAYER M4 ;
        RECT  139.916 68.928 140 68.952 ;
    END
  END vm_rq[490]
  PIN vm_rq[491]
    DIRECTION INPUT ;
    USE SIGNAL ;
    PORT
      LAYER M4 ;
        RECT  139.916 68.976 140 69 ;
    END
  END vm_rq[491]
  PIN vm_rq[492]
    DIRECTION INPUT ;
    USE SIGNAL ;
    PORT
      LAYER M4 ;
        RECT  139.916 69.024 140 69.048 ;
    END
  END vm_rq[492]
  PIN vm_rq[493]
    DIRECTION INPUT ;
    USE SIGNAL ;
    PORT
      LAYER M4 ;
        RECT  139.916 69.072 140 69.096 ;
    END
  END vm_rq[493]
  PIN vm_rq[494]
    DIRECTION INPUT ;
    USE SIGNAL ;
    PORT
      LAYER M4 ;
        RECT  139.916 69.12 140 69.144 ;
    END
  END vm_rq[494]
  PIN vm_rq[495]
    DIRECTION INPUT ;
    USE SIGNAL ;
    PORT
      LAYER M4 ;
        RECT  139.916 69.168 140 69.192 ;
    END
  END vm_rq[495]
  PIN vm_rq[496]
    DIRECTION INPUT ;
    USE SIGNAL ;
    PORT
      LAYER M4 ;
        RECT  139.916 69.216 140 69.24 ;
    END
  END vm_rq[496]
  PIN vm_rq[497]
    DIRECTION INPUT ;
    USE SIGNAL ;
    PORT
      LAYER M4 ;
        RECT  139.916 69.264 140 69.288 ;
    END
  END vm_rq[497]
  PIN vm_rq[498]
    DIRECTION INPUT ;
    USE SIGNAL ;
    PORT
      LAYER M4 ;
        RECT  139.916 69.312 140 69.336 ;
    END
  END vm_rq[498]
  PIN vm_rq[499]
    DIRECTION INPUT ;
    USE SIGNAL ;
    PORT
      LAYER M4 ;
        RECT  139.916 69.36 140 69.384 ;
    END
  END vm_rq[499]
  PIN vm_rq[49]
    DIRECTION INPUT ;
    USE SIGNAL ;
    PORT
      LAYER M4 ;
        RECT  139.916 47.76 140 47.784 ;
    END
  END vm_rq[49]
  PIN vm_rq[4]
    DIRECTION INPUT ;
    USE SIGNAL ;
    PORT
      LAYER M4 ;
        RECT  139.916 45.6 140 45.624 ;
    END
  END vm_rq[4]
  PIN vm_rq[500]
    DIRECTION INPUT ;
    USE SIGNAL ;
    PORT
      LAYER M4 ;
        RECT  139.916 69.408 140 69.432 ;
    END
  END vm_rq[500]
  PIN vm_rq[501]
    DIRECTION INPUT ;
    USE SIGNAL ;
    PORT
      LAYER M4 ;
        RECT  139.916 69.456 140 69.48 ;
    END
  END vm_rq[501]
  PIN vm_rq[502]
    DIRECTION INPUT ;
    USE SIGNAL ;
    PORT
      LAYER M4 ;
        RECT  139.916 69.504 140 69.528 ;
    END
  END vm_rq[502]
  PIN vm_rq[503]
    DIRECTION INPUT ;
    USE SIGNAL ;
    PORT
      LAYER M4 ;
        RECT  139.916 69.552 140 69.576 ;
    END
  END vm_rq[503]
  PIN vm_rq[504]
    DIRECTION INPUT ;
    USE SIGNAL ;
    PORT
      LAYER M4 ;
        RECT  139.916 69.6 140 69.624 ;
    END
  END vm_rq[504]
  PIN vm_rq[505]
    DIRECTION INPUT ;
    USE SIGNAL ;
    PORT
      LAYER M4 ;
        RECT  139.916 69.648 140 69.672 ;
    END
  END vm_rq[505]
  PIN vm_rq[506]
    DIRECTION INPUT ;
    USE SIGNAL ;
    PORT
      LAYER M4 ;
        RECT  139.916 69.696 140 69.72 ;
    END
  END vm_rq[506]
  PIN vm_rq[507]
    DIRECTION INPUT ;
    USE SIGNAL ;
    PORT
      LAYER M4 ;
        RECT  139.916 69.744 140 69.768 ;
    END
  END vm_rq[507]
  PIN vm_rq[508]
    DIRECTION INPUT ;
    USE SIGNAL ;
    PORT
      LAYER M4 ;
        RECT  139.916 69.792 140 69.816 ;
    END
  END vm_rq[508]
  PIN vm_rq[509]
    DIRECTION INPUT ;
    USE SIGNAL ;
    PORT
      LAYER M4 ;
        RECT  139.916 69.84 140 69.864 ;
    END
  END vm_rq[509]
  PIN vm_rq[50]
    DIRECTION INPUT ;
    USE SIGNAL ;
    PORT
      LAYER M4 ;
        RECT  139.916 47.808 140 47.832 ;
    END
  END vm_rq[50]
  PIN vm_rq[510]
    DIRECTION INPUT ;
    USE SIGNAL ;
    PORT
      LAYER M4 ;
        RECT  139.916 69.888 140 69.912 ;
    END
  END vm_rq[510]
  PIN vm_rq[511]
    DIRECTION INPUT ;
    USE SIGNAL ;
    PORT
      LAYER M4 ;
        RECT  139.916 69.936 140 69.96 ;
    END
  END vm_rq[511]
  PIN vm_rq[51]
    DIRECTION INPUT ;
    USE SIGNAL ;
    PORT
      LAYER M4 ;
        RECT  139.916 47.856 140 47.88 ;
    END
  END vm_rq[51]
  PIN vm_rq[52]
    DIRECTION INPUT ;
    USE SIGNAL ;
    PORT
      LAYER M4 ;
        RECT  139.916 47.904 140 47.928 ;
    END
  END vm_rq[52]
  PIN vm_rq[53]
    DIRECTION INPUT ;
    USE SIGNAL ;
    PORT
      LAYER M4 ;
        RECT  139.916 47.952 140 47.976 ;
    END
  END vm_rq[53]
  PIN vm_rq[54]
    DIRECTION INPUT ;
    USE SIGNAL ;
    PORT
      LAYER M4 ;
        RECT  139.916 48 140 48.024 ;
    END
  END vm_rq[54]
  PIN vm_rq[55]
    DIRECTION INPUT ;
    USE SIGNAL ;
    PORT
      LAYER M4 ;
        RECT  139.916 48.048 140 48.072 ;
    END
  END vm_rq[55]
  PIN vm_rq[56]
    DIRECTION INPUT ;
    USE SIGNAL ;
    PORT
      LAYER M4 ;
        RECT  139.916 48.096 140 48.12 ;
    END
  END vm_rq[56]
  PIN vm_rq[57]
    DIRECTION INPUT ;
    USE SIGNAL ;
    PORT
      LAYER M4 ;
        RECT  139.916 48.144 140 48.168 ;
    END
  END vm_rq[57]
  PIN vm_rq[58]
    DIRECTION INPUT ;
    USE SIGNAL ;
    PORT
      LAYER M4 ;
        RECT  139.916 48.192 140 48.216 ;
    END
  END vm_rq[58]
  PIN vm_rq[59]
    DIRECTION INPUT ;
    USE SIGNAL ;
    PORT
      LAYER M4 ;
        RECT  139.916 48.24 140 48.264 ;
    END
  END vm_rq[59]
  PIN vm_rq[5]
    DIRECTION INPUT ;
    USE SIGNAL ;
    PORT
      LAYER M4 ;
        RECT  139.916 45.648 140 45.672 ;
    END
  END vm_rq[5]
  PIN vm_rq[60]
    DIRECTION INPUT ;
    USE SIGNAL ;
    PORT
      LAYER M4 ;
        RECT  139.916 48.288 140 48.312 ;
    END
  END vm_rq[60]
  PIN vm_rq[61]
    DIRECTION INPUT ;
    USE SIGNAL ;
    PORT
      LAYER M4 ;
        RECT  139.916 48.336 140 48.36 ;
    END
  END vm_rq[61]
  PIN vm_rq[62]
    DIRECTION INPUT ;
    USE SIGNAL ;
    PORT
      LAYER M4 ;
        RECT  139.916 48.384 140 48.408 ;
    END
  END vm_rq[62]
  PIN vm_rq[63]
    DIRECTION INPUT ;
    USE SIGNAL ;
    PORT
      LAYER M4 ;
        RECT  139.916 48.432 140 48.456 ;
    END
  END vm_rq[63]
  PIN vm_rq[64]
    DIRECTION INPUT ;
    USE SIGNAL ;
    PORT
      LAYER M4 ;
        RECT  139.916 48.48 140 48.504 ;
    END
  END vm_rq[64]
  PIN vm_rq[65]
    DIRECTION INPUT ;
    USE SIGNAL ;
    PORT
      LAYER M4 ;
        RECT  139.916 48.528 140 48.552 ;
    END
  END vm_rq[65]
  PIN vm_rq[66]
    DIRECTION INPUT ;
    USE SIGNAL ;
    PORT
      LAYER M4 ;
        RECT  139.916 48.576 140 48.6 ;
    END
  END vm_rq[66]
  PIN vm_rq[67]
    DIRECTION INPUT ;
    USE SIGNAL ;
    PORT
      LAYER M4 ;
        RECT  139.916 48.624 140 48.648 ;
    END
  END vm_rq[67]
  PIN vm_rq[68]
    DIRECTION INPUT ;
    USE SIGNAL ;
    PORT
      LAYER M4 ;
        RECT  139.916 48.672 140 48.696 ;
    END
  END vm_rq[68]
  PIN vm_rq[69]
    DIRECTION INPUT ;
    USE SIGNAL ;
    PORT
      LAYER M4 ;
        RECT  139.916 48.72 140 48.744 ;
    END
  END vm_rq[69]
  PIN vm_rq[6]
    DIRECTION INPUT ;
    USE SIGNAL ;
    PORT
      LAYER M4 ;
        RECT  139.916 45.696 140 45.72 ;
    END
  END vm_rq[6]
  PIN vm_rq[70]
    DIRECTION INPUT ;
    USE SIGNAL ;
    PORT
      LAYER M4 ;
        RECT  139.916 48.768 140 48.792 ;
    END
  END vm_rq[70]
  PIN vm_rq[71]
    DIRECTION INPUT ;
    USE SIGNAL ;
    PORT
      LAYER M4 ;
        RECT  139.916 48.816 140 48.84 ;
    END
  END vm_rq[71]
  PIN vm_rq[72]
    DIRECTION INPUT ;
    USE SIGNAL ;
    PORT
      LAYER M4 ;
        RECT  139.916 48.864 140 48.888 ;
    END
  END vm_rq[72]
  PIN vm_rq[73]
    DIRECTION INPUT ;
    USE SIGNAL ;
    PORT
      LAYER M4 ;
        RECT  139.916 48.912 140 48.936 ;
    END
  END vm_rq[73]
  PIN vm_rq[74]
    DIRECTION INPUT ;
    USE SIGNAL ;
    PORT
      LAYER M4 ;
        RECT  139.916 48.96 140 48.984 ;
    END
  END vm_rq[74]
  PIN vm_rq[75]
    DIRECTION INPUT ;
    USE SIGNAL ;
    PORT
      LAYER M4 ;
        RECT  139.916 49.008 140 49.032 ;
    END
  END vm_rq[75]
  PIN vm_rq[76]
    DIRECTION INPUT ;
    USE SIGNAL ;
    PORT
      LAYER M4 ;
        RECT  139.916 49.056 140 49.08 ;
    END
  END vm_rq[76]
  PIN vm_rq[77]
    DIRECTION INPUT ;
    USE SIGNAL ;
    PORT
      LAYER M4 ;
        RECT  139.916 49.104 140 49.128 ;
    END
  END vm_rq[77]
  PIN vm_rq[78]
    DIRECTION INPUT ;
    USE SIGNAL ;
    PORT
      LAYER M4 ;
        RECT  139.916 49.152 140 49.176 ;
    END
  END vm_rq[78]
  PIN vm_rq[79]
    DIRECTION INPUT ;
    USE SIGNAL ;
    PORT
      LAYER M4 ;
        RECT  139.916 49.2 140 49.224 ;
    END
  END vm_rq[79]
  PIN vm_rq[7]
    DIRECTION INPUT ;
    USE SIGNAL ;
    PORT
      LAYER M4 ;
        RECT  139.916 45.744 140 45.768 ;
    END
  END vm_rq[7]
  PIN vm_rq[80]
    DIRECTION INPUT ;
    USE SIGNAL ;
    PORT
      LAYER M4 ;
        RECT  139.916 49.248 140 49.272 ;
    END
  END vm_rq[80]
  PIN vm_rq[81]
    DIRECTION INPUT ;
    USE SIGNAL ;
    PORT
      LAYER M4 ;
        RECT  139.916 49.296 140 49.32 ;
    END
  END vm_rq[81]
  PIN vm_rq[82]
    DIRECTION INPUT ;
    USE SIGNAL ;
    PORT
      LAYER M4 ;
        RECT  139.916 49.344 140 49.368 ;
    END
  END vm_rq[82]
  PIN vm_rq[83]
    DIRECTION INPUT ;
    USE SIGNAL ;
    PORT
      LAYER M4 ;
        RECT  139.916 49.392 140 49.416 ;
    END
  END vm_rq[83]
  PIN vm_rq[84]
    DIRECTION INPUT ;
    USE SIGNAL ;
    PORT
      LAYER M4 ;
        RECT  139.916 49.44 140 49.464 ;
    END
  END vm_rq[84]
  PIN vm_rq[85]
    DIRECTION INPUT ;
    USE SIGNAL ;
    PORT
      LAYER M4 ;
        RECT  139.916 49.488 140 49.512 ;
    END
  END vm_rq[85]
  PIN vm_rq[86]
    DIRECTION INPUT ;
    USE SIGNAL ;
    PORT
      LAYER M4 ;
        RECT  139.916 49.536 140 49.56 ;
    END
  END vm_rq[86]
  PIN vm_rq[87]
    DIRECTION INPUT ;
    USE SIGNAL ;
    PORT
      LAYER M4 ;
        RECT  139.916 49.584 140 49.608 ;
    END
  END vm_rq[87]
  PIN vm_rq[88]
    DIRECTION INPUT ;
    USE SIGNAL ;
    PORT
      LAYER M4 ;
        RECT  139.916 49.632 140 49.656 ;
    END
  END vm_rq[88]
  PIN vm_rq[89]
    DIRECTION INPUT ;
    USE SIGNAL ;
    PORT
      LAYER M4 ;
        RECT  139.916 49.68 140 49.704 ;
    END
  END vm_rq[89]
  PIN vm_rq[8]
    DIRECTION INPUT ;
    USE SIGNAL ;
    PORT
      LAYER M4 ;
        RECT  139.916 45.792 140 45.816 ;
    END
  END vm_rq[8]
  PIN vm_rq[90]
    DIRECTION INPUT ;
    USE SIGNAL ;
    PORT
      LAYER M4 ;
        RECT  139.916 49.728 140 49.752 ;
    END
  END vm_rq[90]
  PIN vm_rq[91]
    DIRECTION INPUT ;
    USE SIGNAL ;
    PORT
      LAYER M4 ;
        RECT  139.916 49.776 140 49.8 ;
    END
  END vm_rq[91]
  PIN vm_rq[92]
    DIRECTION INPUT ;
    USE SIGNAL ;
    PORT
      LAYER M4 ;
        RECT  139.916 49.824 140 49.848 ;
    END
  END vm_rq[92]
  PIN vm_rq[93]
    DIRECTION INPUT ;
    USE SIGNAL ;
    PORT
      LAYER M4 ;
        RECT  139.916 49.872 140 49.896 ;
    END
  END vm_rq[93]
  PIN vm_rq[94]
    DIRECTION INPUT ;
    USE SIGNAL ;
    PORT
      LAYER M4 ;
        RECT  139.916 49.92 140 49.944 ;
    END
  END vm_rq[94]
  PIN vm_rq[95]
    DIRECTION INPUT ;
    USE SIGNAL ;
    PORT
      LAYER M4 ;
        RECT  139.916 49.968 140 49.992 ;
    END
  END vm_rq[95]
  PIN vm_rq[96]
    DIRECTION INPUT ;
    USE SIGNAL ;
    PORT
      LAYER M4 ;
        RECT  139.916 50.016 140 50.04 ;
    END
  END vm_rq[96]
  PIN vm_rq[97]
    DIRECTION INPUT ;
    USE SIGNAL ;
    PORT
      LAYER M4 ;
        RECT  139.916 50.064 140 50.088 ;
    END
  END vm_rq[97]
  PIN vm_rq[98]
    DIRECTION INPUT ;
    USE SIGNAL ;
    PORT
      LAYER M4 ;
        RECT  139.916 50.112 140 50.136 ;
    END
  END vm_rq[98]
  PIN vm_rq[99]
    DIRECTION INPUT ;
    USE SIGNAL ;
    PORT
      LAYER M4 ;
        RECT  139.916 50.16 140 50.184 ;
    END
  END vm_rq[99]
  PIN vm_rq[9]
    DIRECTION INPUT ;
    USE SIGNAL ;
    PORT
      LAYER M4 ;
        RECT  139.916 45.84 140 45.864 ;
    END
  END vm_rq[9]
  PIN vm_waddr[0]
    DIRECTION OUTPUT ;
    USE SIGNAL ;
    PORT
      LAYER M4 ;
        RECT  139.916 69.984 140 70.008 ;
    END
  END vm_waddr[0]
  PIN vm_waddr[1]
    DIRECTION OUTPUT ;
    USE SIGNAL ;
    PORT
      LAYER M4 ;
        RECT  139.916 70.032 140 70.056 ;
    END
  END vm_waddr[1]
  PIN vm_waddr[2]
    DIRECTION OUTPUT ;
    USE SIGNAL ;
    PORT
      LAYER M4 ;
        RECT  139.916 70.08 140 70.104 ;
    END
  END vm_waddr[2]
  PIN vm_waddr[3]
    DIRECTION OUTPUT ;
    USE SIGNAL ;
    PORT
      LAYER M4 ;
        RECT  139.916 70.128 140 70.152 ;
    END
  END vm_waddr[3]
  PIN vm_waddr[4]
    DIRECTION OUTPUT ;
    USE SIGNAL ;
    PORT
      LAYER M4 ;
        RECT  139.916 70.176 140 70.2 ;
    END
  END vm_waddr[4]
  PIN vm_waddr[5]
    DIRECTION OUTPUT ;
    USE SIGNAL ;
    PORT
      LAYER M4 ;
        RECT  139.916 70.224 140 70.248 ;
    END
  END vm_waddr[5]
  PIN vm_waddr[6]
    DIRECTION OUTPUT ;
    USE SIGNAL ;
    PORT
      LAYER M4 ;
        RECT  139.916 70.272 140 70.296 ;
    END
  END vm_waddr[6]
  PIN vm_waddr[7]
    DIRECTION OUTPUT ;
    USE SIGNAL ;
    PORT
      LAYER M4 ;
        RECT  139.916 70.32 140 70.344 ;
    END
  END vm_waddr[7]
  PIN vm_wdata[0]
    DIRECTION OUTPUT ;
    USE SIGNAL ;
    PORT
      LAYER M4 ;
        RECT  139.916 70.368 140 70.392 ;
    END
  END vm_wdata[0]
  PIN vm_wdata[100]
    DIRECTION OUTPUT ;
    USE SIGNAL ;
    PORT
      LAYER M4 ;
        RECT  139.916 75.168 140 75.192 ;
    END
  END vm_wdata[100]
  PIN vm_wdata[101]
    DIRECTION OUTPUT ;
    USE SIGNAL ;
    PORT
      LAYER M4 ;
        RECT  139.916 75.216 140 75.24 ;
    END
  END vm_wdata[101]
  PIN vm_wdata[102]
    DIRECTION OUTPUT ;
    USE SIGNAL ;
    PORT
      LAYER M4 ;
        RECT  139.916 75.264 140 75.288 ;
    END
  END vm_wdata[102]
  PIN vm_wdata[103]
    DIRECTION OUTPUT ;
    USE SIGNAL ;
    PORT
      LAYER M4 ;
        RECT  139.916 75.312 140 75.336 ;
    END
  END vm_wdata[103]
  PIN vm_wdata[104]
    DIRECTION OUTPUT ;
    USE SIGNAL ;
    PORT
      LAYER M4 ;
        RECT  139.916 75.36 140 75.384 ;
    END
  END vm_wdata[104]
  PIN vm_wdata[105]
    DIRECTION OUTPUT ;
    USE SIGNAL ;
    PORT
      LAYER M4 ;
        RECT  139.916 75.408 140 75.432 ;
    END
  END vm_wdata[105]
  PIN vm_wdata[106]
    DIRECTION OUTPUT ;
    USE SIGNAL ;
    PORT
      LAYER M4 ;
        RECT  139.916 75.456 140 75.48 ;
    END
  END vm_wdata[106]
  PIN vm_wdata[107]
    DIRECTION OUTPUT ;
    USE SIGNAL ;
    PORT
      LAYER M4 ;
        RECT  139.916 75.504 140 75.528 ;
    END
  END vm_wdata[107]
  PIN vm_wdata[108]
    DIRECTION OUTPUT ;
    USE SIGNAL ;
    PORT
      LAYER M4 ;
        RECT  139.916 75.552 140 75.576 ;
    END
  END vm_wdata[108]
  PIN vm_wdata[109]
    DIRECTION OUTPUT ;
    USE SIGNAL ;
    PORT
      LAYER M4 ;
        RECT  139.916 75.6 140 75.624 ;
    END
  END vm_wdata[109]
  PIN vm_wdata[10]
    DIRECTION OUTPUT ;
    USE SIGNAL ;
    PORT
      LAYER M4 ;
        RECT  139.916 70.848 140 70.872 ;
    END
  END vm_wdata[10]
  PIN vm_wdata[110]
    DIRECTION OUTPUT ;
    USE SIGNAL ;
    PORT
      LAYER M4 ;
        RECT  139.916 75.648 140 75.672 ;
    END
  END vm_wdata[110]
  PIN vm_wdata[111]
    DIRECTION OUTPUT ;
    USE SIGNAL ;
    PORT
      LAYER M4 ;
        RECT  139.916 75.696 140 75.72 ;
    END
  END vm_wdata[111]
  PIN vm_wdata[112]
    DIRECTION OUTPUT ;
    USE SIGNAL ;
    PORT
      LAYER M4 ;
        RECT  139.916 75.744 140 75.768 ;
    END
  END vm_wdata[112]
  PIN vm_wdata[113]
    DIRECTION OUTPUT ;
    USE SIGNAL ;
    PORT
      LAYER M4 ;
        RECT  139.916 75.792 140 75.816 ;
    END
  END vm_wdata[113]
  PIN vm_wdata[114]
    DIRECTION OUTPUT ;
    USE SIGNAL ;
    PORT
      LAYER M4 ;
        RECT  139.916 75.84 140 75.864 ;
    END
  END vm_wdata[114]
  PIN vm_wdata[115]
    DIRECTION OUTPUT ;
    USE SIGNAL ;
    PORT
      LAYER M4 ;
        RECT  139.916 75.888 140 75.912 ;
    END
  END vm_wdata[115]
  PIN vm_wdata[116]
    DIRECTION OUTPUT ;
    USE SIGNAL ;
    PORT
      LAYER M4 ;
        RECT  139.916 75.936 140 75.96 ;
    END
  END vm_wdata[116]
  PIN vm_wdata[117]
    DIRECTION OUTPUT ;
    USE SIGNAL ;
    PORT
      LAYER M4 ;
        RECT  139.916 75.984 140 76.008 ;
    END
  END vm_wdata[117]
  PIN vm_wdata[118]
    DIRECTION OUTPUT ;
    USE SIGNAL ;
    PORT
      LAYER M4 ;
        RECT  139.916 76.032 140 76.056 ;
    END
  END vm_wdata[118]
  PIN vm_wdata[119]
    DIRECTION OUTPUT ;
    USE SIGNAL ;
    PORT
      LAYER M4 ;
        RECT  139.916 76.08 140 76.104 ;
    END
  END vm_wdata[119]
  PIN vm_wdata[11]
    DIRECTION OUTPUT ;
    USE SIGNAL ;
    PORT
      LAYER M4 ;
        RECT  139.916 70.896 140 70.92 ;
    END
  END vm_wdata[11]
  PIN vm_wdata[120]
    DIRECTION OUTPUT ;
    USE SIGNAL ;
    PORT
      LAYER M4 ;
        RECT  139.916 76.128 140 76.152 ;
    END
  END vm_wdata[120]
  PIN vm_wdata[121]
    DIRECTION OUTPUT ;
    USE SIGNAL ;
    PORT
      LAYER M4 ;
        RECT  139.916 76.176 140 76.2 ;
    END
  END vm_wdata[121]
  PIN vm_wdata[122]
    DIRECTION OUTPUT ;
    USE SIGNAL ;
    PORT
      LAYER M4 ;
        RECT  139.916 76.224 140 76.248 ;
    END
  END vm_wdata[122]
  PIN vm_wdata[123]
    DIRECTION OUTPUT ;
    USE SIGNAL ;
    PORT
      LAYER M4 ;
        RECT  139.916 76.272 140 76.296 ;
    END
  END vm_wdata[123]
  PIN vm_wdata[124]
    DIRECTION OUTPUT ;
    USE SIGNAL ;
    PORT
      LAYER M4 ;
        RECT  139.916 76.32 140 76.344 ;
    END
  END vm_wdata[124]
  PIN vm_wdata[125]
    DIRECTION OUTPUT ;
    USE SIGNAL ;
    PORT
      LAYER M4 ;
        RECT  139.916 76.368 140 76.392 ;
    END
  END vm_wdata[125]
  PIN vm_wdata[126]
    DIRECTION OUTPUT ;
    USE SIGNAL ;
    PORT
      LAYER M4 ;
        RECT  139.916 76.416 140 76.44 ;
    END
  END vm_wdata[126]
  PIN vm_wdata[127]
    DIRECTION OUTPUT ;
    USE SIGNAL ;
    PORT
      LAYER M4 ;
        RECT  139.916 76.464 140 76.488 ;
    END
  END vm_wdata[127]
  PIN vm_wdata[128]
    DIRECTION OUTPUT ;
    USE SIGNAL ;
    PORT
      LAYER M4 ;
        RECT  139.916 76.512 140 76.536 ;
    END
  END vm_wdata[128]
  PIN vm_wdata[129]
    DIRECTION OUTPUT ;
    USE SIGNAL ;
    PORT
      LAYER M4 ;
        RECT  139.916 76.56 140 76.584 ;
    END
  END vm_wdata[129]
  PIN vm_wdata[12]
    DIRECTION OUTPUT ;
    USE SIGNAL ;
    PORT
      LAYER M4 ;
        RECT  139.916 70.944 140 70.968 ;
    END
  END vm_wdata[12]
  PIN vm_wdata[130]
    DIRECTION OUTPUT ;
    USE SIGNAL ;
    PORT
      LAYER M4 ;
        RECT  139.916 76.608 140 76.632 ;
    END
  END vm_wdata[130]
  PIN vm_wdata[131]
    DIRECTION OUTPUT ;
    USE SIGNAL ;
    PORT
      LAYER M4 ;
        RECT  139.916 76.656 140 76.68 ;
    END
  END vm_wdata[131]
  PIN vm_wdata[132]
    DIRECTION OUTPUT ;
    USE SIGNAL ;
    PORT
      LAYER M4 ;
        RECT  139.916 76.704 140 76.728 ;
    END
  END vm_wdata[132]
  PIN vm_wdata[133]
    DIRECTION OUTPUT ;
    USE SIGNAL ;
    PORT
      LAYER M4 ;
        RECT  139.916 76.752 140 76.776 ;
    END
  END vm_wdata[133]
  PIN vm_wdata[134]
    DIRECTION OUTPUT ;
    USE SIGNAL ;
    PORT
      LAYER M4 ;
        RECT  139.916 76.8 140 76.824 ;
    END
  END vm_wdata[134]
  PIN vm_wdata[135]
    DIRECTION OUTPUT ;
    USE SIGNAL ;
    PORT
      LAYER M4 ;
        RECT  139.916 76.848 140 76.872 ;
    END
  END vm_wdata[135]
  PIN vm_wdata[136]
    DIRECTION OUTPUT ;
    USE SIGNAL ;
    PORT
      LAYER M4 ;
        RECT  139.916 76.896 140 76.92 ;
    END
  END vm_wdata[136]
  PIN vm_wdata[137]
    DIRECTION OUTPUT ;
    USE SIGNAL ;
    PORT
      LAYER M4 ;
        RECT  139.916 76.944 140 76.968 ;
    END
  END vm_wdata[137]
  PIN vm_wdata[138]
    DIRECTION OUTPUT ;
    USE SIGNAL ;
    PORT
      LAYER M4 ;
        RECT  139.916 76.992 140 77.016 ;
    END
  END vm_wdata[138]
  PIN vm_wdata[139]
    DIRECTION OUTPUT ;
    USE SIGNAL ;
    PORT
      LAYER M4 ;
        RECT  139.916 77.04 140 77.064 ;
    END
  END vm_wdata[139]
  PIN vm_wdata[13]
    DIRECTION OUTPUT ;
    USE SIGNAL ;
    PORT
      LAYER M4 ;
        RECT  139.916 70.992 140 71.016 ;
    END
  END vm_wdata[13]
  PIN vm_wdata[140]
    DIRECTION OUTPUT ;
    USE SIGNAL ;
    PORT
      LAYER M4 ;
        RECT  139.916 77.088 140 77.112 ;
    END
  END vm_wdata[140]
  PIN vm_wdata[141]
    DIRECTION OUTPUT ;
    USE SIGNAL ;
    PORT
      LAYER M4 ;
        RECT  139.916 77.136 140 77.16 ;
    END
  END vm_wdata[141]
  PIN vm_wdata[142]
    DIRECTION OUTPUT ;
    USE SIGNAL ;
    PORT
      LAYER M4 ;
        RECT  139.916 77.184 140 77.208 ;
    END
  END vm_wdata[142]
  PIN vm_wdata[143]
    DIRECTION OUTPUT ;
    USE SIGNAL ;
    PORT
      LAYER M4 ;
        RECT  139.916 77.232 140 77.256 ;
    END
  END vm_wdata[143]
  PIN vm_wdata[144]
    DIRECTION OUTPUT ;
    USE SIGNAL ;
    PORT
      LAYER M4 ;
        RECT  139.916 77.28 140 77.304 ;
    END
  END vm_wdata[144]
  PIN vm_wdata[145]
    DIRECTION OUTPUT ;
    USE SIGNAL ;
    PORT
      LAYER M4 ;
        RECT  139.916 77.328 140 77.352 ;
    END
  END vm_wdata[145]
  PIN vm_wdata[146]
    DIRECTION OUTPUT ;
    USE SIGNAL ;
    PORT
      LAYER M4 ;
        RECT  139.916 77.376 140 77.4 ;
    END
  END vm_wdata[146]
  PIN vm_wdata[147]
    DIRECTION OUTPUT ;
    USE SIGNAL ;
    PORT
      LAYER M4 ;
        RECT  139.916 77.424 140 77.448 ;
    END
  END vm_wdata[147]
  PIN vm_wdata[148]
    DIRECTION OUTPUT ;
    USE SIGNAL ;
    PORT
      LAYER M4 ;
        RECT  139.916 77.472 140 77.496 ;
    END
  END vm_wdata[148]
  PIN vm_wdata[149]
    DIRECTION OUTPUT ;
    USE SIGNAL ;
    PORT
      LAYER M4 ;
        RECT  139.916 77.52 140 77.544 ;
    END
  END vm_wdata[149]
  PIN vm_wdata[14]
    DIRECTION OUTPUT ;
    USE SIGNAL ;
    PORT
      LAYER M4 ;
        RECT  139.916 71.04 140 71.064 ;
    END
  END vm_wdata[14]
  PIN vm_wdata[150]
    DIRECTION OUTPUT ;
    USE SIGNAL ;
    PORT
      LAYER M4 ;
        RECT  139.916 77.568 140 77.592 ;
    END
  END vm_wdata[150]
  PIN vm_wdata[151]
    DIRECTION OUTPUT ;
    USE SIGNAL ;
    PORT
      LAYER M4 ;
        RECT  139.916 77.616 140 77.64 ;
    END
  END vm_wdata[151]
  PIN vm_wdata[152]
    DIRECTION OUTPUT ;
    USE SIGNAL ;
    PORT
      LAYER M4 ;
        RECT  139.916 77.664 140 77.688 ;
    END
  END vm_wdata[152]
  PIN vm_wdata[153]
    DIRECTION OUTPUT ;
    USE SIGNAL ;
    PORT
      LAYER M4 ;
        RECT  139.916 77.712 140 77.736 ;
    END
  END vm_wdata[153]
  PIN vm_wdata[154]
    DIRECTION OUTPUT ;
    USE SIGNAL ;
    PORT
      LAYER M4 ;
        RECT  139.916 77.76 140 77.784 ;
    END
  END vm_wdata[154]
  PIN vm_wdata[155]
    DIRECTION OUTPUT ;
    USE SIGNAL ;
    PORT
      LAYER M4 ;
        RECT  139.916 77.808 140 77.832 ;
    END
  END vm_wdata[155]
  PIN vm_wdata[156]
    DIRECTION OUTPUT ;
    USE SIGNAL ;
    PORT
      LAYER M4 ;
        RECT  139.916 77.856 140 77.88 ;
    END
  END vm_wdata[156]
  PIN vm_wdata[157]
    DIRECTION OUTPUT ;
    USE SIGNAL ;
    PORT
      LAYER M4 ;
        RECT  139.916 77.904 140 77.928 ;
    END
  END vm_wdata[157]
  PIN vm_wdata[158]
    DIRECTION OUTPUT ;
    USE SIGNAL ;
    PORT
      LAYER M4 ;
        RECT  139.916 77.952 140 77.976 ;
    END
  END vm_wdata[158]
  PIN vm_wdata[159]
    DIRECTION OUTPUT ;
    USE SIGNAL ;
    PORT
      LAYER M4 ;
        RECT  139.916 78 140 78.024 ;
    END
  END vm_wdata[159]
  PIN vm_wdata[15]
    DIRECTION OUTPUT ;
    USE SIGNAL ;
    PORT
      LAYER M4 ;
        RECT  139.916 71.088 140 71.112 ;
    END
  END vm_wdata[15]
  PIN vm_wdata[160]
    DIRECTION OUTPUT ;
    USE SIGNAL ;
    PORT
      LAYER M4 ;
        RECT  139.916 78.048 140 78.072 ;
    END
  END vm_wdata[160]
  PIN vm_wdata[161]
    DIRECTION OUTPUT ;
    USE SIGNAL ;
    PORT
      LAYER M4 ;
        RECT  139.916 78.096 140 78.12 ;
    END
  END vm_wdata[161]
  PIN vm_wdata[162]
    DIRECTION OUTPUT ;
    USE SIGNAL ;
    PORT
      LAYER M4 ;
        RECT  139.916 78.144 140 78.168 ;
    END
  END vm_wdata[162]
  PIN vm_wdata[163]
    DIRECTION OUTPUT ;
    USE SIGNAL ;
    PORT
      LAYER M4 ;
        RECT  139.916 78.192 140 78.216 ;
    END
  END vm_wdata[163]
  PIN vm_wdata[164]
    DIRECTION OUTPUT ;
    USE SIGNAL ;
    PORT
      LAYER M4 ;
        RECT  139.916 78.24 140 78.264 ;
    END
  END vm_wdata[164]
  PIN vm_wdata[165]
    DIRECTION OUTPUT ;
    USE SIGNAL ;
    PORT
      LAYER M4 ;
        RECT  139.916 78.288 140 78.312 ;
    END
  END vm_wdata[165]
  PIN vm_wdata[166]
    DIRECTION OUTPUT ;
    USE SIGNAL ;
    PORT
      LAYER M4 ;
        RECT  139.916 78.336 140 78.36 ;
    END
  END vm_wdata[166]
  PIN vm_wdata[167]
    DIRECTION OUTPUT ;
    USE SIGNAL ;
    PORT
      LAYER M4 ;
        RECT  139.916 78.384 140 78.408 ;
    END
  END vm_wdata[167]
  PIN vm_wdata[168]
    DIRECTION OUTPUT ;
    USE SIGNAL ;
    PORT
      LAYER M4 ;
        RECT  139.916 78.432 140 78.456 ;
    END
  END vm_wdata[168]
  PIN vm_wdata[169]
    DIRECTION OUTPUT ;
    USE SIGNAL ;
    PORT
      LAYER M4 ;
        RECT  139.916 78.48 140 78.504 ;
    END
  END vm_wdata[169]
  PIN vm_wdata[16]
    DIRECTION OUTPUT ;
    USE SIGNAL ;
    PORT
      LAYER M4 ;
        RECT  139.916 71.136 140 71.16 ;
    END
  END vm_wdata[16]
  PIN vm_wdata[170]
    DIRECTION OUTPUT ;
    USE SIGNAL ;
    PORT
      LAYER M4 ;
        RECT  139.916 78.528 140 78.552 ;
    END
  END vm_wdata[170]
  PIN vm_wdata[171]
    DIRECTION OUTPUT ;
    USE SIGNAL ;
    PORT
      LAYER M4 ;
        RECT  139.916 78.576 140 78.6 ;
    END
  END vm_wdata[171]
  PIN vm_wdata[172]
    DIRECTION OUTPUT ;
    USE SIGNAL ;
    PORT
      LAYER M4 ;
        RECT  139.916 78.624 140 78.648 ;
    END
  END vm_wdata[172]
  PIN vm_wdata[173]
    DIRECTION OUTPUT ;
    USE SIGNAL ;
    PORT
      LAYER M4 ;
        RECT  139.916 78.672 140 78.696 ;
    END
  END vm_wdata[173]
  PIN vm_wdata[174]
    DIRECTION OUTPUT ;
    USE SIGNAL ;
    PORT
      LAYER M4 ;
        RECT  139.916 78.72 140 78.744 ;
    END
  END vm_wdata[174]
  PIN vm_wdata[175]
    DIRECTION OUTPUT ;
    USE SIGNAL ;
    PORT
      LAYER M4 ;
        RECT  139.916 78.768 140 78.792 ;
    END
  END vm_wdata[175]
  PIN vm_wdata[176]
    DIRECTION OUTPUT ;
    USE SIGNAL ;
    PORT
      LAYER M4 ;
        RECT  139.916 78.816 140 78.84 ;
    END
  END vm_wdata[176]
  PIN vm_wdata[177]
    DIRECTION OUTPUT ;
    USE SIGNAL ;
    PORT
      LAYER M4 ;
        RECT  139.916 78.864 140 78.888 ;
    END
  END vm_wdata[177]
  PIN vm_wdata[178]
    DIRECTION OUTPUT ;
    USE SIGNAL ;
    PORT
      LAYER M4 ;
        RECT  139.916 78.912 140 78.936 ;
    END
  END vm_wdata[178]
  PIN vm_wdata[179]
    DIRECTION OUTPUT ;
    USE SIGNAL ;
    PORT
      LAYER M4 ;
        RECT  139.916 78.96 140 78.984 ;
    END
  END vm_wdata[179]
  PIN vm_wdata[17]
    DIRECTION OUTPUT ;
    USE SIGNAL ;
    PORT
      LAYER M4 ;
        RECT  139.916 71.184 140 71.208 ;
    END
  END vm_wdata[17]
  PIN vm_wdata[180]
    DIRECTION OUTPUT ;
    USE SIGNAL ;
    PORT
      LAYER M4 ;
        RECT  139.916 79.008 140 79.032 ;
    END
  END vm_wdata[180]
  PIN vm_wdata[181]
    DIRECTION OUTPUT ;
    USE SIGNAL ;
    PORT
      LAYER M4 ;
        RECT  139.916 79.056 140 79.08 ;
    END
  END vm_wdata[181]
  PIN vm_wdata[182]
    DIRECTION OUTPUT ;
    USE SIGNAL ;
    PORT
      LAYER M4 ;
        RECT  139.916 79.104 140 79.128 ;
    END
  END vm_wdata[182]
  PIN vm_wdata[183]
    DIRECTION OUTPUT ;
    USE SIGNAL ;
    PORT
      LAYER M4 ;
        RECT  139.916 79.152 140 79.176 ;
    END
  END vm_wdata[183]
  PIN vm_wdata[184]
    DIRECTION OUTPUT ;
    USE SIGNAL ;
    PORT
      LAYER M4 ;
        RECT  139.916 79.2 140 79.224 ;
    END
  END vm_wdata[184]
  PIN vm_wdata[185]
    DIRECTION OUTPUT ;
    USE SIGNAL ;
    PORT
      LAYER M4 ;
        RECT  139.916 79.248 140 79.272 ;
    END
  END vm_wdata[185]
  PIN vm_wdata[186]
    DIRECTION OUTPUT ;
    USE SIGNAL ;
    PORT
      LAYER M4 ;
        RECT  139.916 79.296 140 79.32 ;
    END
  END vm_wdata[186]
  PIN vm_wdata[187]
    DIRECTION OUTPUT ;
    USE SIGNAL ;
    PORT
      LAYER M4 ;
        RECT  139.916 79.344 140 79.368 ;
    END
  END vm_wdata[187]
  PIN vm_wdata[188]
    DIRECTION OUTPUT ;
    USE SIGNAL ;
    PORT
      LAYER M4 ;
        RECT  139.916 79.392 140 79.416 ;
    END
  END vm_wdata[188]
  PIN vm_wdata[189]
    DIRECTION OUTPUT ;
    USE SIGNAL ;
    PORT
      LAYER M4 ;
        RECT  139.916 79.44 140 79.464 ;
    END
  END vm_wdata[189]
  PIN vm_wdata[18]
    DIRECTION OUTPUT ;
    USE SIGNAL ;
    PORT
      LAYER M4 ;
        RECT  139.916 71.232 140 71.256 ;
    END
  END vm_wdata[18]
  PIN vm_wdata[190]
    DIRECTION OUTPUT ;
    USE SIGNAL ;
    PORT
      LAYER M4 ;
        RECT  139.916 79.488 140 79.512 ;
    END
  END vm_wdata[190]
  PIN vm_wdata[191]
    DIRECTION OUTPUT ;
    USE SIGNAL ;
    PORT
      LAYER M4 ;
        RECT  139.916 79.536 140 79.56 ;
    END
  END vm_wdata[191]
  PIN vm_wdata[192]
    DIRECTION OUTPUT ;
    USE SIGNAL ;
    PORT
      LAYER M4 ;
        RECT  139.916 79.584 140 79.608 ;
    END
  END vm_wdata[192]
  PIN vm_wdata[193]
    DIRECTION OUTPUT ;
    USE SIGNAL ;
    PORT
      LAYER M4 ;
        RECT  139.916 79.632 140 79.656 ;
    END
  END vm_wdata[193]
  PIN vm_wdata[194]
    DIRECTION OUTPUT ;
    USE SIGNAL ;
    PORT
      LAYER M4 ;
        RECT  139.916 79.68 140 79.704 ;
    END
  END vm_wdata[194]
  PIN vm_wdata[195]
    DIRECTION OUTPUT ;
    USE SIGNAL ;
    PORT
      LAYER M4 ;
        RECT  139.916 79.728 140 79.752 ;
    END
  END vm_wdata[195]
  PIN vm_wdata[196]
    DIRECTION OUTPUT ;
    USE SIGNAL ;
    PORT
      LAYER M4 ;
        RECT  139.916 79.776 140 79.8 ;
    END
  END vm_wdata[196]
  PIN vm_wdata[197]
    DIRECTION OUTPUT ;
    USE SIGNAL ;
    PORT
      LAYER M4 ;
        RECT  139.916 79.824 140 79.848 ;
    END
  END vm_wdata[197]
  PIN vm_wdata[198]
    DIRECTION OUTPUT ;
    USE SIGNAL ;
    PORT
      LAYER M4 ;
        RECT  139.916 79.872 140 79.896 ;
    END
  END vm_wdata[198]
  PIN vm_wdata[199]
    DIRECTION OUTPUT ;
    USE SIGNAL ;
    PORT
      LAYER M4 ;
        RECT  139.916 79.92 140 79.944 ;
    END
  END vm_wdata[199]
  PIN vm_wdata[19]
    DIRECTION OUTPUT ;
    USE SIGNAL ;
    PORT
      LAYER M4 ;
        RECT  139.916 71.28 140 71.304 ;
    END
  END vm_wdata[19]
  PIN vm_wdata[1]
    DIRECTION OUTPUT ;
    USE SIGNAL ;
    PORT
      LAYER M4 ;
        RECT  139.916 70.416 140 70.44 ;
    END
  END vm_wdata[1]
  PIN vm_wdata[200]
    DIRECTION OUTPUT ;
    USE SIGNAL ;
    PORT
      LAYER M4 ;
        RECT  139.916 79.968 140 79.992 ;
    END
  END vm_wdata[200]
  PIN vm_wdata[201]
    DIRECTION OUTPUT ;
    USE SIGNAL ;
    PORT
      LAYER M4 ;
        RECT  139.916 80.016 140 80.04 ;
    END
  END vm_wdata[201]
  PIN vm_wdata[202]
    DIRECTION OUTPUT ;
    USE SIGNAL ;
    PORT
      LAYER M4 ;
        RECT  139.916 80.064 140 80.088 ;
    END
  END vm_wdata[202]
  PIN vm_wdata[203]
    DIRECTION OUTPUT ;
    USE SIGNAL ;
    PORT
      LAYER M4 ;
        RECT  139.916 80.112 140 80.136 ;
    END
  END vm_wdata[203]
  PIN vm_wdata[204]
    DIRECTION OUTPUT ;
    USE SIGNAL ;
    PORT
      LAYER M4 ;
        RECT  139.916 80.16 140 80.184 ;
    END
  END vm_wdata[204]
  PIN vm_wdata[205]
    DIRECTION OUTPUT ;
    USE SIGNAL ;
    PORT
      LAYER M4 ;
        RECT  139.916 80.208 140 80.232 ;
    END
  END vm_wdata[205]
  PIN vm_wdata[206]
    DIRECTION OUTPUT ;
    USE SIGNAL ;
    PORT
      LAYER M4 ;
        RECT  139.916 80.256 140 80.28 ;
    END
  END vm_wdata[206]
  PIN vm_wdata[207]
    DIRECTION OUTPUT ;
    USE SIGNAL ;
    PORT
      LAYER M4 ;
        RECT  139.916 80.304 140 80.328 ;
    END
  END vm_wdata[207]
  PIN vm_wdata[208]
    DIRECTION OUTPUT ;
    USE SIGNAL ;
    PORT
      LAYER M4 ;
        RECT  139.916 80.352 140 80.376 ;
    END
  END vm_wdata[208]
  PIN vm_wdata[209]
    DIRECTION OUTPUT ;
    USE SIGNAL ;
    PORT
      LAYER M4 ;
        RECT  139.916 80.4 140 80.424 ;
    END
  END vm_wdata[209]
  PIN vm_wdata[20]
    DIRECTION OUTPUT ;
    USE SIGNAL ;
    PORT
      LAYER M4 ;
        RECT  139.916 71.328 140 71.352 ;
    END
  END vm_wdata[20]
  PIN vm_wdata[210]
    DIRECTION OUTPUT ;
    USE SIGNAL ;
    PORT
      LAYER M4 ;
        RECT  139.916 80.448 140 80.472 ;
    END
  END vm_wdata[210]
  PIN vm_wdata[211]
    DIRECTION OUTPUT ;
    USE SIGNAL ;
    PORT
      LAYER M4 ;
        RECT  139.916 80.496 140 80.52 ;
    END
  END vm_wdata[211]
  PIN vm_wdata[212]
    DIRECTION OUTPUT ;
    USE SIGNAL ;
    PORT
      LAYER M4 ;
        RECT  139.916 80.544 140 80.568 ;
    END
  END vm_wdata[212]
  PIN vm_wdata[213]
    DIRECTION OUTPUT ;
    USE SIGNAL ;
    PORT
      LAYER M4 ;
        RECT  139.916 80.592 140 80.616 ;
    END
  END vm_wdata[213]
  PIN vm_wdata[214]
    DIRECTION OUTPUT ;
    USE SIGNAL ;
    PORT
      LAYER M4 ;
        RECT  139.916 80.64 140 80.664 ;
    END
  END vm_wdata[214]
  PIN vm_wdata[215]
    DIRECTION OUTPUT ;
    USE SIGNAL ;
    PORT
      LAYER M4 ;
        RECT  139.916 80.688 140 80.712 ;
    END
  END vm_wdata[215]
  PIN vm_wdata[216]
    DIRECTION OUTPUT ;
    USE SIGNAL ;
    PORT
      LAYER M4 ;
        RECT  139.916 80.736 140 80.76 ;
    END
  END vm_wdata[216]
  PIN vm_wdata[217]
    DIRECTION OUTPUT ;
    USE SIGNAL ;
    PORT
      LAYER M4 ;
        RECT  139.916 80.784 140 80.808 ;
    END
  END vm_wdata[217]
  PIN vm_wdata[218]
    DIRECTION OUTPUT ;
    USE SIGNAL ;
    PORT
      LAYER M4 ;
        RECT  139.916 80.832 140 80.856 ;
    END
  END vm_wdata[218]
  PIN vm_wdata[219]
    DIRECTION OUTPUT ;
    USE SIGNAL ;
    PORT
      LAYER M4 ;
        RECT  139.916 80.88 140 80.904 ;
    END
  END vm_wdata[219]
  PIN vm_wdata[21]
    DIRECTION OUTPUT ;
    USE SIGNAL ;
    PORT
      LAYER M4 ;
        RECT  139.916 71.376 140 71.4 ;
    END
  END vm_wdata[21]
  PIN vm_wdata[220]
    DIRECTION OUTPUT ;
    USE SIGNAL ;
    PORT
      LAYER M4 ;
        RECT  139.916 80.928 140 80.952 ;
    END
  END vm_wdata[220]
  PIN vm_wdata[221]
    DIRECTION OUTPUT ;
    USE SIGNAL ;
    PORT
      LAYER M4 ;
        RECT  139.916 80.976 140 81 ;
    END
  END vm_wdata[221]
  PIN vm_wdata[222]
    DIRECTION OUTPUT ;
    USE SIGNAL ;
    PORT
      LAYER M4 ;
        RECT  139.916 81.024 140 81.048 ;
    END
  END vm_wdata[222]
  PIN vm_wdata[223]
    DIRECTION OUTPUT ;
    USE SIGNAL ;
    PORT
      LAYER M4 ;
        RECT  139.916 81.072 140 81.096 ;
    END
  END vm_wdata[223]
  PIN vm_wdata[224]
    DIRECTION OUTPUT ;
    USE SIGNAL ;
    PORT
      LAYER M4 ;
        RECT  139.916 81.12 140 81.144 ;
    END
  END vm_wdata[224]
  PIN vm_wdata[225]
    DIRECTION OUTPUT ;
    USE SIGNAL ;
    PORT
      LAYER M4 ;
        RECT  139.916 81.168 140 81.192 ;
    END
  END vm_wdata[225]
  PIN vm_wdata[226]
    DIRECTION OUTPUT ;
    USE SIGNAL ;
    PORT
      LAYER M4 ;
        RECT  139.916 81.216 140 81.24 ;
    END
  END vm_wdata[226]
  PIN vm_wdata[227]
    DIRECTION OUTPUT ;
    USE SIGNAL ;
    PORT
      LAYER M4 ;
        RECT  139.916 81.264 140 81.288 ;
    END
  END vm_wdata[227]
  PIN vm_wdata[228]
    DIRECTION OUTPUT ;
    USE SIGNAL ;
    PORT
      LAYER M4 ;
        RECT  139.916 81.312 140 81.336 ;
    END
  END vm_wdata[228]
  PIN vm_wdata[229]
    DIRECTION OUTPUT ;
    USE SIGNAL ;
    PORT
      LAYER M4 ;
        RECT  139.916 81.36 140 81.384 ;
    END
  END vm_wdata[229]
  PIN vm_wdata[22]
    DIRECTION OUTPUT ;
    USE SIGNAL ;
    PORT
      LAYER M4 ;
        RECT  139.916 71.424 140 71.448 ;
    END
  END vm_wdata[22]
  PIN vm_wdata[230]
    DIRECTION OUTPUT ;
    USE SIGNAL ;
    PORT
      LAYER M4 ;
        RECT  139.916 81.408 140 81.432 ;
    END
  END vm_wdata[230]
  PIN vm_wdata[231]
    DIRECTION OUTPUT ;
    USE SIGNAL ;
    PORT
      LAYER M4 ;
        RECT  139.916 81.456 140 81.48 ;
    END
  END vm_wdata[231]
  PIN vm_wdata[232]
    DIRECTION OUTPUT ;
    USE SIGNAL ;
    PORT
      LAYER M4 ;
        RECT  139.916 81.504 140 81.528 ;
    END
  END vm_wdata[232]
  PIN vm_wdata[233]
    DIRECTION OUTPUT ;
    USE SIGNAL ;
    PORT
      LAYER M4 ;
        RECT  139.916 81.552 140 81.576 ;
    END
  END vm_wdata[233]
  PIN vm_wdata[234]
    DIRECTION OUTPUT ;
    USE SIGNAL ;
    PORT
      LAYER M4 ;
        RECT  139.916 81.6 140 81.624 ;
    END
  END vm_wdata[234]
  PIN vm_wdata[235]
    DIRECTION OUTPUT ;
    USE SIGNAL ;
    PORT
      LAYER M4 ;
        RECT  139.916 81.648 140 81.672 ;
    END
  END vm_wdata[235]
  PIN vm_wdata[236]
    DIRECTION OUTPUT ;
    USE SIGNAL ;
    PORT
      LAYER M4 ;
        RECT  139.916 81.696 140 81.72 ;
    END
  END vm_wdata[236]
  PIN vm_wdata[237]
    DIRECTION OUTPUT ;
    USE SIGNAL ;
    PORT
      LAYER M4 ;
        RECT  139.916 81.744 140 81.768 ;
    END
  END vm_wdata[237]
  PIN vm_wdata[238]
    DIRECTION OUTPUT ;
    USE SIGNAL ;
    PORT
      LAYER M4 ;
        RECT  139.916 81.792 140 81.816 ;
    END
  END vm_wdata[238]
  PIN vm_wdata[239]
    DIRECTION OUTPUT ;
    USE SIGNAL ;
    PORT
      LAYER M4 ;
        RECT  139.916 81.84 140 81.864 ;
    END
  END vm_wdata[239]
  PIN vm_wdata[23]
    DIRECTION OUTPUT ;
    USE SIGNAL ;
    PORT
      LAYER M4 ;
        RECT  139.916 71.472 140 71.496 ;
    END
  END vm_wdata[23]
  PIN vm_wdata[240]
    DIRECTION OUTPUT ;
    USE SIGNAL ;
    PORT
      LAYER M4 ;
        RECT  139.916 81.888 140 81.912 ;
    END
  END vm_wdata[240]
  PIN vm_wdata[241]
    DIRECTION OUTPUT ;
    USE SIGNAL ;
    PORT
      LAYER M4 ;
        RECT  139.916 81.936 140 81.96 ;
    END
  END vm_wdata[241]
  PIN vm_wdata[242]
    DIRECTION OUTPUT ;
    USE SIGNAL ;
    PORT
      LAYER M4 ;
        RECT  139.916 81.984 140 82.008 ;
    END
  END vm_wdata[242]
  PIN vm_wdata[243]
    DIRECTION OUTPUT ;
    USE SIGNAL ;
    PORT
      LAYER M4 ;
        RECT  139.916 82.032 140 82.056 ;
    END
  END vm_wdata[243]
  PIN vm_wdata[244]
    DIRECTION OUTPUT ;
    USE SIGNAL ;
    PORT
      LAYER M4 ;
        RECT  139.916 82.08 140 82.104 ;
    END
  END vm_wdata[244]
  PIN vm_wdata[245]
    DIRECTION OUTPUT ;
    USE SIGNAL ;
    PORT
      LAYER M4 ;
        RECT  139.916 82.128 140 82.152 ;
    END
  END vm_wdata[245]
  PIN vm_wdata[246]
    DIRECTION OUTPUT ;
    USE SIGNAL ;
    PORT
      LAYER M4 ;
        RECT  139.916 82.176 140 82.2 ;
    END
  END vm_wdata[246]
  PIN vm_wdata[247]
    DIRECTION OUTPUT ;
    USE SIGNAL ;
    PORT
      LAYER M4 ;
        RECT  139.916 82.224 140 82.248 ;
    END
  END vm_wdata[247]
  PIN vm_wdata[248]
    DIRECTION OUTPUT ;
    USE SIGNAL ;
    PORT
      LAYER M4 ;
        RECT  139.916 82.272 140 82.296 ;
    END
  END vm_wdata[248]
  PIN vm_wdata[249]
    DIRECTION OUTPUT ;
    USE SIGNAL ;
    PORT
      LAYER M4 ;
        RECT  139.916 82.32 140 82.344 ;
    END
  END vm_wdata[249]
  PIN vm_wdata[24]
    DIRECTION OUTPUT ;
    USE SIGNAL ;
    PORT
      LAYER M4 ;
        RECT  139.916 71.52 140 71.544 ;
    END
  END vm_wdata[24]
  PIN vm_wdata[250]
    DIRECTION OUTPUT ;
    USE SIGNAL ;
    PORT
      LAYER M4 ;
        RECT  139.916 82.368 140 82.392 ;
    END
  END vm_wdata[250]
  PIN vm_wdata[251]
    DIRECTION OUTPUT ;
    USE SIGNAL ;
    PORT
      LAYER M4 ;
        RECT  139.916 82.416 140 82.44 ;
    END
  END vm_wdata[251]
  PIN vm_wdata[252]
    DIRECTION OUTPUT ;
    USE SIGNAL ;
    PORT
      LAYER M4 ;
        RECT  139.916 82.464 140 82.488 ;
    END
  END vm_wdata[252]
  PIN vm_wdata[253]
    DIRECTION OUTPUT ;
    USE SIGNAL ;
    PORT
      LAYER M4 ;
        RECT  139.916 82.512 140 82.536 ;
    END
  END vm_wdata[253]
  PIN vm_wdata[254]
    DIRECTION OUTPUT ;
    USE SIGNAL ;
    PORT
      LAYER M4 ;
        RECT  139.916 82.56 140 82.584 ;
    END
  END vm_wdata[254]
  PIN vm_wdata[255]
    DIRECTION OUTPUT ;
    USE SIGNAL ;
    PORT
      LAYER M4 ;
        RECT  139.916 82.608 140 82.632 ;
    END
  END vm_wdata[255]
  PIN vm_wdata[256]
    DIRECTION OUTPUT ;
    USE SIGNAL ;
    PORT
      LAYER M4 ;
        RECT  139.916 82.656 140 82.68 ;
    END
  END vm_wdata[256]
  PIN vm_wdata[257]
    DIRECTION OUTPUT ;
    USE SIGNAL ;
    PORT
      LAYER M4 ;
        RECT  139.916 82.704 140 82.728 ;
    END
  END vm_wdata[257]
  PIN vm_wdata[258]
    DIRECTION OUTPUT ;
    USE SIGNAL ;
    PORT
      LAYER M4 ;
        RECT  139.916 82.752 140 82.776 ;
    END
  END vm_wdata[258]
  PIN vm_wdata[259]
    DIRECTION OUTPUT ;
    USE SIGNAL ;
    PORT
      LAYER M4 ;
        RECT  139.916 82.8 140 82.824 ;
    END
  END vm_wdata[259]
  PIN vm_wdata[25]
    DIRECTION OUTPUT ;
    USE SIGNAL ;
    PORT
      LAYER M4 ;
        RECT  139.916 71.568 140 71.592 ;
    END
  END vm_wdata[25]
  PIN vm_wdata[260]
    DIRECTION OUTPUT ;
    USE SIGNAL ;
    PORT
      LAYER M4 ;
        RECT  139.916 82.848 140 82.872 ;
    END
  END vm_wdata[260]
  PIN vm_wdata[261]
    DIRECTION OUTPUT ;
    USE SIGNAL ;
    PORT
      LAYER M4 ;
        RECT  139.916 82.896 140 82.92 ;
    END
  END vm_wdata[261]
  PIN vm_wdata[262]
    DIRECTION OUTPUT ;
    USE SIGNAL ;
    PORT
      LAYER M4 ;
        RECT  139.916 82.944 140 82.968 ;
    END
  END vm_wdata[262]
  PIN vm_wdata[263]
    DIRECTION OUTPUT ;
    USE SIGNAL ;
    PORT
      LAYER M4 ;
        RECT  139.916 82.992 140 83.016 ;
    END
  END vm_wdata[263]
  PIN vm_wdata[264]
    DIRECTION OUTPUT ;
    USE SIGNAL ;
    PORT
      LAYER M4 ;
        RECT  139.916 83.04 140 83.064 ;
    END
  END vm_wdata[264]
  PIN vm_wdata[265]
    DIRECTION OUTPUT ;
    USE SIGNAL ;
    PORT
      LAYER M4 ;
        RECT  139.916 83.088 140 83.112 ;
    END
  END vm_wdata[265]
  PIN vm_wdata[266]
    DIRECTION OUTPUT ;
    USE SIGNAL ;
    PORT
      LAYER M4 ;
        RECT  139.916 83.136 140 83.16 ;
    END
  END vm_wdata[266]
  PIN vm_wdata[267]
    DIRECTION OUTPUT ;
    USE SIGNAL ;
    PORT
      LAYER M4 ;
        RECT  139.916 83.184 140 83.208 ;
    END
  END vm_wdata[267]
  PIN vm_wdata[268]
    DIRECTION OUTPUT ;
    USE SIGNAL ;
    PORT
      LAYER M4 ;
        RECT  139.916 83.232 140 83.256 ;
    END
  END vm_wdata[268]
  PIN vm_wdata[269]
    DIRECTION OUTPUT ;
    USE SIGNAL ;
    PORT
      LAYER M4 ;
        RECT  139.916 83.28 140 83.304 ;
    END
  END vm_wdata[269]
  PIN vm_wdata[26]
    DIRECTION OUTPUT ;
    USE SIGNAL ;
    PORT
      LAYER M4 ;
        RECT  139.916 71.616 140 71.64 ;
    END
  END vm_wdata[26]
  PIN vm_wdata[270]
    DIRECTION OUTPUT ;
    USE SIGNAL ;
    PORT
      LAYER M4 ;
        RECT  139.916 83.328 140 83.352 ;
    END
  END vm_wdata[270]
  PIN vm_wdata[271]
    DIRECTION OUTPUT ;
    USE SIGNAL ;
    PORT
      LAYER M4 ;
        RECT  139.916 83.376 140 83.4 ;
    END
  END vm_wdata[271]
  PIN vm_wdata[272]
    DIRECTION OUTPUT ;
    USE SIGNAL ;
    PORT
      LAYER M4 ;
        RECT  139.916 83.424 140 83.448 ;
    END
  END vm_wdata[272]
  PIN vm_wdata[273]
    DIRECTION OUTPUT ;
    USE SIGNAL ;
    PORT
      LAYER M4 ;
        RECT  139.916 83.472 140 83.496 ;
    END
  END vm_wdata[273]
  PIN vm_wdata[274]
    DIRECTION OUTPUT ;
    USE SIGNAL ;
    PORT
      LAYER M4 ;
        RECT  139.916 83.52 140 83.544 ;
    END
  END vm_wdata[274]
  PIN vm_wdata[275]
    DIRECTION OUTPUT ;
    USE SIGNAL ;
    PORT
      LAYER M4 ;
        RECT  139.916 83.568 140 83.592 ;
    END
  END vm_wdata[275]
  PIN vm_wdata[276]
    DIRECTION OUTPUT ;
    USE SIGNAL ;
    PORT
      LAYER M4 ;
        RECT  139.916 83.616 140 83.64 ;
    END
  END vm_wdata[276]
  PIN vm_wdata[277]
    DIRECTION OUTPUT ;
    USE SIGNAL ;
    PORT
      LAYER M4 ;
        RECT  139.916 83.664 140 83.688 ;
    END
  END vm_wdata[277]
  PIN vm_wdata[278]
    DIRECTION OUTPUT ;
    USE SIGNAL ;
    PORT
      LAYER M4 ;
        RECT  139.916 83.712 140 83.736 ;
    END
  END vm_wdata[278]
  PIN vm_wdata[279]
    DIRECTION OUTPUT ;
    USE SIGNAL ;
    PORT
      LAYER M4 ;
        RECT  139.916 83.76 140 83.784 ;
    END
  END vm_wdata[279]
  PIN vm_wdata[27]
    DIRECTION OUTPUT ;
    USE SIGNAL ;
    PORT
      LAYER M4 ;
        RECT  139.916 71.664 140 71.688 ;
    END
  END vm_wdata[27]
  PIN vm_wdata[280]
    DIRECTION OUTPUT ;
    USE SIGNAL ;
    PORT
      LAYER M4 ;
        RECT  139.916 83.808 140 83.832 ;
    END
  END vm_wdata[280]
  PIN vm_wdata[281]
    DIRECTION OUTPUT ;
    USE SIGNAL ;
    PORT
      LAYER M4 ;
        RECT  139.916 83.856 140 83.88 ;
    END
  END vm_wdata[281]
  PIN vm_wdata[282]
    DIRECTION OUTPUT ;
    USE SIGNAL ;
    PORT
      LAYER M4 ;
        RECT  139.916 83.904 140 83.928 ;
    END
  END vm_wdata[282]
  PIN vm_wdata[283]
    DIRECTION OUTPUT ;
    USE SIGNAL ;
    PORT
      LAYER M4 ;
        RECT  139.916 83.952 140 83.976 ;
    END
  END vm_wdata[283]
  PIN vm_wdata[284]
    DIRECTION OUTPUT ;
    USE SIGNAL ;
    PORT
      LAYER M4 ;
        RECT  139.916 84 140 84.024 ;
    END
  END vm_wdata[284]
  PIN vm_wdata[285]
    DIRECTION OUTPUT ;
    USE SIGNAL ;
    PORT
      LAYER M4 ;
        RECT  139.916 84.048 140 84.072 ;
    END
  END vm_wdata[285]
  PIN vm_wdata[286]
    DIRECTION OUTPUT ;
    USE SIGNAL ;
    PORT
      LAYER M4 ;
        RECT  139.916 84.096 140 84.12 ;
    END
  END vm_wdata[286]
  PIN vm_wdata[287]
    DIRECTION OUTPUT ;
    USE SIGNAL ;
    PORT
      LAYER M4 ;
        RECT  139.916 84.144 140 84.168 ;
    END
  END vm_wdata[287]
  PIN vm_wdata[288]
    DIRECTION OUTPUT ;
    USE SIGNAL ;
    PORT
      LAYER M4 ;
        RECT  139.916 84.192 140 84.216 ;
    END
  END vm_wdata[288]
  PIN vm_wdata[289]
    DIRECTION OUTPUT ;
    USE SIGNAL ;
    PORT
      LAYER M4 ;
        RECT  139.916 84.24 140 84.264 ;
    END
  END vm_wdata[289]
  PIN vm_wdata[28]
    DIRECTION OUTPUT ;
    USE SIGNAL ;
    PORT
      LAYER M4 ;
        RECT  139.916 71.712 140 71.736 ;
    END
  END vm_wdata[28]
  PIN vm_wdata[290]
    DIRECTION OUTPUT ;
    USE SIGNAL ;
    PORT
      LAYER M4 ;
        RECT  139.916 84.288 140 84.312 ;
    END
  END vm_wdata[290]
  PIN vm_wdata[291]
    DIRECTION OUTPUT ;
    USE SIGNAL ;
    PORT
      LAYER M4 ;
        RECT  139.916 84.336 140 84.36 ;
    END
  END vm_wdata[291]
  PIN vm_wdata[292]
    DIRECTION OUTPUT ;
    USE SIGNAL ;
    PORT
      LAYER M4 ;
        RECT  139.916 84.384 140 84.408 ;
    END
  END vm_wdata[292]
  PIN vm_wdata[293]
    DIRECTION OUTPUT ;
    USE SIGNAL ;
    PORT
      LAYER M4 ;
        RECT  139.916 84.432 140 84.456 ;
    END
  END vm_wdata[293]
  PIN vm_wdata[294]
    DIRECTION OUTPUT ;
    USE SIGNAL ;
    PORT
      LAYER M4 ;
        RECT  139.916 84.48 140 84.504 ;
    END
  END vm_wdata[294]
  PIN vm_wdata[295]
    DIRECTION OUTPUT ;
    USE SIGNAL ;
    PORT
      LAYER M4 ;
        RECT  139.916 84.528 140 84.552 ;
    END
  END vm_wdata[295]
  PIN vm_wdata[296]
    DIRECTION OUTPUT ;
    USE SIGNAL ;
    PORT
      LAYER M4 ;
        RECT  139.916 84.576 140 84.6 ;
    END
  END vm_wdata[296]
  PIN vm_wdata[297]
    DIRECTION OUTPUT ;
    USE SIGNAL ;
    PORT
      LAYER M4 ;
        RECT  139.916 84.624 140 84.648 ;
    END
  END vm_wdata[297]
  PIN vm_wdata[298]
    DIRECTION OUTPUT ;
    USE SIGNAL ;
    PORT
      LAYER M4 ;
        RECT  139.916 84.672 140 84.696 ;
    END
  END vm_wdata[298]
  PIN vm_wdata[299]
    DIRECTION OUTPUT ;
    USE SIGNAL ;
    PORT
      LAYER M4 ;
        RECT  139.916 84.72 140 84.744 ;
    END
  END vm_wdata[299]
  PIN vm_wdata[29]
    DIRECTION OUTPUT ;
    USE SIGNAL ;
    PORT
      LAYER M4 ;
        RECT  139.916 71.76 140 71.784 ;
    END
  END vm_wdata[29]
  PIN vm_wdata[2]
    DIRECTION OUTPUT ;
    USE SIGNAL ;
    PORT
      LAYER M4 ;
        RECT  139.916 70.464 140 70.488 ;
    END
  END vm_wdata[2]
  PIN vm_wdata[300]
    DIRECTION OUTPUT ;
    USE SIGNAL ;
    PORT
      LAYER M4 ;
        RECT  139.916 84.768 140 84.792 ;
    END
  END vm_wdata[300]
  PIN vm_wdata[301]
    DIRECTION OUTPUT ;
    USE SIGNAL ;
    PORT
      LAYER M4 ;
        RECT  139.916 84.816 140 84.84 ;
    END
  END vm_wdata[301]
  PIN vm_wdata[302]
    DIRECTION OUTPUT ;
    USE SIGNAL ;
    PORT
      LAYER M4 ;
        RECT  139.916 84.864 140 84.888 ;
    END
  END vm_wdata[302]
  PIN vm_wdata[303]
    DIRECTION OUTPUT ;
    USE SIGNAL ;
    PORT
      LAYER M4 ;
        RECT  139.916 84.912 140 84.936 ;
    END
  END vm_wdata[303]
  PIN vm_wdata[304]
    DIRECTION OUTPUT ;
    USE SIGNAL ;
    PORT
      LAYER M4 ;
        RECT  139.916 84.96 140 84.984 ;
    END
  END vm_wdata[304]
  PIN vm_wdata[305]
    DIRECTION OUTPUT ;
    USE SIGNAL ;
    PORT
      LAYER M4 ;
        RECT  139.916 85.008 140 85.032 ;
    END
  END vm_wdata[305]
  PIN vm_wdata[306]
    DIRECTION OUTPUT ;
    USE SIGNAL ;
    PORT
      LAYER M4 ;
        RECT  139.916 85.056 140 85.08 ;
    END
  END vm_wdata[306]
  PIN vm_wdata[307]
    DIRECTION OUTPUT ;
    USE SIGNAL ;
    PORT
      LAYER M4 ;
        RECT  139.916 85.104 140 85.128 ;
    END
  END vm_wdata[307]
  PIN vm_wdata[308]
    DIRECTION OUTPUT ;
    USE SIGNAL ;
    PORT
      LAYER M4 ;
        RECT  139.916 85.152 140 85.176 ;
    END
  END vm_wdata[308]
  PIN vm_wdata[309]
    DIRECTION OUTPUT ;
    USE SIGNAL ;
    PORT
      LAYER M4 ;
        RECT  139.916 85.2 140 85.224 ;
    END
  END vm_wdata[309]
  PIN vm_wdata[30]
    DIRECTION OUTPUT ;
    USE SIGNAL ;
    PORT
      LAYER M4 ;
        RECT  139.916 71.808 140 71.832 ;
    END
  END vm_wdata[30]
  PIN vm_wdata[310]
    DIRECTION OUTPUT ;
    USE SIGNAL ;
    PORT
      LAYER M4 ;
        RECT  139.916 85.248 140 85.272 ;
    END
  END vm_wdata[310]
  PIN vm_wdata[311]
    DIRECTION OUTPUT ;
    USE SIGNAL ;
    PORT
      LAYER M4 ;
        RECT  139.916 85.296 140 85.32 ;
    END
  END vm_wdata[311]
  PIN vm_wdata[312]
    DIRECTION OUTPUT ;
    USE SIGNAL ;
    PORT
      LAYER M4 ;
        RECT  139.916 85.344 140 85.368 ;
    END
  END vm_wdata[312]
  PIN vm_wdata[313]
    DIRECTION OUTPUT ;
    USE SIGNAL ;
    PORT
      LAYER M4 ;
        RECT  139.916 85.392 140 85.416 ;
    END
  END vm_wdata[313]
  PIN vm_wdata[314]
    DIRECTION OUTPUT ;
    USE SIGNAL ;
    PORT
      LAYER M4 ;
        RECT  139.916 85.44 140 85.464 ;
    END
  END vm_wdata[314]
  PIN vm_wdata[315]
    DIRECTION OUTPUT ;
    USE SIGNAL ;
    PORT
      LAYER M4 ;
        RECT  139.916 85.488 140 85.512 ;
    END
  END vm_wdata[315]
  PIN vm_wdata[316]
    DIRECTION OUTPUT ;
    USE SIGNAL ;
    PORT
      LAYER M4 ;
        RECT  139.916 85.536 140 85.56 ;
    END
  END vm_wdata[316]
  PIN vm_wdata[317]
    DIRECTION OUTPUT ;
    USE SIGNAL ;
    PORT
      LAYER M4 ;
        RECT  139.916 85.584 140 85.608 ;
    END
  END vm_wdata[317]
  PIN vm_wdata[318]
    DIRECTION OUTPUT ;
    USE SIGNAL ;
    PORT
      LAYER M4 ;
        RECT  139.916 85.632 140 85.656 ;
    END
  END vm_wdata[318]
  PIN vm_wdata[319]
    DIRECTION OUTPUT ;
    USE SIGNAL ;
    PORT
      LAYER M4 ;
        RECT  139.916 85.68 140 85.704 ;
    END
  END vm_wdata[319]
  PIN vm_wdata[31]
    DIRECTION OUTPUT ;
    USE SIGNAL ;
    PORT
      LAYER M4 ;
        RECT  139.916 71.856 140 71.88 ;
    END
  END vm_wdata[31]
  PIN vm_wdata[320]
    DIRECTION OUTPUT ;
    USE SIGNAL ;
    PORT
      LAYER M4 ;
        RECT  139.916 85.728 140 85.752 ;
    END
  END vm_wdata[320]
  PIN vm_wdata[321]
    DIRECTION OUTPUT ;
    USE SIGNAL ;
    PORT
      LAYER M4 ;
        RECT  139.916 85.776 140 85.8 ;
    END
  END vm_wdata[321]
  PIN vm_wdata[322]
    DIRECTION OUTPUT ;
    USE SIGNAL ;
    PORT
      LAYER M4 ;
        RECT  139.916 85.824 140 85.848 ;
    END
  END vm_wdata[322]
  PIN vm_wdata[323]
    DIRECTION OUTPUT ;
    USE SIGNAL ;
    PORT
      LAYER M4 ;
        RECT  139.916 85.872 140 85.896 ;
    END
  END vm_wdata[323]
  PIN vm_wdata[324]
    DIRECTION OUTPUT ;
    USE SIGNAL ;
    PORT
      LAYER M4 ;
        RECT  139.916 85.92 140 85.944 ;
    END
  END vm_wdata[324]
  PIN vm_wdata[325]
    DIRECTION OUTPUT ;
    USE SIGNAL ;
    PORT
      LAYER M4 ;
        RECT  139.916 85.968 140 85.992 ;
    END
  END vm_wdata[325]
  PIN vm_wdata[326]
    DIRECTION OUTPUT ;
    USE SIGNAL ;
    PORT
      LAYER M4 ;
        RECT  139.916 86.016 140 86.04 ;
    END
  END vm_wdata[326]
  PIN vm_wdata[327]
    DIRECTION OUTPUT ;
    USE SIGNAL ;
    PORT
      LAYER M4 ;
        RECT  139.916 86.064 140 86.088 ;
    END
  END vm_wdata[327]
  PIN vm_wdata[328]
    DIRECTION OUTPUT ;
    USE SIGNAL ;
    PORT
      LAYER M4 ;
        RECT  139.916 86.112 140 86.136 ;
    END
  END vm_wdata[328]
  PIN vm_wdata[329]
    DIRECTION OUTPUT ;
    USE SIGNAL ;
    PORT
      LAYER M4 ;
        RECT  139.916 86.16 140 86.184 ;
    END
  END vm_wdata[329]
  PIN vm_wdata[32]
    DIRECTION OUTPUT ;
    USE SIGNAL ;
    PORT
      LAYER M4 ;
        RECT  139.916 71.904 140 71.928 ;
    END
  END vm_wdata[32]
  PIN vm_wdata[330]
    DIRECTION OUTPUT ;
    USE SIGNAL ;
    PORT
      LAYER M4 ;
        RECT  139.916 86.208 140 86.232 ;
    END
  END vm_wdata[330]
  PIN vm_wdata[331]
    DIRECTION OUTPUT ;
    USE SIGNAL ;
    PORT
      LAYER M4 ;
        RECT  139.916 86.256 140 86.28 ;
    END
  END vm_wdata[331]
  PIN vm_wdata[332]
    DIRECTION OUTPUT ;
    USE SIGNAL ;
    PORT
      LAYER M4 ;
        RECT  139.916 86.304 140 86.328 ;
    END
  END vm_wdata[332]
  PIN vm_wdata[333]
    DIRECTION OUTPUT ;
    USE SIGNAL ;
    PORT
      LAYER M4 ;
        RECT  139.916 86.352 140 86.376 ;
    END
  END vm_wdata[333]
  PIN vm_wdata[334]
    DIRECTION OUTPUT ;
    USE SIGNAL ;
    PORT
      LAYER M4 ;
        RECT  139.916 86.4 140 86.424 ;
    END
  END vm_wdata[334]
  PIN vm_wdata[335]
    DIRECTION OUTPUT ;
    USE SIGNAL ;
    PORT
      LAYER M4 ;
        RECT  139.916 86.448 140 86.472 ;
    END
  END vm_wdata[335]
  PIN vm_wdata[336]
    DIRECTION OUTPUT ;
    USE SIGNAL ;
    PORT
      LAYER M4 ;
        RECT  139.916 86.496 140 86.52 ;
    END
  END vm_wdata[336]
  PIN vm_wdata[337]
    DIRECTION OUTPUT ;
    USE SIGNAL ;
    PORT
      LAYER M4 ;
        RECT  139.916 86.544 140 86.568 ;
    END
  END vm_wdata[337]
  PIN vm_wdata[338]
    DIRECTION OUTPUT ;
    USE SIGNAL ;
    PORT
      LAYER M4 ;
        RECT  139.916 86.592 140 86.616 ;
    END
  END vm_wdata[338]
  PIN vm_wdata[339]
    DIRECTION OUTPUT ;
    USE SIGNAL ;
    PORT
      LAYER M4 ;
        RECT  139.916 86.64 140 86.664 ;
    END
  END vm_wdata[339]
  PIN vm_wdata[33]
    DIRECTION OUTPUT ;
    USE SIGNAL ;
    PORT
      LAYER M4 ;
        RECT  139.916 71.952 140 71.976 ;
    END
  END vm_wdata[33]
  PIN vm_wdata[340]
    DIRECTION OUTPUT ;
    USE SIGNAL ;
    PORT
      LAYER M4 ;
        RECT  139.916 86.688 140 86.712 ;
    END
  END vm_wdata[340]
  PIN vm_wdata[341]
    DIRECTION OUTPUT ;
    USE SIGNAL ;
    PORT
      LAYER M4 ;
        RECT  139.916 86.736 140 86.76 ;
    END
  END vm_wdata[341]
  PIN vm_wdata[342]
    DIRECTION OUTPUT ;
    USE SIGNAL ;
    PORT
      LAYER M4 ;
        RECT  139.916 86.784 140 86.808 ;
    END
  END vm_wdata[342]
  PIN vm_wdata[343]
    DIRECTION OUTPUT ;
    USE SIGNAL ;
    PORT
      LAYER M4 ;
        RECT  139.916 86.832 140 86.856 ;
    END
  END vm_wdata[343]
  PIN vm_wdata[344]
    DIRECTION OUTPUT ;
    USE SIGNAL ;
    PORT
      LAYER M4 ;
        RECT  139.916 86.88 140 86.904 ;
    END
  END vm_wdata[344]
  PIN vm_wdata[345]
    DIRECTION OUTPUT ;
    USE SIGNAL ;
    PORT
      LAYER M4 ;
        RECT  139.916 86.928 140 86.952 ;
    END
  END vm_wdata[345]
  PIN vm_wdata[346]
    DIRECTION OUTPUT ;
    USE SIGNAL ;
    PORT
      LAYER M4 ;
        RECT  139.916 86.976 140 87 ;
    END
  END vm_wdata[346]
  PIN vm_wdata[347]
    DIRECTION OUTPUT ;
    USE SIGNAL ;
    PORT
      LAYER M4 ;
        RECT  139.916 87.024 140 87.048 ;
    END
  END vm_wdata[347]
  PIN vm_wdata[348]
    DIRECTION OUTPUT ;
    USE SIGNAL ;
    PORT
      LAYER M4 ;
        RECT  139.916 87.072 140 87.096 ;
    END
  END vm_wdata[348]
  PIN vm_wdata[349]
    DIRECTION OUTPUT ;
    USE SIGNAL ;
    PORT
      LAYER M4 ;
        RECT  139.916 87.12 140 87.144 ;
    END
  END vm_wdata[349]
  PIN vm_wdata[34]
    DIRECTION OUTPUT ;
    USE SIGNAL ;
    PORT
      LAYER M4 ;
        RECT  139.916 72 140 72.024 ;
    END
  END vm_wdata[34]
  PIN vm_wdata[350]
    DIRECTION OUTPUT ;
    USE SIGNAL ;
    PORT
      LAYER M4 ;
        RECT  139.916 87.168 140 87.192 ;
    END
  END vm_wdata[350]
  PIN vm_wdata[351]
    DIRECTION OUTPUT ;
    USE SIGNAL ;
    PORT
      LAYER M4 ;
        RECT  139.916 87.216 140 87.24 ;
    END
  END vm_wdata[351]
  PIN vm_wdata[352]
    DIRECTION OUTPUT ;
    USE SIGNAL ;
    PORT
      LAYER M4 ;
        RECT  139.916 87.264 140 87.288 ;
    END
  END vm_wdata[352]
  PIN vm_wdata[353]
    DIRECTION OUTPUT ;
    USE SIGNAL ;
    PORT
      LAYER M4 ;
        RECT  139.916 87.312 140 87.336 ;
    END
  END vm_wdata[353]
  PIN vm_wdata[354]
    DIRECTION OUTPUT ;
    USE SIGNAL ;
    PORT
      LAYER M4 ;
        RECT  139.916 87.36 140 87.384 ;
    END
  END vm_wdata[354]
  PIN vm_wdata[355]
    DIRECTION OUTPUT ;
    USE SIGNAL ;
    PORT
      LAYER M4 ;
        RECT  139.916 87.408 140 87.432 ;
    END
  END vm_wdata[355]
  PIN vm_wdata[356]
    DIRECTION OUTPUT ;
    USE SIGNAL ;
    PORT
      LAYER M4 ;
        RECT  139.916 87.456 140 87.48 ;
    END
  END vm_wdata[356]
  PIN vm_wdata[357]
    DIRECTION OUTPUT ;
    USE SIGNAL ;
    PORT
      LAYER M4 ;
        RECT  139.916 87.504 140 87.528 ;
    END
  END vm_wdata[357]
  PIN vm_wdata[358]
    DIRECTION OUTPUT ;
    USE SIGNAL ;
    PORT
      LAYER M4 ;
        RECT  139.916 87.552 140 87.576 ;
    END
  END vm_wdata[358]
  PIN vm_wdata[359]
    DIRECTION OUTPUT ;
    USE SIGNAL ;
    PORT
      LAYER M4 ;
        RECT  139.916 87.6 140 87.624 ;
    END
  END vm_wdata[359]
  PIN vm_wdata[35]
    DIRECTION OUTPUT ;
    USE SIGNAL ;
    PORT
      LAYER M4 ;
        RECT  139.916 72.048 140 72.072 ;
    END
  END vm_wdata[35]
  PIN vm_wdata[360]
    DIRECTION OUTPUT ;
    USE SIGNAL ;
    PORT
      LAYER M4 ;
        RECT  139.916 87.648 140 87.672 ;
    END
  END vm_wdata[360]
  PIN vm_wdata[361]
    DIRECTION OUTPUT ;
    USE SIGNAL ;
    PORT
      LAYER M4 ;
        RECT  139.916 87.696 140 87.72 ;
    END
  END vm_wdata[361]
  PIN vm_wdata[362]
    DIRECTION OUTPUT ;
    USE SIGNAL ;
    PORT
      LAYER M4 ;
        RECT  139.916 87.744 140 87.768 ;
    END
  END vm_wdata[362]
  PIN vm_wdata[363]
    DIRECTION OUTPUT ;
    USE SIGNAL ;
    PORT
      LAYER M4 ;
        RECT  139.916 87.792 140 87.816 ;
    END
  END vm_wdata[363]
  PIN vm_wdata[364]
    DIRECTION OUTPUT ;
    USE SIGNAL ;
    PORT
      LAYER M4 ;
        RECT  139.916 87.84 140 87.864 ;
    END
  END vm_wdata[364]
  PIN vm_wdata[365]
    DIRECTION OUTPUT ;
    USE SIGNAL ;
    PORT
      LAYER M4 ;
        RECT  139.916 87.888 140 87.912 ;
    END
  END vm_wdata[365]
  PIN vm_wdata[366]
    DIRECTION OUTPUT ;
    USE SIGNAL ;
    PORT
      LAYER M4 ;
        RECT  139.916 87.936 140 87.96 ;
    END
  END vm_wdata[366]
  PIN vm_wdata[367]
    DIRECTION OUTPUT ;
    USE SIGNAL ;
    PORT
      LAYER M4 ;
        RECT  139.916 87.984 140 88.008 ;
    END
  END vm_wdata[367]
  PIN vm_wdata[368]
    DIRECTION OUTPUT ;
    USE SIGNAL ;
    PORT
      LAYER M4 ;
        RECT  139.916 88.032 140 88.056 ;
    END
  END vm_wdata[368]
  PIN vm_wdata[369]
    DIRECTION OUTPUT ;
    USE SIGNAL ;
    PORT
      LAYER M4 ;
        RECT  139.916 88.08 140 88.104 ;
    END
  END vm_wdata[369]
  PIN vm_wdata[36]
    DIRECTION OUTPUT ;
    USE SIGNAL ;
    PORT
      LAYER M4 ;
        RECT  139.916 72.096 140 72.12 ;
    END
  END vm_wdata[36]
  PIN vm_wdata[370]
    DIRECTION OUTPUT ;
    USE SIGNAL ;
    PORT
      LAYER M4 ;
        RECT  139.916 88.128 140 88.152 ;
    END
  END vm_wdata[370]
  PIN vm_wdata[371]
    DIRECTION OUTPUT ;
    USE SIGNAL ;
    PORT
      LAYER M4 ;
        RECT  139.916 88.176 140 88.2 ;
    END
  END vm_wdata[371]
  PIN vm_wdata[372]
    DIRECTION OUTPUT ;
    USE SIGNAL ;
    PORT
      LAYER M4 ;
        RECT  139.916 88.224 140 88.248 ;
    END
  END vm_wdata[372]
  PIN vm_wdata[373]
    DIRECTION OUTPUT ;
    USE SIGNAL ;
    PORT
      LAYER M4 ;
        RECT  139.916 88.272 140 88.296 ;
    END
  END vm_wdata[373]
  PIN vm_wdata[374]
    DIRECTION OUTPUT ;
    USE SIGNAL ;
    PORT
      LAYER M4 ;
        RECT  139.916 88.32 140 88.344 ;
    END
  END vm_wdata[374]
  PIN vm_wdata[375]
    DIRECTION OUTPUT ;
    USE SIGNAL ;
    PORT
      LAYER M4 ;
        RECT  139.916 88.368 140 88.392 ;
    END
  END vm_wdata[375]
  PIN vm_wdata[376]
    DIRECTION OUTPUT ;
    USE SIGNAL ;
    PORT
      LAYER M4 ;
        RECT  139.916 88.416 140 88.44 ;
    END
  END vm_wdata[376]
  PIN vm_wdata[377]
    DIRECTION OUTPUT ;
    USE SIGNAL ;
    PORT
      LAYER M4 ;
        RECT  139.916 88.464 140 88.488 ;
    END
  END vm_wdata[377]
  PIN vm_wdata[378]
    DIRECTION OUTPUT ;
    USE SIGNAL ;
    PORT
      LAYER M4 ;
        RECT  139.916 88.512 140 88.536 ;
    END
  END vm_wdata[378]
  PIN vm_wdata[379]
    DIRECTION OUTPUT ;
    USE SIGNAL ;
    PORT
      LAYER M4 ;
        RECT  139.916 88.56 140 88.584 ;
    END
  END vm_wdata[379]
  PIN vm_wdata[37]
    DIRECTION OUTPUT ;
    USE SIGNAL ;
    PORT
      LAYER M4 ;
        RECT  139.916 72.144 140 72.168 ;
    END
  END vm_wdata[37]
  PIN vm_wdata[380]
    DIRECTION OUTPUT ;
    USE SIGNAL ;
    PORT
      LAYER M4 ;
        RECT  139.916 88.608 140 88.632 ;
    END
  END vm_wdata[380]
  PIN vm_wdata[381]
    DIRECTION OUTPUT ;
    USE SIGNAL ;
    PORT
      LAYER M4 ;
        RECT  139.916 88.656 140 88.68 ;
    END
  END vm_wdata[381]
  PIN vm_wdata[382]
    DIRECTION OUTPUT ;
    USE SIGNAL ;
    PORT
      LAYER M4 ;
        RECT  139.916 88.704 140 88.728 ;
    END
  END vm_wdata[382]
  PIN vm_wdata[383]
    DIRECTION OUTPUT ;
    USE SIGNAL ;
    PORT
      LAYER M4 ;
        RECT  139.916 88.752 140 88.776 ;
    END
  END vm_wdata[383]
  PIN vm_wdata[384]
    DIRECTION OUTPUT ;
    USE SIGNAL ;
    PORT
      LAYER M4 ;
        RECT  139.916 88.8 140 88.824 ;
    END
  END vm_wdata[384]
  PIN vm_wdata[385]
    DIRECTION OUTPUT ;
    USE SIGNAL ;
    PORT
      LAYER M4 ;
        RECT  139.916 88.848 140 88.872 ;
    END
  END vm_wdata[385]
  PIN vm_wdata[386]
    DIRECTION OUTPUT ;
    USE SIGNAL ;
    PORT
      LAYER M4 ;
        RECT  139.916 88.896 140 88.92 ;
    END
  END vm_wdata[386]
  PIN vm_wdata[387]
    DIRECTION OUTPUT ;
    USE SIGNAL ;
    PORT
      LAYER M4 ;
        RECT  139.916 88.944 140 88.968 ;
    END
  END vm_wdata[387]
  PIN vm_wdata[388]
    DIRECTION OUTPUT ;
    USE SIGNAL ;
    PORT
      LAYER M4 ;
        RECT  139.916 88.992 140 89.016 ;
    END
  END vm_wdata[388]
  PIN vm_wdata[389]
    DIRECTION OUTPUT ;
    USE SIGNAL ;
    PORT
      LAYER M4 ;
        RECT  139.916 89.04 140 89.064 ;
    END
  END vm_wdata[389]
  PIN vm_wdata[38]
    DIRECTION OUTPUT ;
    USE SIGNAL ;
    PORT
      LAYER M4 ;
        RECT  139.916 72.192 140 72.216 ;
    END
  END vm_wdata[38]
  PIN vm_wdata[390]
    DIRECTION OUTPUT ;
    USE SIGNAL ;
    PORT
      LAYER M4 ;
        RECT  139.916 89.088 140 89.112 ;
    END
  END vm_wdata[390]
  PIN vm_wdata[391]
    DIRECTION OUTPUT ;
    USE SIGNAL ;
    PORT
      LAYER M4 ;
        RECT  139.916 89.136 140 89.16 ;
    END
  END vm_wdata[391]
  PIN vm_wdata[392]
    DIRECTION OUTPUT ;
    USE SIGNAL ;
    PORT
      LAYER M4 ;
        RECT  139.916 89.184 140 89.208 ;
    END
  END vm_wdata[392]
  PIN vm_wdata[393]
    DIRECTION OUTPUT ;
    USE SIGNAL ;
    PORT
      LAYER M4 ;
        RECT  139.916 89.232 140 89.256 ;
    END
  END vm_wdata[393]
  PIN vm_wdata[394]
    DIRECTION OUTPUT ;
    USE SIGNAL ;
    PORT
      LAYER M4 ;
        RECT  139.916 89.28 140 89.304 ;
    END
  END vm_wdata[394]
  PIN vm_wdata[395]
    DIRECTION OUTPUT ;
    USE SIGNAL ;
    PORT
      LAYER M4 ;
        RECT  139.916 89.328 140 89.352 ;
    END
  END vm_wdata[395]
  PIN vm_wdata[396]
    DIRECTION OUTPUT ;
    USE SIGNAL ;
    PORT
      LAYER M4 ;
        RECT  139.916 89.376 140 89.4 ;
    END
  END vm_wdata[396]
  PIN vm_wdata[397]
    DIRECTION OUTPUT ;
    USE SIGNAL ;
    PORT
      LAYER M4 ;
        RECT  139.916 89.424 140 89.448 ;
    END
  END vm_wdata[397]
  PIN vm_wdata[398]
    DIRECTION OUTPUT ;
    USE SIGNAL ;
    PORT
      LAYER M4 ;
        RECT  139.916 89.472 140 89.496 ;
    END
  END vm_wdata[398]
  PIN vm_wdata[399]
    DIRECTION OUTPUT ;
    USE SIGNAL ;
    PORT
      LAYER M4 ;
        RECT  139.916 89.52 140 89.544 ;
    END
  END vm_wdata[399]
  PIN vm_wdata[39]
    DIRECTION OUTPUT ;
    USE SIGNAL ;
    PORT
      LAYER M4 ;
        RECT  139.916 72.24 140 72.264 ;
    END
  END vm_wdata[39]
  PIN vm_wdata[3]
    DIRECTION OUTPUT ;
    USE SIGNAL ;
    PORT
      LAYER M4 ;
        RECT  139.916 70.512 140 70.536 ;
    END
  END vm_wdata[3]
  PIN vm_wdata[400]
    DIRECTION OUTPUT ;
    USE SIGNAL ;
    PORT
      LAYER M4 ;
        RECT  139.916 89.568 140 89.592 ;
    END
  END vm_wdata[400]
  PIN vm_wdata[401]
    DIRECTION OUTPUT ;
    USE SIGNAL ;
    PORT
      LAYER M4 ;
        RECT  139.916 89.616 140 89.64 ;
    END
  END vm_wdata[401]
  PIN vm_wdata[402]
    DIRECTION OUTPUT ;
    USE SIGNAL ;
    PORT
      LAYER M4 ;
        RECT  139.916 89.664 140 89.688 ;
    END
  END vm_wdata[402]
  PIN vm_wdata[403]
    DIRECTION OUTPUT ;
    USE SIGNAL ;
    PORT
      LAYER M4 ;
        RECT  139.916 89.712 140 89.736 ;
    END
  END vm_wdata[403]
  PIN vm_wdata[404]
    DIRECTION OUTPUT ;
    USE SIGNAL ;
    PORT
      LAYER M4 ;
        RECT  139.916 89.76 140 89.784 ;
    END
  END vm_wdata[404]
  PIN vm_wdata[405]
    DIRECTION OUTPUT ;
    USE SIGNAL ;
    PORT
      LAYER M4 ;
        RECT  139.916 89.808 140 89.832 ;
    END
  END vm_wdata[405]
  PIN vm_wdata[406]
    DIRECTION OUTPUT ;
    USE SIGNAL ;
    PORT
      LAYER M4 ;
        RECT  139.916 89.856 140 89.88 ;
    END
  END vm_wdata[406]
  PIN vm_wdata[407]
    DIRECTION OUTPUT ;
    USE SIGNAL ;
    PORT
      LAYER M4 ;
        RECT  139.916 89.904 140 89.928 ;
    END
  END vm_wdata[407]
  PIN vm_wdata[408]
    DIRECTION OUTPUT ;
    USE SIGNAL ;
    PORT
      LAYER M4 ;
        RECT  139.916 89.952 140 89.976 ;
    END
  END vm_wdata[408]
  PIN vm_wdata[409]
    DIRECTION OUTPUT ;
    USE SIGNAL ;
    PORT
      LAYER M4 ;
        RECT  139.916 90 140 90.024 ;
    END
  END vm_wdata[409]
  PIN vm_wdata[40]
    DIRECTION OUTPUT ;
    USE SIGNAL ;
    PORT
      LAYER M4 ;
        RECT  139.916 72.288 140 72.312 ;
    END
  END vm_wdata[40]
  PIN vm_wdata[410]
    DIRECTION OUTPUT ;
    USE SIGNAL ;
    PORT
      LAYER M4 ;
        RECT  139.916 90.048 140 90.072 ;
    END
  END vm_wdata[410]
  PIN vm_wdata[411]
    DIRECTION OUTPUT ;
    USE SIGNAL ;
    PORT
      LAYER M4 ;
        RECT  139.916 90.096 140 90.12 ;
    END
  END vm_wdata[411]
  PIN vm_wdata[412]
    DIRECTION OUTPUT ;
    USE SIGNAL ;
    PORT
      LAYER M4 ;
        RECT  139.916 90.144 140 90.168 ;
    END
  END vm_wdata[412]
  PIN vm_wdata[413]
    DIRECTION OUTPUT ;
    USE SIGNAL ;
    PORT
      LAYER M4 ;
        RECT  139.916 90.192 140 90.216 ;
    END
  END vm_wdata[413]
  PIN vm_wdata[414]
    DIRECTION OUTPUT ;
    USE SIGNAL ;
    PORT
      LAYER M4 ;
        RECT  139.916 90.24 140 90.264 ;
    END
  END vm_wdata[414]
  PIN vm_wdata[415]
    DIRECTION OUTPUT ;
    USE SIGNAL ;
    PORT
      LAYER M4 ;
        RECT  139.916 90.288 140 90.312 ;
    END
  END vm_wdata[415]
  PIN vm_wdata[416]
    DIRECTION OUTPUT ;
    USE SIGNAL ;
    PORT
      LAYER M4 ;
        RECT  139.916 90.336 140 90.36 ;
    END
  END vm_wdata[416]
  PIN vm_wdata[417]
    DIRECTION OUTPUT ;
    USE SIGNAL ;
    PORT
      LAYER M4 ;
        RECT  139.916 90.384 140 90.408 ;
    END
  END vm_wdata[417]
  PIN vm_wdata[418]
    DIRECTION OUTPUT ;
    USE SIGNAL ;
    PORT
      LAYER M4 ;
        RECT  139.916 90.432 140 90.456 ;
    END
  END vm_wdata[418]
  PIN vm_wdata[419]
    DIRECTION OUTPUT ;
    USE SIGNAL ;
    PORT
      LAYER M4 ;
        RECT  139.916 90.48 140 90.504 ;
    END
  END vm_wdata[419]
  PIN vm_wdata[41]
    DIRECTION OUTPUT ;
    USE SIGNAL ;
    PORT
      LAYER M4 ;
        RECT  139.916 72.336 140 72.36 ;
    END
  END vm_wdata[41]
  PIN vm_wdata[420]
    DIRECTION OUTPUT ;
    USE SIGNAL ;
    PORT
      LAYER M4 ;
        RECT  139.916 90.528 140 90.552 ;
    END
  END vm_wdata[420]
  PIN vm_wdata[421]
    DIRECTION OUTPUT ;
    USE SIGNAL ;
    PORT
      LAYER M4 ;
        RECT  139.916 90.576 140 90.6 ;
    END
  END vm_wdata[421]
  PIN vm_wdata[422]
    DIRECTION OUTPUT ;
    USE SIGNAL ;
    PORT
      LAYER M4 ;
        RECT  139.916 90.624 140 90.648 ;
    END
  END vm_wdata[422]
  PIN vm_wdata[423]
    DIRECTION OUTPUT ;
    USE SIGNAL ;
    PORT
      LAYER M4 ;
        RECT  139.916 90.672 140 90.696 ;
    END
  END vm_wdata[423]
  PIN vm_wdata[424]
    DIRECTION OUTPUT ;
    USE SIGNAL ;
    PORT
      LAYER M4 ;
        RECT  139.916 90.72 140 90.744 ;
    END
  END vm_wdata[424]
  PIN vm_wdata[425]
    DIRECTION OUTPUT ;
    USE SIGNAL ;
    PORT
      LAYER M4 ;
        RECT  139.916 90.768 140 90.792 ;
    END
  END vm_wdata[425]
  PIN vm_wdata[426]
    DIRECTION OUTPUT ;
    USE SIGNAL ;
    PORT
      LAYER M4 ;
        RECT  139.916 90.816 140 90.84 ;
    END
  END vm_wdata[426]
  PIN vm_wdata[427]
    DIRECTION OUTPUT ;
    USE SIGNAL ;
    PORT
      LAYER M4 ;
        RECT  139.916 90.864 140 90.888 ;
    END
  END vm_wdata[427]
  PIN vm_wdata[428]
    DIRECTION OUTPUT ;
    USE SIGNAL ;
    PORT
      LAYER M4 ;
        RECT  139.916 90.912 140 90.936 ;
    END
  END vm_wdata[428]
  PIN vm_wdata[429]
    DIRECTION OUTPUT ;
    USE SIGNAL ;
    PORT
      LAYER M4 ;
        RECT  139.916 90.96 140 90.984 ;
    END
  END vm_wdata[429]
  PIN vm_wdata[42]
    DIRECTION OUTPUT ;
    USE SIGNAL ;
    PORT
      LAYER M4 ;
        RECT  139.916 72.384 140 72.408 ;
    END
  END vm_wdata[42]
  PIN vm_wdata[430]
    DIRECTION OUTPUT ;
    USE SIGNAL ;
    PORT
      LAYER M4 ;
        RECT  139.916 91.008 140 91.032 ;
    END
  END vm_wdata[430]
  PIN vm_wdata[431]
    DIRECTION OUTPUT ;
    USE SIGNAL ;
    PORT
      LAYER M4 ;
        RECT  139.916 91.056 140 91.08 ;
    END
  END vm_wdata[431]
  PIN vm_wdata[432]
    DIRECTION OUTPUT ;
    USE SIGNAL ;
    PORT
      LAYER M4 ;
        RECT  139.916 91.104 140 91.128 ;
    END
  END vm_wdata[432]
  PIN vm_wdata[433]
    DIRECTION OUTPUT ;
    USE SIGNAL ;
    PORT
      LAYER M4 ;
        RECT  139.916 91.152 140 91.176 ;
    END
  END vm_wdata[433]
  PIN vm_wdata[434]
    DIRECTION OUTPUT ;
    USE SIGNAL ;
    PORT
      LAYER M4 ;
        RECT  139.916 91.2 140 91.224 ;
    END
  END vm_wdata[434]
  PIN vm_wdata[435]
    DIRECTION OUTPUT ;
    USE SIGNAL ;
    PORT
      LAYER M4 ;
        RECT  139.916 91.248 140 91.272 ;
    END
  END vm_wdata[435]
  PIN vm_wdata[436]
    DIRECTION OUTPUT ;
    USE SIGNAL ;
    PORT
      LAYER M4 ;
        RECT  139.916 91.296 140 91.32 ;
    END
  END vm_wdata[436]
  PIN vm_wdata[437]
    DIRECTION OUTPUT ;
    USE SIGNAL ;
    PORT
      LAYER M4 ;
        RECT  139.916 91.344 140 91.368 ;
    END
  END vm_wdata[437]
  PIN vm_wdata[438]
    DIRECTION OUTPUT ;
    USE SIGNAL ;
    PORT
      LAYER M4 ;
        RECT  139.916 91.392 140 91.416 ;
    END
  END vm_wdata[438]
  PIN vm_wdata[439]
    DIRECTION OUTPUT ;
    USE SIGNAL ;
    PORT
      LAYER M4 ;
        RECT  139.916 91.44 140 91.464 ;
    END
  END vm_wdata[439]
  PIN vm_wdata[43]
    DIRECTION OUTPUT ;
    USE SIGNAL ;
    PORT
      LAYER M4 ;
        RECT  139.916 72.432 140 72.456 ;
    END
  END vm_wdata[43]
  PIN vm_wdata[440]
    DIRECTION OUTPUT ;
    USE SIGNAL ;
    PORT
      LAYER M4 ;
        RECT  139.916 91.488 140 91.512 ;
    END
  END vm_wdata[440]
  PIN vm_wdata[441]
    DIRECTION OUTPUT ;
    USE SIGNAL ;
    PORT
      LAYER M4 ;
        RECT  139.916 91.536 140 91.56 ;
    END
  END vm_wdata[441]
  PIN vm_wdata[442]
    DIRECTION OUTPUT ;
    USE SIGNAL ;
    PORT
      LAYER M4 ;
        RECT  139.916 91.584 140 91.608 ;
    END
  END vm_wdata[442]
  PIN vm_wdata[443]
    DIRECTION OUTPUT ;
    USE SIGNAL ;
    PORT
      LAYER M4 ;
        RECT  139.916 91.632 140 91.656 ;
    END
  END vm_wdata[443]
  PIN vm_wdata[444]
    DIRECTION OUTPUT ;
    USE SIGNAL ;
    PORT
      LAYER M4 ;
        RECT  139.916 91.68 140 91.704 ;
    END
  END vm_wdata[444]
  PIN vm_wdata[445]
    DIRECTION OUTPUT ;
    USE SIGNAL ;
    PORT
      LAYER M4 ;
        RECT  139.916 91.728 140 91.752 ;
    END
  END vm_wdata[445]
  PIN vm_wdata[446]
    DIRECTION OUTPUT ;
    USE SIGNAL ;
    PORT
      LAYER M4 ;
        RECT  139.916 91.776 140 91.8 ;
    END
  END vm_wdata[446]
  PIN vm_wdata[447]
    DIRECTION OUTPUT ;
    USE SIGNAL ;
    PORT
      LAYER M4 ;
        RECT  139.916 91.824 140 91.848 ;
    END
  END vm_wdata[447]
  PIN vm_wdata[448]
    DIRECTION OUTPUT ;
    USE SIGNAL ;
    PORT
      LAYER M4 ;
        RECT  139.916 91.872 140 91.896 ;
    END
  END vm_wdata[448]
  PIN vm_wdata[449]
    DIRECTION OUTPUT ;
    USE SIGNAL ;
    PORT
      LAYER M4 ;
        RECT  139.916 91.92 140 91.944 ;
    END
  END vm_wdata[449]
  PIN vm_wdata[44]
    DIRECTION OUTPUT ;
    USE SIGNAL ;
    PORT
      LAYER M4 ;
        RECT  139.916 72.48 140 72.504 ;
    END
  END vm_wdata[44]
  PIN vm_wdata[450]
    DIRECTION OUTPUT ;
    USE SIGNAL ;
    PORT
      LAYER M4 ;
        RECT  139.916 91.968 140 91.992 ;
    END
  END vm_wdata[450]
  PIN vm_wdata[451]
    DIRECTION OUTPUT ;
    USE SIGNAL ;
    PORT
      LAYER M4 ;
        RECT  139.916 92.016 140 92.04 ;
    END
  END vm_wdata[451]
  PIN vm_wdata[452]
    DIRECTION OUTPUT ;
    USE SIGNAL ;
    PORT
      LAYER M4 ;
        RECT  139.916 92.064 140 92.088 ;
    END
  END vm_wdata[452]
  PIN vm_wdata[453]
    DIRECTION OUTPUT ;
    USE SIGNAL ;
    PORT
      LAYER M4 ;
        RECT  139.916 92.112 140 92.136 ;
    END
  END vm_wdata[453]
  PIN vm_wdata[454]
    DIRECTION OUTPUT ;
    USE SIGNAL ;
    PORT
      LAYER M4 ;
        RECT  139.916 92.16 140 92.184 ;
    END
  END vm_wdata[454]
  PIN vm_wdata[455]
    DIRECTION OUTPUT ;
    USE SIGNAL ;
    PORT
      LAYER M4 ;
        RECT  139.916 92.208 140 92.232 ;
    END
  END vm_wdata[455]
  PIN vm_wdata[456]
    DIRECTION OUTPUT ;
    USE SIGNAL ;
    PORT
      LAYER M4 ;
        RECT  139.916 92.256 140 92.28 ;
    END
  END vm_wdata[456]
  PIN vm_wdata[457]
    DIRECTION OUTPUT ;
    USE SIGNAL ;
    PORT
      LAYER M4 ;
        RECT  139.916 92.304 140 92.328 ;
    END
  END vm_wdata[457]
  PIN vm_wdata[458]
    DIRECTION OUTPUT ;
    USE SIGNAL ;
    PORT
      LAYER M4 ;
        RECT  139.916 92.352 140 92.376 ;
    END
  END vm_wdata[458]
  PIN vm_wdata[459]
    DIRECTION OUTPUT ;
    USE SIGNAL ;
    PORT
      LAYER M4 ;
        RECT  139.916 92.4 140 92.424 ;
    END
  END vm_wdata[459]
  PIN vm_wdata[45]
    DIRECTION OUTPUT ;
    USE SIGNAL ;
    PORT
      LAYER M4 ;
        RECT  139.916 72.528 140 72.552 ;
    END
  END vm_wdata[45]
  PIN vm_wdata[460]
    DIRECTION OUTPUT ;
    USE SIGNAL ;
    PORT
      LAYER M4 ;
        RECT  139.916 92.448 140 92.472 ;
    END
  END vm_wdata[460]
  PIN vm_wdata[461]
    DIRECTION OUTPUT ;
    USE SIGNAL ;
    PORT
      LAYER M4 ;
        RECT  139.916 92.496 140 92.52 ;
    END
  END vm_wdata[461]
  PIN vm_wdata[462]
    DIRECTION OUTPUT ;
    USE SIGNAL ;
    PORT
      LAYER M4 ;
        RECT  139.916 92.544 140 92.568 ;
    END
  END vm_wdata[462]
  PIN vm_wdata[463]
    DIRECTION OUTPUT ;
    USE SIGNAL ;
    PORT
      LAYER M4 ;
        RECT  139.916 92.592 140 92.616 ;
    END
  END vm_wdata[463]
  PIN vm_wdata[464]
    DIRECTION OUTPUT ;
    USE SIGNAL ;
    PORT
      LAYER M4 ;
        RECT  139.916 92.64 140 92.664 ;
    END
  END vm_wdata[464]
  PIN vm_wdata[465]
    DIRECTION OUTPUT ;
    USE SIGNAL ;
    PORT
      LAYER M4 ;
        RECT  139.916 92.688 140 92.712 ;
    END
  END vm_wdata[465]
  PIN vm_wdata[466]
    DIRECTION OUTPUT ;
    USE SIGNAL ;
    PORT
      LAYER M4 ;
        RECT  139.916 92.736 140 92.76 ;
    END
  END vm_wdata[466]
  PIN vm_wdata[467]
    DIRECTION OUTPUT ;
    USE SIGNAL ;
    PORT
      LAYER M4 ;
        RECT  139.916 92.784 140 92.808 ;
    END
  END vm_wdata[467]
  PIN vm_wdata[468]
    DIRECTION OUTPUT ;
    USE SIGNAL ;
    PORT
      LAYER M4 ;
        RECT  139.916 92.832 140 92.856 ;
    END
  END vm_wdata[468]
  PIN vm_wdata[469]
    DIRECTION OUTPUT ;
    USE SIGNAL ;
    PORT
      LAYER M4 ;
        RECT  139.916 92.88 140 92.904 ;
    END
  END vm_wdata[469]
  PIN vm_wdata[46]
    DIRECTION OUTPUT ;
    USE SIGNAL ;
    PORT
      LAYER M4 ;
        RECT  139.916 72.576 140 72.6 ;
    END
  END vm_wdata[46]
  PIN vm_wdata[470]
    DIRECTION OUTPUT ;
    USE SIGNAL ;
    PORT
      LAYER M4 ;
        RECT  139.916 92.928 140 92.952 ;
    END
  END vm_wdata[470]
  PIN vm_wdata[471]
    DIRECTION OUTPUT ;
    USE SIGNAL ;
    PORT
      LAYER M4 ;
        RECT  139.916 92.976 140 93 ;
    END
  END vm_wdata[471]
  PIN vm_wdata[472]
    DIRECTION OUTPUT ;
    USE SIGNAL ;
    PORT
      LAYER M4 ;
        RECT  139.916 93.024 140 93.048 ;
    END
  END vm_wdata[472]
  PIN vm_wdata[473]
    DIRECTION OUTPUT ;
    USE SIGNAL ;
    PORT
      LAYER M4 ;
        RECT  139.916 93.072 140 93.096 ;
    END
  END vm_wdata[473]
  PIN vm_wdata[474]
    DIRECTION OUTPUT ;
    USE SIGNAL ;
    PORT
      LAYER M4 ;
        RECT  139.916 93.12 140 93.144 ;
    END
  END vm_wdata[474]
  PIN vm_wdata[475]
    DIRECTION OUTPUT ;
    USE SIGNAL ;
    PORT
      LAYER M4 ;
        RECT  139.916 93.168 140 93.192 ;
    END
  END vm_wdata[475]
  PIN vm_wdata[476]
    DIRECTION OUTPUT ;
    USE SIGNAL ;
    PORT
      LAYER M4 ;
        RECT  139.916 93.216 140 93.24 ;
    END
  END vm_wdata[476]
  PIN vm_wdata[477]
    DIRECTION OUTPUT ;
    USE SIGNAL ;
    PORT
      LAYER M4 ;
        RECT  139.916 93.264 140 93.288 ;
    END
  END vm_wdata[477]
  PIN vm_wdata[478]
    DIRECTION OUTPUT ;
    USE SIGNAL ;
    PORT
      LAYER M4 ;
        RECT  139.916 93.312 140 93.336 ;
    END
  END vm_wdata[478]
  PIN vm_wdata[479]
    DIRECTION OUTPUT ;
    USE SIGNAL ;
    PORT
      LAYER M4 ;
        RECT  139.916 93.36 140 93.384 ;
    END
  END vm_wdata[479]
  PIN vm_wdata[47]
    DIRECTION OUTPUT ;
    USE SIGNAL ;
    PORT
      LAYER M4 ;
        RECT  139.916 72.624 140 72.648 ;
    END
  END vm_wdata[47]
  PIN vm_wdata[480]
    DIRECTION OUTPUT ;
    USE SIGNAL ;
    PORT
      LAYER M4 ;
        RECT  139.916 93.408 140 93.432 ;
    END
  END vm_wdata[480]
  PIN vm_wdata[481]
    DIRECTION OUTPUT ;
    USE SIGNAL ;
    PORT
      LAYER M4 ;
        RECT  139.916 93.456 140 93.48 ;
    END
  END vm_wdata[481]
  PIN vm_wdata[482]
    DIRECTION OUTPUT ;
    USE SIGNAL ;
    PORT
      LAYER M4 ;
        RECT  139.916 93.504 140 93.528 ;
    END
  END vm_wdata[482]
  PIN vm_wdata[483]
    DIRECTION OUTPUT ;
    USE SIGNAL ;
    PORT
      LAYER M4 ;
        RECT  139.916 93.552 140 93.576 ;
    END
  END vm_wdata[483]
  PIN vm_wdata[484]
    DIRECTION OUTPUT ;
    USE SIGNAL ;
    PORT
      LAYER M4 ;
        RECT  139.916 93.6 140 93.624 ;
    END
  END vm_wdata[484]
  PIN vm_wdata[485]
    DIRECTION OUTPUT ;
    USE SIGNAL ;
    PORT
      LAYER M4 ;
        RECT  139.916 93.648 140 93.672 ;
    END
  END vm_wdata[485]
  PIN vm_wdata[486]
    DIRECTION OUTPUT ;
    USE SIGNAL ;
    PORT
      LAYER M4 ;
        RECT  139.916 93.696 140 93.72 ;
    END
  END vm_wdata[486]
  PIN vm_wdata[487]
    DIRECTION OUTPUT ;
    USE SIGNAL ;
    PORT
      LAYER M4 ;
        RECT  139.916 93.744 140 93.768 ;
    END
  END vm_wdata[487]
  PIN vm_wdata[488]
    DIRECTION OUTPUT ;
    USE SIGNAL ;
    PORT
      LAYER M4 ;
        RECT  139.916 93.792 140 93.816 ;
    END
  END vm_wdata[488]
  PIN vm_wdata[489]
    DIRECTION OUTPUT ;
    USE SIGNAL ;
    PORT
      LAYER M4 ;
        RECT  139.916 93.84 140 93.864 ;
    END
  END vm_wdata[489]
  PIN vm_wdata[48]
    DIRECTION OUTPUT ;
    USE SIGNAL ;
    PORT
      LAYER M4 ;
        RECT  139.916 72.672 140 72.696 ;
    END
  END vm_wdata[48]
  PIN vm_wdata[490]
    DIRECTION OUTPUT ;
    USE SIGNAL ;
    PORT
      LAYER M4 ;
        RECT  139.916 93.888 140 93.912 ;
    END
  END vm_wdata[490]
  PIN vm_wdata[491]
    DIRECTION OUTPUT ;
    USE SIGNAL ;
    PORT
      LAYER M4 ;
        RECT  139.916 93.936 140 93.96 ;
    END
  END vm_wdata[491]
  PIN vm_wdata[492]
    DIRECTION OUTPUT ;
    USE SIGNAL ;
    PORT
      LAYER M4 ;
        RECT  139.916 93.984 140 94.008 ;
    END
  END vm_wdata[492]
  PIN vm_wdata[493]
    DIRECTION OUTPUT ;
    USE SIGNAL ;
    PORT
      LAYER M4 ;
        RECT  139.916 94.032 140 94.056 ;
    END
  END vm_wdata[493]
  PIN vm_wdata[494]
    DIRECTION OUTPUT ;
    USE SIGNAL ;
    PORT
      LAYER M4 ;
        RECT  139.916 94.08 140 94.104 ;
    END
  END vm_wdata[494]
  PIN vm_wdata[495]
    DIRECTION OUTPUT ;
    USE SIGNAL ;
    PORT
      LAYER M4 ;
        RECT  139.916 94.128 140 94.152 ;
    END
  END vm_wdata[495]
  PIN vm_wdata[496]
    DIRECTION OUTPUT ;
    USE SIGNAL ;
    PORT
      LAYER M4 ;
        RECT  139.916 94.176 140 94.2 ;
    END
  END vm_wdata[496]
  PIN vm_wdata[497]
    DIRECTION OUTPUT ;
    USE SIGNAL ;
    PORT
      LAYER M4 ;
        RECT  139.916 94.224 140 94.248 ;
    END
  END vm_wdata[497]
  PIN vm_wdata[498]
    DIRECTION OUTPUT ;
    USE SIGNAL ;
    PORT
      LAYER M4 ;
        RECT  139.916 94.272 140 94.296 ;
    END
  END vm_wdata[498]
  PIN vm_wdata[499]
    DIRECTION OUTPUT ;
    USE SIGNAL ;
    PORT
      LAYER M4 ;
        RECT  139.916 94.32 140 94.344 ;
    END
  END vm_wdata[499]
  PIN vm_wdata[49]
    DIRECTION OUTPUT ;
    USE SIGNAL ;
    PORT
      LAYER M4 ;
        RECT  139.916 72.72 140 72.744 ;
    END
  END vm_wdata[49]
  PIN vm_wdata[4]
    DIRECTION OUTPUT ;
    USE SIGNAL ;
    PORT
      LAYER M4 ;
        RECT  139.916 70.56 140 70.584 ;
    END
  END vm_wdata[4]
  PIN vm_wdata[500]
    DIRECTION OUTPUT ;
    USE SIGNAL ;
    PORT
      LAYER M4 ;
        RECT  139.916 94.368 140 94.392 ;
    END
  END vm_wdata[500]
  PIN vm_wdata[501]
    DIRECTION OUTPUT ;
    USE SIGNAL ;
    PORT
      LAYER M4 ;
        RECT  139.916 94.416 140 94.44 ;
    END
  END vm_wdata[501]
  PIN vm_wdata[502]
    DIRECTION OUTPUT ;
    USE SIGNAL ;
    PORT
      LAYER M4 ;
        RECT  139.916 94.464 140 94.488 ;
    END
  END vm_wdata[502]
  PIN vm_wdata[503]
    DIRECTION OUTPUT ;
    USE SIGNAL ;
    PORT
      LAYER M4 ;
        RECT  139.916 94.512 140 94.536 ;
    END
  END vm_wdata[503]
  PIN vm_wdata[504]
    DIRECTION OUTPUT ;
    USE SIGNAL ;
    PORT
      LAYER M4 ;
        RECT  139.916 94.56 140 94.584 ;
    END
  END vm_wdata[504]
  PIN vm_wdata[505]
    DIRECTION OUTPUT ;
    USE SIGNAL ;
    PORT
      LAYER M4 ;
        RECT  139.916 94.608 140 94.632 ;
    END
  END vm_wdata[505]
  PIN vm_wdata[506]
    DIRECTION OUTPUT ;
    USE SIGNAL ;
    PORT
      LAYER M4 ;
        RECT  139.916 94.656 140 94.68 ;
    END
  END vm_wdata[506]
  PIN vm_wdata[507]
    DIRECTION OUTPUT ;
    USE SIGNAL ;
    PORT
      LAYER M4 ;
        RECT  139.916 94.704 140 94.728 ;
    END
  END vm_wdata[507]
  PIN vm_wdata[508]
    DIRECTION OUTPUT ;
    USE SIGNAL ;
    PORT
      LAYER M4 ;
        RECT  139.916 94.752 140 94.776 ;
    END
  END vm_wdata[508]
  PIN vm_wdata[509]
    DIRECTION OUTPUT ;
    USE SIGNAL ;
    PORT
      LAYER M4 ;
        RECT  139.916 94.8 140 94.824 ;
    END
  END vm_wdata[509]
  PIN vm_wdata[50]
    DIRECTION OUTPUT ;
    USE SIGNAL ;
    PORT
      LAYER M4 ;
        RECT  139.916 72.768 140 72.792 ;
    END
  END vm_wdata[50]
  PIN vm_wdata[510]
    DIRECTION OUTPUT ;
    USE SIGNAL ;
    PORT
      LAYER M4 ;
        RECT  139.916 94.848 140 94.872 ;
    END
  END vm_wdata[510]
  PIN vm_wdata[511]
    DIRECTION OUTPUT ;
    USE SIGNAL ;
    PORT
      LAYER M4 ;
        RECT  139.916 94.896 140 94.92 ;
    END
  END vm_wdata[511]
  PIN vm_wdata[51]
    DIRECTION OUTPUT ;
    USE SIGNAL ;
    PORT
      LAYER M4 ;
        RECT  139.916 72.816 140 72.84 ;
    END
  END vm_wdata[51]
  PIN vm_wdata[52]
    DIRECTION OUTPUT ;
    USE SIGNAL ;
    PORT
      LAYER M4 ;
        RECT  139.916 72.864 140 72.888 ;
    END
  END vm_wdata[52]
  PIN vm_wdata[53]
    DIRECTION OUTPUT ;
    USE SIGNAL ;
    PORT
      LAYER M4 ;
        RECT  139.916 72.912 140 72.936 ;
    END
  END vm_wdata[53]
  PIN vm_wdata[54]
    DIRECTION OUTPUT ;
    USE SIGNAL ;
    PORT
      LAYER M4 ;
        RECT  139.916 72.96 140 72.984 ;
    END
  END vm_wdata[54]
  PIN vm_wdata[55]
    DIRECTION OUTPUT ;
    USE SIGNAL ;
    PORT
      LAYER M4 ;
        RECT  139.916 73.008 140 73.032 ;
    END
  END vm_wdata[55]
  PIN vm_wdata[56]
    DIRECTION OUTPUT ;
    USE SIGNAL ;
    PORT
      LAYER M4 ;
        RECT  139.916 73.056 140 73.08 ;
    END
  END vm_wdata[56]
  PIN vm_wdata[57]
    DIRECTION OUTPUT ;
    USE SIGNAL ;
    PORT
      LAYER M4 ;
        RECT  139.916 73.104 140 73.128 ;
    END
  END vm_wdata[57]
  PIN vm_wdata[58]
    DIRECTION OUTPUT ;
    USE SIGNAL ;
    PORT
      LAYER M4 ;
        RECT  139.916 73.152 140 73.176 ;
    END
  END vm_wdata[58]
  PIN vm_wdata[59]
    DIRECTION OUTPUT ;
    USE SIGNAL ;
    PORT
      LAYER M4 ;
        RECT  139.916 73.2 140 73.224 ;
    END
  END vm_wdata[59]
  PIN vm_wdata[5]
    DIRECTION OUTPUT ;
    USE SIGNAL ;
    PORT
      LAYER M4 ;
        RECT  139.916 70.608 140 70.632 ;
    END
  END vm_wdata[5]
  PIN vm_wdata[60]
    DIRECTION OUTPUT ;
    USE SIGNAL ;
    PORT
      LAYER M4 ;
        RECT  139.916 73.248 140 73.272 ;
    END
  END vm_wdata[60]
  PIN vm_wdata[61]
    DIRECTION OUTPUT ;
    USE SIGNAL ;
    PORT
      LAYER M4 ;
        RECT  139.916 73.296 140 73.32 ;
    END
  END vm_wdata[61]
  PIN vm_wdata[62]
    DIRECTION OUTPUT ;
    USE SIGNAL ;
    PORT
      LAYER M4 ;
        RECT  139.916 73.344 140 73.368 ;
    END
  END vm_wdata[62]
  PIN vm_wdata[63]
    DIRECTION OUTPUT ;
    USE SIGNAL ;
    PORT
      LAYER M4 ;
        RECT  139.916 73.392 140 73.416 ;
    END
  END vm_wdata[63]
  PIN vm_wdata[64]
    DIRECTION OUTPUT ;
    USE SIGNAL ;
    PORT
      LAYER M4 ;
        RECT  139.916 73.44 140 73.464 ;
    END
  END vm_wdata[64]
  PIN vm_wdata[65]
    DIRECTION OUTPUT ;
    USE SIGNAL ;
    PORT
      LAYER M4 ;
        RECT  139.916 73.488 140 73.512 ;
    END
  END vm_wdata[65]
  PIN vm_wdata[66]
    DIRECTION OUTPUT ;
    USE SIGNAL ;
    PORT
      LAYER M4 ;
        RECT  139.916 73.536 140 73.56 ;
    END
  END vm_wdata[66]
  PIN vm_wdata[67]
    DIRECTION OUTPUT ;
    USE SIGNAL ;
    PORT
      LAYER M4 ;
        RECT  139.916 73.584 140 73.608 ;
    END
  END vm_wdata[67]
  PIN vm_wdata[68]
    DIRECTION OUTPUT ;
    USE SIGNAL ;
    PORT
      LAYER M4 ;
        RECT  139.916 73.632 140 73.656 ;
    END
  END vm_wdata[68]
  PIN vm_wdata[69]
    DIRECTION OUTPUT ;
    USE SIGNAL ;
    PORT
      LAYER M4 ;
        RECT  139.916 73.68 140 73.704 ;
    END
  END vm_wdata[69]
  PIN vm_wdata[6]
    DIRECTION OUTPUT ;
    USE SIGNAL ;
    PORT
      LAYER M4 ;
        RECT  139.916 70.656 140 70.68 ;
    END
  END vm_wdata[6]
  PIN vm_wdata[70]
    DIRECTION OUTPUT ;
    USE SIGNAL ;
    PORT
      LAYER M4 ;
        RECT  139.916 73.728 140 73.752 ;
    END
  END vm_wdata[70]
  PIN vm_wdata[71]
    DIRECTION OUTPUT ;
    USE SIGNAL ;
    PORT
      LAYER M4 ;
        RECT  139.916 73.776 140 73.8 ;
    END
  END vm_wdata[71]
  PIN vm_wdata[72]
    DIRECTION OUTPUT ;
    USE SIGNAL ;
    PORT
      LAYER M4 ;
        RECT  139.916 73.824 140 73.848 ;
    END
  END vm_wdata[72]
  PIN vm_wdata[73]
    DIRECTION OUTPUT ;
    USE SIGNAL ;
    PORT
      LAYER M4 ;
        RECT  139.916 73.872 140 73.896 ;
    END
  END vm_wdata[73]
  PIN vm_wdata[74]
    DIRECTION OUTPUT ;
    USE SIGNAL ;
    PORT
      LAYER M4 ;
        RECT  139.916 73.92 140 73.944 ;
    END
  END vm_wdata[74]
  PIN vm_wdata[75]
    DIRECTION OUTPUT ;
    USE SIGNAL ;
    PORT
      LAYER M4 ;
        RECT  139.916 73.968 140 73.992 ;
    END
  END vm_wdata[75]
  PIN vm_wdata[76]
    DIRECTION OUTPUT ;
    USE SIGNAL ;
    PORT
      LAYER M4 ;
        RECT  139.916 74.016 140 74.04 ;
    END
  END vm_wdata[76]
  PIN vm_wdata[77]
    DIRECTION OUTPUT ;
    USE SIGNAL ;
    PORT
      LAYER M4 ;
        RECT  139.916 74.064 140 74.088 ;
    END
  END vm_wdata[77]
  PIN vm_wdata[78]
    DIRECTION OUTPUT ;
    USE SIGNAL ;
    PORT
      LAYER M4 ;
        RECT  139.916 74.112 140 74.136 ;
    END
  END vm_wdata[78]
  PIN vm_wdata[79]
    DIRECTION OUTPUT ;
    USE SIGNAL ;
    PORT
      LAYER M4 ;
        RECT  139.916 74.16 140 74.184 ;
    END
  END vm_wdata[79]
  PIN vm_wdata[7]
    DIRECTION OUTPUT ;
    USE SIGNAL ;
    PORT
      LAYER M4 ;
        RECT  139.916 70.704 140 70.728 ;
    END
  END vm_wdata[7]
  PIN vm_wdata[80]
    DIRECTION OUTPUT ;
    USE SIGNAL ;
    PORT
      LAYER M4 ;
        RECT  139.916 74.208 140 74.232 ;
    END
  END vm_wdata[80]
  PIN vm_wdata[81]
    DIRECTION OUTPUT ;
    USE SIGNAL ;
    PORT
      LAYER M4 ;
        RECT  139.916 74.256 140 74.28 ;
    END
  END vm_wdata[81]
  PIN vm_wdata[82]
    DIRECTION OUTPUT ;
    USE SIGNAL ;
    PORT
      LAYER M4 ;
        RECT  139.916 74.304 140 74.328 ;
    END
  END vm_wdata[82]
  PIN vm_wdata[83]
    DIRECTION OUTPUT ;
    USE SIGNAL ;
    PORT
      LAYER M4 ;
        RECT  139.916 74.352 140 74.376 ;
    END
  END vm_wdata[83]
  PIN vm_wdata[84]
    DIRECTION OUTPUT ;
    USE SIGNAL ;
    PORT
      LAYER M4 ;
        RECT  139.916 74.4 140 74.424 ;
    END
  END vm_wdata[84]
  PIN vm_wdata[85]
    DIRECTION OUTPUT ;
    USE SIGNAL ;
    PORT
      LAYER M4 ;
        RECT  139.916 74.448 140 74.472 ;
    END
  END vm_wdata[85]
  PIN vm_wdata[86]
    DIRECTION OUTPUT ;
    USE SIGNAL ;
    PORT
      LAYER M4 ;
        RECT  139.916 74.496 140 74.52 ;
    END
  END vm_wdata[86]
  PIN vm_wdata[87]
    DIRECTION OUTPUT ;
    USE SIGNAL ;
    PORT
      LAYER M4 ;
        RECT  139.916 74.544 140 74.568 ;
    END
  END vm_wdata[87]
  PIN vm_wdata[88]
    DIRECTION OUTPUT ;
    USE SIGNAL ;
    PORT
      LAYER M4 ;
        RECT  139.916 74.592 140 74.616 ;
    END
  END vm_wdata[88]
  PIN vm_wdata[89]
    DIRECTION OUTPUT ;
    USE SIGNAL ;
    PORT
      LAYER M4 ;
        RECT  139.916 74.64 140 74.664 ;
    END
  END vm_wdata[89]
  PIN vm_wdata[8]
    DIRECTION OUTPUT ;
    USE SIGNAL ;
    PORT
      LAYER M4 ;
        RECT  139.916 70.752 140 70.776 ;
    END
  END vm_wdata[8]
  PIN vm_wdata[90]
    DIRECTION OUTPUT ;
    USE SIGNAL ;
    PORT
      LAYER M4 ;
        RECT  139.916 74.688 140 74.712 ;
    END
  END vm_wdata[90]
  PIN vm_wdata[91]
    DIRECTION OUTPUT ;
    USE SIGNAL ;
    PORT
      LAYER M4 ;
        RECT  139.916 74.736 140 74.76 ;
    END
  END vm_wdata[91]
  PIN vm_wdata[92]
    DIRECTION OUTPUT ;
    USE SIGNAL ;
    PORT
      LAYER M4 ;
        RECT  139.916 74.784 140 74.808 ;
    END
  END vm_wdata[92]
  PIN vm_wdata[93]
    DIRECTION OUTPUT ;
    USE SIGNAL ;
    PORT
      LAYER M4 ;
        RECT  139.916 74.832 140 74.856 ;
    END
  END vm_wdata[93]
  PIN vm_wdata[94]
    DIRECTION OUTPUT ;
    USE SIGNAL ;
    PORT
      LAYER M4 ;
        RECT  139.916 74.88 140 74.904 ;
    END
  END vm_wdata[94]
  PIN vm_wdata[95]
    DIRECTION OUTPUT ;
    USE SIGNAL ;
    PORT
      LAYER M4 ;
        RECT  139.916 74.928 140 74.952 ;
    END
  END vm_wdata[95]
  PIN vm_wdata[96]
    DIRECTION OUTPUT ;
    USE SIGNAL ;
    PORT
      LAYER M4 ;
        RECT  139.916 74.976 140 75 ;
    END
  END vm_wdata[96]
  PIN vm_wdata[97]
    DIRECTION OUTPUT ;
    USE SIGNAL ;
    PORT
      LAYER M4 ;
        RECT  139.916 75.024 140 75.048 ;
    END
  END vm_wdata[97]
  PIN vm_wdata[98]
    DIRECTION OUTPUT ;
    USE SIGNAL ;
    PORT
      LAYER M4 ;
        RECT  139.916 75.072 140 75.096 ;
    END
  END vm_wdata[98]
  PIN vm_wdata[99]
    DIRECTION OUTPUT ;
    USE SIGNAL ;
    PORT
      LAYER M4 ;
        RECT  139.916 75.12 140 75.144 ;
    END
  END vm_wdata[99]
  PIN vm_wdata[9]
    DIRECTION OUTPUT ;
    USE SIGNAL ;
    PORT
      LAYER M4 ;
        RECT  139.916 70.8 140 70.824 ;
    END
  END vm_wdata[9]
  PIN vm_we
    DIRECTION OUTPUT ;
    USE SIGNAL ;
    PORT
      LAYER M4 ;
        RECT  139.916 94.944 140 94.968 ;
    END
  END vm_we
  PIN VDD
    DIRECTION INOUT ;
    USE POWER ;
    PORT
      LAYER M6 ;
        RECT  1.44 134 138.582 134.288 ;
        RECT  1.44 123.2 138.582 123.488 ;
        RECT  1.44 112.4 138.582 112.688 ;
        RECT  1.44 101.6 138.582 101.888 ;
        RECT  1.44 90.8 138.582 91.088 ;
        RECT  1.44 80 138.582 80.288 ;
        RECT  1.44 69.2 138.582 69.488 ;
        RECT  1.44 58.4 138.582 58.688 ;
        RECT  1.44 47.6 138.582 47.888 ;
        RECT  1.44 36.8 138.582 37.088 ;
        RECT  1.44 26 138.582 26.288 ;
        RECT  1.44 15.2 138.582 15.488 ;
        RECT  1.44 4.4 138.582 4.688 ;
        RECT  1.44 138.654 138.582 138.942 ;
        RECT  1.44 1.188 138.582 1.476 ;
    END
  END VDD
  PIN VSS
    DIRECTION INOUT ;
    USE GROUND ;
    PORT
      LAYER M6 ;
        RECT  1.44 133.616 138.582 133.904 ;
        RECT  1.44 122.816 138.582 123.104 ;
        RECT  1.44 112.016 138.582 112.304 ;
        RECT  1.44 101.216 138.582 101.504 ;
        RECT  1.44 90.416 138.582 90.704 ;
        RECT  1.44 79.616 138.582 79.904 ;
        RECT  1.44 68.816 138.582 69.104 ;
        RECT  1.44 58.016 138.582 58.304 ;
        RECT  1.44 47.216 138.582 47.504 ;
        RECT  1.44 36.416 138.582 36.704 ;
        RECT  1.44 25.616 138.582 25.904 ;
        RECT  1.44 14.816 138.582 15.104 ;
        RECT  1.44 4.016 138.582 4.304 ;
        RECT  1.632 138.27 138.39 138.558 ;
        RECT  1.632 1.572 138.39 1.86 ;
    END
  END VSS
  OBS
    LAYER RVTN ;
     RECT  0 1.188 140 140 ;
    LAYER RVTP ;
     RECT  0 1.188 140 140 ;
    LAYER M1 ;
     RECT  0 1.188 140 140 ;
    LAYER M2 ;
     RECT  0 1.188 140 140 ;
    LAYER M3 ;
     RECT  0 1.188 140 140 ;
    LAYER M4 ;
     RECT  0 1.188 140 140 ;
    LAYER M5 ;
     RECT  0 1.188 140 140 ;
    LAYER M6 ;
     RECT  0 1.188 140 140 ;
  END
END ot_chip_pkg_ctrl
END LIBRARY
